# OpenTallas tools/qwen_missing/phy_plan_pins.py (plan pin sites, QC S4P): ot_qfd_serdes_112g_x12_phy_s597 hard-macro ABSTRACT (licensed PHY IP; FDI side only)
VERSION 5.7 ;
BUSBITCHARS "[]" ;
DIVIDERCHAR "/" ;
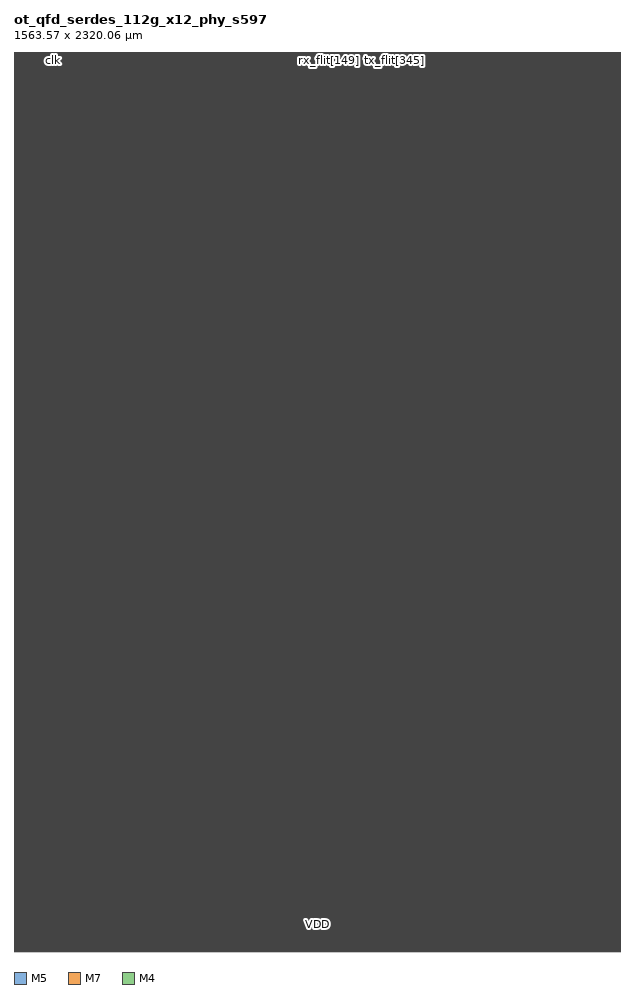
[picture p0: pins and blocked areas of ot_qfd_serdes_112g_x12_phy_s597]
MACRO ot_qfd_serdes_112g_x12_phy_s597
  FOREIGN ot_qfd_serdes_112g_x12_phy_s597 0 0 ;
  SYMMETRY X Y ;
  SIZE 1563.570 BY 2320.056 ;
  CLASS BLOCK ;
  PIN clk
    DIRECTION INPUT ;
    USE CLOCK ;
    SHAPE ABUTMENT ;
    PORT
      LAYER M5 ;
      RECT 99.996 2319.864 100.020 2320.056 ;
    END
  END clk
  PIN rst_n
    DIRECTION INPUT ;
    USE SIGNAL ;
    SHAPE ABUTMENT ;
    PORT
      LAYER M5 ;
      RECT 100.044 2319.864 100.068 2320.056 ;
    END
  END rst_n
  PIN tx_up
    DIRECTION OUTPUT ;
    USE SIGNAL ;
    SHAPE ABUTMENT ;
    PORT
      LAYER M7 ;
      RECT 1034.960 2319.864 1034.992 2320.056 ;
    END
  END tx_up
  PIN tx_v
    DIRECTION INPUT ;
    USE SIGNAL ;
    SHAPE ABUTMENT ;
    PORT
      LAYER M7 ;
      RECT 1036.304 2319.864 1036.336 2320.056 ;
    END
  END tx_v
  PIN tx_flit[0]
    DIRECTION INPUT ;
    USE SIGNAL ;
    SHAPE ABUTMENT ;
    PORT
      LAYER M7 ;
      RECT 909.200 2319.864 909.232 2320.056 ;
    END
  END tx_flit[0]
  PIN tx_flit[1]
    DIRECTION INPUT ;
    USE SIGNAL ;
    SHAPE ABUTMENT ;
    PORT
      LAYER M5 ;
      RECT 909.084 2319.864 909.108 2320.056 ;
    END
  END tx_flit[1]
  PIN tx_flit[2]
    DIRECTION INPUT ;
    USE SIGNAL ;
    SHAPE ABUTMENT ;
    PORT
      LAYER M7 ;
      RECT 909.648 2319.864 909.680 2320.056 ;
    END
  END tx_flit[2]
  PIN tx_flit[3]
    DIRECTION INPUT ;
    USE SIGNAL ;
    SHAPE ABUTMENT ;
    PORT
      LAYER M5 ;
      RECT 909.612 2319.864 909.636 2320.056 ;
    END
  END tx_flit[3]
  PIN tx_flit[4]
    DIRECTION INPUT ;
    USE SIGNAL ;
    SHAPE ABUTMENT ;
    PORT
      LAYER M7 ;
      RECT 910.032 2319.864 910.064 2320.056 ;
    END
  END tx_flit[4]
  PIN tx_flit[5]
    DIRECTION INPUT ;
    USE SIGNAL ;
    SHAPE ABUTMENT ;
    PORT
      LAYER M5 ;
      RECT 910.044 2319.864 910.068 2320.056 ;
    END
  END tx_flit[5]
  PIN tx_flit[6]
    DIRECTION INPUT ;
    USE SIGNAL ;
    SHAPE ABUTMENT ;
    PORT
      LAYER M7 ;
      RECT 910.480 2319.864 910.512 2320.056 ;
    END
  END tx_flit[6]
  PIN tx_flit[7]
    DIRECTION INPUT ;
    USE SIGNAL ;
    SHAPE ABUTMENT ;
    PORT
      LAYER M5 ;
      RECT 910.476 2319.864 910.500 2320.056 ;
    END
  END tx_flit[7]
  PIN tx_flit[8]
    DIRECTION INPUT ;
    USE SIGNAL ;
    SHAPE ABUTMENT ;
    PORT
      LAYER M7 ;
      RECT 910.864 2319.864 910.896 2320.056 ;
    END
  END tx_flit[8]
  PIN tx_flit[9]
    DIRECTION INPUT ;
    USE SIGNAL ;
    SHAPE ABUTMENT ;
    PORT
      LAYER M5 ;
      RECT 910.860 2319.864 910.884 2320.056 ;
    END
  END tx_flit[9]
  PIN tx_flit[10]
    DIRECTION INPUT ;
    USE SIGNAL ;
    SHAPE ABUTMENT ;
    PORT
      LAYER M7 ;
      RECT 910.992 2319.864 911.024 2320.056 ;
    END
  END tx_flit[10]
  PIN tx_flit[11]
    DIRECTION INPUT ;
    USE SIGNAL ;
    SHAPE ABUTMENT ;
    PORT
      LAYER M5 ;
      RECT 911.292 2319.864 911.316 2320.056 ;
    END
  END tx_flit[11]
  PIN tx_flit[12]
    DIRECTION INPUT ;
    USE SIGNAL ;
    SHAPE ABUTMENT ;
    PORT
      LAYER M7 ;
      RECT 912.016 2319.864 912.048 2320.056 ;
    END
  END tx_flit[12]
  PIN tx_flit[13]
    DIRECTION INPUT ;
    USE SIGNAL ;
    SHAPE ABUTMENT ;
    PORT
      LAYER M5 ;
      RECT 911.724 2319.864 911.748 2320.056 ;
    END
  END tx_flit[13]
  PIN tx_flit[14]
    DIRECTION INPUT ;
    USE SIGNAL ;
    SHAPE ABUTMENT ;
    PORT
      LAYER M7 ;
      RECT 912.144 2319.864 912.176 2320.056 ;
    END
  END tx_flit[14]
  PIN tx_flit[15]
    DIRECTION INPUT ;
    USE SIGNAL ;
    SHAPE ABUTMENT ;
    PORT
      LAYER M5 ;
      RECT 912.108 2319.864 912.132 2320.056 ;
    END
  END tx_flit[15]
  PIN tx_flit[16]
    DIRECTION INPUT ;
    USE SIGNAL ;
    SHAPE ABUTMENT ;
    PORT
      LAYER M7 ;
      RECT 912.528 2319.864 912.560 2320.056 ;
    END
  END tx_flit[16]
  PIN tx_flit[17]
    DIRECTION INPUT ;
    USE SIGNAL ;
    SHAPE ABUTMENT ;
    PORT
      LAYER M5 ;
      RECT 912.540 2319.864 912.564 2320.056 ;
    END
  END tx_flit[17]
  PIN tx_flit[18]
    DIRECTION INPUT ;
    USE SIGNAL ;
    SHAPE ABUTMENT ;
    PORT
      LAYER M7 ;
      RECT 912.976 2319.864 913.008 2320.056 ;
    END
  END tx_flit[18]
  PIN tx_flit[19]
    DIRECTION INPUT ;
    USE SIGNAL ;
    SHAPE ABUTMENT ;
    PORT
      LAYER M5 ;
      RECT 912.972 2319.864 912.996 2320.056 ;
    END
  END tx_flit[19]
  PIN tx_flit[20]
    DIRECTION INPUT ;
    USE SIGNAL ;
    SHAPE ABUTMENT ;
    PORT
      LAYER M7 ;
      RECT 913.360 2319.864 913.392 2320.056 ;
    END
  END tx_flit[20]
  PIN tx_flit[21]
    DIRECTION INPUT ;
    USE SIGNAL ;
    SHAPE ABUTMENT ;
    PORT
      LAYER M5 ;
      RECT 913.356 2319.864 913.380 2320.056 ;
    END
  END tx_flit[21]
  PIN tx_flit[22]
    DIRECTION INPUT ;
    USE SIGNAL ;
    SHAPE ABUTMENT ;
    PORT
      LAYER M7 ;
      RECT 913.808 2319.864 913.840 2320.056 ;
    END
  END tx_flit[22]
  PIN tx_flit[23]
    DIRECTION INPUT ;
    USE SIGNAL ;
    SHAPE ABUTMENT ;
    PORT
      LAYER M5 ;
      RECT 913.932 2319.864 913.956 2320.056 ;
    END
  END tx_flit[23]
  PIN tx_flit[24]
    DIRECTION INPUT ;
    USE SIGNAL ;
    SHAPE ABUTMENT ;
    PORT
      LAYER M7 ;
      RECT 914.192 2319.864 914.224 2320.056 ;
    END
  END tx_flit[24]
  PIN tx_flit[25]
    DIRECTION INPUT ;
    USE SIGNAL ;
    SHAPE ABUTMENT ;
    PORT
      LAYER M5 ;
      RECT 914.220 2319.864 914.244 2320.056 ;
    END
  END tx_flit[25]
  PIN tx_flit[26]
    DIRECTION INPUT ;
    USE SIGNAL ;
    SHAPE ABUTMENT ;
    PORT
      LAYER M7 ;
      RECT 914.640 2319.864 914.672 2320.056 ;
    END
  END tx_flit[26]
  PIN tx_flit[27]
    DIRECTION INPUT ;
    USE SIGNAL ;
    SHAPE ABUTMENT ;
    PORT
      LAYER M5 ;
      RECT 914.652 2319.864 914.676 2320.056 ;
    END
  END tx_flit[27]
  PIN tx_flit[28]
    DIRECTION INPUT ;
    USE SIGNAL ;
    SHAPE ABUTMENT ;
    PORT
      LAYER M7 ;
      RECT 915.024 2319.864 915.056 2320.056 ;
    END
  END tx_flit[28]
  PIN tx_flit[29]
    DIRECTION INPUT ;
    USE SIGNAL ;
    SHAPE ABUTMENT ;
    PORT
      LAYER M5 ;
      RECT 915.036 2319.864 915.060 2320.056 ;
    END
  END tx_flit[29]
  PIN tx_flit[30]
    DIRECTION INPUT ;
    USE SIGNAL ;
    SHAPE ABUTMENT ;
    PORT
      LAYER M7 ;
      RECT 915.472 2319.864 915.504 2320.056 ;
    END
  END tx_flit[30]
  PIN tx_flit[31]
    DIRECTION INPUT ;
    USE SIGNAL ;
    SHAPE ABUTMENT ;
    PORT
      LAYER M5 ;
      RECT 915.468 2319.864 915.492 2320.056 ;
    END
  END tx_flit[31]
  PIN tx_flit[32]
    DIRECTION INPUT ;
    USE SIGNAL ;
    SHAPE ABUTMENT ;
    PORT
      LAYER M7 ;
      RECT 915.856 2319.864 915.888 2320.056 ;
    END
  END tx_flit[32]
  PIN tx_flit[33]
    DIRECTION INPUT ;
    USE SIGNAL ;
    SHAPE ABUTMENT ;
    PORT
      LAYER M5 ;
      RECT 915.900 2319.864 915.924 2320.056 ;
    END
  END tx_flit[33]
  PIN tx_flit[34]
    DIRECTION INPUT ;
    USE SIGNAL ;
    SHAPE ABUTMENT ;
    PORT
      LAYER M7 ;
      RECT 916.304 2319.864 916.336 2320.056 ;
    END
  END tx_flit[34]
  PIN tx_flit[35]
    DIRECTION INPUT ;
    USE SIGNAL ;
    SHAPE ABUTMENT ;
    PORT
      LAYER M5 ;
      RECT 916.284 2319.864 916.308 2320.056 ;
    END
  END tx_flit[35]
  PIN tx_flit[36]
    DIRECTION INPUT ;
    USE SIGNAL ;
    SHAPE ABUTMENT ;
    PORT
      LAYER M7 ;
      RECT 916.688 2319.864 916.720 2320.056 ;
    END
  END tx_flit[36]
  PIN tx_flit[37]
    DIRECTION INPUT ;
    USE SIGNAL ;
    SHAPE ABUTMENT ;
    PORT
      LAYER M5 ;
      RECT 916.716 2319.864 916.740 2320.056 ;
    END
  END tx_flit[37]
  PIN tx_flit[38]
    DIRECTION INPUT ;
    USE SIGNAL ;
    SHAPE ABUTMENT ;
    PORT
      LAYER M7 ;
      RECT 917.136 2319.864 917.168 2320.056 ;
    END
  END tx_flit[38]
  PIN tx_flit[39]
    DIRECTION INPUT ;
    USE SIGNAL ;
    SHAPE ABUTMENT ;
    PORT
      LAYER M5 ;
      RECT 917.148 2319.864 917.172 2320.056 ;
    END
  END tx_flit[39]
  PIN tx_flit[40]
    DIRECTION INPUT ;
    USE SIGNAL ;
    SHAPE ABUTMENT ;
    PORT
      LAYER M7 ;
      RECT 917.520 2319.864 917.552 2320.056 ;
    END
  END tx_flit[40]
  PIN tx_flit[41]
    DIRECTION INPUT ;
    USE SIGNAL ;
    SHAPE ABUTMENT ;
    PORT
      LAYER M5 ;
      RECT 917.532 2319.864 917.556 2320.056 ;
    END
  END tx_flit[41]
  PIN tx_flit[42]
    DIRECTION INPUT ;
    USE SIGNAL ;
    SHAPE ABUTMENT ;
    PORT
      LAYER M7 ;
      RECT 917.968 2319.864 918.000 2320.056 ;
    END
  END tx_flit[42]
  PIN tx_flit[43]
    DIRECTION INPUT ;
    USE SIGNAL ;
    SHAPE ABUTMENT ;
    PORT
      LAYER M5 ;
      RECT 917.724 2319.864 917.748 2320.056 ;
    END
  END tx_flit[43]
  PIN tx_flit[44]
    DIRECTION INPUT ;
    USE SIGNAL ;
    SHAPE ABUTMENT ;
    PORT
      LAYER M7 ;
      RECT 918.352 2319.864 918.384 2320.056 ;
    END
  END tx_flit[44]
  PIN tx_flit[45]
    DIRECTION INPUT ;
    USE SIGNAL ;
    SHAPE ABUTMENT ;
    PORT
      LAYER M5 ;
      RECT 918.396 2319.864 918.420 2320.056 ;
    END
  END tx_flit[45]
  PIN tx_flit[46]
    DIRECTION INPUT ;
    USE SIGNAL ;
    SHAPE ABUTMENT ;
    PORT
      LAYER M7 ;
      RECT 918.800 2319.864 918.832 2320.056 ;
    END
  END tx_flit[46]
  PIN tx_flit[47]
    DIRECTION INPUT ;
    USE SIGNAL ;
    SHAPE ABUTMENT ;
    PORT
      LAYER M5 ;
      RECT 918.780 2319.864 918.804 2320.056 ;
    END
  END tx_flit[47]
  PIN tx_flit[48]
    DIRECTION INPUT ;
    USE SIGNAL ;
    SHAPE ABUTMENT ;
    PORT
      LAYER M7 ;
      RECT 919.248 2319.864 919.280 2320.056 ;
    END
  END tx_flit[48]
  PIN tx_flit[49]
    DIRECTION INPUT ;
    USE SIGNAL ;
    SHAPE ABUTMENT ;
    PORT
      LAYER M5 ;
      RECT 919.212 2319.864 919.236 2320.056 ;
    END
  END tx_flit[49]
  PIN tx_flit[50]
    DIRECTION INPUT ;
    USE SIGNAL ;
    SHAPE ABUTMENT ;
    PORT
      LAYER M7 ;
      RECT 919.632 2319.864 919.664 2320.056 ;
    END
  END tx_flit[50]
  PIN tx_flit[51]
    DIRECTION INPUT ;
    USE SIGNAL ;
    SHAPE ABUTMENT ;
    PORT
      LAYER M5 ;
      RECT 919.644 2319.864 919.668 2320.056 ;
    END
  END tx_flit[51]
  PIN tx_flit[52]
    DIRECTION INPUT ;
    USE SIGNAL ;
    SHAPE ABUTMENT ;
    PORT
      LAYER M7 ;
      RECT 920.656 2319.864 920.688 2320.056 ;
    END
  END tx_flit[52]
  PIN tx_flit[53]
    DIRECTION INPUT ;
    USE SIGNAL ;
    SHAPE ABUTMENT ;
    PORT
      LAYER M5 ;
      RECT 920.076 2319.864 920.100 2320.056 ;
    END
  END tx_flit[53]
  PIN tx_flit[54]
    DIRECTION INPUT ;
    USE SIGNAL ;
    SHAPE ABUTMENT ;
    PORT
      LAYER M7 ;
      RECT 920.720 2319.864 920.752 2320.056 ;
    END
  END tx_flit[54]
  PIN tx_flit[55]
    DIRECTION INPUT ;
    USE SIGNAL ;
    SHAPE ABUTMENT ;
    PORT
      LAYER M5 ;
      RECT 920.460 2319.864 920.484 2320.056 ;
    END
  END tx_flit[55]
  PIN tx_flit[56]
    DIRECTION INPUT ;
    USE SIGNAL ;
    SHAPE ABUTMENT ;
    PORT
      LAYER M7 ;
      RECT 920.912 2319.864 920.944 2320.056 ;
    END
  END tx_flit[56]
  PIN tx_flit[57]
    DIRECTION INPUT ;
    USE SIGNAL ;
    SHAPE ABUTMENT ;
    PORT
      LAYER M5 ;
      RECT 920.892 2319.864 920.916 2320.056 ;
    END
  END tx_flit[57]
  PIN tx_flit[58]
    DIRECTION INPUT ;
    USE SIGNAL ;
    SHAPE ABUTMENT ;
    PORT
      LAYER M7 ;
      RECT 921.296 2319.864 921.328 2320.056 ;
    END
  END tx_flit[58]
  PIN tx_flit[59]
    DIRECTION INPUT ;
    USE SIGNAL ;
    SHAPE ABUTMENT ;
    PORT
      LAYER M5 ;
      RECT 921.324 2319.864 921.348 2320.056 ;
    END
  END tx_flit[59]
  PIN tx_flit[60]
    DIRECTION INPUT ;
    USE SIGNAL ;
    SHAPE ABUTMENT ;
    PORT
      LAYER M7 ;
      RECT 921.744 2319.864 921.776 2320.056 ;
    END
  END tx_flit[60]
  PIN tx_flit[61]
    DIRECTION INPUT ;
    USE SIGNAL ;
    SHAPE ABUTMENT ;
    PORT
      LAYER M5 ;
      RECT 921.708 2319.864 921.732 2320.056 ;
    END
  END tx_flit[61]
  PIN tx_flit[62]
    DIRECTION INPUT ;
    USE SIGNAL ;
    SHAPE ABUTMENT ;
    PORT
      LAYER M7 ;
      RECT 922.128 2319.864 922.160 2320.056 ;
    END
  END tx_flit[62]
  PIN tx_flit[63]
    DIRECTION INPUT ;
    USE SIGNAL ;
    SHAPE ABUTMENT ;
    PORT
      LAYER M5 ;
      RECT 922.044 2319.864 922.068 2320.056 ;
    END
  END tx_flit[63]
  PIN tx_flit[64]
    DIRECTION INPUT ;
    USE SIGNAL ;
    SHAPE ABUTMENT ;
    PORT
      LAYER M7 ;
      RECT 922.576 2319.864 922.608 2320.056 ;
    END
  END tx_flit[64]
  PIN tx_flit[65]
    DIRECTION INPUT ;
    USE SIGNAL ;
    SHAPE ABUTMENT ;
    PORT
      LAYER M5 ;
      RECT 922.572 2319.864 922.596 2320.056 ;
    END
  END tx_flit[65]
  PIN tx_flit[66]
    DIRECTION INPUT ;
    USE SIGNAL ;
    SHAPE ABUTMENT ;
    PORT
      LAYER M7 ;
      RECT 922.960 2319.864 922.992 2320.056 ;
    END
  END tx_flit[66]
  PIN tx_flit[67]
    DIRECTION INPUT ;
    USE SIGNAL ;
    SHAPE ABUTMENT ;
    PORT
      LAYER M5 ;
      RECT 922.956 2319.864 922.980 2320.056 ;
    END
  END tx_flit[67]
  PIN tx_flit[68]
    DIRECTION INPUT ;
    USE SIGNAL ;
    SHAPE ABUTMENT ;
    PORT
      LAYER M7 ;
      RECT 923.408 2319.864 923.440 2320.056 ;
    END
  END tx_flit[68]
  PIN tx_flit[69]
    DIRECTION INPUT ;
    USE SIGNAL ;
    SHAPE ABUTMENT ;
    PORT
      LAYER M5 ;
      RECT 923.388 2319.864 923.412 2320.056 ;
    END
  END tx_flit[69]
  PIN tx_flit[70]
    DIRECTION INPUT ;
    USE SIGNAL ;
    SHAPE ABUTMENT ;
    PORT
      LAYER M7 ;
      RECT 923.792 2319.864 923.824 2320.056 ;
    END
  END tx_flit[70]
  PIN tx_flit[71]
    DIRECTION INPUT ;
    USE SIGNAL ;
    SHAPE ABUTMENT ;
    PORT
      LAYER M5 ;
      RECT 923.820 2319.864 923.844 2320.056 ;
    END
  END tx_flit[71]
  PIN tx_flit[72]
    DIRECTION INPUT ;
    USE SIGNAL ;
    SHAPE ABUTMENT ;
    PORT
      LAYER M7 ;
      RECT 924.240 2319.864 924.272 2320.056 ;
    END
  END tx_flit[72]
  PIN tx_flit[73]
    DIRECTION INPUT ;
    USE SIGNAL ;
    SHAPE ABUTMENT ;
    PORT
      LAYER M5 ;
      RECT 924.252 2319.864 924.276 2320.056 ;
    END
  END tx_flit[73]
  PIN tx_flit[74]
    DIRECTION INPUT ;
    USE SIGNAL ;
    SHAPE ABUTMENT ;
    PORT
      LAYER M7 ;
      RECT 924.624 2319.864 924.656 2320.056 ;
    END
  END tx_flit[74]
  PIN tx_flit[75]
    DIRECTION INPUT ;
    USE SIGNAL ;
    SHAPE ABUTMENT ;
    PORT
      LAYER M5 ;
      RECT 924.636 2319.864 924.660 2320.056 ;
    END
  END tx_flit[75]
  PIN tx_flit[76]
    DIRECTION INPUT ;
    USE SIGNAL ;
    SHAPE ABUTMENT ;
    PORT
      LAYER M7 ;
      RECT 925.072 2319.864 925.104 2320.056 ;
    END
  END tx_flit[76]
  PIN tx_flit[77]
    DIRECTION INPUT ;
    USE SIGNAL ;
    SHAPE ABUTMENT ;
    PORT
      LAYER M5 ;
      RECT 925.068 2319.864 925.092 2320.056 ;
    END
  END tx_flit[77]
  PIN tx_flit[78]
    DIRECTION INPUT ;
    USE SIGNAL ;
    SHAPE ABUTMENT ;
    PORT
      LAYER M7 ;
      RECT 925.456 2319.864 925.488 2320.056 ;
    END
  END tx_flit[78]
  PIN tx_flit[79]
    DIRECTION INPUT ;
    USE SIGNAL ;
    SHAPE ABUTMENT ;
    PORT
      LAYER M5 ;
      RECT 925.500 2319.864 925.524 2320.056 ;
    END
  END tx_flit[79]
  PIN tx_flit[80]
    DIRECTION INPUT ;
    USE SIGNAL ;
    SHAPE ABUTMENT ;
    PORT
      LAYER M7 ;
      RECT 925.904 2319.864 925.936 2320.056 ;
    END
  END tx_flit[80]
  PIN tx_flit[81]
    DIRECTION INPUT ;
    USE SIGNAL ;
    SHAPE ABUTMENT ;
    PORT
      LAYER M5 ;
      RECT 925.884 2319.864 925.908 2320.056 ;
    END
  END tx_flit[81]
  PIN tx_flit[82]
    DIRECTION INPUT ;
    USE SIGNAL ;
    SHAPE ABUTMENT ;
    PORT
      LAYER M7 ;
      RECT 926.288 2319.864 926.320 2320.056 ;
    END
  END tx_flit[82]
  PIN tx_flit[83]
    DIRECTION INPUT ;
    USE SIGNAL ;
    SHAPE ABUTMENT ;
    PORT
      LAYER M5 ;
      RECT 926.316 2319.864 926.340 2320.056 ;
    END
  END tx_flit[83]
  PIN tx_flit[84]
    DIRECTION INPUT ;
    USE SIGNAL ;
    SHAPE ABUTMENT ;
    PORT
      LAYER M7 ;
      RECT 926.736 2319.864 926.768 2320.056 ;
    END
  END tx_flit[84]
  PIN tx_flit[85]
    DIRECTION INPUT ;
    USE SIGNAL ;
    SHAPE ABUTMENT ;
    PORT
      LAYER M5 ;
      RECT 926.892 2319.864 926.916 2320.056 ;
    END
  END tx_flit[85]
  PIN tx_flit[86]
    DIRECTION INPUT ;
    USE SIGNAL ;
    SHAPE ABUTMENT ;
    PORT
      LAYER M7 ;
      RECT 927.120 2319.864 927.152 2320.056 ;
    END
  END tx_flit[86]
  PIN tx_flit[87]
    DIRECTION INPUT ;
    USE SIGNAL ;
    SHAPE ABUTMENT ;
    PORT
      LAYER M5 ;
      RECT 927.132 2319.864 927.156 2320.056 ;
    END
  END tx_flit[87]
  PIN tx_flit[88]
    DIRECTION INPUT ;
    USE SIGNAL ;
    SHAPE ABUTMENT ;
    PORT
      LAYER M7 ;
      RECT 927.568 2319.864 927.600 2320.056 ;
    END
  END tx_flit[88]
  PIN tx_flit[89]
    DIRECTION INPUT ;
    USE SIGNAL ;
    SHAPE ABUTMENT ;
    PORT
      LAYER M5 ;
      RECT 927.564 2319.864 927.588 2320.056 ;
    END
  END tx_flit[89]
  PIN tx_flit[90]
    DIRECTION INPUT ;
    USE SIGNAL ;
    SHAPE ABUTMENT ;
    PORT
      LAYER M7 ;
      RECT 927.952 2319.864 927.984 2320.056 ;
    END
  END tx_flit[90]
  PIN tx_flit[91]
    DIRECTION INPUT ;
    USE SIGNAL ;
    SHAPE ABUTMENT ;
    PORT
      LAYER M5 ;
      RECT 927.996 2319.864 928.020 2320.056 ;
    END
  END tx_flit[91]
  PIN tx_flit[92]
    DIRECTION INPUT ;
    USE SIGNAL ;
    SHAPE ABUTMENT ;
    PORT
      LAYER M7 ;
      RECT 928.272 2319.864 928.304 2320.056 ;
    END
  END tx_flit[92]
  PIN tx_flit[93]
    DIRECTION INPUT ;
    USE SIGNAL ;
    SHAPE ABUTMENT ;
    PORT
      LAYER M5 ;
      RECT 928.380 2319.864 928.404 2320.056 ;
    END
  END tx_flit[93]
  PIN tx_flit[94]
    DIRECTION INPUT ;
    USE SIGNAL ;
    SHAPE ABUTMENT ;
    PORT
      LAYER M7 ;
      RECT 929.296 2319.864 929.328 2320.056 ;
    END
  END tx_flit[94]
  PIN tx_flit[95]
    DIRECTION INPUT ;
    USE SIGNAL ;
    SHAPE ABUTMENT ;
    PORT
      LAYER M5 ;
      RECT 928.812 2319.864 928.836 2320.056 ;
    END
  END tx_flit[95]
  PIN tx_flit[96]
    DIRECTION INPUT ;
    USE SIGNAL ;
    SHAPE ABUTMENT ;
    PORT
      LAYER M7 ;
      RECT 929.360 2319.864 929.392 2320.056 ;
    END
  END tx_flit[96]
  PIN tx_flit[97]
    DIRECTION INPUT ;
    USE SIGNAL ;
    SHAPE ABUTMENT ;
    PORT
      LAYER M5 ;
      RECT 929.244 2319.864 929.268 2320.056 ;
    END
  END tx_flit[97]
  PIN tx_flit[98]
    DIRECTION INPUT ;
    USE SIGNAL ;
    SHAPE ABUTMENT ;
    PORT
      LAYER M7 ;
      RECT 929.680 2319.864 929.712 2320.056 ;
    END
  END tx_flit[98]
  PIN tx_flit[99]
    DIRECTION INPUT ;
    USE SIGNAL ;
    SHAPE ABUTMENT ;
    PORT
      LAYER M5 ;
      RECT 929.676 2319.864 929.700 2320.056 ;
    END
  END tx_flit[99]
  PIN tx_flit[100]
    DIRECTION INPUT ;
    USE SIGNAL ;
    SHAPE ABUTMENT ;
    PORT
      LAYER M7 ;
      RECT 930.064 2319.864 930.096 2320.056 ;
    END
  END tx_flit[100]
  PIN tx_flit[101]
    DIRECTION INPUT ;
    USE SIGNAL ;
    SHAPE ABUTMENT ;
    PORT
      LAYER M5 ;
      RECT 930.060 2319.864 930.084 2320.056 ;
    END
  END tx_flit[101]
  PIN tx_flit[102]
    DIRECTION INPUT ;
    USE SIGNAL ;
    SHAPE ABUTMENT ;
    PORT
      LAYER M7 ;
      RECT 930.512 2319.864 930.544 2320.056 ;
    END
  END tx_flit[102]
  PIN tx_flit[103]
    DIRECTION INPUT ;
    USE SIGNAL ;
    SHAPE ABUTMENT ;
    PORT
      LAYER M5 ;
      RECT 930.492 2319.864 930.516 2320.056 ;
    END
  END tx_flit[103]
  PIN tx_flit[104]
    DIRECTION INPUT ;
    USE SIGNAL ;
    SHAPE ABUTMENT ;
    PORT
      LAYER M7 ;
      RECT 930.896 2319.864 930.928 2320.056 ;
    END
  END tx_flit[104]
  PIN tx_flit[105]
    DIRECTION INPUT ;
    USE SIGNAL ;
    SHAPE ABUTMENT ;
    PORT
      LAYER M5 ;
      RECT 930.684 2319.864 930.708 2320.056 ;
    END
  END tx_flit[105]
  PIN tx_flit[106]
    DIRECTION INPUT ;
    USE SIGNAL ;
    SHAPE ABUTMENT ;
    PORT
      LAYER M7 ;
      RECT 931.344 2319.864 931.376 2320.056 ;
    END
  END tx_flit[106]
  PIN tx_flit[107]
    DIRECTION INPUT ;
    USE SIGNAL ;
    SHAPE ABUTMENT ;
    PORT
      LAYER M5 ;
      RECT 931.308 2319.864 931.332 2320.056 ;
    END
  END tx_flit[107]
  PIN tx_flit[108]
    DIRECTION INPUT ;
    USE SIGNAL ;
    SHAPE ABUTMENT ;
    PORT
      LAYER M7 ;
      RECT 931.728 2319.864 931.760 2320.056 ;
    END
  END tx_flit[108]
  PIN tx_flit[109]
    DIRECTION INPUT ;
    USE SIGNAL ;
    SHAPE ABUTMENT ;
    PORT
      LAYER M5 ;
      RECT 931.740 2319.864 931.764 2320.056 ;
    END
  END tx_flit[109]
  PIN tx_flit[110]
    DIRECTION INPUT ;
    USE SIGNAL ;
    SHAPE ABUTMENT ;
    PORT
      LAYER M7 ;
      RECT 932.176 2319.864 932.208 2320.056 ;
    END
  END tx_flit[110]
  PIN tx_flit[111]
    DIRECTION INPUT ;
    USE SIGNAL ;
    SHAPE ABUTMENT ;
    PORT
      LAYER M5 ;
      RECT 932.172 2319.864 932.196 2320.056 ;
    END
  END tx_flit[111]
  PIN tx_flit[112]
    DIRECTION INPUT ;
    USE SIGNAL ;
    SHAPE ABUTMENT ;
    PORT
      LAYER M7 ;
      RECT 932.560 2319.864 932.592 2320.056 ;
    END
  END tx_flit[112]
  PIN tx_flit[113]
    DIRECTION INPUT ;
    USE SIGNAL ;
    SHAPE ABUTMENT ;
    PORT
      LAYER M5 ;
      RECT 932.556 2319.864 932.580 2320.056 ;
    END
  END tx_flit[113]
  PIN tx_flit[114]
    DIRECTION INPUT ;
    USE SIGNAL ;
    SHAPE ABUTMENT ;
    PORT
      LAYER M7 ;
      RECT 933.008 2319.864 933.040 2320.056 ;
    END
  END tx_flit[114]
  PIN tx_flit[115]
    DIRECTION INPUT ;
    USE SIGNAL ;
    SHAPE ABUTMENT ;
    PORT
      LAYER M5 ;
      RECT 932.988 2319.864 933.012 2320.056 ;
    END
  END tx_flit[115]
  PIN tx_flit[116]
    DIRECTION INPUT ;
    USE SIGNAL ;
    SHAPE ABUTMENT ;
    PORT
      LAYER M7 ;
      RECT 933.392 2319.864 933.424 2320.056 ;
    END
  END tx_flit[116]
  PIN tx_flit[117]
    DIRECTION INPUT ;
    USE SIGNAL ;
    SHAPE ABUTMENT ;
    PORT
      LAYER M5 ;
      RECT 933.420 2319.864 933.444 2320.056 ;
    END
  END tx_flit[117]
  PIN tx_flit[118]
    DIRECTION INPUT ;
    USE SIGNAL ;
    SHAPE ABUTMENT ;
    PORT
      LAYER M7 ;
      RECT 933.840 2319.864 933.872 2320.056 ;
    END
  END tx_flit[118]
  PIN tx_flit[119]
    DIRECTION INPUT ;
    USE SIGNAL ;
    SHAPE ABUTMENT ;
    PORT
      LAYER M5 ;
      RECT 933.804 2319.864 933.828 2320.056 ;
    END
  END tx_flit[119]
  PIN tx_flit[120]
    DIRECTION INPUT ;
    USE SIGNAL ;
    SHAPE ABUTMENT ;
    PORT
      LAYER M7 ;
      RECT 934.224 2319.864 934.256 2320.056 ;
    END
  END tx_flit[120]
  PIN tx_flit[121]
    DIRECTION INPUT ;
    USE SIGNAL ;
    SHAPE ABUTMENT ;
    PORT
      LAYER M5 ;
      RECT 934.236 2319.864 934.260 2320.056 ;
    END
  END tx_flit[121]
  PIN tx_flit[122]
    DIRECTION INPUT ;
    USE SIGNAL ;
    SHAPE ABUTMENT ;
    PORT
      LAYER M7 ;
      RECT 934.672 2319.864 934.704 2320.056 ;
    END
  END tx_flit[122]
  PIN tx_flit[123]
    DIRECTION INPUT ;
    USE SIGNAL ;
    SHAPE ABUTMENT ;
    PORT
      LAYER M5 ;
      RECT 934.668 2319.864 934.692 2320.056 ;
    END
  END tx_flit[123]
  PIN tx_flit[124]
    DIRECTION INPUT ;
    USE SIGNAL ;
    SHAPE ABUTMENT ;
    PORT
      LAYER M7 ;
      RECT 935.056 2319.864 935.088 2320.056 ;
    END
  END tx_flit[124]
  PIN tx_flit[125]
    DIRECTION INPUT ;
    USE SIGNAL ;
    SHAPE ABUTMENT ;
    PORT
      LAYER M5 ;
      RECT 935.004 2319.864 935.028 2320.056 ;
    END
  END tx_flit[125]
  PIN tx_flit[126]
    DIRECTION INPUT ;
    USE SIGNAL ;
    SHAPE ABUTMENT ;
    PORT
      LAYER M7 ;
      RECT 935.504 2319.864 935.536 2320.056 ;
    END
  END tx_flit[126]
  PIN tx_flit[127]
    DIRECTION INPUT ;
    USE SIGNAL ;
    SHAPE ABUTMENT ;
    PORT
      LAYER M5 ;
      RECT 935.532 2319.864 935.556 2320.056 ;
    END
  END tx_flit[127]
  PIN tx_flit[128]
    DIRECTION INPUT ;
    USE SIGNAL ;
    SHAPE ABUTMENT ;
    PORT
      LAYER M7 ;
      RECT 935.888 2319.864 935.920 2320.056 ;
    END
  END tx_flit[128]
  PIN tx_flit[129]
    DIRECTION INPUT ;
    USE SIGNAL ;
    SHAPE ABUTMENT ;
    PORT
      LAYER M5 ;
      RECT 935.916 2319.864 935.940 2320.056 ;
    END
  END tx_flit[129]
  PIN tx_flit[130]
    DIRECTION INPUT ;
    USE SIGNAL ;
    SHAPE ABUTMENT ;
    PORT
      LAYER M7 ;
      RECT 936.336 2319.864 936.368 2320.056 ;
    END
  END tx_flit[130]
  PIN tx_flit[131]
    DIRECTION INPUT ;
    USE SIGNAL ;
    SHAPE ABUTMENT ;
    PORT
      LAYER M5 ;
      RECT 936.348 2319.864 936.372 2320.056 ;
    END
  END tx_flit[131]
  PIN tx_flit[132]
    DIRECTION INPUT ;
    USE SIGNAL ;
    SHAPE ABUTMENT ;
    PORT
      LAYER M7 ;
      RECT 936.720 2319.864 936.752 2320.056 ;
    END
  END tx_flit[132]
  PIN tx_flit[133]
    DIRECTION INPUT ;
    USE SIGNAL ;
    SHAPE ABUTMENT ;
    PORT
      LAYER M5 ;
      RECT 936.732 2319.864 936.756 2320.056 ;
    END
  END tx_flit[133]
  PIN tx_flit[134]
    DIRECTION INPUT ;
    USE SIGNAL ;
    SHAPE ABUTMENT ;
    PORT
      LAYER M7 ;
      RECT 936.912 2319.864 936.944 2320.056 ;
    END
  END tx_flit[134]
  PIN tx_flit[135]
    DIRECTION INPUT ;
    USE SIGNAL ;
    SHAPE ABUTMENT ;
    PORT
      LAYER M5 ;
      RECT 937.164 2319.864 937.188 2320.056 ;
    END
  END tx_flit[135]
  PIN tx_flit[136]
    DIRECTION INPUT ;
    USE SIGNAL ;
    SHAPE ABUTMENT ;
    PORT
      LAYER M7 ;
      RECT 937.936 2319.864 937.968 2320.056 ;
    END
  END tx_flit[136]
  PIN tx_flit[137]
    DIRECTION INPUT ;
    USE SIGNAL ;
    SHAPE ABUTMENT ;
    PORT
      LAYER M5 ;
      RECT 937.596 2319.864 937.620 2320.056 ;
    END
  END tx_flit[137]
  PIN tx_flit[138]
    DIRECTION INPUT ;
    USE SIGNAL ;
    SHAPE ABUTMENT ;
    PORT
      LAYER M7 ;
      RECT 938.000 2319.864 938.032 2320.056 ;
    END
  END tx_flit[138]
  PIN tx_flit[139]
    DIRECTION INPUT ;
    USE SIGNAL ;
    SHAPE ABUTMENT ;
    PORT
      LAYER M5 ;
      RECT 937.980 2319.864 938.004 2320.056 ;
    END
  END tx_flit[139]
  PIN tx_flit[140]
    DIRECTION INPUT ;
    USE SIGNAL ;
    SHAPE ABUTMENT ;
    PORT
      LAYER M7 ;
      RECT 938.384 2319.864 938.416 2320.056 ;
    END
  END tx_flit[140]
  PIN tx_flit[141]
    DIRECTION INPUT ;
    USE SIGNAL ;
    SHAPE ABUTMENT ;
    PORT
      LAYER M5 ;
      RECT 938.412 2319.864 938.436 2320.056 ;
    END
  END tx_flit[141]
  PIN tx_flit[142]
    DIRECTION INPUT ;
    USE SIGNAL ;
    SHAPE ABUTMENT ;
    PORT
      LAYER M7 ;
      RECT 938.832 2319.864 938.864 2320.056 ;
    END
  END tx_flit[142]
  PIN tx_flit[143]
    DIRECTION INPUT ;
    USE SIGNAL ;
    SHAPE ABUTMENT ;
    PORT
      LAYER M5 ;
      RECT 938.844 2319.864 938.868 2320.056 ;
    END
  END tx_flit[143]
  PIN tx_flit[144]
    DIRECTION INPUT ;
    USE SIGNAL ;
    SHAPE ABUTMENT ;
    PORT
      LAYER M7 ;
      RECT 939.280 2319.864 939.312 2320.056 ;
    END
  END tx_flit[144]
  PIN tx_flit[145]
    DIRECTION INPUT ;
    USE SIGNAL ;
    SHAPE ABUTMENT ;
    PORT
      LAYER M5 ;
      RECT 939.276 2319.864 939.300 2320.056 ;
    END
  END tx_flit[145]
  PIN tx_flit[146]
    DIRECTION INPUT ;
    USE SIGNAL ;
    SHAPE ABUTMENT ;
    PORT
      LAYER M7 ;
      RECT 939.664 2319.864 939.696 2320.056 ;
    END
  END tx_flit[146]
  PIN tx_flit[147]
    DIRECTION INPUT ;
    USE SIGNAL ;
    SHAPE ABUTMENT ;
    PORT
      LAYER M5 ;
      RECT 939.852 2319.864 939.876 2320.056 ;
    END
  END tx_flit[147]
  PIN tx_flit[148]
    DIRECTION INPUT ;
    USE SIGNAL ;
    SHAPE ABUTMENT ;
    PORT
      LAYER M7 ;
      RECT 940.112 2319.864 940.144 2320.056 ;
    END
  END tx_flit[148]
  PIN tx_flit[149]
    DIRECTION INPUT ;
    USE SIGNAL ;
    SHAPE ABUTMENT ;
    PORT
      LAYER M5 ;
      RECT 940.092 2319.864 940.116 2320.056 ;
    END
  END tx_flit[149]
  PIN tx_flit[150]
    DIRECTION INPUT ;
    USE SIGNAL ;
    SHAPE ABUTMENT ;
    PORT
      LAYER M7 ;
      RECT 940.496 2319.864 940.528 2320.056 ;
    END
  END tx_flit[150]
  PIN tx_flit[151]
    DIRECTION INPUT ;
    USE SIGNAL ;
    SHAPE ABUTMENT ;
    PORT
      LAYER M5 ;
      RECT 940.524 2319.864 940.548 2320.056 ;
    END
  END tx_flit[151]
  PIN tx_flit[152]
    DIRECTION INPUT ;
    USE SIGNAL ;
    SHAPE ABUTMENT ;
    PORT
      LAYER M7 ;
      RECT 940.944 2319.864 940.976 2320.056 ;
    END
  END tx_flit[152]
  PIN tx_flit[153]
    DIRECTION INPUT ;
    USE SIGNAL ;
    SHAPE ABUTMENT ;
    PORT
      LAYER M5 ;
      RECT 940.908 2319.864 940.932 2320.056 ;
    END
  END tx_flit[153]
  PIN tx_flit[154]
    DIRECTION INPUT ;
    USE SIGNAL ;
    SHAPE ABUTMENT ;
    PORT
      LAYER M7 ;
      RECT 941.328 2319.864 941.360 2320.056 ;
    END
  END tx_flit[154]
  PIN tx_flit[155]
    DIRECTION INPUT ;
    USE SIGNAL ;
    SHAPE ABUTMENT ;
    PORT
      LAYER M5 ;
      RECT 941.340 2319.864 941.364 2320.056 ;
    END
  END tx_flit[155]
  PIN tx_flit[156]
    DIRECTION INPUT ;
    USE SIGNAL ;
    SHAPE ABUTMENT ;
    PORT
      LAYER M7 ;
      RECT 941.776 2319.864 941.808 2320.056 ;
    END
  END tx_flit[156]
  PIN tx_flit[157]
    DIRECTION INPUT ;
    USE SIGNAL ;
    SHAPE ABUTMENT ;
    PORT
      LAYER M5 ;
      RECT 941.772 2319.864 941.796 2320.056 ;
    END
  END tx_flit[157]
  PIN tx_flit[158]
    DIRECTION INPUT ;
    USE SIGNAL ;
    SHAPE ABUTMENT ;
    PORT
      LAYER M7 ;
      RECT 942.160 2319.864 942.192 2320.056 ;
    END
  END tx_flit[158]
  PIN tx_flit[159]
    DIRECTION INPUT ;
    USE SIGNAL ;
    SHAPE ABUTMENT ;
    PORT
      LAYER M5 ;
      RECT 942.156 2319.864 942.180 2320.056 ;
    END
  END tx_flit[159]
  PIN tx_flit[160]
    DIRECTION INPUT ;
    USE SIGNAL ;
    SHAPE ABUTMENT ;
    PORT
      LAYER M7 ;
      RECT 942.608 2319.864 942.640 2320.056 ;
    END
  END tx_flit[160]
  PIN tx_flit[161]
    DIRECTION INPUT ;
    USE SIGNAL ;
    SHAPE ABUTMENT ;
    PORT
      LAYER M5 ;
      RECT 942.588 2319.864 942.612 2320.056 ;
    END
  END tx_flit[161]
  PIN tx_flit[162]
    DIRECTION INPUT ;
    USE SIGNAL ;
    SHAPE ABUTMENT ;
    PORT
      LAYER M7 ;
      RECT 942.992 2319.864 943.024 2320.056 ;
    END
  END tx_flit[162]
  PIN tx_flit[163]
    DIRECTION INPUT ;
    USE SIGNAL ;
    SHAPE ABUTMENT ;
    PORT
      LAYER M5 ;
      RECT 943.020 2319.864 943.044 2320.056 ;
    END
  END tx_flit[163]
  PIN tx_flit[164]
    DIRECTION INPUT ;
    USE SIGNAL ;
    SHAPE ABUTMENT ;
    PORT
      LAYER M7 ;
      RECT 943.440 2319.864 943.472 2320.056 ;
    END
  END tx_flit[164]
  PIN tx_flit[165]
    DIRECTION INPUT ;
    USE SIGNAL ;
    SHAPE ABUTMENT ;
    PORT
      LAYER M5 ;
      RECT 943.404 2319.864 943.428 2320.056 ;
    END
  END tx_flit[165]
  PIN tx_flit[166]
    DIRECTION INPUT ;
    USE SIGNAL ;
    SHAPE ABUTMENT ;
    PORT
      LAYER M7 ;
      RECT 943.824 2319.864 943.856 2320.056 ;
    END
  END tx_flit[166]
  PIN tx_flit[167]
    DIRECTION INPUT ;
    USE SIGNAL ;
    SHAPE ABUTMENT ;
    PORT
      LAYER M5 ;
      RECT 943.644 2319.864 943.668 2320.056 ;
    END
  END tx_flit[167]
  PIN tx_flit[168]
    DIRECTION INPUT ;
    USE SIGNAL ;
    SHAPE ABUTMENT ;
    PORT
      LAYER M7 ;
      RECT 944.272 2319.864 944.304 2320.056 ;
    END
  END tx_flit[168]
  PIN tx_flit[169]
    DIRECTION INPUT ;
    USE SIGNAL ;
    SHAPE ABUTMENT ;
    PORT
      LAYER M5 ;
      RECT 944.268 2319.864 944.292 2320.056 ;
    END
  END tx_flit[169]
  PIN tx_flit[170]
    DIRECTION INPUT ;
    USE SIGNAL ;
    SHAPE ABUTMENT ;
    PORT
      LAYER M7 ;
      RECT 944.656 2319.864 944.688 2320.056 ;
    END
  END tx_flit[170]
  PIN tx_flit[171]
    DIRECTION INPUT ;
    USE SIGNAL ;
    SHAPE ABUTMENT ;
    PORT
      LAYER M5 ;
      RECT 944.700 2319.864 944.724 2320.056 ;
    END
  END tx_flit[171]
  PIN tx_flit[172]
    DIRECTION INPUT ;
    USE SIGNAL ;
    SHAPE ABUTMENT ;
    PORT
      LAYER M7 ;
      RECT 945.104 2319.864 945.136 2320.056 ;
    END
  END tx_flit[172]
  PIN tx_flit[173]
    DIRECTION INPUT ;
    USE SIGNAL ;
    SHAPE ABUTMENT ;
    PORT
      LAYER M5 ;
      RECT 945.084 2319.864 945.108 2320.056 ;
    END
  END tx_flit[173]
  PIN tx_flit[174]
    DIRECTION INPUT ;
    USE SIGNAL ;
    SHAPE ABUTMENT ;
    PORT
      LAYER M7 ;
      RECT 945.488 2319.864 945.520 2320.056 ;
    END
  END tx_flit[174]
  PIN tx_flit[175]
    DIRECTION INPUT ;
    USE SIGNAL ;
    SHAPE ABUTMENT ;
    PORT
      LAYER M5 ;
      RECT 945.516 2319.864 945.540 2320.056 ;
    END
  END tx_flit[175]
  PIN tx_flit[176]
    DIRECTION INPUT ;
    USE SIGNAL ;
    SHAPE ABUTMENT ;
    PORT
      LAYER M7 ;
      RECT 945.552 2319.864 945.584 2320.056 ;
    END
  END tx_flit[176]
  PIN tx_flit[177]
    DIRECTION INPUT ;
    USE SIGNAL ;
    SHAPE ABUTMENT ;
    PORT
      LAYER M5 ;
      RECT 945.948 2319.864 945.972 2320.056 ;
    END
  END tx_flit[177]
  PIN tx_flit[178]
    DIRECTION INPUT ;
    USE SIGNAL ;
    SHAPE ABUTMENT ;
    PORT
      LAYER M7 ;
      RECT 946.576 2319.864 946.608 2320.056 ;
    END
  END tx_flit[178]
  PIN tx_flit[179]
    DIRECTION INPUT ;
    USE SIGNAL ;
    SHAPE ABUTMENT ;
    PORT
      LAYER M5 ;
      RECT 946.332 2319.864 946.356 2320.056 ;
    END
  END tx_flit[179]
  PIN tx_flit[180]
    DIRECTION INPUT ;
    USE SIGNAL ;
    SHAPE ABUTMENT ;
    PORT
      LAYER M7 ;
      RECT 946.768 2319.864 946.800 2320.056 ;
    END
  END tx_flit[180]
  PIN tx_flit[181]
    DIRECTION INPUT ;
    USE SIGNAL ;
    SHAPE ABUTMENT ;
    PORT
      LAYER M5 ;
      RECT 946.764 2319.864 946.788 2320.056 ;
    END
  END tx_flit[181]
  PIN tx_flit[182]
    DIRECTION INPUT ;
    USE SIGNAL ;
    SHAPE ABUTMENT ;
    PORT
      LAYER M7 ;
      RECT 947.152 2319.864 947.184 2320.056 ;
    END
  END tx_flit[182]
  PIN tx_flit[183]
    DIRECTION INPUT ;
    USE SIGNAL ;
    SHAPE ABUTMENT ;
    PORT
      LAYER M5 ;
      RECT 947.196 2319.864 947.220 2320.056 ;
    END
  END tx_flit[183]
  PIN tx_flit[184]
    DIRECTION INPUT ;
    USE SIGNAL ;
    SHAPE ABUTMENT ;
    PORT
      LAYER M7 ;
      RECT 947.600 2319.864 947.632 2320.056 ;
    END
  END tx_flit[184]
  PIN tx_flit[185]
    DIRECTION INPUT ;
    USE SIGNAL ;
    SHAPE ABUTMENT ;
    PORT
      LAYER M5 ;
      RECT 947.580 2319.864 947.604 2320.056 ;
    END
  END tx_flit[185]
  PIN tx_flit[186]
    DIRECTION INPUT ;
    USE SIGNAL ;
    SHAPE ABUTMENT ;
    PORT
      LAYER M7 ;
      RECT 947.984 2319.864 948.016 2320.056 ;
    END
  END tx_flit[186]
  PIN tx_flit[187]
    DIRECTION INPUT ;
    USE SIGNAL ;
    SHAPE ABUTMENT ;
    PORT
      LAYER M5 ;
      RECT 947.964 2319.864 947.988 2320.056 ;
    END
  END tx_flit[187]
  PIN tx_flit[188]
    DIRECTION INPUT ;
    USE SIGNAL ;
    SHAPE ABUTMENT ;
    PORT
      LAYER M7 ;
      RECT 948.432 2319.864 948.464 2320.056 ;
    END
  END tx_flit[188]
  PIN tx_flit[189]
    DIRECTION INPUT ;
    USE SIGNAL ;
    SHAPE ABUTMENT ;
    PORT
      LAYER M5 ;
      RECT 948.492 2319.864 948.516 2320.056 ;
    END
  END tx_flit[189]
  PIN tx_flit[190]
    DIRECTION INPUT ;
    USE SIGNAL ;
    SHAPE ABUTMENT ;
    PORT
      LAYER M7 ;
      RECT 948.816 2319.864 948.848 2320.056 ;
    END
  END tx_flit[190]
  PIN tx_flit[191]
    DIRECTION INPUT ;
    USE SIGNAL ;
    SHAPE ABUTMENT ;
    PORT
      LAYER M5 ;
      RECT 948.828 2319.864 948.852 2320.056 ;
    END
  END tx_flit[191]
  PIN tx_flit[192]
    DIRECTION INPUT ;
    USE SIGNAL ;
    SHAPE ABUTMENT ;
    PORT
      LAYER M7 ;
      RECT 949.264 2319.864 949.296 2320.056 ;
    END
  END tx_flit[192]
  PIN tx_flit[193]
    DIRECTION INPUT ;
    USE SIGNAL ;
    SHAPE ABUTMENT ;
    PORT
      LAYER M5 ;
      RECT 949.260 2319.864 949.284 2320.056 ;
    END
  END tx_flit[193]
  PIN tx_flit[194]
    DIRECTION INPUT ;
    USE SIGNAL ;
    SHAPE ABUTMENT ;
    PORT
      LAYER M7 ;
      RECT 949.712 2319.864 949.744 2320.056 ;
    END
  END tx_flit[194]
  PIN tx_flit[195]
    DIRECTION INPUT ;
    USE SIGNAL ;
    SHAPE ABUTMENT ;
    PORT
      LAYER M5 ;
      RECT 949.692 2319.864 949.716 2320.056 ;
    END
  END tx_flit[195]
  PIN tx_flit[196]
    DIRECTION INPUT ;
    USE SIGNAL ;
    SHAPE ABUTMENT ;
    PORT
      LAYER M7 ;
      RECT 950.096 2319.864 950.128 2320.056 ;
    END
  END tx_flit[196]
  PIN tx_flit[197]
    DIRECTION INPUT ;
    USE SIGNAL ;
    SHAPE ABUTMENT ;
    PORT
      LAYER M5 ;
      RECT 950.124 2319.864 950.148 2320.056 ;
    END
  END tx_flit[197]
  PIN tx_flit[198]
    DIRECTION INPUT ;
    USE SIGNAL ;
    SHAPE ABUTMENT ;
    PORT
      LAYER M7 ;
      RECT 950.544 2319.864 950.576 2320.056 ;
    END
  END tx_flit[198]
  PIN tx_flit[199]
    DIRECTION INPUT ;
    USE SIGNAL ;
    SHAPE ABUTMENT ;
    PORT
      LAYER M5 ;
      RECT 950.508 2319.864 950.532 2320.056 ;
    END
  END tx_flit[199]
  PIN tx_flit[200]
    DIRECTION INPUT ;
    USE SIGNAL ;
    SHAPE ABUTMENT ;
    PORT
      LAYER M7 ;
      RECT 950.928 2319.864 950.960 2320.056 ;
    END
  END tx_flit[200]
  PIN tx_flit[201]
    DIRECTION INPUT ;
    USE SIGNAL ;
    SHAPE ABUTMENT ;
    PORT
      LAYER M5 ;
      RECT 950.940 2319.864 950.964 2320.056 ;
    END
  END tx_flit[201]
  PIN tx_flit[202]
    DIRECTION INPUT ;
    USE SIGNAL ;
    SHAPE ABUTMENT ;
    PORT
      LAYER M7 ;
      RECT 951.376 2319.864 951.408 2320.056 ;
    END
  END tx_flit[202]
  PIN tx_flit[203]
    DIRECTION INPUT ;
    USE SIGNAL ;
    SHAPE ABUTMENT ;
    PORT
      LAYER M5 ;
      RECT 951.372 2319.864 951.396 2320.056 ;
    END
  END tx_flit[203]
  PIN tx_flit[204]
    DIRECTION INPUT ;
    USE SIGNAL ;
    SHAPE ABUTMENT ;
    PORT
      LAYER M7 ;
      RECT 951.760 2319.864 951.792 2320.056 ;
    END
  END tx_flit[204]
  PIN tx_flit[205]
    DIRECTION INPUT ;
    USE SIGNAL ;
    SHAPE ABUTMENT ;
    PORT
      LAYER M5 ;
      RECT 951.756 2319.864 951.780 2320.056 ;
    END
  END tx_flit[205]
  PIN tx_flit[206]
    DIRECTION INPUT ;
    USE SIGNAL ;
    SHAPE ABUTMENT ;
    PORT
      LAYER M7 ;
      RECT 952.208 2319.864 952.240 2320.056 ;
    END
  END tx_flit[206]
  PIN tx_flit[207]
    DIRECTION INPUT ;
    USE SIGNAL ;
    SHAPE ABUTMENT ;
    PORT
      LAYER M5 ;
      RECT 952.188 2319.864 952.212 2320.056 ;
    END
  END tx_flit[207]
  PIN tx_flit[208]
    DIRECTION INPUT ;
    USE SIGNAL ;
    SHAPE ABUTMENT ;
    PORT
      LAYER M7 ;
      RECT 952.592 2319.864 952.624 2320.056 ;
    END
  END tx_flit[208]
  PIN tx_flit[209]
    DIRECTION INPUT ;
    USE SIGNAL ;
    SHAPE ABUTMENT ;
    PORT
      LAYER M5 ;
      RECT 952.812 2319.864 952.836 2320.056 ;
    END
  END tx_flit[209]
  PIN tx_flit[210]
    DIRECTION INPUT ;
    USE SIGNAL ;
    SHAPE ABUTMENT ;
    PORT
      LAYER M7 ;
      RECT 953.040 2319.864 953.072 2320.056 ;
    END
  END tx_flit[210]
  PIN tx_flit[211]
    DIRECTION INPUT ;
    USE SIGNAL ;
    SHAPE ABUTMENT ;
    PORT
      LAYER M5 ;
      RECT 953.004 2319.864 953.028 2320.056 ;
    END
  END tx_flit[211]
  PIN tx_flit[212]
    DIRECTION INPUT ;
    USE SIGNAL ;
    SHAPE ABUTMENT ;
    PORT
      LAYER M7 ;
      RECT 953.424 2319.864 953.456 2320.056 ;
    END
  END tx_flit[212]
  PIN tx_flit[213]
    DIRECTION INPUT ;
    USE SIGNAL ;
    SHAPE ABUTMENT ;
    PORT
      LAYER M5 ;
      RECT 953.436 2319.864 953.460 2320.056 ;
    END
  END tx_flit[213]
  PIN tx_flit[214]
    DIRECTION INPUT ;
    USE SIGNAL ;
    SHAPE ABUTMENT ;
    PORT
      LAYER M7 ;
      RECT 953.872 2319.864 953.904 2320.056 ;
    END
  END tx_flit[214]
  PIN tx_flit[215]
    DIRECTION INPUT ;
    USE SIGNAL ;
    SHAPE ABUTMENT ;
    PORT
      LAYER M5 ;
      RECT 953.868 2319.864 953.892 2320.056 ;
    END
  END tx_flit[215]
  PIN tx_flit[216]
    DIRECTION INPUT ;
    USE SIGNAL ;
    SHAPE ABUTMENT ;
    PORT
      LAYER M7 ;
      RECT 954.192 2319.864 954.224 2320.056 ;
    END
  END tx_flit[216]
  PIN tx_flit[217]
    DIRECTION INPUT ;
    USE SIGNAL ;
    SHAPE ABUTMENT ;
    PORT
      LAYER M5 ;
      RECT 954.300 2319.864 954.324 2320.056 ;
    END
  END tx_flit[217]
  PIN tx_flit[218]
    DIRECTION INPUT ;
    USE SIGNAL ;
    SHAPE ABUTMENT ;
    PORT
      LAYER M7 ;
      RECT 955.216 2319.864 955.248 2320.056 ;
    END
  END tx_flit[218]
  PIN tx_flit[219]
    DIRECTION INPUT ;
    USE SIGNAL ;
    SHAPE ABUTMENT ;
    PORT
      LAYER M5 ;
      RECT 954.684 2319.864 954.708 2320.056 ;
    END
  END tx_flit[219]
  PIN tx_flit[220]
    DIRECTION INPUT ;
    USE SIGNAL ;
    SHAPE ABUTMENT ;
    PORT
      LAYER M7 ;
      RECT 955.280 2319.864 955.312 2320.056 ;
    END
  END tx_flit[220]
  PIN tx_flit[221]
    DIRECTION INPUT ;
    USE SIGNAL ;
    SHAPE ABUTMENT ;
    PORT
      LAYER M5 ;
      RECT 955.116 2319.864 955.140 2320.056 ;
    END
  END tx_flit[221]
  PIN tx_flit[222]
    DIRECTION INPUT ;
    USE SIGNAL ;
    SHAPE ABUTMENT ;
    PORT
      LAYER M7 ;
      RECT 955.536 2319.864 955.568 2320.056 ;
    END
  END tx_flit[222]
  PIN tx_flit[223]
    DIRECTION INPUT ;
    USE SIGNAL ;
    SHAPE ABUTMENT ;
    PORT
      LAYER M5 ;
      RECT 955.548 2319.864 955.572 2320.056 ;
    END
  END tx_flit[223]
  PIN tx_flit[224]
    DIRECTION INPUT ;
    USE SIGNAL ;
    SHAPE ABUTMENT ;
    PORT
      LAYER M7 ;
      RECT 955.920 2319.864 955.952 2320.056 ;
    END
  END tx_flit[224]
  PIN tx_flit[225]
    DIRECTION INPUT ;
    USE SIGNAL ;
    SHAPE ABUTMENT ;
    PORT
      LAYER M5 ;
      RECT 955.932 2319.864 955.956 2320.056 ;
    END
  END tx_flit[225]
  PIN tx_flit[226]
    DIRECTION INPUT ;
    USE SIGNAL ;
    SHAPE ABUTMENT ;
    PORT
      LAYER M7 ;
      RECT 956.368 2319.864 956.400 2320.056 ;
    END
  END tx_flit[226]
  PIN tx_flit[227]
    DIRECTION INPUT ;
    USE SIGNAL ;
    SHAPE ABUTMENT ;
    PORT
      LAYER M5 ;
      RECT 956.364 2319.864 956.388 2320.056 ;
    END
  END tx_flit[227]
  PIN tx_flit[228]
    DIRECTION INPUT ;
    USE SIGNAL ;
    SHAPE ABUTMENT ;
    PORT
      LAYER M7 ;
      RECT 956.752 2319.864 956.784 2320.056 ;
    END
  END tx_flit[228]
  PIN tx_flit[229]
    DIRECTION INPUT ;
    USE SIGNAL ;
    SHAPE ABUTMENT ;
    PORT
      LAYER M5 ;
      RECT 956.604 2319.864 956.628 2320.056 ;
    END
  END tx_flit[229]
  PIN tx_flit[230]
    DIRECTION INPUT ;
    USE SIGNAL ;
    SHAPE ABUTMENT ;
    PORT
      LAYER M7 ;
      RECT 957.200 2319.864 957.232 2320.056 ;
    END
  END tx_flit[230]
  PIN tx_flit[231]
    DIRECTION INPUT ;
    USE SIGNAL ;
    SHAPE ABUTMENT ;
    PORT
      LAYER M5 ;
      RECT 957.180 2319.864 957.204 2320.056 ;
    END
  END tx_flit[231]
  PIN tx_flit[232]
    DIRECTION INPUT ;
    USE SIGNAL ;
    SHAPE ABUTMENT ;
    PORT
      LAYER M7 ;
      RECT 957.584 2319.864 957.616 2320.056 ;
    END
  END tx_flit[232]
  PIN tx_flit[233]
    DIRECTION INPUT ;
    USE SIGNAL ;
    SHAPE ABUTMENT ;
    PORT
      LAYER M5 ;
      RECT 957.612 2319.864 957.636 2320.056 ;
    END
  END tx_flit[233]
  PIN tx_flit[234]
    DIRECTION INPUT ;
    USE SIGNAL ;
    SHAPE ABUTMENT ;
    PORT
      LAYER M7 ;
      RECT 958.032 2319.864 958.064 2320.056 ;
    END
  END tx_flit[234]
  PIN tx_flit[235]
    DIRECTION INPUT ;
    USE SIGNAL ;
    SHAPE ABUTMENT ;
    PORT
      LAYER M5 ;
      RECT 958.044 2319.864 958.068 2320.056 ;
    END
  END tx_flit[235]
  PIN tx_flit[236]
    DIRECTION INPUT ;
    USE SIGNAL ;
    SHAPE ABUTMENT ;
    PORT
      LAYER M7 ;
      RECT 958.416 2319.864 958.448 2320.056 ;
    END
  END tx_flit[236]
  PIN tx_flit[237]
    DIRECTION INPUT ;
    USE SIGNAL ;
    SHAPE ABUTMENT ;
    PORT
      LAYER M5 ;
      RECT 958.428 2319.864 958.452 2320.056 ;
    END
  END tx_flit[237]
  PIN tx_flit[238]
    DIRECTION INPUT ;
    USE SIGNAL ;
    SHAPE ABUTMENT ;
    PORT
      LAYER M7 ;
      RECT 958.864 2319.864 958.896 2320.056 ;
    END
  END tx_flit[238]
  PIN tx_flit[239]
    DIRECTION INPUT ;
    USE SIGNAL ;
    SHAPE ABUTMENT ;
    PORT
      LAYER M5 ;
      RECT 958.860 2319.864 958.884 2320.056 ;
    END
  END tx_flit[239]
  PIN tx_flit[240]
    DIRECTION INPUT ;
    USE SIGNAL ;
    SHAPE ABUTMENT ;
    PORT
      LAYER M7 ;
      RECT 959.312 2319.864 959.344 2320.056 ;
    END
  END tx_flit[240]
  PIN tx_flit[241]
    DIRECTION INPUT ;
    USE SIGNAL ;
    SHAPE ABUTMENT ;
    PORT
      LAYER M5 ;
      RECT 959.292 2319.864 959.316 2320.056 ;
    END
  END tx_flit[241]
  PIN tx_flit[242]
    DIRECTION INPUT ;
    USE SIGNAL ;
    SHAPE ABUTMENT ;
    PORT
      LAYER M7 ;
      RECT 959.696 2319.864 959.728 2320.056 ;
    END
  END tx_flit[242]
  PIN tx_flit[243]
    DIRECTION INPUT ;
    USE SIGNAL ;
    SHAPE ABUTMENT ;
    PORT
      LAYER M5 ;
      RECT 959.724 2319.864 959.748 2320.056 ;
    END
  END tx_flit[243]
  PIN tx_flit[244]
    DIRECTION INPUT ;
    USE SIGNAL ;
    SHAPE ABUTMENT ;
    PORT
      LAYER M7 ;
      RECT 960.144 2319.864 960.176 2320.056 ;
    END
  END tx_flit[244]
  PIN tx_flit[245]
    DIRECTION INPUT ;
    USE SIGNAL ;
    SHAPE ABUTMENT ;
    PORT
      LAYER M5 ;
      RECT 960.108 2319.864 960.132 2320.056 ;
    END
  END tx_flit[245]
  PIN tx_flit[246]
    DIRECTION INPUT ;
    USE SIGNAL ;
    SHAPE ABUTMENT ;
    PORT
      LAYER M7 ;
      RECT 960.528 2319.864 960.560 2320.056 ;
    END
  END tx_flit[246]
  PIN tx_flit[247]
    DIRECTION INPUT ;
    USE SIGNAL ;
    SHAPE ABUTMENT ;
    PORT
      LAYER M5 ;
      RECT 960.540 2319.864 960.564 2320.056 ;
    END
  END tx_flit[247]
  PIN tx_flit[248]
    DIRECTION INPUT ;
    USE SIGNAL ;
    SHAPE ABUTMENT ;
    PORT
      LAYER M7 ;
      RECT 960.976 2319.864 961.008 2320.056 ;
    END
  END tx_flit[248]
  PIN tx_flit[249]
    DIRECTION INPUT ;
    USE SIGNAL ;
    SHAPE ABUTMENT ;
    PORT
      LAYER M5 ;
      RECT 960.924 2319.864 960.948 2320.056 ;
    END
  END tx_flit[249]
  PIN tx_flit[250]
    DIRECTION INPUT ;
    USE SIGNAL ;
    SHAPE ABUTMENT ;
    PORT
      LAYER M7 ;
      RECT 961.360 2319.864 961.392 2320.056 ;
    END
  END tx_flit[250]
  PIN tx_flit[251]
    DIRECTION INPUT ;
    USE SIGNAL ;
    SHAPE ABUTMENT ;
    PORT
      LAYER M5 ;
      RECT 961.452 2319.864 961.476 2320.056 ;
    END
  END tx_flit[251]
  PIN tx_flit[252]
    DIRECTION INPUT ;
    USE SIGNAL ;
    SHAPE ABUTMENT ;
    PORT
      LAYER M7 ;
      RECT 961.808 2319.864 961.840 2320.056 ;
    END
  END tx_flit[252]
  PIN tx_flit[253]
    DIRECTION INPUT ;
    USE SIGNAL ;
    SHAPE ABUTMENT ;
    PORT
      LAYER M5 ;
      RECT 961.788 2319.864 961.812 2320.056 ;
    END
  END tx_flit[253]
  PIN tx_flit[254]
    DIRECTION INPUT ;
    USE SIGNAL ;
    SHAPE ABUTMENT ;
    PORT
      LAYER M7 ;
      RECT 962.192 2319.864 962.224 2320.056 ;
    END
  END tx_flit[254]
  PIN tx_flit[255]
    DIRECTION INPUT ;
    USE SIGNAL ;
    SHAPE ABUTMENT ;
    PORT
      LAYER M5 ;
      RECT 962.220 2319.864 962.244 2320.056 ;
    END
  END tx_flit[255]
  PIN tx_flit[256]
    DIRECTION INPUT ;
    USE SIGNAL ;
    SHAPE ABUTMENT ;
    PORT
      LAYER M7 ;
      RECT 962.640 2319.864 962.672 2320.056 ;
    END
  END tx_flit[256]
  PIN tx_flit[257]
    DIRECTION INPUT ;
    USE SIGNAL ;
    SHAPE ABUTMENT ;
    PORT
      LAYER M5 ;
      RECT 962.604 2319.864 962.628 2320.056 ;
    END
  END tx_flit[257]
  PIN tx_flit[258]
    DIRECTION INPUT ;
    USE SIGNAL ;
    SHAPE ABUTMENT ;
    PORT
      LAYER M7 ;
      RECT 962.832 2319.864 962.864 2320.056 ;
    END
  END tx_flit[258]
  PIN tx_flit[259]
    DIRECTION INPUT ;
    USE SIGNAL ;
    SHAPE ABUTMENT ;
    PORT
      LAYER M5 ;
      RECT 963.036 2319.864 963.060 2320.056 ;
    END
  END tx_flit[259]
  PIN tx_flit[260]
    DIRECTION INPUT ;
    USE SIGNAL ;
    SHAPE ABUTMENT ;
    PORT
      LAYER M7 ;
      RECT 963.856 2319.864 963.888 2320.056 ;
    END
  END tx_flit[260]
  PIN tx_flit[261]
    DIRECTION INPUT ;
    USE SIGNAL ;
    SHAPE ABUTMENT ;
    PORT
      LAYER M5 ;
      RECT 963.468 2319.864 963.492 2320.056 ;
    END
  END tx_flit[261]
  PIN tx_flit[262]
    DIRECTION INPUT ;
    USE SIGNAL ;
    SHAPE ABUTMENT ;
    PORT
      LAYER M7 ;
      RECT 963.920 2319.864 963.952 2320.056 ;
    END
  END tx_flit[262]
  PIN tx_flit[263]
    DIRECTION INPUT ;
    USE SIGNAL ;
    SHAPE ABUTMENT ;
    PORT
      LAYER M5 ;
      RECT 963.852 2319.864 963.876 2320.056 ;
    END
  END tx_flit[263]
  PIN tx_flit[264]
    DIRECTION INPUT ;
    USE SIGNAL ;
    SHAPE ABUTMENT ;
    PORT
      LAYER M7 ;
      RECT 964.304 2319.864 964.336 2320.056 ;
    END
  END tx_flit[264]
  PIN tx_flit[265]
    DIRECTION INPUT ;
    USE SIGNAL ;
    SHAPE ABUTMENT ;
    PORT
      LAYER M5 ;
      RECT 964.284 2319.864 964.308 2320.056 ;
    END
  END tx_flit[265]
  PIN tx_flit[266]
    DIRECTION INPUT ;
    USE SIGNAL ;
    SHAPE ABUTMENT ;
    PORT
      LAYER M7 ;
      RECT 964.688 2319.864 964.720 2320.056 ;
    END
  END tx_flit[266]
  PIN tx_flit[267]
    DIRECTION INPUT ;
    USE SIGNAL ;
    SHAPE ABUTMENT ;
    PORT
      LAYER M5 ;
      RECT 964.716 2319.864 964.740 2320.056 ;
    END
  END tx_flit[267]
  PIN tx_flit[268]
    DIRECTION INPUT ;
    USE SIGNAL ;
    SHAPE ABUTMENT ;
    PORT
      LAYER M7 ;
      RECT 965.136 2319.864 965.168 2320.056 ;
    END
  END tx_flit[268]
  PIN tx_flit[269]
    DIRECTION INPUT ;
    USE SIGNAL ;
    SHAPE ABUTMENT ;
    PORT
      LAYER M5 ;
      RECT 965.148 2319.864 965.172 2320.056 ;
    END
  END tx_flit[269]
  PIN tx_flit[270]
    DIRECTION INPUT ;
    USE SIGNAL ;
    SHAPE ABUTMENT ;
    PORT
      LAYER M7 ;
      RECT 965.520 2319.864 965.552 2320.056 ;
    END
  END tx_flit[270]
  PIN tx_flit[271]
    DIRECTION INPUT ;
    USE SIGNAL ;
    SHAPE ABUTMENT ;
    PORT
      LAYER M5 ;
      RECT 965.772 2319.864 965.796 2320.056 ;
    END
  END tx_flit[271]
  PIN tx_flit[272]
    DIRECTION INPUT ;
    USE SIGNAL ;
    SHAPE ABUTMENT ;
    PORT
      LAYER M7 ;
      RECT 965.968 2319.864 966.000 2320.056 ;
    END
  END tx_flit[272]
  PIN tx_flit[273]
    DIRECTION INPUT ;
    USE SIGNAL ;
    SHAPE ABUTMENT ;
    PORT
      LAYER M5 ;
      RECT 965.964 2319.864 965.988 2320.056 ;
    END
  END tx_flit[273]
  PIN tx_flit[274]
    DIRECTION INPUT ;
    USE SIGNAL ;
    SHAPE ABUTMENT ;
    PORT
      LAYER M7 ;
      RECT 966.352 2319.864 966.384 2320.056 ;
    END
  END tx_flit[274]
  PIN tx_flit[275]
    DIRECTION INPUT ;
    USE SIGNAL ;
    SHAPE ABUTMENT ;
    PORT
      LAYER M5 ;
      RECT 966.396 2319.864 966.420 2320.056 ;
    END
  END tx_flit[275]
  PIN tx_flit[276]
    DIRECTION INPUT ;
    USE SIGNAL ;
    SHAPE ABUTMENT ;
    PORT
      LAYER M7 ;
      RECT 966.800 2319.864 966.832 2320.056 ;
    END
  END tx_flit[276]
  PIN tx_flit[277]
    DIRECTION INPUT ;
    USE SIGNAL ;
    SHAPE ABUTMENT ;
    PORT
      LAYER M5 ;
      RECT 966.780 2319.864 966.804 2320.056 ;
    END
  END tx_flit[277]
  PIN tx_flit[278]
    DIRECTION INPUT ;
    USE SIGNAL ;
    SHAPE ABUTMENT ;
    PORT
      LAYER M7 ;
      RECT 967.184 2319.864 967.216 2320.056 ;
    END
  END tx_flit[278]
  PIN tx_flit[279]
    DIRECTION INPUT ;
    USE SIGNAL ;
    SHAPE ABUTMENT ;
    PORT
      LAYER M5 ;
      RECT 967.212 2319.864 967.236 2320.056 ;
    END
  END tx_flit[279]
  PIN tx_flit[280]
    DIRECTION INPUT ;
    USE SIGNAL ;
    SHAPE ABUTMENT ;
    PORT
      LAYER M7 ;
      RECT 967.632 2319.864 967.664 2320.056 ;
    END
  END tx_flit[280]
  PIN tx_flit[281]
    DIRECTION INPUT ;
    USE SIGNAL ;
    SHAPE ABUTMENT ;
    PORT
      LAYER M5 ;
      RECT 967.644 2319.864 967.668 2320.056 ;
    END
  END tx_flit[281]
  PIN tx_flit[282]
    DIRECTION INPUT ;
    USE SIGNAL ;
    SHAPE ABUTMENT ;
    PORT
      LAYER M7 ;
      RECT 968.016 2319.864 968.048 2320.056 ;
    END
  END tx_flit[282]
  PIN tx_flit[283]
    DIRECTION INPUT ;
    USE SIGNAL ;
    SHAPE ABUTMENT ;
    PORT
      LAYER M5 ;
      RECT 968.028 2319.864 968.052 2320.056 ;
    END
  END tx_flit[283]
  PIN tx_flit[284]
    DIRECTION INPUT ;
    USE SIGNAL ;
    SHAPE ABUTMENT ;
    PORT
      LAYER M7 ;
      RECT 968.464 2319.864 968.496 2320.056 ;
    END
  END tx_flit[284]
  PIN tx_flit[285]
    DIRECTION INPUT ;
    USE SIGNAL ;
    SHAPE ABUTMENT ;
    PORT
      LAYER M5 ;
      RECT 968.460 2319.864 968.484 2320.056 ;
    END
  END tx_flit[285]
  PIN tx_flit[286]
    DIRECTION INPUT ;
    USE SIGNAL ;
    SHAPE ABUTMENT ;
    PORT
      LAYER M7 ;
      RECT 968.848 2319.864 968.880 2320.056 ;
    END
  END tx_flit[286]
  PIN tx_flit[287]
    DIRECTION INPUT ;
    USE SIGNAL ;
    SHAPE ABUTMENT ;
    PORT
      LAYER M5 ;
      RECT 968.892 2319.864 968.916 2320.056 ;
    END
  END tx_flit[287]
  PIN tx_flit[288]
    DIRECTION INPUT ;
    USE SIGNAL ;
    SHAPE ABUTMENT ;
    PORT
      LAYER M7 ;
      RECT 969.296 2319.864 969.328 2320.056 ;
    END
  END tx_flit[288]
  PIN tx_flit[289]
    DIRECTION INPUT ;
    USE SIGNAL ;
    SHAPE ABUTMENT ;
    PORT
      LAYER M5 ;
      RECT 969.324 2319.864 969.348 2320.056 ;
    END
  END tx_flit[289]
  PIN tx_flit[290]
    DIRECTION INPUT ;
    USE SIGNAL ;
    SHAPE ABUTMENT ;
    PORT
      LAYER M7 ;
      RECT 969.744 2319.864 969.776 2320.056 ;
    END
  END tx_flit[290]
  PIN tx_flit[291]
    DIRECTION INPUT ;
    USE SIGNAL ;
    SHAPE ABUTMENT ;
    PORT
      LAYER M5 ;
      RECT 969.564 2319.864 969.588 2320.056 ;
    END
  END tx_flit[291]
  PIN tx_flit[292]
    DIRECTION INPUT ;
    USE SIGNAL ;
    SHAPE ABUTMENT ;
    PORT
      LAYER M7 ;
      RECT 970.128 2319.864 970.160 2320.056 ;
    END
  END tx_flit[292]
  PIN tx_flit[293]
    DIRECTION INPUT ;
    USE SIGNAL ;
    SHAPE ABUTMENT ;
    PORT
      LAYER M5 ;
      RECT 970.140 2319.864 970.164 2320.056 ;
    END
  END tx_flit[293]
  PIN tx_flit[294]
    DIRECTION INPUT ;
    USE SIGNAL ;
    SHAPE ABUTMENT ;
    PORT
      LAYER M7 ;
      RECT 970.576 2319.864 970.608 2320.056 ;
    END
  END tx_flit[294]
  PIN tx_flit[295]
    DIRECTION INPUT ;
    USE SIGNAL ;
    SHAPE ABUTMENT ;
    PORT
      LAYER M5 ;
      RECT 970.572 2319.864 970.596 2320.056 ;
    END
  END tx_flit[295]
  PIN tx_flit[296]
    DIRECTION INPUT ;
    USE SIGNAL ;
    SHAPE ABUTMENT ;
    PORT
      LAYER M7 ;
      RECT 970.960 2319.864 970.992 2320.056 ;
    END
  END tx_flit[296]
  PIN tx_flit[297]
    DIRECTION INPUT ;
    USE SIGNAL ;
    SHAPE ABUTMENT ;
    PORT
      LAYER M5 ;
      RECT 970.956 2319.864 970.980 2320.056 ;
    END
  END tx_flit[297]
  PIN tx_flit[298]
    DIRECTION INPUT ;
    USE SIGNAL ;
    SHAPE ABUTMENT ;
    PORT
      LAYER M7 ;
      RECT 971.408 2319.864 971.440 2320.056 ;
    END
  END tx_flit[298]
  PIN tx_flit[299]
    DIRECTION INPUT ;
    USE SIGNAL ;
    SHAPE ABUTMENT ;
    PORT
      LAYER M5 ;
      RECT 971.388 2319.864 971.412 2320.056 ;
    END
  END tx_flit[299]
  PIN tx_flit[300]
    DIRECTION INPUT ;
    USE SIGNAL ;
    SHAPE ABUTMENT ;
    PORT
      LAYER M7 ;
      RECT 971.472 2319.864 971.504 2320.056 ;
    END
  END tx_flit[300]
  PIN tx_flit[301]
    DIRECTION INPUT ;
    USE SIGNAL ;
    SHAPE ABUTMENT ;
    PORT
      LAYER M5 ;
      RECT 971.820 2319.864 971.844 2320.056 ;
    END
  END tx_flit[301]
  PIN tx_flit[302]
    DIRECTION INPUT ;
    USE SIGNAL ;
    SHAPE ABUTMENT ;
    PORT
      LAYER M7 ;
      RECT 972.496 2319.864 972.528 2320.056 ;
    END
  END tx_flit[302]
  PIN tx_flit[303]
    DIRECTION INPUT ;
    USE SIGNAL ;
    SHAPE ABUTMENT ;
    PORT
      LAYER M5 ;
      RECT 972.204 2319.864 972.228 2320.056 ;
    END
  END tx_flit[303]
  PIN tx_flit[304]
    DIRECTION INPUT ;
    USE SIGNAL ;
    SHAPE ABUTMENT ;
    PORT
      LAYER M7 ;
      RECT 972.624 2319.864 972.656 2320.056 ;
    END
  END tx_flit[304]
  PIN tx_flit[305]
    DIRECTION INPUT ;
    USE SIGNAL ;
    SHAPE ABUTMENT ;
    PORT
      LAYER M5 ;
      RECT 972.636 2319.864 972.660 2320.056 ;
    END
  END tx_flit[305]
  PIN tx_flit[306]
    DIRECTION INPUT ;
    USE SIGNAL ;
    SHAPE ABUTMENT ;
    PORT
      LAYER M7 ;
      RECT 973.072 2319.864 973.104 2320.056 ;
    END
  END tx_flit[306]
  PIN tx_flit[307]
    DIRECTION INPUT ;
    USE SIGNAL ;
    SHAPE ABUTMENT ;
    PORT
      LAYER M5 ;
      RECT 973.068 2319.864 973.092 2320.056 ;
    END
  END tx_flit[307]
  PIN tx_flit[308]
    DIRECTION INPUT ;
    USE SIGNAL ;
    SHAPE ABUTMENT ;
    PORT
      LAYER M7 ;
      RECT 973.456 2319.864 973.488 2320.056 ;
    END
  END tx_flit[308]
  PIN tx_flit[309]
    DIRECTION INPUT ;
    USE SIGNAL ;
    SHAPE ABUTMENT ;
    PORT
      LAYER M5 ;
      RECT 973.452 2319.864 973.476 2320.056 ;
    END
  END tx_flit[309]
  PIN tx_flit[310]
    DIRECTION INPUT ;
    USE SIGNAL ;
    SHAPE ABUTMENT ;
    PORT
      LAYER M7 ;
      RECT 973.904 2319.864 973.936 2320.056 ;
    END
  END tx_flit[310]
  PIN tx_flit[311]
    DIRECTION INPUT ;
    USE SIGNAL ;
    SHAPE ABUTMENT ;
    PORT
      LAYER M5 ;
      RECT 973.884 2319.864 973.908 2320.056 ;
    END
  END tx_flit[311]
  PIN tx_flit[312]
    DIRECTION INPUT ;
    USE SIGNAL ;
    SHAPE ABUTMENT ;
    PORT
      LAYER M7 ;
      RECT 974.288 2319.864 974.320 2320.056 ;
    END
  END tx_flit[312]
  PIN tx_flit[313]
    DIRECTION INPUT ;
    USE SIGNAL ;
    SHAPE ABUTMENT ;
    PORT
      LAYER M5 ;
      RECT 974.412 2319.864 974.436 2320.056 ;
    END
  END tx_flit[313]
  PIN tx_flit[314]
    DIRECTION INPUT ;
    USE SIGNAL ;
    SHAPE ABUTMENT ;
    PORT
      LAYER M7 ;
      RECT 974.736 2319.864 974.768 2320.056 ;
    END
  END tx_flit[314]
  PIN tx_flit[315]
    DIRECTION INPUT ;
    USE SIGNAL ;
    SHAPE ABUTMENT ;
    PORT
      LAYER M5 ;
      RECT 974.748 2319.864 974.772 2320.056 ;
    END
  END tx_flit[315]
  PIN tx_flit[316]
    DIRECTION INPUT ;
    USE SIGNAL ;
    SHAPE ABUTMENT ;
    PORT
      LAYER M7 ;
      RECT 975.120 2319.864 975.152 2320.056 ;
    END
  END tx_flit[316]
  PIN tx_flit[317]
    DIRECTION INPUT ;
    USE SIGNAL ;
    SHAPE ABUTMENT ;
    PORT
      LAYER M5 ;
      RECT 975.132 2319.864 975.156 2320.056 ;
    END
  END tx_flit[317]
  PIN tx_flit[318]
    DIRECTION INPUT ;
    USE SIGNAL ;
    SHAPE ABUTMENT ;
    PORT
      LAYER M7 ;
      RECT 975.568 2319.864 975.600 2320.056 ;
    END
  END tx_flit[318]
  PIN tx_flit[319]
    DIRECTION INPUT ;
    USE SIGNAL ;
    SHAPE ABUTMENT ;
    PORT
      LAYER M5 ;
      RECT 975.564 2319.864 975.588 2320.056 ;
    END
  END tx_flit[319]
  PIN tx_flit[320]
    DIRECTION INPUT ;
    USE SIGNAL ;
    SHAPE ABUTMENT ;
    PORT
      LAYER M7 ;
      RECT 975.952 2319.864 975.984 2320.056 ;
    END
  END tx_flit[320]
  PIN tx_flit[321]
    DIRECTION INPUT ;
    USE SIGNAL ;
    SHAPE ABUTMENT ;
    PORT
      LAYER M5 ;
      RECT 975.996 2319.864 976.020 2320.056 ;
    END
  END tx_flit[321]
  PIN tx_flit[322]
    DIRECTION INPUT ;
    USE SIGNAL ;
    SHAPE ABUTMENT ;
    PORT
      LAYER M7 ;
      RECT 976.400 2319.864 976.432 2320.056 ;
    END
  END tx_flit[322]
  PIN tx_flit[323]
    DIRECTION INPUT ;
    USE SIGNAL ;
    SHAPE ABUTMENT ;
    PORT
      LAYER M5 ;
      RECT 976.380 2319.864 976.404 2320.056 ;
    END
  END tx_flit[323]
  PIN tx_flit[324]
    DIRECTION INPUT ;
    USE SIGNAL ;
    SHAPE ABUTMENT ;
    PORT
      LAYER M7 ;
      RECT 976.784 2319.864 976.816 2320.056 ;
    END
  END tx_flit[324]
  PIN tx_flit[325]
    DIRECTION INPUT ;
    USE SIGNAL ;
    SHAPE ABUTMENT ;
    PORT
      LAYER M5 ;
      RECT 976.812 2319.864 976.836 2320.056 ;
    END
  END tx_flit[325]
  PIN tx_flit[326]
    DIRECTION INPUT ;
    USE SIGNAL ;
    SHAPE ABUTMENT ;
    PORT
      LAYER M7 ;
      RECT 977.232 2319.864 977.264 2320.056 ;
    END
  END tx_flit[326]
  PIN tx_flit[327]
    DIRECTION INPUT ;
    USE SIGNAL ;
    SHAPE ABUTMENT ;
    PORT
      LAYER M5 ;
      RECT 977.244 2319.864 977.268 2320.056 ;
    END
  END tx_flit[327]
  PIN tx_flit[328]
    DIRECTION INPUT ;
    USE SIGNAL ;
    SHAPE ABUTMENT ;
    PORT
      LAYER M7 ;
      RECT 977.616 2319.864 977.648 2320.056 ;
    END
  END tx_flit[328]
  PIN tx_flit[329]
    DIRECTION INPUT ;
    USE SIGNAL ;
    SHAPE ABUTMENT ;
    PORT
      LAYER M5 ;
      RECT 977.628 2319.864 977.652 2320.056 ;
    END
  END tx_flit[329]
  PIN tx_flit[330]
    DIRECTION INPUT ;
    USE SIGNAL ;
    SHAPE ABUTMENT ;
    PORT
      LAYER M7 ;
      RECT 978.064 2319.864 978.096 2320.056 ;
    END
  END tx_flit[330]
  PIN tx_flit[331]
    DIRECTION INPUT ;
    USE SIGNAL ;
    SHAPE ABUTMENT ;
    PORT
      LAYER M5 ;
      RECT 978.060 2319.864 978.084 2320.056 ;
    END
  END tx_flit[331]
  PIN tx_flit[332]
    DIRECTION INPUT ;
    USE SIGNAL ;
    SHAPE ABUTMENT ;
    PORT
      LAYER M7 ;
      RECT 978.448 2319.864 978.480 2320.056 ;
    END
  END tx_flit[332]
  PIN tx_flit[333]
    DIRECTION INPUT ;
    USE SIGNAL ;
    SHAPE ABUTMENT ;
    PORT
      LAYER M5 ;
      RECT 978.732 2319.864 978.756 2320.056 ;
    END
  END tx_flit[333]
  PIN tx_flit[334]
    DIRECTION INPUT ;
    USE SIGNAL ;
    SHAPE ABUTMENT ;
    PORT
      LAYER M7 ;
      RECT 978.896 2319.864 978.928 2320.056 ;
    END
  END tx_flit[334]
  PIN tx_flit[335]
    DIRECTION INPUT ;
    USE SIGNAL ;
    SHAPE ABUTMENT ;
    PORT
      LAYER M5 ;
      RECT 978.924 2319.864 978.948 2320.056 ;
    END
  END tx_flit[335]
  PIN tx_flit[336]
    DIRECTION INPUT ;
    USE SIGNAL ;
    SHAPE ABUTMENT ;
    PORT
      LAYER M7 ;
      RECT 979.344 2319.864 979.376 2320.056 ;
    END
  END tx_flit[336]
  PIN tx_flit[337]
    DIRECTION INPUT ;
    USE SIGNAL ;
    SHAPE ABUTMENT ;
    PORT
      LAYER M5 ;
      RECT 979.308 2319.864 979.332 2320.056 ;
    END
  END tx_flit[337]
  PIN tx_flit[338]
    DIRECTION INPUT ;
    USE SIGNAL ;
    SHAPE ABUTMENT ;
    PORT
      LAYER M7 ;
      RECT 979.728 2319.864 979.760 2320.056 ;
    END
  END tx_flit[338]
  PIN tx_flit[339]
    DIRECTION INPUT ;
    USE SIGNAL ;
    SHAPE ABUTMENT ;
    PORT
      LAYER M5 ;
      RECT 979.740 2319.864 979.764 2320.056 ;
    END
  END tx_flit[339]
  PIN tx_flit[340]
    DIRECTION INPUT ;
    USE SIGNAL ;
    SHAPE ABUTMENT ;
    PORT
      LAYER M7 ;
      RECT 980.048 2319.864 980.080 2320.056 ;
    END
  END tx_flit[340]
  PIN tx_flit[341]
    DIRECTION INPUT ;
    USE SIGNAL ;
    SHAPE ABUTMENT ;
    PORT
      LAYER M5 ;
      RECT 980.172 2319.864 980.196 2320.056 ;
    END
  END tx_flit[341]
  PIN tx_flit[342]
    DIRECTION INPUT ;
    USE SIGNAL ;
    SHAPE ABUTMENT ;
    PORT
      LAYER M7 ;
      RECT 980.112 2319.864 980.144 2320.056 ;
    END
  END tx_flit[342]
  PIN tx_flit[343]
    DIRECTION INPUT ;
    USE SIGNAL ;
    SHAPE ABUTMENT ;
    PORT
      LAYER M5 ;
      RECT 980.556 2319.864 980.580 2320.056 ;
    END
  END tx_flit[343]
  PIN tx_flit[344]
    DIRECTION INPUT ;
    USE SIGNAL ;
    SHAPE ABUTMENT ;
    PORT
      LAYER M7 ;
      RECT 981.136 2319.864 981.168 2320.056 ;
    END
  END tx_flit[344]
  PIN tx_flit[345]
    DIRECTION INPUT ;
    USE SIGNAL ;
    SHAPE ABUTMENT ;
    PORT
      LAYER M5 ;
      RECT 980.988 2319.864 981.012 2320.056 ;
    END
  END tx_flit[345]
  PIN tx_flit[346]
    DIRECTION INPUT ;
    USE SIGNAL ;
    SHAPE ABUTMENT ;
    PORT
      LAYER M7 ;
      RECT 981.392 2319.864 981.424 2320.056 ;
    END
  END tx_flit[346]
  PIN tx_flit[347]
    DIRECTION INPUT ;
    USE SIGNAL ;
    SHAPE ABUTMENT ;
    PORT
      LAYER M5 ;
      RECT 981.420 2319.864 981.444 2320.056 ;
    END
  END tx_flit[347]
  PIN tx_flit[348]
    DIRECTION INPUT ;
    USE SIGNAL ;
    SHAPE ABUTMENT ;
    PORT
      LAYER M7 ;
      RECT 981.840 2319.864 981.872 2320.056 ;
    END
  END tx_flit[348]
  PIN tx_flit[349]
    DIRECTION INPUT ;
    USE SIGNAL ;
    SHAPE ABUTMENT ;
    PORT
      LAYER M5 ;
      RECT 981.804 2319.864 981.828 2320.056 ;
    END
  END tx_flit[349]
  PIN tx_flit[350]
    DIRECTION INPUT ;
    USE SIGNAL ;
    SHAPE ABUTMENT ;
    PORT
      LAYER M7 ;
      RECT 982.224 2319.864 982.256 2320.056 ;
    END
  END tx_flit[350]
  PIN tx_flit[351]
    DIRECTION INPUT ;
    USE SIGNAL ;
    SHAPE ABUTMENT ;
    PORT
      LAYER M5 ;
      RECT 982.236 2319.864 982.260 2320.056 ;
    END
  END tx_flit[351]
  PIN tx_flit[352]
    DIRECTION INPUT ;
    USE SIGNAL ;
    SHAPE ABUTMENT ;
    PORT
      LAYER M7 ;
      RECT 982.672 2319.864 982.704 2320.056 ;
    END
  END tx_flit[352]
  PIN tx_flit[353]
    DIRECTION INPUT ;
    USE SIGNAL ;
    SHAPE ABUTMENT ;
    PORT
      LAYER M5 ;
      RECT 982.524 2319.864 982.548 2320.056 ;
    END
  END tx_flit[353]
  PIN tx_flit[354]
    DIRECTION INPUT ;
    USE SIGNAL ;
    SHAPE ABUTMENT ;
    PORT
      LAYER M7 ;
      RECT 983.056 2319.864 983.088 2320.056 ;
    END
  END tx_flit[354]
  PIN tx_flit[355]
    DIRECTION INPUT ;
    USE SIGNAL ;
    SHAPE ABUTMENT ;
    PORT
      LAYER M5 ;
      RECT 983.052 2319.864 983.076 2320.056 ;
    END
  END tx_flit[355]
  PIN tx_flit[356]
    DIRECTION INPUT ;
    USE SIGNAL ;
    SHAPE ABUTMENT ;
    PORT
      LAYER M7 ;
      RECT 983.504 2319.864 983.536 2320.056 ;
    END
  END tx_flit[356]
  PIN tx_flit[357]
    DIRECTION INPUT ;
    USE SIGNAL ;
    SHAPE ABUTMENT ;
    PORT
      LAYER M5 ;
      RECT 983.484 2319.864 983.508 2320.056 ;
    END
  END tx_flit[357]
  PIN tx_flit[358]
    DIRECTION INPUT ;
    USE SIGNAL ;
    SHAPE ABUTMENT ;
    PORT
      LAYER M7 ;
      RECT 983.888 2319.864 983.920 2320.056 ;
    END
  END tx_flit[358]
  PIN tx_flit[359]
    DIRECTION INPUT ;
    USE SIGNAL ;
    SHAPE ABUTMENT ;
    PORT
      LAYER M5 ;
      RECT 983.916 2319.864 983.940 2320.056 ;
    END
  END tx_flit[359]
  PIN tx_flit[360]
    DIRECTION INPUT ;
    USE SIGNAL ;
    SHAPE ABUTMENT ;
    PORT
      LAYER M7 ;
      RECT 984.336 2319.864 984.368 2320.056 ;
    END
  END tx_flit[360]
  PIN tx_flit[361]
    DIRECTION INPUT ;
    USE SIGNAL ;
    SHAPE ABUTMENT ;
    PORT
      LAYER M5 ;
      RECT 984.348 2319.864 984.372 2320.056 ;
    END
  END tx_flit[361]
  PIN tx_flit[362]
    DIRECTION INPUT ;
    USE SIGNAL ;
    SHAPE ABUTMENT ;
    PORT
      LAYER M7 ;
      RECT 984.720 2319.864 984.752 2320.056 ;
    END
  END tx_flit[362]
  PIN tx_flit[363]
    DIRECTION INPUT ;
    USE SIGNAL ;
    SHAPE ABUTMENT ;
    PORT
      LAYER M5 ;
      RECT 984.732 2319.864 984.756 2320.056 ;
    END
  END tx_flit[363]
  PIN tx_flit[364]
    DIRECTION INPUT ;
    USE SIGNAL ;
    SHAPE ABUTMENT ;
    PORT
      LAYER M7 ;
      RECT 985.168 2319.864 985.200 2320.056 ;
    END
  END tx_flit[364]
  PIN tx_flit[365]
    DIRECTION INPUT ;
    USE SIGNAL ;
    SHAPE ABUTMENT ;
    PORT
      LAYER M5 ;
      RECT 985.164 2319.864 985.188 2320.056 ;
    END
  END tx_flit[365]
  PIN tx_flit[366]
    DIRECTION INPUT ;
    USE SIGNAL ;
    SHAPE ABUTMENT ;
    PORT
      LAYER M7 ;
      RECT 985.552 2319.864 985.584 2320.056 ;
    END
  END tx_flit[366]
  PIN tx_flit[367]
    DIRECTION INPUT ;
    USE SIGNAL ;
    SHAPE ABUTMENT ;
    PORT
      LAYER M5 ;
      RECT 985.596 2319.864 985.620 2320.056 ;
    END
  END tx_flit[367]
  PIN tx_flit[368]
    DIRECTION INPUT ;
    USE SIGNAL ;
    SHAPE ABUTMENT ;
    PORT
      LAYER M7 ;
      RECT 986.000 2319.864 986.032 2320.056 ;
    END
  END tx_flit[368]
  PIN tx_flit[369]
    DIRECTION INPUT ;
    USE SIGNAL ;
    SHAPE ABUTMENT ;
    PORT
      LAYER M5 ;
      RECT 985.980 2319.864 986.004 2320.056 ;
    END
  END tx_flit[369]
  PIN tx_flit[370]
    DIRECTION INPUT ;
    USE SIGNAL ;
    SHAPE ABUTMENT ;
    PORT
      LAYER M7 ;
      RECT 986.384 2319.864 986.416 2320.056 ;
    END
  END tx_flit[370]
  PIN tx_flit[371]
    DIRECTION INPUT ;
    USE SIGNAL ;
    SHAPE ABUTMENT ;
    PORT
      LAYER M5 ;
      RECT 986.412 2319.864 986.436 2320.056 ;
    END
  END tx_flit[371]
  PIN tx_flit[372]
    DIRECTION INPUT ;
    USE SIGNAL ;
    SHAPE ABUTMENT ;
    PORT
      LAYER M7 ;
      RECT 986.832 2319.864 986.864 2320.056 ;
    END
  END tx_flit[372]
  PIN tx_flit[373]
    DIRECTION INPUT ;
    USE SIGNAL ;
    SHAPE ABUTMENT ;
    PORT
      LAYER M5 ;
      RECT 986.844 2319.864 986.868 2320.056 ;
    END
  END tx_flit[373]
  PIN tx_flit[374]
    DIRECTION INPUT ;
    USE SIGNAL ;
    SHAPE ABUTMENT ;
    PORT
      LAYER M7 ;
      RECT 987.216 2319.864 987.248 2320.056 ;
    END
  END tx_flit[374]
  PIN tx_flit[375]
    DIRECTION INPUT ;
    USE SIGNAL ;
    SHAPE ABUTMENT ;
    PORT
      LAYER M5 ;
      RECT 987.372 2319.864 987.396 2320.056 ;
    END
  END tx_flit[375]
  PIN tx_flit[376]
    DIRECTION INPUT ;
    USE SIGNAL ;
    SHAPE ABUTMENT ;
    PORT
      LAYER M7 ;
      RECT 987.664 2319.864 987.696 2320.056 ;
    END
  END tx_flit[376]
  PIN tx_flit[377]
    DIRECTION INPUT ;
    USE SIGNAL ;
    SHAPE ABUTMENT ;
    PORT
      LAYER M5 ;
      RECT 987.660 2319.864 987.684 2320.056 ;
    END
  END tx_flit[377]
  PIN tx_flit[378]
    DIRECTION INPUT ;
    USE SIGNAL ;
    SHAPE ABUTMENT ;
    PORT
      LAYER M7 ;
      RECT 988.048 2319.864 988.080 2320.056 ;
    END
  END tx_flit[378]
  PIN tx_flit[379]
    DIRECTION INPUT ;
    USE SIGNAL ;
    SHAPE ABUTMENT ;
    PORT
      LAYER M5 ;
      RECT 988.092 2319.864 988.116 2320.056 ;
    END
  END tx_flit[379]
  PIN tx_flit[380]
    DIRECTION INPUT ;
    USE SIGNAL ;
    SHAPE ABUTMENT ;
    PORT
      LAYER M7 ;
      RECT 988.496 2319.864 988.528 2320.056 ;
    END
  END tx_flit[380]
  PIN tx_flit[381]
    DIRECTION INPUT ;
    USE SIGNAL ;
    SHAPE ABUTMENT ;
    PORT
      LAYER M5 ;
      RECT 988.476 2319.864 988.500 2320.056 ;
    END
  END tx_flit[381]
  PIN tx_flit[382]
    DIRECTION INPUT ;
    USE SIGNAL ;
    SHAPE ABUTMENT ;
    PORT
      LAYER M7 ;
      RECT 988.688 2319.864 988.720 2320.056 ;
    END
  END tx_flit[382]
  PIN tx_flit[383]
    DIRECTION INPUT ;
    USE SIGNAL ;
    SHAPE ABUTMENT ;
    PORT
      LAYER M5 ;
      RECT 988.908 2319.864 988.932 2320.056 ;
    END
  END tx_flit[383]
  PIN tx_flit[384]
    DIRECTION INPUT ;
    USE SIGNAL ;
    SHAPE ABUTMENT ;
    PORT
      LAYER M7 ;
      RECT 988.752 2319.864 988.784 2320.056 ;
    END
  END tx_flit[384]
  PIN tx_flit[385]
    DIRECTION INPUT ;
    USE SIGNAL ;
    SHAPE ABUTMENT ;
    PORT
      LAYER M5 ;
      RECT 989.340 2319.864 989.364 2320.056 ;
    END
  END tx_flit[385]
  PIN tx_flit[386]
    DIRECTION INPUT ;
    USE SIGNAL ;
    SHAPE ABUTMENT ;
    PORT
      LAYER M7 ;
      RECT 989.776 2319.864 989.808 2320.056 ;
    END
  END tx_flit[386]
  PIN tx_flit[387]
    DIRECTION INPUT ;
    USE SIGNAL ;
    SHAPE ABUTMENT ;
    PORT
      LAYER M5 ;
      RECT 989.772 2319.864 989.796 2320.056 ;
    END
  END tx_flit[387]
  PIN tx_flit[388]
    DIRECTION INPUT ;
    USE SIGNAL ;
    SHAPE ABUTMENT ;
    PORT
      LAYER M7 ;
      RECT 990.160 2319.864 990.192 2320.056 ;
    END
  END tx_flit[388]
  PIN tx_flit[389]
    DIRECTION INPUT ;
    USE SIGNAL ;
    SHAPE ABUTMENT ;
    PORT
      LAYER M5 ;
      RECT 990.156 2319.864 990.180 2320.056 ;
    END
  END tx_flit[389]
  PIN tx_flit[390]
    DIRECTION INPUT ;
    USE SIGNAL ;
    SHAPE ABUTMENT ;
    PORT
      LAYER M7 ;
      RECT 990.608 2319.864 990.640 2320.056 ;
    END
  END tx_flit[390]
  PIN tx_flit[391]
    DIRECTION INPUT ;
    USE SIGNAL ;
    SHAPE ABUTMENT ;
    PORT
      LAYER M5 ;
      RECT 990.588 2319.864 990.612 2320.056 ;
    END
  END tx_flit[391]
  PIN tx_flit[392]
    DIRECTION INPUT ;
    USE SIGNAL ;
    SHAPE ABUTMENT ;
    PORT
      LAYER M7 ;
      RECT 990.992 2319.864 991.024 2320.056 ;
    END
  END tx_flit[392]
  PIN tx_flit[393]
    DIRECTION INPUT ;
    USE SIGNAL ;
    SHAPE ABUTMENT ;
    PORT
      LAYER M5 ;
      RECT 991.020 2319.864 991.044 2320.056 ;
    END
  END tx_flit[393]
  PIN tx_flit[394]
    DIRECTION INPUT ;
    USE SIGNAL ;
    SHAPE ABUTMENT ;
    PORT
      LAYER M7 ;
      RECT 991.440 2319.864 991.472 2320.056 ;
    END
  END tx_flit[394]
  PIN tx_flit[395]
    DIRECTION INPUT ;
    USE SIGNAL ;
    SHAPE ABUTMENT ;
    PORT
      LAYER M5 ;
      RECT 991.164 2319.864 991.188 2320.056 ;
    END
  END tx_flit[395]
  PIN tx_flit[396]
    DIRECTION INPUT ;
    USE SIGNAL ;
    SHAPE ABUTMENT ;
    PORT
      LAYER M7 ;
      RECT 991.824 2319.864 991.856 2320.056 ;
    END
  END tx_flit[396]
  PIN tx_flit[397]
    DIRECTION INPUT ;
    USE SIGNAL ;
    SHAPE ABUTMENT ;
    PORT
      LAYER M5 ;
      RECT 991.836 2319.864 991.860 2320.056 ;
    END
  END tx_flit[397]
  PIN tx_flit[398]
    DIRECTION INPUT ;
    USE SIGNAL ;
    SHAPE ABUTMENT ;
    PORT
      LAYER M7 ;
      RECT 992.272 2319.864 992.304 2320.056 ;
    END
  END tx_flit[398]
  PIN tx_flit[399]
    DIRECTION INPUT ;
    USE SIGNAL ;
    SHAPE ABUTMENT ;
    PORT
      LAYER M5 ;
      RECT 992.268 2319.864 992.292 2320.056 ;
    END
  END tx_flit[399]
  PIN tx_flit[400]
    DIRECTION INPUT ;
    USE SIGNAL ;
    SHAPE ABUTMENT ;
    PORT
      LAYER M7 ;
      RECT 992.656 2319.864 992.688 2320.056 ;
    END
  END tx_flit[400]
  PIN tx_flit[401]
    DIRECTION INPUT ;
    USE SIGNAL ;
    SHAPE ABUTMENT ;
    PORT
      LAYER M5 ;
      RECT 992.652 2319.864 992.676 2320.056 ;
    END
  END tx_flit[401]
  PIN tx_flit[402]
    DIRECTION INPUT ;
    USE SIGNAL ;
    SHAPE ABUTMENT ;
    PORT
      LAYER M7 ;
      RECT 993.104 2319.864 993.136 2320.056 ;
    END
  END tx_flit[402]
  PIN tx_flit[403]
    DIRECTION INPUT ;
    USE SIGNAL ;
    SHAPE ABUTMENT ;
    PORT
      LAYER M5 ;
      RECT 993.084 2319.864 993.108 2320.056 ;
    END
  END tx_flit[403]
  PIN tx_flit[404]
    DIRECTION INPUT ;
    USE SIGNAL ;
    SHAPE ABUTMENT ;
    PORT
      LAYER M7 ;
      RECT 993.488 2319.864 993.520 2320.056 ;
    END
  END tx_flit[404]
  PIN tx_flit[405]
    DIRECTION INPUT ;
    USE SIGNAL ;
    SHAPE ABUTMENT ;
    PORT
      LAYER M5 ;
      RECT 993.516 2319.864 993.540 2320.056 ;
    END
  END tx_flit[405]
  PIN tx_flit[406]
    DIRECTION INPUT ;
    USE SIGNAL ;
    SHAPE ABUTMENT ;
    PORT
      LAYER M7 ;
      RECT 993.936 2319.864 993.968 2320.056 ;
    END
  END tx_flit[406]
  PIN tx_flit[407]
    DIRECTION INPUT ;
    USE SIGNAL ;
    SHAPE ABUTMENT ;
    PORT
      LAYER M5 ;
      RECT 993.948 2319.864 993.972 2320.056 ;
    END
  END tx_flit[407]
  PIN tx_flit[408]
    DIRECTION INPUT ;
    USE SIGNAL ;
    SHAPE ABUTMENT ;
    PORT
      LAYER M7 ;
      RECT 994.320 2319.864 994.352 2320.056 ;
    END
  END tx_flit[408]
  PIN tx_flit[409]
    DIRECTION INPUT ;
    USE SIGNAL ;
    SHAPE ABUTMENT ;
    PORT
      LAYER M5 ;
      RECT 994.332 2319.864 994.356 2320.056 ;
    END
  END tx_flit[409]
  PIN tx_flit[410]
    DIRECTION INPUT ;
    USE SIGNAL ;
    SHAPE ABUTMENT ;
    PORT
      LAYER M7 ;
      RECT 994.768 2319.864 994.800 2320.056 ;
    END
  END tx_flit[410]
  PIN tx_flit[411]
    DIRECTION INPUT ;
    USE SIGNAL ;
    SHAPE ABUTMENT ;
    PORT
      LAYER M5 ;
      RECT 994.764 2319.864 994.788 2320.056 ;
    END
  END tx_flit[411]
  PIN tx_flit[412]
    DIRECTION INPUT ;
    USE SIGNAL ;
    SHAPE ABUTMENT ;
    PORT
      LAYER M7 ;
      RECT 995.152 2319.864 995.184 2320.056 ;
    END
  END tx_flit[412]
  PIN tx_flit[413]
    DIRECTION INPUT ;
    USE SIGNAL ;
    SHAPE ABUTMENT ;
    PORT
      LAYER M5 ;
      RECT 995.196 2319.864 995.220 2320.056 ;
    END
  END tx_flit[413]
  PIN tx_flit[414]
    DIRECTION INPUT ;
    USE SIGNAL ;
    SHAPE ABUTMENT ;
    PORT
      LAYER M7 ;
      RECT 995.600 2319.864 995.632 2320.056 ;
    END
  END tx_flit[414]
  PIN tx_flit[415]
    DIRECTION INPUT ;
    USE SIGNAL ;
    SHAPE ABUTMENT ;
    PORT
      LAYER M5 ;
      RECT 995.484 2319.864 995.508 2320.056 ;
    END
  END tx_flit[415]
  PIN tx_flit[416]
    DIRECTION INPUT ;
    USE SIGNAL ;
    SHAPE ABUTMENT ;
    PORT
      LAYER M7 ;
      RECT 995.984 2319.864 996.016 2320.056 ;
    END
  END tx_flit[416]
  PIN tx_flit[417]
    DIRECTION INPUT ;
    USE SIGNAL ;
    SHAPE ABUTMENT ;
    PORT
      LAYER M5 ;
      RECT 996.012 2319.864 996.036 2320.056 ;
    END
  END tx_flit[417]
  PIN tx_flit[418]
    DIRECTION INPUT ;
    USE SIGNAL ;
    SHAPE ABUTMENT ;
    PORT
      LAYER M7 ;
      RECT 996.432 2319.864 996.464 2320.056 ;
    END
  END tx_flit[418]
  PIN tx_flit[419]
    DIRECTION INPUT ;
    USE SIGNAL ;
    SHAPE ABUTMENT ;
    PORT
      LAYER M5 ;
      RECT 996.444 2319.864 996.468 2320.056 ;
    END
  END tx_flit[419]
  PIN tx_flit[420]
    DIRECTION INPUT ;
    USE SIGNAL ;
    SHAPE ABUTMENT ;
    PORT
      LAYER M7 ;
      RECT 996.816 2319.864 996.848 2320.056 ;
    END
  END tx_flit[420]
  PIN tx_flit[421]
    DIRECTION INPUT ;
    USE SIGNAL ;
    SHAPE ABUTMENT ;
    PORT
      LAYER M5 ;
      RECT 996.828 2319.864 996.852 2320.056 ;
    END
  END tx_flit[421]
  PIN tx_flit[422]
    DIRECTION INPUT ;
    USE SIGNAL ;
    SHAPE ABUTMENT ;
    PORT
      LAYER M7 ;
      RECT 997.264 2319.864 997.296 2320.056 ;
    END
  END tx_flit[422]
  PIN tx_flit[423]
    DIRECTION INPUT ;
    USE SIGNAL ;
    SHAPE ABUTMENT ;
    PORT
      LAYER M5 ;
      RECT 997.260 2319.864 997.284 2320.056 ;
    END
  END tx_flit[423]
  PIN tx_flit[424]
    DIRECTION INPUT ;
    USE SIGNAL ;
    SHAPE ABUTMENT ;
    PORT
      LAYER M7 ;
      RECT 997.392 2319.864 997.424 2320.056 ;
    END
  END tx_flit[424]
  PIN tx_flit[425]
    DIRECTION INPUT ;
    USE SIGNAL ;
    SHAPE ABUTMENT ;
    PORT
      LAYER M5 ;
      RECT 997.692 2319.864 997.716 2320.056 ;
    END
  END tx_flit[425]
  PIN tx_flit[426]
    DIRECTION INPUT ;
    USE SIGNAL ;
    SHAPE ABUTMENT ;
    PORT
      LAYER M7 ;
      RECT 998.416 2319.864 998.448 2320.056 ;
    END
  END tx_flit[426]
  PIN tx_flit[427]
    DIRECTION INPUT ;
    USE SIGNAL ;
    SHAPE ABUTMENT ;
    PORT
      LAYER M5 ;
      RECT 998.076 2319.864 998.100 2320.056 ;
    END
  END tx_flit[427]
  PIN tx_flit[428]
    DIRECTION INPUT ;
    USE SIGNAL ;
    SHAPE ABUTMENT ;
    PORT
      LAYER M7 ;
      RECT 998.480 2319.864 998.512 2320.056 ;
    END
  END tx_flit[428]
  PIN tx_flit[429]
    DIRECTION INPUT ;
    USE SIGNAL ;
    SHAPE ABUTMENT ;
    PORT
      LAYER M5 ;
      RECT 998.508 2319.864 998.532 2320.056 ;
    END
  END tx_flit[429]
  PIN tx_flit[430]
    DIRECTION INPUT ;
    USE SIGNAL ;
    SHAPE ABUTMENT ;
    PORT
      LAYER M7 ;
      RECT 998.928 2319.864 998.960 2320.056 ;
    END
  END tx_flit[430]
  PIN tx_flit[431]
    DIRECTION INPUT ;
    USE SIGNAL ;
    SHAPE ABUTMENT ;
    PORT
      LAYER M5 ;
      RECT 998.940 2319.864 998.964 2320.056 ;
    END
  END tx_flit[431]
  PIN tx_flit[432]
    DIRECTION INPUT ;
    USE SIGNAL ;
    SHAPE ABUTMENT ;
    PORT
      LAYER M7 ;
      RECT 999.376 2319.864 999.408 2320.056 ;
    END
  END tx_flit[432]
  PIN tx_flit[433]
    DIRECTION INPUT ;
    USE SIGNAL ;
    SHAPE ABUTMENT ;
    PORT
      LAYER M5 ;
      RECT 999.372 2319.864 999.396 2320.056 ;
    END
  END tx_flit[433]
  PIN tx_flit[434]
    DIRECTION INPUT ;
    USE SIGNAL ;
    SHAPE ABUTMENT ;
    PORT
      LAYER M7 ;
      RECT 999.760 2319.864 999.792 2320.056 ;
    END
  END tx_flit[434]
  PIN tx_flit[435]
    DIRECTION INPUT ;
    USE SIGNAL ;
    SHAPE ABUTMENT ;
    PORT
      LAYER M5 ;
      RECT 999.756 2319.864 999.780 2320.056 ;
    END
  END tx_flit[435]
  PIN tx_flit[436]
    DIRECTION INPUT ;
    USE SIGNAL ;
    SHAPE ABUTMENT ;
    PORT
      LAYER M7 ;
      RECT 1000.208 2319.864 1000.240 2320.056 ;
    END
  END tx_flit[436]
  PIN tx_flit[437]
    DIRECTION INPUT ;
    USE SIGNAL ;
    SHAPE ABUTMENT ;
    PORT
      LAYER M5 ;
      RECT 1000.332 2319.864 1000.356 2320.056 ;
    END
  END tx_flit[437]
  PIN tx_flit[438]
    DIRECTION INPUT ;
    USE SIGNAL ;
    SHAPE ABUTMENT ;
    PORT
      LAYER M7 ;
      RECT 1000.592 2319.864 1000.624 2320.056 ;
    END
  END tx_flit[438]
  PIN tx_flit[439]
    DIRECTION INPUT ;
    USE SIGNAL ;
    SHAPE ABUTMENT ;
    PORT
      LAYER M5 ;
      RECT 1000.620 2319.864 1000.644 2320.056 ;
    END
  END tx_flit[439]
  PIN tx_flit[440]
    DIRECTION INPUT ;
    USE SIGNAL ;
    SHAPE ABUTMENT ;
    PORT
      LAYER M7 ;
      RECT 1001.040 2319.864 1001.072 2320.056 ;
    END
  END tx_flit[440]
  PIN tx_flit[441]
    DIRECTION INPUT ;
    USE SIGNAL ;
    SHAPE ABUTMENT ;
    PORT
      LAYER M5 ;
      RECT 1001.004 2319.864 1001.028 2320.056 ;
    END
  END tx_flit[441]
  PIN tx_flit[442]
    DIRECTION INPUT ;
    USE SIGNAL ;
    SHAPE ABUTMENT ;
    PORT
      LAYER M7 ;
      RECT 1001.424 2319.864 1001.456 2320.056 ;
    END
  END tx_flit[442]
  PIN tx_flit[443]
    DIRECTION INPUT ;
    USE SIGNAL ;
    SHAPE ABUTMENT ;
    PORT
      LAYER M5 ;
      RECT 1001.436 2319.864 1001.460 2320.056 ;
    END
  END tx_flit[443]
  PIN tx_flit[444]
    DIRECTION INPUT ;
    USE SIGNAL ;
    SHAPE ABUTMENT ;
    PORT
      LAYER M7 ;
      RECT 1001.872 2319.864 1001.904 2320.056 ;
    END
  END tx_flit[444]
  PIN tx_flit[445]
    DIRECTION INPUT ;
    USE SIGNAL ;
    SHAPE ABUTMENT ;
    PORT
      LAYER M5 ;
      RECT 1001.868 2319.864 1001.892 2320.056 ;
    END
  END tx_flit[445]
  PIN tx_flit[446]
    DIRECTION INPUT ;
    USE SIGNAL ;
    SHAPE ABUTMENT ;
    PORT
      LAYER M7 ;
      RECT 1002.256 2319.864 1002.288 2320.056 ;
    END
  END tx_flit[446]
  PIN tx_flit[447]
    DIRECTION INPUT ;
    USE SIGNAL ;
    SHAPE ABUTMENT ;
    PORT
      LAYER M5 ;
      RECT 1002.252 2319.864 1002.276 2320.056 ;
    END
  END tx_flit[447]
  PIN tx_flit[448]
    DIRECTION INPUT ;
    USE SIGNAL ;
    SHAPE ABUTMENT ;
    PORT
      LAYER M7 ;
      RECT 1002.704 2319.864 1002.736 2320.056 ;
    END
  END tx_flit[448]
  PIN tx_flit[449]
    DIRECTION INPUT ;
    USE SIGNAL ;
    SHAPE ABUTMENT ;
    PORT
      LAYER M5 ;
      RECT 1002.684 2319.864 1002.708 2320.056 ;
    END
  END tx_flit[449]
  PIN tx_flit[450]
    DIRECTION INPUT ;
    USE SIGNAL ;
    SHAPE ABUTMENT ;
    PORT
      LAYER M7 ;
      RECT 1003.088 2319.864 1003.120 2320.056 ;
    END
  END tx_flit[450]
  PIN tx_flit[451]
    DIRECTION INPUT ;
    USE SIGNAL ;
    SHAPE ABUTMENT ;
    PORT
      LAYER M5 ;
      RECT 1003.116 2319.864 1003.140 2320.056 ;
    END
  END tx_flit[451]
  PIN tx_flit[452]
    DIRECTION INPUT ;
    USE SIGNAL ;
    SHAPE ABUTMENT ;
    PORT
      LAYER M7 ;
      RECT 1003.536 2319.864 1003.568 2320.056 ;
    END
  END tx_flit[452]
  PIN tx_flit[453]
    DIRECTION INPUT ;
    USE SIGNAL ;
    SHAPE ABUTMENT ;
    PORT
      LAYER M5 ;
      RECT 1003.500 2319.864 1003.524 2320.056 ;
    END
  END tx_flit[453]
  PIN tx_flit[454]
    DIRECTION INPUT ;
    USE SIGNAL ;
    SHAPE ABUTMENT ;
    PORT
      LAYER M7 ;
      RECT 1003.920 2319.864 1003.952 2320.056 ;
    END
  END tx_flit[454]
  PIN tx_flit[455]
    DIRECTION INPUT ;
    USE SIGNAL ;
    SHAPE ABUTMENT ;
    PORT
      LAYER M5 ;
      RECT 1003.932 2319.864 1003.956 2320.056 ;
    END
  END tx_flit[455]
  PIN tx_flit[456]
    DIRECTION INPUT ;
    USE SIGNAL ;
    SHAPE ABUTMENT ;
    PORT
      LAYER M7 ;
      RECT 1004.368 2319.864 1004.400 2320.056 ;
    END
  END tx_flit[456]
  PIN tx_flit[457]
    DIRECTION INPUT ;
    USE SIGNAL ;
    SHAPE ABUTMENT ;
    PORT
      LAYER M5 ;
      RECT 1004.124 2319.864 1004.148 2320.056 ;
    END
  END tx_flit[457]
  PIN tx_flit[458]
    DIRECTION INPUT ;
    USE SIGNAL ;
    SHAPE ABUTMENT ;
    PORT
      LAYER M7 ;
      RECT 1004.752 2319.864 1004.784 2320.056 ;
    END
  END tx_flit[458]
  PIN tx_flit[459]
    DIRECTION INPUT ;
    USE SIGNAL ;
    SHAPE ABUTMENT ;
    PORT
      LAYER M5 ;
      RECT 1004.796 2319.864 1004.820 2320.056 ;
    END
  END tx_flit[459]
  PIN tx_flit[460]
    DIRECTION INPUT ;
    USE SIGNAL ;
    SHAPE ABUTMENT ;
    PORT
      LAYER M7 ;
      RECT 1005.200 2319.864 1005.232 2320.056 ;
    END
  END tx_flit[460]
  PIN tx_flit[461]
    DIRECTION INPUT ;
    USE SIGNAL ;
    SHAPE ABUTMENT ;
    PORT
      LAYER M5 ;
      RECT 1005.180 2319.864 1005.204 2320.056 ;
    END
  END tx_flit[461]
  PIN tx_flit[462]
    DIRECTION INPUT ;
    USE SIGNAL ;
    SHAPE ABUTMENT ;
    PORT
      LAYER M7 ;
      RECT 1005.584 2319.864 1005.616 2320.056 ;
    END
  END tx_flit[462]
  PIN tx_flit[463]
    DIRECTION INPUT ;
    USE SIGNAL ;
    SHAPE ABUTMENT ;
    PORT
      LAYER M5 ;
      RECT 1005.612 2319.864 1005.636 2320.056 ;
    END
  END tx_flit[463]
  PIN tx_flit[464]
    DIRECTION INPUT ;
    USE SIGNAL ;
    SHAPE ABUTMENT ;
    PORT
      LAYER M7 ;
      RECT 1005.968 2319.864 1006.000 2320.056 ;
    END
  END tx_flit[464]
  PIN tx_flit[465]
    DIRECTION INPUT ;
    USE SIGNAL ;
    SHAPE ABUTMENT ;
    PORT
      LAYER M5 ;
      RECT 1006.044 2319.864 1006.068 2320.056 ;
    END
  END tx_flit[465]
  PIN tx_flit[466]
    DIRECTION INPUT ;
    USE SIGNAL ;
    SHAPE ABUTMENT ;
    PORT
      LAYER M7 ;
      RECT 1006.032 2319.864 1006.064 2320.056 ;
    END
  END tx_flit[466]
  PIN tx_flit[467]
    DIRECTION INPUT ;
    USE SIGNAL ;
    SHAPE ABUTMENT ;
    PORT
      LAYER M5 ;
      RECT 1006.428 2319.864 1006.452 2320.056 ;
    END
  END tx_flit[467]
  PIN tx_flit[468]
    DIRECTION INPUT ;
    USE SIGNAL ;
    SHAPE ABUTMENT ;
    PORT
      LAYER M7 ;
      RECT 1007.056 2319.864 1007.088 2320.056 ;
    END
  END tx_flit[468]
  PIN tx_flit[469]
    DIRECTION INPUT ;
    USE SIGNAL ;
    SHAPE ABUTMENT ;
    PORT
      LAYER M5 ;
      RECT 1006.860 2319.864 1006.884 2320.056 ;
    END
  END tx_flit[469]
  PIN tx_flit[470]
    DIRECTION INPUT ;
    USE SIGNAL ;
    SHAPE ABUTMENT ;
    PORT
      LAYER M7 ;
      RECT 1007.248 2319.864 1007.280 2320.056 ;
    END
  END tx_flit[470]
  PIN tx_flit[471]
    DIRECTION INPUT ;
    USE SIGNAL ;
    SHAPE ABUTMENT ;
    PORT
      LAYER M5 ;
      RECT 1007.292 2319.864 1007.316 2320.056 ;
    END
  END tx_flit[471]
  PIN tx_flit[472]
    DIRECTION INPUT ;
    USE SIGNAL ;
    SHAPE ABUTMENT ;
    PORT
      LAYER M7 ;
      RECT 1007.696 2319.864 1007.728 2320.056 ;
    END
  END tx_flit[472]
  PIN tx_flit[473]
    DIRECTION INPUT ;
    USE SIGNAL ;
    SHAPE ABUTMENT ;
    PORT
      LAYER M5 ;
      RECT 1007.676 2319.864 1007.700 2320.056 ;
    END
  END tx_flit[473]
  PIN tx_flit[474]
    DIRECTION INPUT ;
    USE SIGNAL ;
    SHAPE ABUTMENT ;
    PORT
      LAYER M7 ;
      RECT 1008.080 2319.864 1008.112 2320.056 ;
    END
  END tx_flit[474]
  PIN tx_flit[475]
    DIRECTION INPUT ;
    USE SIGNAL ;
    SHAPE ABUTMENT ;
    PORT
      LAYER M5 ;
      RECT 1008.108 2319.864 1008.132 2320.056 ;
    END
  END tx_flit[475]
  PIN tx_flit[476]
    DIRECTION INPUT ;
    USE SIGNAL ;
    SHAPE ABUTMENT ;
    PORT
      LAYER M7 ;
      RECT 1008.528 2319.864 1008.560 2320.056 ;
    END
  END tx_flit[476]
  PIN tx_flit[477]
    DIRECTION INPUT ;
    USE SIGNAL ;
    SHAPE ABUTMENT ;
    PORT
      LAYER M5 ;
      RECT 1008.444 2319.864 1008.468 2320.056 ;
    END
  END tx_flit[477]
  PIN tx_flit[478]
    DIRECTION INPUT ;
    USE SIGNAL ;
    SHAPE ABUTMENT ;
    PORT
      LAYER M7 ;
      RECT 1008.976 2319.864 1009.008 2320.056 ;
    END
  END tx_flit[478]
  PIN tx_flit[479]
    DIRECTION INPUT ;
    USE SIGNAL ;
    SHAPE ABUTMENT ;
    PORT
      LAYER M5 ;
      RECT 1008.972 2319.864 1008.996 2320.056 ;
    END
  END tx_flit[479]
  PIN tx_flit[480]
    DIRECTION INPUT ;
    USE SIGNAL ;
    SHAPE ABUTMENT ;
    PORT
      LAYER M7 ;
      RECT 1009.360 2319.864 1009.392 2320.056 ;
    END
  END tx_flit[480]
  PIN tx_flit[481]
    DIRECTION INPUT ;
    USE SIGNAL ;
    SHAPE ABUTMENT ;
    PORT
      LAYER M5 ;
      RECT 1009.356 2319.864 1009.380 2320.056 ;
    END
  END tx_flit[481]
  PIN tx_flit[482]
    DIRECTION INPUT ;
    USE SIGNAL ;
    SHAPE ABUTMENT ;
    PORT
      LAYER M7 ;
      RECT 1009.808 2319.864 1009.840 2320.056 ;
    END
  END tx_flit[482]
  PIN tx_flit[483]
    DIRECTION INPUT ;
    USE SIGNAL ;
    SHAPE ABUTMENT ;
    PORT
      LAYER M5 ;
      RECT 1009.788 2319.864 1009.812 2320.056 ;
    END
  END tx_flit[483]
  PIN tx_flit[484]
    DIRECTION INPUT ;
    USE SIGNAL ;
    SHAPE ABUTMENT ;
    PORT
      LAYER M7 ;
      RECT 1010.192 2319.864 1010.224 2320.056 ;
    END
  END tx_flit[484]
  PIN tx_flit[485]
    DIRECTION INPUT ;
    USE SIGNAL ;
    SHAPE ABUTMENT ;
    PORT
      LAYER M5 ;
      RECT 1010.220 2319.864 1010.244 2320.056 ;
    END
  END tx_flit[485]
  PIN tx_flit[486]
    DIRECTION INPUT ;
    USE SIGNAL ;
    SHAPE ABUTMENT ;
    PORT
      LAYER M7 ;
      RECT 1010.640 2319.864 1010.672 2320.056 ;
    END
  END tx_flit[486]
  PIN tx_flit[487]
    DIRECTION INPUT ;
    USE SIGNAL ;
    SHAPE ABUTMENT ;
    PORT
      LAYER M5 ;
      RECT 1010.604 2319.864 1010.628 2320.056 ;
    END
  END tx_flit[487]
  PIN tx_flit[488]
    DIRECTION INPUT ;
    USE SIGNAL ;
    SHAPE ABUTMENT ;
    PORT
      LAYER M7 ;
      RECT 1011.024 2319.864 1011.056 2320.056 ;
    END
  END tx_flit[488]
  PIN tx_flit[489]
    DIRECTION INPUT ;
    USE SIGNAL ;
    SHAPE ABUTMENT ;
    PORT
      LAYER M5 ;
      RECT 1011.036 2319.864 1011.060 2320.056 ;
    END
  END tx_flit[489]
  PIN tx_flit[490]
    DIRECTION INPUT ;
    USE SIGNAL ;
    SHAPE ABUTMENT ;
    PORT
      LAYER M7 ;
      RECT 1011.472 2319.864 1011.504 2320.056 ;
    END
  END tx_flit[490]
  PIN tx_flit[491]
    DIRECTION INPUT ;
    USE SIGNAL ;
    SHAPE ABUTMENT ;
    PORT
      LAYER M5 ;
      RECT 1011.468 2319.864 1011.492 2320.056 ;
    END
  END tx_flit[491]
  PIN tx_flit[492]
    DIRECTION INPUT ;
    USE SIGNAL ;
    SHAPE ABUTMENT ;
    PORT
      LAYER M7 ;
      RECT 1011.856 2319.864 1011.888 2320.056 ;
    END
  END tx_flit[492]
  PIN tx_flit[493]
    DIRECTION INPUT ;
    USE SIGNAL ;
    SHAPE ABUTMENT ;
    PORT
      LAYER M5 ;
      RECT 1011.852 2319.864 1011.876 2320.056 ;
    END
  END tx_flit[493]
  PIN tx_flit[494]
    DIRECTION INPUT ;
    USE SIGNAL ;
    SHAPE ABUTMENT ;
    PORT
      LAYER M7 ;
      RECT 1012.304 2319.864 1012.336 2320.056 ;
    END
  END tx_flit[494]
  PIN tx_flit[495]
    DIRECTION INPUT ;
    USE SIGNAL ;
    SHAPE ABUTMENT ;
    PORT
      LAYER M5 ;
      RECT 1012.284 2319.864 1012.308 2320.056 ;
    END
  END tx_flit[495]
  PIN tx_flit[496]
    DIRECTION INPUT ;
    USE SIGNAL ;
    SHAPE ABUTMENT ;
    PORT
      LAYER M7 ;
      RECT 1012.688 2319.864 1012.720 2320.056 ;
    END
  END tx_flit[496]
  PIN tx_flit[497]
    DIRECTION INPUT ;
    USE SIGNAL ;
    SHAPE ABUTMENT ;
    PORT
      LAYER M5 ;
      RECT 1012.716 2319.864 1012.740 2320.056 ;
    END
  END tx_flit[497]
  PIN tx_flit[498]
    DIRECTION INPUT ;
    USE SIGNAL ;
    SHAPE ABUTMENT ;
    PORT
      LAYER M7 ;
      RECT 1013.136 2319.864 1013.168 2320.056 ;
    END
  END tx_flit[498]
  PIN tx_flit[499]
    DIRECTION INPUT ;
    USE SIGNAL ;
    SHAPE ABUTMENT ;
    PORT
      LAYER M5 ;
      RECT 1013.292 2319.864 1013.316 2320.056 ;
    END
  END tx_flit[499]
  PIN tx_flit[500]
    DIRECTION INPUT ;
    USE SIGNAL ;
    SHAPE ABUTMENT ;
    PORT
      LAYER M7 ;
      RECT 1013.520 2319.864 1013.552 2320.056 ;
    END
  END tx_flit[500]
  PIN tx_flit[501]
    DIRECTION INPUT ;
    USE SIGNAL ;
    SHAPE ABUTMENT ;
    PORT
      LAYER M5 ;
      RECT 1013.532 2319.864 1013.556 2320.056 ;
    END
  END tx_flit[501]
  PIN tx_flit[502]
    DIRECTION INPUT ;
    USE SIGNAL ;
    SHAPE ABUTMENT ;
    PORT
      LAYER M7 ;
      RECT 1013.968 2319.864 1014.000 2320.056 ;
    END
  END tx_flit[502]
  PIN tx_flit[503]
    DIRECTION INPUT ;
    USE SIGNAL ;
    SHAPE ABUTMENT ;
    PORT
      LAYER M5 ;
      RECT 1013.964 2319.864 1013.988 2320.056 ;
    END
  END tx_flit[503]
  PIN tx_flit[504]
    DIRECTION INPUT ;
    USE SIGNAL ;
    SHAPE ABUTMENT ;
    PORT
      LAYER M7 ;
      RECT 1014.352 2319.864 1014.384 2320.056 ;
    END
  END tx_flit[504]
  PIN tx_flit[505]
    DIRECTION INPUT ;
    USE SIGNAL ;
    SHAPE ABUTMENT ;
    PORT
      LAYER M5 ;
      RECT 1014.396 2319.864 1014.420 2320.056 ;
    END
  END tx_flit[505]
  PIN tx_flit[506]
    DIRECTION INPUT ;
    USE SIGNAL ;
    SHAPE ABUTMENT ;
    PORT
      LAYER M7 ;
      RECT 1014.608 2319.864 1014.640 2320.056 ;
    END
  END tx_flit[506]
  PIN tx_flit[507]
    DIRECTION INPUT ;
    USE SIGNAL ;
    SHAPE ABUTMENT ;
    PORT
      LAYER M5 ;
      RECT 1014.780 2319.864 1014.804 2320.056 ;
    END
  END tx_flit[507]
  PIN tx_flit[508]
    DIRECTION INPUT ;
    USE SIGNAL ;
    SHAPE ABUTMENT ;
    PORT
      LAYER M7 ;
      RECT 1014.672 2319.864 1014.704 2320.056 ;
    END
  END tx_flit[508]
  PIN tx_flit[509]
    DIRECTION INPUT ;
    USE SIGNAL ;
    SHAPE ABUTMENT ;
    PORT
      LAYER M5 ;
      RECT 1015.212 2319.864 1015.236 2320.056 ;
    END
  END tx_flit[509]
  PIN tx_flit[510]
    DIRECTION INPUT ;
    USE SIGNAL ;
    SHAPE ABUTMENT ;
    PORT
      LAYER M7 ;
      RECT 1015.696 2319.864 1015.728 2320.056 ;
    END
  END tx_flit[510]
  PIN tx_flit[511]
    DIRECTION INPUT ;
    USE SIGNAL ;
    SHAPE ABUTMENT ;
    PORT
      LAYER M5 ;
      RECT 1015.644 2319.864 1015.668 2320.056 ;
    END
  END tx_flit[511]
  PIN tx_flit[512]
    DIRECTION INPUT ;
    USE SIGNAL ;
    SHAPE ABUTMENT ;
    PORT
      LAYER M7 ;
      RECT 1016.016 2319.864 1016.048 2320.056 ;
    END
  END tx_flit[512]
  PIN tx_flit[513]
    DIRECTION INPUT ;
    USE SIGNAL ;
    SHAPE ABUTMENT ;
    PORT
      LAYER M5 ;
      RECT 1016.028 2319.864 1016.052 2320.056 ;
    END
  END tx_flit[513]
  PIN tx_flit[514]
    DIRECTION INPUT ;
    USE SIGNAL ;
    SHAPE ABUTMENT ;
    PORT
      LAYER M7 ;
      RECT 1016.464 2319.864 1016.496 2320.056 ;
    END
  END tx_flit[514]
  PIN tx_flit[515]
    DIRECTION INPUT ;
    USE SIGNAL ;
    SHAPE ABUTMENT ;
    PORT
      LAYER M5 ;
      RECT 1016.460 2319.864 1016.484 2320.056 ;
    END
  END tx_flit[515]
  PIN tx_flit[516]
    DIRECTION INPUT ;
    USE SIGNAL ;
    SHAPE ABUTMENT ;
    PORT
      LAYER M7 ;
      RECT 1016.848 2319.864 1016.880 2320.056 ;
    END
  END tx_flit[516]
  PIN tx_flit[517]
    DIRECTION INPUT ;
    USE SIGNAL ;
    SHAPE ABUTMENT ;
    PORT
      LAYER M5 ;
      RECT 1016.892 2319.864 1016.916 2320.056 ;
    END
  END tx_flit[517]
  PIN tx_flit[518]
    DIRECTION INPUT ;
    USE SIGNAL ;
    SHAPE ABUTMENT ;
    PORT
      LAYER M7 ;
      RECT 1017.296 2319.864 1017.328 2320.056 ;
    END
  END tx_flit[518]
  PIN tx_flit[519]
    DIRECTION INPUT ;
    USE SIGNAL ;
    SHAPE ABUTMENT ;
    PORT
      LAYER M5 ;
      RECT 1017.084 2319.864 1017.108 2320.056 ;
    END
  END tx_flit[519]
  PIN tx_flit[520]
    DIRECTION INPUT ;
    USE SIGNAL ;
    SHAPE ABUTMENT ;
    PORT
      LAYER M7 ;
      RECT 1017.680 2319.864 1017.712 2320.056 ;
    END
  END tx_flit[520]
  PIN tx_flit[521]
    DIRECTION INPUT ;
    USE SIGNAL ;
    SHAPE ABUTMENT ;
    PORT
      LAYER M5 ;
      RECT 1017.708 2319.864 1017.732 2320.056 ;
    END
  END tx_flit[521]
  PIN tx_flit[522]
    DIRECTION INPUT ;
    USE SIGNAL ;
    SHAPE ABUTMENT ;
    PORT
      LAYER M7 ;
      RECT 1018.128 2319.864 1018.160 2320.056 ;
    END
  END tx_flit[522]
  PIN tx_flit[523]
    DIRECTION INPUT ;
    USE SIGNAL ;
    SHAPE ABUTMENT ;
    PORT
      LAYER M5 ;
      RECT 1018.140 2319.864 1018.164 2320.056 ;
    END
  END tx_flit[523]
  PIN tx_flit[524]
    DIRECTION INPUT ;
    USE SIGNAL ;
    SHAPE ABUTMENT ;
    PORT
      LAYER M7 ;
      RECT 1018.512 2319.864 1018.544 2320.056 ;
    END
  END tx_flit[524]
  PIN tx_flit[525]
    DIRECTION INPUT ;
    USE SIGNAL ;
    SHAPE ABUTMENT ;
    PORT
      LAYER M5 ;
      RECT 1018.524 2319.864 1018.548 2320.056 ;
    END
  END tx_flit[525]
  PIN tx_flit[526]
    DIRECTION INPUT ;
    USE SIGNAL ;
    SHAPE ABUTMENT ;
    PORT
      LAYER M7 ;
      RECT 1018.960 2319.864 1018.992 2320.056 ;
    END
  END tx_flit[526]
  PIN tx_flit[527]
    DIRECTION INPUT ;
    USE SIGNAL ;
    SHAPE ABUTMENT ;
    PORT
      LAYER M5 ;
      RECT 1018.956 2319.864 1018.980 2320.056 ;
    END
  END tx_flit[527]
  PIN tx_flit[528]
    DIRECTION INPUT ;
    USE SIGNAL ;
    SHAPE ABUTMENT ;
    PORT
      LAYER M7 ;
      RECT 1019.408 2319.864 1019.440 2320.056 ;
    END
  END tx_flit[528]
  PIN tx_flit[529]
    DIRECTION INPUT ;
    USE SIGNAL ;
    SHAPE ABUTMENT ;
    PORT
      LAYER M5 ;
      RECT 1019.388 2319.864 1019.412 2320.056 ;
    END
  END tx_flit[529]
  PIN tx_flit[530]
    DIRECTION INPUT ;
    USE SIGNAL ;
    SHAPE ABUTMENT ;
    PORT
      LAYER M7 ;
      RECT 1019.792 2319.864 1019.824 2320.056 ;
    END
  END tx_flit[530]
  PIN tx_flit[531]
    DIRECTION INPUT ;
    USE SIGNAL ;
    SHAPE ABUTMENT ;
    PORT
      LAYER M5 ;
      RECT 1019.820 2319.864 1019.844 2320.056 ;
    END
  END tx_flit[531]
  PIN tx_flit[532]
    DIRECTION INPUT ;
    USE SIGNAL ;
    SHAPE ABUTMENT ;
    PORT
      LAYER M7 ;
      RECT 1020.240 2319.864 1020.272 2320.056 ;
    END
  END tx_flit[532]
  PIN tx_flit[533]
    DIRECTION INPUT ;
    USE SIGNAL ;
    SHAPE ABUTMENT ;
    PORT
      LAYER M5 ;
      RECT 1020.204 2319.864 1020.228 2320.056 ;
    END
  END tx_flit[533]
  PIN tx_flit[534]
    DIRECTION INPUT ;
    USE SIGNAL ;
    SHAPE ABUTMENT ;
    PORT
      LAYER M7 ;
      RECT 1020.624 2319.864 1020.656 2320.056 ;
    END
  END tx_flit[534]
  PIN tx_flit[535]
    DIRECTION INPUT ;
    USE SIGNAL ;
    SHAPE ABUTMENT ;
    PORT
      LAYER M5 ;
      RECT 1020.636 2319.864 1020.660 2320.056 ;
    END
  END tx_flit[535]
  PIN tx_flit[536]
    DIRECTION INPUT ;
    USE SIGNAL ;
    SHAPE ABUTMENT ;
    PORT
      LAYER M7 ;
      RECT 1021.072 2319.864 1021.104 2320.056 ;
    END
  END tx_flit[536]
  PIN tx_flit[537]
    DIRECTION INPUT ;
    USE SIGNAL ;
    SHAPE ABUTMENT ;
    PORT
      LAYER M5 ;
      RECT 1021.068 2319.864 1021.092 2320.056 ;
    END
  END tx_flit[537]
  PIN tx_flit[538]
    DIRECTION INPUT ;
    USE SIGNAL ;
    SHAPE ABUTMENT ;
    PORT
      LAYER M7 ;
      RECT 1021.456 2319.864 1021.488 2320.056 ;
    END
  END tx_flit[538]
  PIN tx_flit[539]
    DIRECTION INPUT ;
    USE SIGNAL ;
    SHAPE ABUTMENT ;
    PORT
      LAYER M5 ;
      RECT 1021.404 2319.864 1021.428 2320.056 ;
    END
  END tx_flit[539]
  PIN tx_flit[540]
    DIRECTION INPUT ;
    USE SIGNAL ;
    SHAPE ABUTMENT ;
    PORT
      LAYER M7 ;
      RECT 1021.904 2319.864 1021.936 2320.056 ;
    END
  END tx_flit[540]
  PIN tx_flit[541]
    DIRECTION INPUT ;
    USE SIGNAL ;
    SHAPE ABUTMENT ;
    PORT
      LAYER M5 ;
      RECT 1021.932 2319.864 1021.956 2320.056 ;
    END
  END tx_flit[541]
  PIN tx_flit[542]
    DIRECTION INPUT ;
    USE SIGNAL ;
    SHAPE ABUTMENT ;
    PORT
      LAYER M7 ;
      RECT 1022.288 2319.864 1022.320 2320.056 ;
    END
  END tx_flit[542]
  PIN tx_flit[543]
    DIRECTION INPUT ;
    USE SIGNAL ;
    SHAPE ABUTMENT ;
    PORT
      LAYER M5 ;
      RECT 1022.316 2319.864 1022.340 2320.056 ;
    END
  END tx_flit[543]
  PIN tx_flit[544]
    DIRECTION INPUT ;
    USE SIGNAL ;
    SHAPE ABUTMENT ;
    PORT
      LAYER M7 ;
      RECT 1022.736 2319.864 1022.768 2320.056 ;
    END
  END tx_flit[544]
  PIN tx_flit[545]
    DIRECTION INPUT ;
    USE SIGNAL ;
    SHAPE ABUTMENT ;
    PORT
      LAYER M5 ;
      RECT 1022.700 2319.864 1022.724 2320.056 ;
    END
  END tx_flit[545]
  PIN tx_flit[546]
    DIRECTION INPUT ;
    USE SIGNAL ;
    SHAPE ABUTMENT ;
    PORT
      LAYER M7 ;
      RECT 1023.120 2319.864 1023.152 2320.056 ;
    END
  END tx_flit[546]
  PIN tx_flit[547]
    DIRECTION INPUT ;
    USE SIGNAL ;
    SHAPE ABUTMENT ;
    PORT
      LAYER M5 ;
      RECT 1023.132 2319.864 1023.156 2320.056 ;
    END
  END tx_flit[547]
  PIN tx_flit[548]
    DIRECTION INPUT ;
    USE SIGNAL ;
    SHAPE ABUTMENT ;
    PORT
      LAYER M7 ;
      RECT 1023.312 2319.864 1023.344 2320.056 ;
    END
  END tx_flit[548]
  PIN tx_flit[549]
    DIRECTION INPUT ;
    USE SIGNAL ;
    SHAPE ABUTMENT ;
    PORT
      LAYER M5 ;
      RECT 1023.564 2319.864 1023.588 2320.056 ;
    END
  END tx_flit[549]
  PIN tx_flit[550]
    DIRECTION INPUT ;
    USE SIGNAL ;
    SHAPE ABUTMENT ;
    PORT
      LAYER M7 ;
      RECT 1024.336 2319.864 1024.368 2320.056 ;
    END
  END tx_flit[550]
  PIN tx_flit[551]
    DIRECTION INPUT ;
    USE SIGNAL ;
    SHAPE ABUTMENT ;
    PORT
      LAYER M5 ;
      RECT 1023.996 2319.864 1024.020 2320.056 ;
    END
  END tx_flit[551]
  PIN tx_flit[552]
    DIRECTION INPUT ;
    USE SIGNAL ;
    SHAPE ABUTMENT ;
    PORT
      LAYER M7 ;
      RECT 1024.400 2319.864 1024.432 2320.056 ;
    END
  END tx_flit[552]
  PIN tx_flit[553]
    DIRECTION INPUT ;
    USE SIGNAL ;
    SHAPE ABUTMENT ;
    PORT
      LAYER M5 ;
      RECT 1024.380 2319.864 1024.404 2320.056 ;
    END
  END tx_flit[553]
  PIN tx_flit[554]
    DIRECTION INPUT ;
    USE SIGNAL ;
    SHAPE ABUTMENT ;
    PORT
      LAYER M7 ;
      RECT 1024.784 2319.864 1024.816 2320.056 ;
    END
  END tx_flit[554]
  PIN tx_flit[555]
    DIRECTION INPUT ;
    USE SIGNAL ;
    SHAPE ABUTMENT ;
    PORT
      LAYER M5 ;
      RECT 1024.812 2319.864 1024.836 2320.056 ;
    END
  END tx_flit[555]
  PIN tx_flit[556]
    DIRECTION INPUT ;
    USE SIGNAL ;
    SHAPE ABUTMENT ;
    PORT
      LAYER M7 ;
      RECT 1025.232 2319.864 1025.264 2320.056 ;
    END
  END tx_flit[556]
  PIN tx_flit[557]
    DIRECTION INPUT ;
    USE SIGNAL ;
    SHAPE ABUTMENT ;
    PORT
      LAYER M5 ;
      RECT 1025.244 2319.864 1025.268 2320.056 ;
    END
  END tx_flit[557]
  PIN tx_flit[558]
    DIRECTION INPUT ;
    USE SIGNAL ;
    SHAPE ABUTMENT ;
    PORT
      LAYER M7 ;
      RECT 1025.616 2319.864 1025.648 2320.056 ;
    END
  END tx_flit[558]
  PIN tx_flit[559]
    DIRECTION INPUT ;
    USE SIGNAL ;
    SHAPE ABUTMENT ;
    PORT
      LAYER M5 ;
      RECT 1025.628 2319.864 1025.652 2320.056 ;
    END
  END tx_flit[559]
  PIN tx_flit[560]
    DIRECTION INPUT ;
    USE SIGNAL ;
    SHAPE ABUTMENT ;
    PORT
      LAYER M7 ;
      RECT 1026.064 2319.864 1026.096 2320.056 ;
    END
  END tx_flit[560]
  PIN tx_flit[561]
    DIRECTION INPUT ;
    USE SIGNAL ;
    SHAPE ABUTMENT ;
    PORT
      LAYER M5 ;
      RECT 1026.252 2319.864 1026.276 2320.056 ;
    END
  END tx_flit[561]
  PIN tx_flit[562]
    DIRECTION INPUT ;
    USE SIGNAL ;
    SHAPE ABUTMENT ;
    PORT
      LAYER M7 ;
      RECT 1026.448 2319.864 1026.480 2320.056 ;
    END
  END tx_flit[562]
  PIN tx_flit[563]
    DIRECTION INPUT ;
    USE SIGNAL ;
    SHAPE ABUTMENT ;
    PORT
      LAYER M5 ;
      RECT 1026.492 2319.864 1026.516 2320.056 ;
    END
  END tx_flit[563]
  PIN tx_flit[564]
    DIRECTION INPUT ;
    USE SIGNAL ;
    SHAPE ABUTMENT ;
    PORT
      LAYER M7 ;
      RECT 1026.896 2319.864 1026.928 2320.056 ;
    END
  END tx_flit[564]
  PIN tx_flit[565]
    DIRECTION INPUT ;
    USE SIGNAL ;
    SHAPE ABUTMENT ;
    PORT
      LAYER M5 ;
      RECT 1026.876 2319.864 1026.900 2320.056 ;
    END
  END tx_flit[565]
  PIN tx_flit[566]
    DIRECTION INPUT ;
    USE SIGNAL ;
    SHAPE ABUTMENT ;
    PORT
      LAYER M7 ;
      RECT 1027.280 2319.864 1027.312 2320.056 ;
    END
  END tx_flit[566]
  PIN tx_flit[567]
    DIRECTION INPUT ;
    USE SIGNAL ;
    SHAPE ABUTMENT ;
    PORT
      LAYER M5 ;
      RECT 1027.308 2319.864 1027.332 2320.056 ;
    END
  END tx_flit[567]
  PIN tx_flit[568]
    DIRECTION INPUT ;
    USE SIGNAL ;
    SHAPE ABUTMENT ;
    PORT
      LAYER M7 ;
      RECT 1027.728 2319.864 1027.760 2320.056 ;
    END
  END tx_flit[568]
  PIN tx_flit[569]
    DIRECTION INPUT ;
    USE SIGNAL ;
    SHAPE ABUTMENT ;
    PORT
      LAYER M5 ;
      RECT 1027.740 2319.864 1027.764 2320.056 ;
    END
  END tx_flit[569]
  PIN tx_flit[570]
    DIRECTION INPUT ;
    USE SIGNAL ;
    SHAPE ABUTMENT ;
    PORT
      LAYER M7 ;
      RECT 1028.112 2319.864 1028.144 2320.056 ;
    END
  END tx_flit[570]
  PIN tx_flit[571]
    DIRECTION INPUT ;
    USE SIGNAL ;
    SHAPE ABUTMENT ;
    PORT
      LAYER M5 ;
      RECT 1028.124 2319.864 1028.148 2320.056 ;
    END
  END tx_flit[571]
  PIN tx_flit[572]
    DIRECTION INPUT ;
    USE SIGNAL ;
    SHAPE ABUTMENT ;
    PORT
      LAYER M7 ;
      RECT 1028.560 2319.864 1028.592 2320.056 ;
    END
  END tx_flit[572]
  PIN tx_flit[573]
    DIRECTION INPUT ;
    USE SIGNAL ;
    SHAPE ABUTMENT ;
    PORT
      LAYER M5 ;
      RECT 1028.556 2319.864 1028.580 2320.056 ;
    END
  END tx_flit[573]
  PIN tx_flit[574]
    DIRECTION INPUT ;
    USE SIGNAL ;
    SHAPE ABUTMENT ;
    PORT
      LAYER M7 ;
      RECT 1029.008 2319.864 1029.040 2320.056 ;
    END
  END tx_flit[574]
  PIN tx_flit[575]
    DIRECTION INPUT ;
    USE SIGNAL ;
    SHAPE ABUTMENT ;
    PORT
      LAYER M5 ;
      RECT 1028.988 2319.864 1029.012 2320.056 ;
    END
  END tx_flit[575]
  PIN tx_flit[576]
    DIRECTION INPUT ;
    USE SIGNAL ;
    SHAPE ABUTMENT ;
    PORT
      LAYER M7 ;
      RECT 1029.392 2319.864 1029.424 2320.056 ;
    END
  END tx_flit[576]
  PIN tx_flit[577]
    DIRECTION INPUT ;
    USE SIGNAL ;
    SHAPE ABUTMENT ;
    PORT
      LAYER M5 ;
      RECT 1029.420 2319.864 1029.444 2320.056 ;
    END
  END tx_flit[577]
  PIN tx_flit[578]
    DIRECTION INPUT ;
    USE SIGNAL ;
    SHAPE ABUTMENT ;
    PORT
      LAYER M7 ;
      RECT 1029.840 2319.864 1029.872 2320.056 ;
    END
  END tx_flit[578]
  PIN tx_flit[579]
    DIRECTION INPUT ;
    USE SIGNAL ;
    SHAPE ABUTMENT ;
    PORT
      LAYER M5 ;
      RECT 1029.804 2319.864 1029.828 2320.056 ;
    END
  END tx_flit[579]
  PIN tx_flit[580]
    DIRECTION INPUT ;
    USE SIGNAL ;
    SHAPE ABUTMENT ;
    PORT
      LAYER M7 ;
      RECT 1030.224 2319.864 1030.256 2320.056 ;
    END
  END tx_flit[580]
  PIN tx_flit[581]
    DIRECTION INPUT ;
    USE SIGNAL ;
    SHAPE ABUTMENT ;
    PORT
      LAYER M5 ;
      RECT 1030.044 2319.864 1030.068 2320.056 ;
    END
  END tx_flit[581]
  PIN tx_flit[582]
    DIRECTION INPUT ;
    USE SIGNAL ;
    SHAPE ABUTMENT ;
    PORT
      LAYER M7 ;
      RECT 1030.672 2319.864 1030.704 2320.056 ;
    END
  END tx_flit[582]
  PIN tx_flit[583]
    DIRECTION INPUT ;
    USE SIGNAL ;
    SHAPE ABUTMENT ;
    PORT
      LAYER M5 ;
      RECT 1030.668 2319.864 1030.692 2320.056 ;
    END
  END tx_flit[583]
  PIN tx_flit[584]
    DIRECTION INPUT ;
    USE SIGNAL ;
    SHAPE ABUTMENT ;
    PORT
      LAYER M7 ;
      RECT 1031.056 2319.864 1031.088 2320.056 ;
    END
  END tx_flit[584]
  PIN tx_flit[585]
    DIRECTION INPUT ;
    USE SIGNAL ;
    SHAPE ABUTMENT ;
    PORT
      LAYER M5 ;
      RECT 1031.052 2319.864 1031.076 2320.056 ;
    END
  END tx_flit[585]
  PIN tx_flit[586]
    DIRECTION INPUT ;
    USE SIGNAL ;
    SHAPE ABUTMENT ;
    PORT
      LAYER M7 ;
      RECT 1031.504 2319.864 1031.536 2320.056 ;
    END
  END tx_flit[586]
  PIN tx_flit[587]
    DIRECTION INPUT ;
    USE SIGNAL ;
    SHAPE ABUTMENT ;
    PORT
      LAYER M5 ;
      RECT 1031.484 2319.864 1031.508 2320.056 ;
    END
  END tx_flit[587]
  PIN tx_flit[588]
    DIRECTION INPUT ;
    USE SIGNAL ;
    SHAPE ABUTMENT ;
    PORT
      LAYER M7 ;
      RECT 1031.888 2319.864 1031.920 2320.056 ;
    END
  END tx_flit[588]
  PIN tx_flit[589]
    DIRECTION INPUT ;
    USE SIGNAL ;
    SHAPE ABUTMENT ;
    PORT
      LAYER M5 ;
      RECT 1031.916 2319.864 1031.940 2320.056 ;
    END
  END tx_flit[589]
  PIN tx_flit[590]
    DIRECTION INPUT ;
    USE SIGNAL ;
    SHAPE ABUTMENT ;
    PORT
      LAYER M7 ;
      RECT 1031.952 2319.864 1031.984 2320.056 ;
    END
  END tx_flit[590]
  PIN tx_flit[591]
    DIRECTION INPUT ;
    USE SIGNAL ;
    SHAPE ABUTMENT ;
    PORT
      LAYER M5 ;
      RECT 1032.300 2319.864 1032.324 2320.056 ;
    END
  END tx_flit[591]
  PIN tx_flit[592]
    DIRECTION INPUT ;
    USE SIGNAL ;
    SHAPE ABUTMENT ;
    PORT
      LAYER M7 ;
      RECT 1032.976 2319.864 1033.008 2320.056 ;
    END
  END tx_flit[592]
  PIN tx_flit[593]
    DIRECTION INPUT ;
    USE SIGNAL ;
    SHAPE ABUTMENT ;
    PORT
      LAYER M5 ;
      RECT 1032.732 2319.864 1032.756 2320.056 ;
    END
  END tx_flit[593]
  PIN tx_flit[594]
    DIRECTION INPUT ;
    USE SIGNAL ;
    SHAPE ABUTMENT ;
    PORT
      LAYER M7 ;
      RECT 1033.168 2319.864 1033.200 2320.056 ;
    END
  END tx_flit[594]
  PIN tx_flit[595]
    DIRECTION INPUT ;
    USE SIGNAL ;
    SHAPE ABUTMENT ;
    PORT
      LAYER M5 ;
      RECT 1033.164 2319.864 1033.188 2320.056 ;
    END
  END tx_flit[595]
  PIN tx_flit[596]
    DIRECTION INPUT ;
    USE SIGNAL ;
    SHAPE ABUTMENT ;
    PORT
      LAYER M7 ;
      RECT 1033.552 2319.864 1033.584 2320.056 ;
    END
  END tx_flit[596]
  PIN rx_v
    DIRECTION OUTPUT ;
    USE SIGNAL ;
    SHAPE ABUTMENT ;
    PORT
      LAYER M7 ;
      RECT 907.856 2319.864 907.888 2320.056 ;
    END
  END rx_v
  PIN rx_flit[0]
    DIRECTION OUTPUT ;
    USE SIGNAL ;
    SHAPE ABUTMENT ;
    PORT
      LAYER M7 ;
      RECT 782.416 2319.864 782.448 2320.056 ;
    END
  END rx_flit[0]
  PIN rx_flit[1]
    DIRECTION OUTPUT ;
    USE SIGNAL ;
    SHAPE ABUTMENT ;
    PORT
      LAYER M5 ;
      RECT 782.124 2319.864 782.148 2320.056 ;
    END
  END rx_flit[1]
  PIN rx_flit[2]
    DIRECTION OUTPUT ;
    USE SIGNAL ;
    SHAPE ABUTMENT ;
    PORT
      LAYER M7 ;
      RECT 782.544 2319.864 782.576 2320.056 ;
    END
  END rx_flit[2]
  PIN rx_flit[3]
    DIRECTION OUTPUT ;
    USE SIGNAL ;
    SHAPE ABUTMENT ;
    PORT
      LAYER M5 ;
      RECT 782.556 2319.864 782.580 2320.056 ;
    END
  END rx_flit[3]
  PIN rx_flit[4]
    DIRECTION OUTPUT ;
    USE SIGNAL ;
    SHAPE ABUTMENT ;
    PORT
      LAYER M7 ;
      RECT 782.928 2319.864 782.960 2320.056 ;
    END
  END rx_flit[4]
  PIN rx_flit[5]
    DIRECTION OUTPUT ;
    USE SIGNAL ;
    SHAPE ABUTMENT ;
    PORT
      LAYER M5 ;
      RECT 782.940 2319.864 782.964 2320.056 ;
    END
  END rx_flit[5]
  PIN rx_flit[6]
    DIRECTION OUTPUT ;
    USE SIGNAL ;
    SHAPE ABUTMENT ;
    PORT
      LAYER M7 ;
      RECT 783.376 2319.864 783.408 2320.056 ;
    END
  END rx_flit[6]
  PIN rx_flit[7]
    DIRECTION OUTPUT ;
    USE SIGNAL ;
    SHAPE ABUTMENT ;
    PORT
      LAYER M5 ;
      RECT 783.372 2319.864 783.396 2320.056 ;
    END
  END rx_flit[7]
  PIN rx_flit[8]
    DIRECTION OUTPUT ;
    USE SIGNAL ;
    SHAPE ABUTMENT ;
    PORT
      LAYER M7 ;
      RECT 783.760 2319.864 783.792 2320.056 ;
    END
  END rx_flit[8]
  PIN rx_flit[9]
    DIRECTION OUTPUT ;
    USE SIGNAL ;
    SHAPE ABUTMENT ;
    PORT
      LAYER M5 ;
      RECT 783.804 2319.864 783.828 2320.056 ;
    END
  END rx_flit[9]
  PIN rx_flit[10]
    DIRECTION OUTPUT ;
    USE SIGNAL ;
    SHAPE ABUTMENT ;
    PORT
      LAYER M7 ;
      RECT 784.208 2319.864 784.240 2320.056 ;
    END
  END rx_flit[10]
  PIN rx_flit[11]
    DIRECTION OUTPUT ;
    USE SIGNAL ;
    SHAPE ABUTMENT ;
    PORT
      LAYER M5 ;
      RECT 784.332 2319.864 784.356 2320.056 ;
    END
  END rx_flit[11]
  PIN rx_flit[12]
    DIRECTION OUTPUT ;
    USE SIGNAL ;
    SHAPE ABUTMENT ;
    PORT
      LAYER M7 ;
      RECT 784.592 2319.864 784.624 2320.056 ;
    END
  END rx_flit[12]
  PIN rx_flit[13]
    DIRECTION OUTPUT ;
    USE SIGNAL ;
    SHAPE ABUTMENT ;
    PORT
      LAYER M5 ;
      RECT 784.620 2319.864 784.644 2320.056 ;
    END
  END rx_flit[13]
  PIN rx_flit[14]
    DIRECTION OUTPUT ;
    USE SIGNAL ;
    SHAPE ABUTMENT ;
    PORT
      LAYER M7 ;
      RECT 785.040 2319.864 785.072 2320.056 ;
    END
  END rx_flit[14]
  PIN rx_flit[15]
    DIRECTION OUTPUT ;
    USE SIGNAL ;
    SHAPE ABUTMENT ;
    PORT
      LAYER M5 ;
      RECT 785.052 2319.864 785.076 2320.056 ;
    END
  END rx_flit[15]
  PIN rx_flit[16]
    DIRECTION OUTPUT ;
    USE SIGNAL ;
    SHAPE ABUTMENT ;
    PORT
      LAYER M7 ;
      RECT 785.424 2319.864 785.456 2320.056 ;
    END
  END rx_flit[16]
  PIN rx_flit[17]
    DIRECTION OUTPUT ;
    USE SIGNAL ;
    SHAPE ABUTMENT ;
    PORT
      LAYER M5 ;
      RECT 785.436 2319.864 785.460 2320.056 ;
    END
  END rx_flit[17]
  PIN rx_flit[18]
    DIRECTION OUTPUT ;
    USE SIGNAL ;
    SHAPE ABUTMENT ;
    PORT
      LAYER M7 ;
      RECT 785.872 2319.864 785.904 2320.056 ;
    END
  END rx_flit[18]
  PIN rx_flit[19]
    DIRECTION OUTPUT ;
    USE SIGNAL ;
    SHAPE ABUTMENT ;
    PORT
      LAYER M5 ;
      RECT 785.868 2319.864 785.892 2320.056 ;
    END
  END rx_flit[19]
  PIN rx_flit[20]
    DIRECTION OUTPUT ;
    USE SIGNAL ;
    SHAPE ABUTMENT ;
    PORT
      LAYER M7 ;
      RECT 786.256 2319.864 786.288 2320.056 ;
    END
  END rx_flit[20]
  PIN rx_flit[21]
    DIRECTION OUTPUT ;
    USE SIGNAL ;
    SHAPE ABUTMENT ;
    PORT
      LAYER M5 ;
      RECT 786.300 2319.864 786.324 2320.056 ;
    END
  END rx_flit[21]
  PIN rx_flit[22]
    DIRECTION OUTPUT ;
    USE SIGNAL ;
    SHAPE ABUTMENT ;
    PORT
      LAYER M7 ;
      RECT 786.704 2319.864 786.736 2320.056 ;
    END
  END rx_flit[22]
  PIN rx_flit[23]
    DIRECTION OUTPUT ;
    USE SIGNAL ;
    SHAPE ABUTMENT ;
    PORT
      LAYER M5 ;
      RECT 786.684 2319.864 786.708 2320.056 ;
    END
  END rx_flit[23]
  PIN rx_flit[24]
    DIRECTION OUTPUT ;
    USE SIGNAL ;
    SHAPE ABUTMENT ;
    PORT
      LAYER M7 ;
      RECT 787.152 2319.864 787.184 2320.056 ;
    END
  END rx_flit[24]
  PIN rx_flit[25]
    DIRECTION OUTPUT ;
    USE SIGNAL ;
    SHAPE ABUTMENT ;
    PORT
      LAYER M5 ;
      RECT 787.116 2319.864 787.140 2320.056 ;
    END
  END rx_flit[25]
  PIN rx_flit[26]
    DIRECTION OUTPUT ;
    USE SIGNAL ;
    SHAPE ABUTMENT ;
    PORT
      LAYER M7 ;
      RECT 787.536 2319.864 787.568 2320.056 ;
    END
  END rx_flit[26]
  PIN rx_flit[27]
    DIRECTION OUTPUT ;
    USE SIGNAL ;
    SHAPE ABUTMENT ;
    PORT
      LAYER M5 ;
      RECT 787.548 2319.864 787.572 2320.056 ;
    END
  END rx_flit[27]
  PIN rx_flit[28]
    DIRECTION OUTPUT ;
    USE SIGNAL ;
    SHAPE ABUTMENT ;
    PORT
      LAYER M7 ;
      RECT 787.984 2319.864 788.016 2320.056 ;
    END
  END rx_flit[28]
  PIN rx_flit[29]
    DIRECTION OUTPUT ;
    USE SIGNAL ;
    SHAPE ABUTMENT ;
    PORT
      LAYER M5 ;
      RECT 787.980 2319.864 788.004 2320.056 ;
    END
  END rx_flit[29]
  PIN rx_flit[30]
    DIRECTION OUTPUT ;
    USE SIGNAL ;
    SHAPE ABUTMENT ;
    PORT
      LAYER M7 ;
      RECT 788.368 2319.864 788.400 2320.056 ;
    END
  END rx_flit[30]
  PIN rx_flit[31]
    DIRECTION OUTPUT ;
    USE SIGNAL ;
    SHAPE ABUTMENT ;
    PORT
      LAYER M5 ;
      RECT 788.124 2319.864 788.148 2320.056 ;
    END
  END rx_flit[31]
  PIN rx_flit[32]
    DIRECTION OUTPUT ;
    USE SIGNAL ;
    SHAPE ABUTMENT ;
    PORT
      LAYER M7 ;
      RECT 788.816 2319.864 788.848 2320.056 ;
    END
  END rx_flit[32]
  PIN rx_flit[33]
    DIRECTION OUTPUT ;
    USE SIGNAL ;
    SHAPE ABUTMENT ;
    PORT
      LAYER M5 ;
      RECT 788.796 2319.864 788.820 2320.056 ;
    END
  END rx_flit[33]
  PIN rx_flit[34]
    DIRECTION OUTPUT ;
    USE SIGNAL ;
    SHAPE ABUTMENT ;
    PORT
      LAYER M7 ;
      RECT 789.200 2319.864 789.232 2320.056 ;
    END
  END rx_flit[34]
  PIN rx_flit[35]
    DIRECTION OUTPUT ;
    USE SIGNAL ;
    SHAPE ABUTMENT ;
    PORT
      LAYER M5 ;
      RECT 789.228 2319.864 789.252 2320.056 ;
    END
  END rx_flit[35]
  PIN rx_flit[36]
    DIRECTION OUTPUT ;
    USE SIGNAL ;
    SHAPE ABUTMENT ;
    PORT
      LAYER M7 ;
      RECT 789.648 2319.864 789.680 2320.056 ;
    END
  END rx_flit[36]
  PIN rx_flit[37]
    DIRECTION OUTPUT ;
    USE SIGNAL ;
    SHAPE ABUTMENT ;
    PORT
      LAYER M5 ;
      RECT 789.612 2319.864 789.636 2320.056 ;
    END
  END rx_flit[37]
  PIN rx_flit[38]
    DIRECTION OUTPUT ;
    USE SIGNAL ;
    SHAPE ABUTMENT ;
    PORT
      LAYER M7 ;
      RECT 790.032 2319.864 790.064 2320.056 ;
    END
  END rx_flit[38]
  PIN rx_flit[39]
    DIRECTION OUTPUT ;
    USE SIGNAL ;
    SHAPE ABUTMENT ;
    PORT
      LAYER M5 ;
      RECT 790.044 2319.864 790.068 2320.056 ;
    END
  END rx_flit[39]
  PIN rx_flit[40]
    DIRECTION OUTPUT ;
    USE SIGNAL ;
    SHAPE ABUTMENT ;
    PORT
      LAYER M7 ;
      RECT 791.056 2319.864 791.088 2320.056 ;
    END
  END rx_flit[40]
  PIN rx_flit[41]
    DIRECTION OUTPUT ;
    USE SIGNAL ;
    SHAPE ABUTMENT ;
    PORT
      LAYER M5 ;
      RECT 790.476 2319.864 790.500 2320.056 ;
    END
  END rx_flit[41]
  PIN rx_flit[42]
    DIRECTION OUTPUT ;
    USE SIGNAL ;
    SHAPE ABUTMENT ;
    PORT
      LAYER M7 ;
      RECT 791.120 2319.864 791.152 2320.056 ;
    END
  END rx_flit[42]
  PIN rx_flit[43]
    DIRECTION OUTPUT ;
    USE SIGNAL ;
    SHAPE ABUTMENT ;
    PORT
      LAYER M5 ;
      RECT 790.860 2319.864 790.884 2320.056 ;
    END
  END rx_flit[43]
  PIN rx_flit[44]
    DIRECTION OUTPUT ;
    USE SIGNAL ;
    SHAPE ABUTMENT ;
    PORT
      LAYER M7 ;
      RECT 791.312 2319.864 791.344 2320.056 ;
    END
  END rx_flit[44]
  PIN rx_flit[45]
    DIRECTION OUTPUT ;
    USE SIGNAL ;
    SHAPE ABUTMENT ;
    PORT
      LAYER M5 ;
      RECT 791.292 2319.864 791.316 2320.056 ;
    END
  END rx_flit[45]
  PIN rx_flit[46]
    DIRECTION OUTPUT ;
    USE SIGNAL ;
    SHAPE ABUTMENT ;
    PORT
      LAYER M7 ;
      RECT 791.696 2319.864 791.728 2320.056 ;
    END
  END rx_flit[46]
  PIN rx_flit[47]
    DIRECTION OUTPUT ;
    USE SIGNAL ;
    SHAPE ABUTMENT ;
    PORT
      LAYER M5 ;
      RECT 791.724 2319.864 791.748 2320.056 ;
    END
  END rx_flit[47]
  PIN rx_flit[48]
    DIRECTION OUTPUT ;
    USE SIGNAL ;
    SHAPE ABUTMENT ;
    PORT
      LAYER M7 ;
      RECT 792.144 2319.864 792.176 2320.056 ;
    END
  END rx_flit[48]
  PIN rx_flit[49]
    DIRECTION OUTPUT ;
    USE SIGNAL ;
    SHAPE ABUTMENT ;
    PORT
      LAYER M5 ;
      RECT 792.108 2319.864 792.132 2320.056 ;
    END
  END rx_flit[49]
  PIN rx_flit[50]
    DIRECTION OUTPUT ;
    USE SIGNAL ;
    SHAPE ABUTMENT ;
    PORT
      LAYER M7 ;
      RECT 792.528 2319.864 792.560 2320.056 ;
    END
  END rx_flit[50]
  PIN rx_flit[51]
    DIRECTION OUTPUT ;
    USE SIGNAL ;
    SHAPE ABUTMENT ;
    PORT
      LAYER M5 ;
      RECT 792.444 2319.864 792.468 2320.056 ;
    END
  END rx_flit[51]
  PIN rx_flit[52]
    DIRECTION OUTPUT ;
    USE SIGNAL ;
    SHAPE ABUTMENT ;
    PORT
      LAYER M7 ;
      RECT 792.976 2319.864 793.008 2320.056 ;
    END
  END rx_flit[52]
  PIN rx_flit[53]
    DIRECTION OUTPUT ;
    USE SIGNAL ;
    SHAPE ABUTMENT ;
    PORT
      LAYER M5 ;
      RECT 792.972 2319.864 792.996 2320.056 ;
    END
  END rx_flit[53]
  PIN rx_flit[54]
    DIRECTION OUTPUT ;
    USE SIGNAL ;
    SHAPE ABUTMENT ;
    PORT
      LAYER M7 ;
      RECT 793.360 2319.864 793.392 2320.056 ;
    END
  END rx_flit[54]
  PIN rx_flit[55]
    DIRECTION OUTPUT ;
    USE SIGNAL ;
    SHAPE ABUTMENT ;
    PORT
      LAYER M5 ;
      RECT 793.404 2319.864 793.428 2320.056 ;
    END
  END rx_flit[55]
  PIN rx_flit[56]
    DIRECTION OUTPUT ;
    USE SIGNAL ;
    SHAPE ABUTMENT ;
    PORT
      LAYER M7 ;
      RECT 793.808 2319.864 793.840 2320.056 ;
    END
  END rx_flit[56]
  PIN rx_flit[57]
    DIRECTION OUTPUT ;
    USE SIGNAL ;
    SHAPE ABUTMENT ;
    PORT
      LAYER M5 ;
      RECT 793.788 2319.864 793.812 2320.056 ;
    END
  END rx_flit[57]
  PIN rx_flit[58]
    DIRECTION OUTPUT ;
    USE SIGNAL ;
    SHAPE ABUTMENT ;
    PORT
      LAYER M7 ;
      RECT 794.192 2319.864 794.224 2320.056 ;
    END
  END rx_flit[58]
  PIN rx_flit[59]
    DIRECTION OUTPUT ;
    USE SIGNAL ;
    SHAPE ABUTMENT ;
    PORT
      LAYER M5 ;
      RECT 794.220 2319.864 794.244 2320.056 ;
    END
  END rx_flit[59]
  PIN rx_flit[60]
    DIRECTION OUTPUT ;
    USE SIGNAL ;
    SHAPE ABUTMENT ;
    PORT
      LAYER M7 ;
      RECT 794.640 2319.864 794.672 2320.056 ;
    END
  END rx_flit[60]
  PIN rx_flit[61]
    DIRECTION OUTPUT ;
    USE SIGNAL ;
    SHAPE ABUTMENT ;
    PORT
      LAYER M5 ;
      RECT 794.652 2319.864 794.676 2320.056 ;
    END
  END rx_flit[61]
  PIN rx_flit[62]
    DIRECTION OUTPUT ;
    USE SIGNAL ;
    SHAPE ABUTMENT ;
    PORT
      LAYER M7 ;
      RECT 795.024 2319.864 795.056 2320.056 ;
    END
  END rx_flit[62]
  PIN rx_flit[63]
    DIRECTION OUTPUT ;
    USE SIGNAL ;
    SHAPE ABUTMENT ;
    PORT
      LAYER M5 ;
      RECT 795.036 2319.864 795.060 2320.056 ;
    END
  END rx_flit[63]
  PIN rx_flit[64]
    DIRECTION OUTPUT ;
    USE SIGNAL ;
    SHAPE ABUTMENT ;
    PORT
      LAYER M7 ;
      RECT 795.472 2319.864 795.504 2320.056 ;
    END
  END rx_flit[64]
  PIN rx_flit[65]
    DIRECTION OUTPUT ;
    USE SIGNAL ;
    SHAPE ABUTMENT ;
    PORT
      LAYER M5 ;
      RECT 795.468 2319.864 795.492 2320.056 ;
    END
  END rx_flit[65]
  PIN rx_flit[66]
    DIRECTION OUTPUT ;
    USE SIGNAL ;
    SHAPE ABUTMENT ;
    PORT
      LAYER M7 ;
      RECT 795.856 2319.864 795.888 2320.056 ;
    END
  END rx_flit[66]
  PIN rx_flit[67]
    DIRECTION OUTPUT ;
    USE SIGNAL ;
    SHAPE ABUTMENT ;
    PORT
      LAYER M5 ;
      RECT 795.900 2319.864 795.924 2320.056 ;
    END
  END rx_flit[67]
  PIN rx_flit[68]
    DIRECTION OUTPUT ;
    USE SIGNAL ;
    SHAPE ABUTMENT ;
    PORT
      LAYER M7 ;
      RECT 796.304 2319.864 796.336 2320.056 ;
    END
  END rx_flit[68]
  PIN rx_flit[69]
    DIRECTION OUTPUT ;
    USE SIGNAL ;
    SHAPE ABUTMENT ;
    PORT
      LAYER M5 ;
      RECT 796.284 2319.864 796.308 2320.056 ;
    END
  END rx_flit[69]
  PIN rx_flit[70]
    DIRECTION OUTPUT ;
    USE SIGNAL ;
    SHAPE ABUTMENT ;
    PORT
      LAYER M7 ;
      RECT 796.688 2319.864 796.720 2320.056 ;
    END
  END rx_flit[70]
  PIN rx_flit[71]
    DIRECTION OUTPUT ;
    USE SIGNAL ;
    SHAPE ABUTMENT ;
    PORT
      LAYER M5 ;
      RECT 796.716 2319.864 796.740 2320.056 ;
    END
  END rx_flit[71]
  PIN rx_flit[72]
    DIRECTION OUTPUT ;
    USE SIGNAL ;
    SHAPE ABUTMENT ;
    PORT
      LAYER M7 ;
      RECT 797.136 2319.864 797.168 2320.056 ;
    END
  END rx_flit[72]
  PIN rx_flit[73]
    DIRECTION OUTPUT ;
    USE SIGNAL ;
    SHAPE ABUTMENT ;
    PORT
      LAYER M5 ;
      RECT 797.292 2319.864 797.316 2320.056 ;
    END
  END rx_flit[73]
  PIN rx_flit[74]
    DIRECTION OUTPUT ;
    USE SIGNAL ;
    SHAPE ABUTMENT ;
    PORT
      LAYER M7 ;
      RECT 797.584 2319.864 797.616 2320.056 ;
    END
  END rx_flit[74]
  PIN rx_flit[75]
    DIRECTION OUTPUT ;
    USE SIGNAL ;
    SHAPE ABUTMENT ;
    PORT
      LAYER M5 ;
      RECT 797.580 2319.864 797.604 2320.056 ;
    END
  END rx_flit[75]
  PIN rx_flit[76]
    DIRECTION OUTPUT ;
    USE SIGNAL ;
    SHAPE ABUTMENT ;
    PORT
      LAYER M7 ;
      RECT 797.968 2319.864 798.000 2320.056 ;
    END
  END rx_flit[76]
  PIN rx_flit[77]
    DIRECTION OUTPUT ;
    USE SIGNAL ;
    SHAPE ABUTMENT ;
    PORT
      LAYER M5 ;
      RECT 797.964 2319.864 797.988 2320.056 ;
    END
  END rx_flit[77]
  PIN rx_flit[78]
    DIRECTION OUTPUT ;
    USE SIGNAL ;
    SHAPE ABUTMENT ;
    PORT
      LAYER M7 ;
      RECT 798.416 2319.864 798.448 2320.056 ;
    END
  END rx_flit[78]
  PIN rx_flit[79]
    DIRECTION OUTPUT ;
    USE SIGNAL ;
    SHAPE ABUTMENT ;
    PORT
      LAYER M5 ;
      RECT 798.396 2319.864 798.420 2320.056 ;
    END
  END rx_flit[79]
  PIN rx_flit[80]
    DIRECTION OUTPUT ;
    USE SIGNAL ;
    SHAPE ABUTMENT ;
    PORT
      LAYER M7 ;
      RECT 798.672 2319.864 798.704 2320.056 ;
    END
  END rx_flit[80]
  PIN rx_flit[81]
    DIRECTION OUTPUT ;
    USE SIGNAL ;
    SHAPE ABUTMENT ;
    PORT
      LAYER M5 ;
      RECT 798.828 2319.864 798.852 2320.056 ;
    END
  END rx_flit[81]
  PIN rx_flit[82]
    DIRECTION OUTPUT ;
    USE SIGNAL ;
    SHAPE ABUTMENT ;
    PORT
      LAYER M7 ;
      RECT 799.696 2319.864 799.728 2320.056 ;
    END
  END rx_flit[82]
  PIN rx_flit[83]
    DIRECTION OUTPUT ;
    USE SIGNAL ;
    SHAPE ABUTMENT ;
    PORT
      LAYER M5 ;
      RECT 799.212 2319.864 799.236 2320.056 ;
    END
  END rx_flit[83]
  PIN rx_flit[84]
    DIRECTION OUTPUT ;
    USE SIGNAL ;
    SHAPE ABUTMENT ;
    PORT
      LAYER M7 ;
      RECT 799.760 2319.864 799.792 2320.056 ;
    END
  END rx_flit[84]
  PIN rx_flit[85]
    DIRECTION OUTPUT ;
    USE SIGNAL ;
    SHAPE ABUTMENT ;
    PORT
      LAYER M5 ;
      RECT 799.644 2319.864 799.668 2320.056 ;
    END
  END rx_flit[85]
  PIN rx_flit[86]
    DIRECTION OUTPUT ;
    USE SIGNAL ;
    SHAPE ABUTMENT ;
    PORT
      LAYER M7 ;
      RECT 800.080 2319.864 800.112 2320.056 ;
    END
  END rx_flit[86]
  PIN rx_flit[87]
    DIRECTION OUTPUT ;
    USE SIGNAL ;
    SHAPE ABUTMENT ;
    PORT
      LAYER M5 ;
      RECT 800.076 2319.864 800.100 2320.056 ;
    END
  END rx_flit[87]
  PIN rx_flit[88]
    DIRECTION OUTPUT ;
    USE SIGNAL ;
    SHAPE ABUTMENT ;
    PORT
      LAYER M7 ;
      RECT 800.464 2319.864 800.496 2320.056 ;
    END
  END rx_flit[88]
  PIN rx_flit[89]
    DIRECTION OUTPUT ;
    USE SIGNAL ;
    SHAPE ABUTMENT ;
    PORT
      LAYER M5 ;
      RECT 800.460 2319.864 800.484 2320.056 ;
    END
  END rx_flit[89]
  PIN rx_flit[90]
    DIRECTION OUTPUT ;
    USE SIGNAL ;
    SHAPE ABUTMENT ;
    PORT
      LAYER M7 ;
      RECT 800.912 2319.864 800.944 2320.056 ;
    END
  END rx_flit[90]
  PIN rx_flit[91]
    DIRECTION OUTPUT ;
    USE SIGNAL ;
    SHAPE ABUTMENT ;
    PORT
      LAYER M5 ;
      RECT 800.892 2319.864 800.916 2320.056 ;
    END
  END rx_flit[91]
  PIN rx_flit[92]
    DIRECTION OUTPUT ;
    USE SIGNAL ;
    SHAPE ABUTMENT ;
    PORT
      LAYER M7 ;
      RECT 801.296 2319.864 801.328 2320.056 ;
    END
  END rx_flit[92]
  PIN rx_flit[93]
    DIRECTION OUTPUT ;
    USE SIGNAL ;
    SHAPE ABUTMENT ;
    PORT
      LAYER M5 ;
      RECT 801.084 2319.864 801.108 2320.056 ;
    END
  END rx_flit[93]
  PIN rx_flit[94]
    DIRECTION OUTPUT ;
    USE SIGNAL ;
    SHAPE ABUTMENT ;
    PORT
      LAYER M7 ;
      RECT 801.744 2319.864 801.776 2320.056 ;
    END
  END rx_flit[94]
  PIN rx_flit[95]
    DIRECTION OUTPUT ;
    USE SIGNAL ;
    SHAPE ABUTMENT ;
    PORT
      LAYER M5 ;
      RECT 801.708 2319.864 801.732 2320.056 ;
    END
  END rx_flit[95]
  PIN rx_flit[96]
    DIRECTION OUTPUT ;
    USE SIGNAL ;
    SHAPE ABUTMENT ;
    PORT
      LAYER M7 ;
      RECT 802.128 2319.864 802.160 2320.056 ;
    END
  END rx_flit[96]
  PIN rx_flit[97]
    DIRECTION OUTPUT ;
    USE SIGNAL ;
    SHAPE ABUTMENT ;
    PORT
      LAYER M5 ;
      RECT 802.140 2319.864 802.164 2320.056 ;
    END
  END rx_flit[97]
  PIN rx_flit[98]
    DIRECTION OUTPUT ;
    USE SIGNAL ;
    SHAPE ABUTMENT ;
    PORT
      LAYER M7 ;
      RECT 802.576 2319.864 802.608 2320.056 ;
    END
  END rx_flit[98]
  PIN rx_flit[99]
    DIRECTION OUTPUT ;
    USE SIGNAL ;
    SHAPE ABUTMENT ;
    PORT
      LAYER M5 ;
      RECT 802.572 2319.864 802.596 2320.056 ;
    END
  END rx_flit[99]
  PIN rx_flit[100]
    DIRECTION OUTPUT ;
    USE SIGNAL ;
    SHAPE ABUTMENT ;
    PORT
      LAYER M7 ;
      RECT 802.960 2319.864 802.992 2320.056 ;
    END
  END rx_flit[100]
  PIN rx_flit[101]
    DIRECTION OUTPUT ;
    USE SIGNAL ;
    SHAPE ABUTMENT ;
    PORT
      LAYER M5 ;
      RECT 803.004 2319.864 803.028 2320.056 ;
    END
  END rx_flit[101]
  PIN rx_flit[102]
    DIRECTION OUTPUT ;
    USE SIGNAL ;
    SHAPE ABUTMENT ;
    PORT
      LAYER M7 ;
      RECT 803.408 2319.864 803.440 2320.056 ;
    END
  END rx_flit[102]
  PIN rx_flit[103]
    DIRECTION OUTPUT ;
    USE SIGNAL ;
    SHAPE ABUTMENT ;
    PORT
      LAYER M5 ;
      RECT 803.388 2319.864 803.412 2320.056 ;
    END
  END rx_flit[103]
  PIN rx_flit[104]
    DIRECTION OUTPUT ;
    USE SIGNAL ;
    SHAPE ABUTMENT ;
    PORT
      LAYER M7 ;
      RECT 803.792 2319.864 803.824 2320.056 ;
    END
  END rx_flit[104]
  PIN rx_flit[105]
    DIRECTION OUTPUT ;
    USE SIGNAL ;
    SHAPE ABUTMENT ;
    PORT
      LAYER M5 ;
      RECT 803.820 2319.864 803.844 2320.056 ;
    END
  END rx_flit[105]
  PIN rx_flit[106]
    DIRECTION OUTPUT ;
    USE SIGNAL ;
    SHAPE ABUTMENT ;
    PORT
      LAYER M7 ;
      RECT 804.240 2319.864 804.272 2320.056 ;
    END
  END rx_flit[106]
  PIN rx_flit[107]
    DIRECTION OUTPUT ;
    USE SIGNAL ;
    SHAPE ABUTMENT ;
    PORT
      LAYER M5 ;
      RECT 804.252 2319.864 804.276 2320.056 ;
    END
  END rx_flit[107]
  PIN rx_flit[108]
    DIRECTION OUTPUT ;
    USE SIGNAL ;
    SHAPE ABUTMENT ;
    PORT
      LAYER M7 ;
      RECT 804.624 2319.864 804.656 2320.056 ;
    END
  END rx_flit[108]
  PIN rx_flit[109]
    DIRECTION OUTPUT ;
    USE SIGNAL ;
    SHAPE ABUTMENT ;
    PORT
      LAYER M5 ;
      RECT 804.636 2319.864 804.660 2320.056 ;
    END
  END rx_flit[109]
  PIN rx_flit[110]
    DIRECTION OUTPUT ;
    USE SIGNAL ;
    SHAPE ABUTMENT ;
    PORT
      LAYER M7 ;
      RECT 805.072 2319.864 805.104 2320.056 ;
    END
  END rx_flit[110]
  PIN rx_flit[111]
    DIRECTION OUTPUT ;
    USE SIGNAL ;
    SHAPE ABUTMENT ;
    PORT
      LAYER M5 ;
      RECT 805.068 2319.864 805.092 2320.056 ;
    END
  END rx_flit[111]
  PIN rx_flit[112]
    DIRECTION OUTPUT ;
    USE SIGNAL ;
    SHAPE ABUTMENT ;
    PORT
      LAYER M7 ;
      RECT 805.456 2319.864 805.488 2320.056 ;
    END
  END rx_flit[112]
  PIN rx_flit[113]
    DIRECTION OUTPUT ;
    USE SIGNAL ;
    SHAPE ABUTMENT ;
    PORT
      LAYER M5 ;
      RECT 805.404 2319.864 805.428 2320.056 ;
    END
  END rx_flit[113]
  PIN rx_flit[114]
    DIRECTION OUTPUT ;
    USE SIGNAL ;
    SHAPE ABUTMENT ;
    PORT
      LAYER M7 ;
      RECT 805.904 2319.864 805.936 2320.056 ;
    END
  END rx_flit[114]
  PIN rx_flit[115]
    DIRECTION OUTPUT ;
    USE SIGNAL ;
    SHAPE ABUTMENT ;
    PORT
      LAYER M5 ;
      RECT 805.932 2319.864 805.956 2320.056 ;
    END
  END rx_flit[115]
  PIN rx_flit[116]
    DIRECTION OUTPUT ;
    USE SIGNAL ;
    SHAPE ABUTMENT ;
    PORT
      LAYER M7 ;
      RECT 806.288 2319.864 806.320 2320.056 ;
    END
  END rx_flit[116]
  PIN rx_flit[117]
    DIRECTION OUTPUT ;
    USE SIGNAL ;
    SHAPE ABUTMENT ;
    PORT
      LAYER M5 ;
      RECT 806.316 2319.864 806.340 2320.056 ;
    END
  END rx_flit[117]
  PIN rx_flit[118]
    DIRECTION OUTPUT ;
    USE SIGNAL ;
    SHAPE ABUTMENT ;
    PORT
      LAYER M7 ;
      RECT 806.736 2319.864 806.768 2320.056 ;
    END
  END rx_flit[118]
  PIN rx_flit[119]
    DIRECTION OUTPUT ;
    USE SIGNAL ;
    SHAPE ABUTMENT ;
    PORT
      LAYER M5 ;
      RECT 806.748 2319.864 806.772 2320.056 ;
    END
  END rx_flit[119]
  PIN rx_flit[120]
    DIRECTION OUTPUT ;
    USE SIGNAL ;
    SHAPE ABUTMENT ;
    PORT
      LAYER M7 ;
      RECT 807.120 2319.864 807.152 2320.056 ;
    END
  END rx_flit[120]
  PIN rx_flit[121]
    DIRECTION OUTPUT ;
    USE SIGNAL ;
    SHAPE ABUTMENT ;
    PORT
      LAYER M5 ;
      RECT 807.132 2319.864 807.156 2320.056 ;
    END
  END rx_flit[121]
  PIN rx_flit[122]
    DIRECTION OUTPUT ;
    USE SIGNAL ;
    SHAPE ABUTMENT ;
    PORT
      LAYER M7 ;
      RECT 807.312 2319.864 807.344 2320.056 ;
    END
  END rx_flit[122]
  PIN rx_flit[123]
    DIRECTION OUTPUT ;
    USE SIGNAL ;
    SHAPE ABUTMENT ;
    PORT
      LAYER M5 ;
      RECT 807.564 2319.864 807.588 2320.056 ;
    END
  END rx_flit[123]
  PIN rx_flit[124]
    DIRECTION OUTPUT ;
    USE SIGNAL ;
    SHAPE ABUTMENT ;
    PORT
      LAYER M7 ;
      RECT 808.336 2319.864 808.368 2320.056 ;
    END
  END rx_flit[124]
  PIN rx_flit[125]
    DIRECTION OUTPUT ;
    USE SIGNAL ;
    SHAPE ABUTMENT ;
    PORT
      LAYER M5 ;
      RECT 807.996 2319.864 808.020 2320.056 ;
    END
  END rx_flit[125]
  PIN rx_flit[126]
    DIRECTION OUTPUT ;
    USE SIGNAL ;
    SHAPE ABUTMENT ;
    PORT
      LAYER M7 ;
      RECT 808.400 2319.864 808.432 2320.056 ;
    END
  END rx_flit[126]
  PIN rx_flit[127]
    DIRECTION OUTPUT ;
    USE SIGNAL ;
    SHAPE ABUTMENT ;
    PORT
      LAYER M5 ;
      RECT 808.428 2319.864 808.452 2320.056 ;
    END
  END rx_flit[127]
  PIN rx_flit[128]
    DIRECTION OUTPUT ;
    USE SIGNAL ;
    SHAPE ABUTMENT ;
    PORT
      LAYER M7 ;
      RECT 808.848 2319.864 808.880 2320.056 ;
    END
  END rx_flit[128]
  PIN rx_flit[129]
    DIRECTION OUTPUT ;
    USE SIGNAL ;
    SHAPE ABUTMENT ;
    PORT
      LAYER M5 ;
      RECT 808.812 2319.864 808.836 2320.056 ;
    END
  END rx_flit[129]
  PIN rx_flit[130]
    DIRECTION OUTPUT ;
    USE SIGNAL ;
    SHAPE ABUTMENT ;
    PORT
      LAYER M7 ;
      RECT 809.232 2319.864 809.264 2320.056 ;
    END
  END rx_flit[130]
  PIN rx_flit[131]
    DIRECTION OUTPUT ;
    USE SIGNAL ;
    SHAPE ABUTMENT ;
    PORT
      LAYER M5 ;
      RECT 809.244 2319.864 809.268 2320.056 ;
    END
  END rx_flit[131]
  PIN rx_flit[132]
    DIRECTION OUTPUT ;
    USE SIGNAL ;
    SHAPE ABUTMENT ;
    PORT
      LAYER M7 ;
      RECT 809.680 2319.864 809.712 2320.056 ;
    END
  END rx_flit[132]
  PIN rx_flit[133]
    DIRECTION OUTPUT ;
    USE SIGNAL ;
    SHAPE ABUTMENT ;
    PORT
      LAYER M5 ;
      RECT 809.676 2319.864 809.700 2320.056 ;
    END
  END rx_flit[133]
  PIN rx_flit[134]
    DIRECTION OUTPUT ;
    USE SIGNAL ;
    SHAPE ABUTMENT ;
    PORT
      LAYER M7 ;
      RECT 810.064 2319.864 810.096 2320.056 ;
    END
  END rx_flit[134]
  PIN rx_flit[135]
    DIRECTION OUTPUT ;
    USE SIGNAL ;
    SHAPE ABUTMENT ;
    PORT
      LAYER M5 ;
      RECT 810.252 2319.864 810.276 2320.056 ;
    END
  END rx_flit[135]
  PIN rx_flit[136]
    DIRECTION OUTPUT ;
    USE SIGNAL ;
    SHAPE ABUTMENT ;
    PORT
      LAYER M7 ;
      RECT 810.512 2319.864 810.544 2320.056 ;
    END
  END rx_flit[136]
  PIN rx_flit[137]
    DIRECTION OUTPUT ;
    USE SIGNAL ;
    SHAPE ABUTMENT ;
    PORT
      LAYER M5 ;
      RECT 810.492 2319.864 810.516 2320.056 ;
    END
  END rx_flit[137]
  PIN rx_flit[138]
    DIRECTION OUTPUT ;
    USE SIGNAL ;
    SHAPE ABUTMENT ;
    PORT
      LAYER M7 ;
      RECT 810.896 2319.864 810.928 2320.056 ;
    END
  END rx_flit[138]
  PIN rx_flit[139]
    DIRECTION OUTPUT ;
    USE SIGNAL ;
    SHAPE ABUTMENT ;
    PORT
      LAYER M5 ;
      RECT 810.924 2319.864 810.948 2320.056 ;
    END
  END rx_flit[139]
  PIN rx_flit[140]
    DIRECTION OUTPUT ;
    USE SIGNAL ;
    SHAPE ABUTMENT ;
    PORT
      LAYER M7 ;
      RECT 811.344 2319.864 811.376 2320.056 ;
    END
  END rx_flit[140]
  PIN rx_flit[141]
    DIRECTION OUTPUT ;
    USE SIGNAL ;
    SHAPE ABUTMENT ;
    PORT
      LAYER M5 ;
      RECT 811.308 2319.864 811.332 2320.056 ;
    END
  END rx_flit[141]
  PIN rx_flit[142]
    DIRECTION OUTPUT ;
    USE SIGNAL ;
    SHAPE ABUTMENT ;
    PORT
      LAYER M7 ;
      RECT 811.728 2319.864 811.760 2320.056 ;
    END
  END rx_flit[142]
  PIN rx_flit[143]
    DIRECTION OUTPUT ;
    USE SIGNAL ;
    SHAPE ABUTMENT ;
    PORT
      LAYER M5 ;
      RECT 811.740 2319.864 811.764 2320.056 ;
    END
  END rx_flit[143]
  PIN rx_flit[144]
    DIRECTION OUTPUT ;
    USE SIGNAL ;
    SHAPE ABUTMENT ;
    PORT
      LAYER M7 ;
      RECT 812.176 2319.864 812.208 2320.056 ;
    END
  END rx_flit[144]
  PIN rx_flit[145]
    DIRECTION OUTPUT ;
    USE SIGNAL ;
    SHAPE ABUTMENT ;
    PORT
      LAYER M5 ;
      RECT 812.172 2319.864 812.196 2320.056 ;
    END
  END rx_flit[145]
  PIN rx_flit[146]
    DIRECTION OUTPUT ;
    USE SIGNAL ;
    SHAPE ABUTMENT ;
    PORT
      LAYER M7 ;
      RECT 812.560 2319.864 812.592 2320.056 ;
    END
  END rx_flit[146]
  PIN rx_flit[147]
    DIRECTION OUTPUT ;
    USE SIGNAL ;
    SHAPE ABUTMENT ;
    PORT
      LAYER M5 ;
      RECT 812.556 2319.864 812.580 2320.056 ;
    END
  END rx_flit[147]
  PIN rx_flit[148]
    DIRECTION OUTPUT ;
    USE SIGNAL ;
    SHAPE ABUTMENT ;
    PORT
      LAYER M7 ;
      RECT 813.008 2319.864 813.040 2320.056 ;
    END
  END rx_flit[148]
  PIN rx_flit[149]
    DIRECTION OUTPUT ;
    USE SIGNAL ;
    SHAPE ABUTMENT ;
    PORT
      LAYER M5 ;
      RECT 812.988 2319.864 813.012 2320.056 ;
    END
  END rx_flit[149]
  PIN rx_flit[150]
    DIRECTION OUTPUT ;
    USE SIGNAL ;
    SHAPE ABUTMENT ;
    PORT
      LAYER M7 ;
      RECT 813.392 2319.864 813.424 2320.056 ;
    END
  END rx_flit[150]
  PIN rx_flit[151]
    DIRECTION OUTPUT ;
    USE SIGNAL ;
    SHAPE ABUTMENT ;
    PORT
      LAYER M5 ;
      RECT 813.420 2319.864 813.444 2320.056 ;
    END
  END rx_flit[151]
  PIN rx_flit[152]
    DIRECTION OUTPUT ;
    USE SIGNAL ;
    SHAPE ABUTMENT ;
    PORT
      LAYER M7 ;
      RECT 813.840 2319.864 813.872 2320.056 ;
    END
  END rx_flit[152]
  PIN rx_flit[153]
    DIRECTION OUTPUT ;
    USE SIGNAL ;
    SHAPE ABUTMENT ;
    PORT
      LAYER M5 ;
      RECT 813.852 2319.864 813.876 2320.056 ;
    END
  END rx_flit[153]
  PIN rx_flit[154]
    DIRECTION OUTPUT ;
    USE SIGNAL ;
    SHAPE ABUTMENT ;
    PORT
      LAYER M7 ;
      RECT 814.224 2319.864 814.256 2320.056 ;
    END
  END rx_flit[154]
  PIN rx_flit[155]
    DIRECTION OUTPUT ;
    USE SIGNAL ;
    SHAPE ABUTMENT ;
    PORT
      LAYER M5 ;
      RECT 814.044 2319.864 814.068 2320.056 ;
    END
  END rx_flit[155]
  PIN rx_flit[156]
    DIRECTION OUTPUT ;
    USE SIGNAL ;
    SHAPE ABUTMENT ;
    PORT
      LAYER M7 ;
      RECT 814.672 2319.864 814.704 2320.056 ;
    END
  END rx_flit[156]
  PIN rx_flit[157]
    DIRECTION OUTPUT ;
    USE SIGNAL ;
    SHAPE ABUTMENT ;
    PORT
      LAYER M5 ;
      RECT 814.668 2319.864 814.692 2320.056 ;
    END
  END rx_flit[157]
  PIN rx_flit[158]
    DIRECTION OUTPUT ;
    USE SIGNAL ;
    SHAPE ABUTMENT ;
    PORT
      LAYER M7 ;
      RECT 815.056 2319.864 815.088 2320.056 ;
    END
  END rx_flit[158]
  PIN rx_flit[159]
    DIRECTION OUTPUT ;
    USE SIGNAL ;
    SHAPE ABUTMENT ;
    PORT
      LAYER M5 ;
      RECT 815.100 2319.864 815.124 2320.056 ;
    END
  END rx_flit[159]
  PIN rx_flit[160]
    DIRECTION OUTPUT ;
    USE SIGNAL ;
    SHAPE ABUTMENT ;
    PORT
      LAYER M7 ;
      RECT 815.504 2319.864 815.536 2320.056 ;
    END
  END rx_flit[160]
  PIN rx_flit[161]
    DIRECTION OUTPUT ;
    USE SIGNAL ;
    SHAPE ABUTMENT ;
    PORT
      LAYER M5 ;
      RECT 815.484 2319.864 815.508 2320.056 ;
    END
  END rx_flit[161]
  PIN rx_flit[162]
    DIRECTION OUTPUT ;
    USE SIGNAL ;
    SHAPE ABUTMENT ;
    PORT
      LAYER M7 ;
      RECT 815.888 2319.864 815.920 2320.056 ;
    END
  END rx_flit[162]
  PIN rx_flit[163]
    DIRECTION OUTPUT ;
    USE SIGNAL ;
    SHAPE ABUTMENT ;
    PORT
      LAYER M5 ;
      RECT 815.916 2319.864 815.940 2320.056 ;
    END
  END rx_flit[163]
  PIN rx_flit[164]
    DIRECTION OUTPUT ;
    USE SIGNAL ;
    SHAPE ABUTMENT ;
    PORT
      LAYER M7 ;
      RECT 815.952 2319.864 815.984 2320.056 ;
    END
  END rx_flit[164]
  PIN rx_flit[165]
    DIRECTION OUTPUT ;
    USE SIGNAL ;
    SHAPE ABUTMENT ;
    PORT
      LAYER M5 ;
      RECT 816.348 2319.864 816.372 2320.056 ;
    END
  END rx_flit[165]
  PIN rx_flit[166]
    DIRECTION OUTPUT ;
    USE SIGNAL ;
    SHAPE ABUTMENT ;
    PORT
      LAYER M7 ;
      RECT 816.976 2319.864 817.008 2320.056 ;
    END
  END rx_flit[166]
  PIN rx_flit[167]
    DIRECTION OUTPUT ;
    USE SIGNAL ;
    SHAPE ABUTMENT ;
    PORT
      LAYER M5 ;
      RECT 816.732 2319.864 816.756 2320.056 ;
    END
  END rx_flit[167]
  PIN rx_flit[168]
    DIRECTION OUTPUT ;
    USE SIGNAL ;
    SHAPE ABUTMENT ;
    PORT
      LAYER M7 ;
      RECT 817.168 2319.864 817.200 2320.056 ;
    END
  END rx_flit[168]
  PIN rx_flit[169]
    DIRECTION OUTPUT ;
    USE SIGNAL ;
    SHAPE ABUTMENT ;
    PORT
      LAYER M5 ;
      RECT 817.164 2319.864 817.188 2320.056 ;
    END
  END rx_flit[169]
  PIN rx_flit[170]
    DIRECTION OUTPUT ;
    USE SIGNAL ;
    SHAPE ABUTMENT ;
    PORT
      LAYER M7 ;
      RECT 817.552 2319.864 817.584 2320.056 ;
    END
  END rx_flit[170]
  PIN rx_flit[171]
    DIRECTION OUTPUT ;
    USE SIGNAL ;
    SHAPE ABUTMENT ;
    PORT
      LAYER M5 ;
      RECT 817.596 2319.864 817.620 2320.056 ;
    END
  END rx_flit[171]
  PIN rx_flit[172]
    DIRECTION OUTPUT ;
    USE SIGNAL ;
    SHAPE ABUTMENT ;
    PORT
      LAYER M7 ;
      RECT 818.000 2319.864 818.032 2320.056 ;
    END
  END rx_flit[172]
  PIN rx_flit[173]
    DIRECTION OUTPUT ;
    USE SIGNAL ;
    SHAPE ABUTMENT ;
    PORT
      LAYER M5 ;
      RECT 817.980 2319.864 818.004 2320.056 ;
    END
  END rx_flit[173]
  PIN rx_flit[174]
    DIRECTION OUTPUT ;
    USE SIGNAL ;
    SHAPE ABUTMENT ;
    PORT
      LAYER M7 ;
      RECT 818.448 2319.864 818.480 2320.056 ;
    END
  END rx_flit[174]
  PIN rx_flit[175]
    DIRECTION OUTPUT ;
    USE SIGNAL ;
    SHAPE ABUTMENT ;
    PORT
      LAYER M5 ;
      RECT 818.364 2319.864 818.388 2320.056 ;
    END
  END rx_flit[175]
  PIN rx_flit[176]
    DIRECTION OUTPUT ;
    USE SIGNAL ;
    SHAPE ABUTMENT ;
    PORT
      LAYER M7 ;
      RECT 818.832 2319.864 818.864 2320.056 ;
    END
  END rx_flit[176]
  PIN rx_flit[177]
    DIRECTION OUTPUT ;
    USE SIGNAL ;
    SHAPE ABUTMENT ;
    PORT
      LAYER M5 ;
      RECT 818.892 2319.864 818.916 2320.056 ;
    END
  END rx_flit[177]
  PIN rx_flit[178]
    DIRECTION OUTPUT ;
    USE SIGNAL ;
    SHAPE ABUTMENT ;
    PORT
      LAYER M7 ;
      RECT 819.280 2319.864 819.312 2320.056 ;
    END
  END rx_flit[178]
  PIN rx_flit[179]
    DIRECTION OUTPUT ;
    USE SIGNAL ;
    SHAPE ABUTMENT ;
    PORT
      LAYER M5 ;
      RECT 819.276 2319.864 819.300 2320.056 ;
    END
  END rx_flit[179]
  PIN rx_flit[180]
    DIRECTION OUTPUT ;
    USE SIGNAL ;
    SHAPE ABUTMENT ;
    PORT
      LAYER M7 ;
      RECT 819.664 2319.864 819.696 2320.056 ;
    END
  END rx_flit[180]
  PIN rx_flit[181]
    DIRECTION OUTPUT ;
    USE SIGNAL ;
    SHAPE ABUTMENT ;
    PORT
      LAYER M5 ;
      RECT 819.660 2319.864 819.684 2320.056 ;
    END
  END rx_flit[181]
  PIN rx_flit[182]
    DIRECTION OUTPUT ;
    USE SIGNAL ;
    SHAPE ABUTMENT ;
    PORT
      LAYER M7 ;
      RECT 820.112 2319.864 820.144 2320.056 ;
    END
  END rx_flit[182]
  PIN rx_flit[183]
    DIRECTION OUTPUT ;
    USE SIGNAL ;
    SHAPE ABUTMENT ;
    PORT
      LAYER M5 ;
      RECT 820.092 2319.864 820.116 2320.056 ;
    END
  END rx_flit[183]
  PIN rx_flit[184]
    DIRECTION OUTPUT ;
    USE SIGNAL ;
    SHAPE ABUTMENT ;
    PORT
      LAYER M7 ;
      RECT 820.496 2319.864 820.528 2320.056 ;
    END
  END rx_flit[184]
  PIN rx_flit[185]
    DIRECTION OUTPUT ;
    USE SIGNAL ;
    SHAPE ABUTMENT ;
    PORT
      LAYER M5 ;
      RECT 820.524 2319.864 820.548 2320.056 ;
    END
  END rx_flit[185]
  PIN rx_flit[186]
    DIRECTION OUTPUT ;
    USE SIGNAL ;
    SHAPE ABUTMENT ;
    PORT
      LAYER M7 ;
      RECT 820.944 2319.864 820.976 2320.056 ;
    END
  END rx_flit[186]
  PIN rx_flit[187]
    DIRECTION OUTPUT ;
    USE SIGNAL ;
    SHAPE ABUTMENT ;
    PORT
      LAYER M5 ;
      RECT 820.908 2319.864 820.932 2320.056 ;
    END
  END rx_flit[187]
  PIN rx_flit[188]
    DIRECTION OUTPUT ;
    USE SIGNAL ;
    SHAPE ABUTMENT ;
    PORT
      LAYER M7 ;
      RECT 821.328 2319.864 821.360 2320.056 ;
    END
  END rx_flit[188]
  PIN rx_flit[189]
    DIRECTION OUTPUT ;
    USE SIGNAL ;
    SHAPE ABUTMENT ;
    PORT
      LAYER M5 ;
      RECT 821.340 2319.864 821.364 2320.056 ;
    END
  END rx_flit[189]
  PIN rx_flit[190]
    DIRECTION OUTPUT ;
    USE SIGNAL ;
    SHAPE ABUTMENT ;
    PORT
      LAYER M7 ;
      RECT 821.776 2319.864 821.808 2320.056 ;
    END
  END rx_flit[190]
  PIN rx_flit[191]
    DIRECTION OUTPUT ;
    USE SIGNAL ;
    SHAPE ABUTMENT ;
    PORT
      LAYER M5 ;
      RECT 821.772 2319.864 821.796 2320.056 ;
    END
  END rx_flit[191]
  PIN rx_flit[192]
    DIRECTION OUTPUT ;
    USE SIGNAL ;
    SHAPE ABUTMENT ;
    PORT
      LAYER M7 ;
      RECT 822.160 2319.864 822.192 2320.056 ;
    END
  END rx_flit[192]
  PIN rx_flit[193]
    DIRECTION OUTPUT ;
    USE SIGNAL ;
    SHAPE ABUTMENT ;
    PORT
      LAYER M5 ;
      RECT 822.156 2319.864 822.180 2320.056 ;
    END
  END rx_flit[193]
  PIN rx_flit[194]
    DIRECTION OUTPUT ;
    USE SIGNAL ;
    SHAPE ABUTMENT ;
    PORT
      LAYER M7 ;
      RECT 822.608 2319.864 822.640 2320.056 ;
    END
  END rx_flit[194]
  PIN rx_flit[195]
    DIRECTION OUTPUT ;
    USE SIGNAL ;
    SHAPE ABUTMENT ;
    PORT
      LAYER M5 ;
      RECT 822.588 2319.864 822.612 2320.056 ;
    END
  END rx_flit[195]
  PIN rx_flit[196]
    DIRECTION OUTPUT ;
    USE SIGNAL ;
    SHAPE ABUTMENT ;
    PORT
      LAYER M7 ;
      RECT 822.992 2319.864 823.024 2320.056 ;
    END
  END rx_flit[196]
  PIN rx_flit[197]
    DIRECTION OUTPUT ;
    USE SIGNAL ;
    SHAPE ABUTMENT ;
    PORT
      LAYER M5 ;
      RECT 823.212 2319.864 823.236 2320.056 ;
    END
  END rx_flit[197]
  PIN rx_flit[198]
    DIRECTION OUTPUT ;
    USE SIGNAL ;
    SHAPE ABUTMENT ;
    PORT
      LAYER M7 ;
      RECT 823.440 2319.864 823.472 2320.056 ;
    END
  END rx_flit[198]
  PIN rx_flit[199]
    DIRECTION OUTPUT ;
    USE SIGNAL ;
    SHAPE ABUTMENT ;
    PORT
      LAYER M5 ;
      RECT 823.404 2319.864 823.428 2320.056 ;
    END
  END rx_flit[199]
  PIN rx_flit[200]
    DIRECTION OUTPUT ;
    USE SIGNAL ;
    SHAPE ABUTMENT ;
    PORT
      LAYER M7 ;
      RECT 823.824 2319.864 823.856 2320.056 ;
    END
  END rx_flit[200]
  PIN rx_flit[201]
    DIRECTION OUTPUT ;
    USE SIGNAL ;
    SHAPE ABUTMENT ;
    PORT
      LAYER M5 ;
      RECT 823.836 2319.864 823.860 2320.056 ;
    END
  END rx_flit[201]
  PIN rx_flit[202]
    DIRECTION OUTPUT ;
    USE SIGNAL ;
    SHAPE ABUTMENT ;
    PORT
      LAYER M7 ;
      RECT 824.272 2319.864 824.304 2320.056 ;
    END
  END rx_flit[202]
  PIN rx_flit[203]
    DIRECTION OUTPUT ;
    USE SIGNAL ;
    SHAPE ABUTMENT ;
    PORT
      LAYER M5 ;
      RECT 824.268 2319.864 824.292 2320.056 ;
    END
  END rx_flit[203]
  PIN rx_flit[204]
    DIRECTION OUTPUT ;
    USE SIGNAL ;
    SHAPE ABUTMENT ;
    PORT
      LAYER M7 ;
      RECT 824.592 2319.864 824.624 2320.056 ;
    END
  END rx_flit[204]
  PIN rx_flit[205]
    DIRECTION OUTPUT ;
    USE SIGNAL ;
    SHAPE ABUTMENT ;
    PORT
      LAYER M5 ;
      RECT 824.700 2319.864 824.724 2320.056 ;
    END
  END rx_flit[205]
  PIN rx_flit[206]
    DIRECTION OUTPUT ;
    USE SIGNAL ;
    SHAPE ABUTMENT ;
    PORT
      LAYER M7 ;
      RECT 825.616 2319.864 825.648 2320.056 ;
    END
  END rx_flit[206]
  PIN rx_flit[207]
    DIRECTION OUTPUT ;
    USE SIGNAL ;
    SHAPE ABUTMENT ;
    PORT
      LAYER M5 ;
      RECT 825.084 2319.864 825.108 2320.056 ;
    END
  END rx_flit[207]
  PIN rx_flit[208]
    DIRECTION OUTPUT ;
    USE SIGNAL ;
    SHAPE ABUTMENT ;
    PORT
      LAYER M7 ;
      RECT 825.680 2319.864 825.712 2320.056 ;
    END
  END rx_flit[208]
  PIN rx_flit[209]
    DIRECTION OUTPUT ;
    USE SIGNAL ;
    SHAPE ABUTMENT ;
    PORT
      LAYER M5 ;
      RECT 825.516 2319.864 825.540 2320.056 ;
    END
  END rx_flit[209]
  PIN rx_flit[210]
    DIRECTION OUTPUT ;
    USE SIGNAL ;
    SHAPE ABUTMENT ;
    PORT
      LAYER M7 ;
      RECT 825.936 2319.864 825.968 2320.056 ;
    END
  END rx_flit[210]
  PIN rx_flit[211]
    DIRECTION OUTPUT ;
    USE SIGNAL ;
    SHAPE ABUTMENT ;
    PORT
      LAYER M5 ;
      RECT 825.948 2319.864 825.972 2320.056 ;
    END
  END rx_flit[211]
  PIN rx_flit[212]
    DIRECTION OUTPUT ;
    USE SIGNAL ;
    SHAPE ABUTMENT ;
    PORT
      LAYER M7 ;
      RECT 826.320 2319.864 826.352 2320.056 ;
    END
  END rx_flit[212]
  PIN rx_flit[213]
    DIRECTION OUTPUT ;
    USE SIGNAL ;
    SHAPE ABUTMENT ;
    PORT
      LAYER M5 ;
      RECT 826.332 2319.864 826.356 2320.056 ;
    END
  END rx_flit[213]
  PIN rx_flit[214]
    DIRECTION OUTPUT ;
    USE SIGNAL ;
    SHAPE ABUTMENT ;
    PORT
      LAYER M7 ;
      RECT 826.768 2319.864 826.800 2320.056 ;
    END
  END rx_flit[214]
  PIN rx_flit[215]
    DIRECTION OUTPUT ;
    USE SIGNAL ;
    SHAPE ABUTMENT ;
    PORT
      LAYER M5 ;
      RECT 826.764 2319.864 826.788 2320.056 ;
    END
  END rx_flit[215]
  PIN rx_flit[216]
    DIRECTION OUTPUT ;
    USE SIGNAL ;
    SHAPE ABUTMENT ;
    PORT
      LAYER M7 ;
      RECT 827.152 2319.864 827.184 2320.056 ;
    END
  END rx_flit[216]
  PIN rx_flit[217]
    DIRECTION OUTPUT ;
    USE SIGNAL ;
    SHAPE ABUTMENT ;
    PORT
      LAYER M5 ;
      RECT 827.004 2319.864 827.028 2320.056 ;
    END
  END rx_flit[217]
  PIN rx_flit[218]
    DIRECTION OUTPUT ;
    USE SIGNAL ;
    SHAPE ABUTMENT ;
    PORT
      LAYER M7 ;
      RECT 827.600 2319.864 827.632 2320.056 ;
    END
  END rx_flit[218]
  PIN rx_flit[219]
    DIRECTION OUTPUT ;
    USE SIGNAL ;
    SHAPE ABUTMENT ;
    PORT
      LAYER M5 ;
      RECT 827.580 2319.864 827.604 2320.056 ;
    END
  END rx_flit[219]
  PIN rx_flit[220]
    DIRECTION OUTPUT ;
    USE SIGNAL ;
    SHAPE ABUTMENT ;
    PORT
      LAYER M7 ;
      RECT 827.984 2319.864 828.016 2320.056 ;
    END
  END rx_flit[220]
  PIN rx_flit[221]
    DIRECTION OUTPUT ;
    USE SIGNAL ;
    SHAPE ABUTMENT ;
    PORT
      LAYER M5 ;
      RECT 828.012 2319.864 828.036 2320.056 ;
    END
  END rx_flit[221]
  PIN rx_flit[222]
    DIRECTION OUTPUT ;
    USE SIGNAL ;
    SHAPE ABUTMENT ;
    PORT
      LAYER M7 ;
      RECT 828.432 2319.864 828.464 2320.056 ;
    END
  END rx_flit[222]
  PIN rx_flit[223]
    DIRECTION OUTPUT ;
    USE SIGNAL ;
    SHAPE ABUTMENT ;
    PORT
      LAYER M5 ;
      RECT 828.444 2319.864 828.468 2320.056 ;
    END
  END rx_flit[223]
  PIN rx_flit[224]
    DIRECTION OUTPUT ;
    USE SIGNAL ;
    SHAPE ABUTMENT ;
    PORT
      LAYER M7 ;
      RECT 828.880 2319.864 828.912 2320.056 ;
    END
  END rx_flit[224]
  PIN rx_flit[225]
    DIRECTION OUTPUT ;
    USE SIGNAL ;
    SHAPE ABUTMENT ;
    PORT
      LAYER M5 ;
      RECT 828.876 2319.864 828.900 2320.056 ;
    END
  END rx_flit[225]
  PIN rx_flit[226]
    DIRECTION OUTPUT ;
    USE SIGNAL ;
    SHAPE ABUTMENT ;
    PORT
      LAYER M7 ;
      RECT 829.264 2319.864 829.296 2320.056 ;
    END
  END rx_flit[226]
  PIN rx_flit[227]
    DIRECTION OUTPUT ;
    USE SIGNAL ;
    SHAPE ABUTMENT ;
    PORT
      LAYER M5 ;
      RECT 829.260 2319.864 829.284 2320.056 ;
    END
  END rx_flit[227]
  PIN rx_flit[228]
    DIRECTION OUTPUT ;
    USE SIGNAL ;
    SHAPE ABUTMENT ;
    PORT
      LAYER M7 ;
      RECT 829.712 2319.864 829.744 2320.056 ;
    END
  END rx_flit[228]
  PIN rx_flit[229]
    DIRECTION OUTPUT ;
    USE SIGNAL ;
    SHAPE ABUTMENT ;
    PORT
      LAYER M5 ;
      RECT 829.692 2319.864 829.716 2320.056 ;
    END
  END rx_flit[229]
  PIN rx_flit[230]
    DIRECTION OUTPUT ;
    USE SIGNAL ;
    SHAPE ABUTMENT ;
    PORT
      LAYER M7 ;
      RECT 830.096 2319.864 830.128 2320.056 ;
    END
  END rx_flit[230]
  PIN rx_flit[231]
    DIRECTION OUTPUT ;
    USE SIGNAL ;
    SHAPE ABUTMENT ;
    PORT
      LAYER M5 ;
      RECT 830.124 2319.864 830.148 2320.056 ;
    END
  END rx_flit[231]
  PIN rx_flit[232]
    DIRECTION OUTPUT ;
    USE SIGNAL ;
    SHAPE ABUTMENT ;
    PORT
      LAYER M7 ;
      RECT 830.544 2319.864 830.576 2320.056 ;
    END
  END rx_flit[232]
  PIN rx_flit[233]
    DIRECTION OUTPUT ;
    USE SIGNAL ;
    SHAPE ABUTMENT ;
    PORT
      LAYER M5 ;
      RECT 830.508 2319.864 830.532 2320.056 ;
    END
  END rx_flit[233]
  PIN rx_flit[234]
    DIRECTION OUTPUT ;
    USE SIGNAL ;
    SHAPE ABUTMENT ;
    PORT
      LAYER M7 ;
      RECT 830.928 2319.864 830.960 2320.056 ;
    END
  END rx_flit[234]
  PIN rx_flit[235]
    DIRECTION OUTPUT ;
    USE SIGNAL ;
    SHAPE ABUTMENT ;
    PORT
      LAYER M5 ;
      RECT 830.940 2319.864 830.964 2320.056 ;
    END
  END rx_flit[235]
  PIN rx_flit[236]
    DIRECTION OUTPUT ;
    USE SIGNAL ;
    SHAPE ABUTMENT ;
    PORT
      LAYER M7 ;
      RECT 831.376 2319.864 831.408 2320.056 ;
    END
  END rx_flit[236]
  PIN rx_flit[237]
    DIRECTION OUTPUT ;
    USE SIGNAL ;
    SHAPE ABUTMENT ;
    PORT
      LAYER M5 ;
      RECT 831.324 2319.864 831.348 2320.056 ;
    END
  END rx_flit[237]
  PIN rx_flit[238]
    DIRECTION OUTPUT ;
    USE SIGNAL ;
    SHAPE ABUTMENT ;
    PORT
      LAYER M7 ;
      RECT 831.760 2319.864 831.792 2320.056 ;
    END
  END rx_flit[238]
  PIN rx_flit[239]
    DIRECTION OUTPUT ;
    USE SIGNAL ;
    SHAPE ABUTMENT ;
    PORT
      LAYER M5 ;
      RECT 831.852 2319.864 831.876 2320.056 ;
    END
  END rx_flit[239]
  PIN rx_flit[240]
    DIRECTION OUTPUT ;
    USE SIGNAL ;
    SHAPE ABUTMENT ;
    PORT
      LAYER M7 ;
      RECT 832.208 2319.864 832.240 2320.056 ;
    END
  END rx_flit[240]
  PIN rx_flit[241]
    DIRECTION OUTPUT ;
    USE SIGNAL ;
    SHAPE ABUTMENT ;
    PORT
      LAYER M5 ;
      RECT 832.188 2319.864 832.212 2320.056 ;
    END
  END rx_flit[241]
  PIN rx_flit[242]
    DIRECTION OUTPUT ;
    USE SIGNAL ;
    SHAPE ABUTMENT ;
    PORT
      LAYER M7 ;
      RECT 832.592 2319.864 832.624 2320.056 ;
    END
  END rx_flit[242]
  PIN rx_flit[243]
    DIRECTION OUTPUT ;
    USE SIGNAL ;
    SHAPE ABUTMENT ;
    PORT
      LAYER M5 ;
      RECT 832.620 2319.864 832.644 2320.056 ;
    END
  END rx_flit[243]
  PIN rx_flit[244]
    DIRECTION OUTPUT ;
    USE SIGNAL ;
    SHAPE ABUTMENT ;
    PORT
      LAYER M7 ;
      RECT 833.040 2319.864 833.072 2320.056 ;
    END
  END rx_flit[244]
  PIN rx_flit[245]
    DIRECTION OUTPUT ;
    USE SIGNAL ;
    SHAPE ABUTMENT ;
    PORT
      LAYER M5 ;
      RECT 833.004 2319.864 833.028 2320.056 ;
    END
  END rx_flit[245]
  PIN rx_flit[246]
    DIRECTION OUTPUT ;
    USE SIGNAL ;
    SHAPE ABUTMENT ;
    PORT
      LAYER M7 ;
      RECT 833.232 2319.864 833.264 2320.056 ;
    END
  END rx_flit[246]
  PIN rx_flit[247]
    DIRECTION OUTPUT ;
    USE SIGNAL ;
    SHAPE ABUTMENT ;
    PORT
      LAYER M5 ;
      RECT 833.436 2319.864 833.460 2320.056 ;
    END
  END rx_flit[247]
  PIN rx_flit[248]
    DIRECTION OUTPUT ;
    USE SIGNAL ;
    SHAPE ABUTMENT ;
    PORT
      LAYER M7 ;
      RECT 834.256 2319.864 834.288 2320.056 ;
    END
  END rx_flit[248]
  PIN rx_flit[249]
    DIRECTION OUTPUT ;
    USE SIGNAL ;
    SHAPE ABUTMENT ;
    PORT
      LAYER M5 ;
      RECT 833.868 2319.864 833.892 2320.056 ;
    END
  END rx_flit[249]
  PIN rx_flit[250]
    DIRECTION OUTPUT ;
    USE SIGNAL ;
    SHAPE ABUTMENT ;
    PORT
      LAYER M7 ;
      RECT 834.320 2319.864 834.352 2320.056 ;
    END
  END rx_flit[250]
  PIN rx_flit[251]
    DIRECTION OUTPUT ;
    USE SIGNAL ;
    SHAPE ABUTMENT ;
    PORT
      LAYER M5 ;
      RECT 834.300 2319.864 834.324 2320.056 ;
    END
  END rx_flit[251]
  PIN rx_flit[252]
    DIRECTION OUTPUT ;
    USE SIGNAL ;
    SHAPE ABUTMENT ;
    PORT
      LAYER M7 ;
      RECT 834.704 2319.864 834.736 2320.056 ;
    END
  END rx_flit[252]
  PIN rx_flit[253]
    DIRECTION OUTPUT ;
    USE SIGNAL ;
    SHAPE ABUTMENT ;
    PORT
      LAYER M5 ;
      RECT 834.684 2319.864 834.708 2320.056 ;
    END
  END rx_flit[253]
  PIN rx_flit[254]
    DIRECTION OUTPUT ;
    USE SIGNAL ;
    SHAPE ABUTMENT ;
    PORT
      LAYER M7 ;
      RECT 835.088 2319.864 835.120 2320.056 ;
    END
  END rx_flit[254]
  PIN rx_flit[255]
    DIRECTION OUTPUT ;
    USE SIGNAL ;
    SHAPE ABUTMENT ;
    PORT
      LAYER M5 ;
      RECT 835.116 2319.864 835.140 2320.056 ;
    END
  END rx_flit[255]
  PIN rx_flit[256]
    DIRECTION OUTPUT ;
    USE SIGNAL ;
    SHAPE ABUTMENT ;
    PORT
      LAYER M7 ;
      RECT 835.536 2319.864 835.568 2320.056 ;
    END
  END rx_flit[256]
  PIN rx_flit[257]
    DIRECTION OUTPUT ;
    USE SIGNAL ;
    SHAPE ABUTMENT ;
    PORT
      LAYER M5 ;
      RECT 835.548 2319.864 835.572 2320.056 ;
    END
  END rx_flit[257]
  PIN rx_flit[258]
    DIRECTION OUTPUT ;
    USE SIGNAL ;
    SHAPE ABUTMENT ;
    PORT
      LAYER M7 ;
      RECT 835.920 2319.864 835.952 2320.056 ;
    END
  END rx_flit[258]
  PIN rx_flit[259]
    DIRECTION OUTPUT ;
    USE SIGNAL ;
    SHAPE ABUTMENT ;
    PORT
      LAYER M5 ;
      RECT 836.172 2319.864 836.196 2320.056 ;
    END
  END rx_flit[259]
  PIN rx_flit[260]
    DIRECTION OUTPUT ;
    USE SIGNAL ;
    SHAPE ABUTMENT ;
    PORT
      LAYER M7 ;
      RECT 836.368 2319.864 836.400 2320.056 ;
    END
  END rx_flit[260]
  PIN rx_flit[261]
    DIRECTION OUTPUT ;
    USE SIGNAL ;
    SHAPE ABUTMENT ;
    PORT
      LAYER M5 ;
      RECT 836.364 2319.864 836.388 2320.056 ;
    END
  END rx_flit[261]
  PIN rx_flit[262]
    DIRECTION OUTPUT ;
    USE SIGNAL ;
    SHAPE ABUTMENT ;
    PORT
      LAYER M7 ;
      RECT 836.752 2319.864 836.784 2320.056 ;
    END
  END rx_flit[262]
  PIN rx_flit[263]
    DIRECTION OUTPUT ;
    USE SIGNAL ;
    SHAPE ABUTMENT ;
    PORT
      LAYER M5 ;
      RECT 836.796 2319.864 836.820 2320.056 ;
    END
  END rx_flit[263]
  PIN rx_flit[264]
    DIRECTION OUTPUT ;
    USE SIGNAL ;
    SHAPE ABUTMENT ;
    PORT
      LAYER M7 ;
      RECT 837.200 2319.864 837.232 2320.056 ;
    END
  END rx_flit[264]
  PIN rx_flit[265]
    DIRECTION OUTPUT ;
    USE SIGNAL ;
    SHAPE ABUTMENT ;
    PORT
      LAYER M5 ;
      RECT 837.180 2319.864 837.204 2320.056 ;
    END
  END rx_flit[265]
  PIN rx_flit[266]
    DIRECTION OUTPUT ;
    USE SIGNAL ;
    SHAPE ABUTMENT ;
    PORT
      LAYER M7 ;
      RECT 837.584 2319.864 837.616 2320.056 ;
    END
  END rx_flit[266]
  PIN rx_flit[267]
    DIRECTION OUTPUT ;
    USE SIGNAL ;
    SHAPE ABUTMENT ;
    PORT
      LAYER M5 ;
      RECT 837.612 2319.864 837.636 2320.056 ;
    END
  END rx_flit[267]
  PIN rx_flit[268]
    DIRECTION OUTPUT ;
    USE SIGNAL ;
    SHAPE ABUTMENT ;
    PORT
      LAYER M7 ;
      RECT 838.032 2319.864 838.064 2320.056 ;
    END
  END rx_flit[268]
  PIN rx_flit[269]
    DIRECTION OUTPUT ;
    USE SIGNAL ;
    SHAPE ABUTMENT ;
    PORT
      LAYER M5 ;
      RECT 838.044 2319.864 838.068 2320.056 ;
    END
  END rx_flit[269]
  PIN rx_flit[270]
    DIRECTION OUTPUT ;
    USE SIGNAL ;
    SHAPE ABUTMENT ;
    PORT
      LAYER M7 ;
      RECT 838.416 2319.864 838.448 2320.056 ;
    END
  END rx_flit[270]
  PIN rx_flit[271]
    DIRECTION OUTPUT ;
    USE SIGNAL ;
    SHAPE ABUTMENT ;
    PORT
      LAYER M5 ;
      RECT 838.428 2319.864 838.452 2320.056 ;
    END
  END rx_flit[271]
  PIN rx_flit[272]
    DIRECTION OUTPUT ;
    USE SIGNAL ;
    SHAPE ABUTMENT ;
    PORT
      LAYER M7 ;
      RECT 838.864 2319.864 838.896 2320.056 ;
    END
  END rx_flit[272]
  PIN rx_flit[273]
    DIRECTION OUTPUT ;
    USE SIGNAL ;
    SHAPE ABUTMENT ;
    PORT
      LAYER M5 ;
      RECT 838.860 2319.864 838.884 2320.056 ;
    END
  END rx_flit[273]
  PIN rx_flit[274]
    DIRECTION OUTPUT ;
    USE SIGNAL ;
    SHAPE ABUTMENT ;
    PORT
      LAYER M7 ;
      RECT 839.312 2319.864 839.344 2320.056 ;
    END
  END rx_flit[274]
  PIN rx_flit[275]
    DIRECTION OUTPUT ;
    USE SIGNAL ;
    SHAPE ABUTMENT ;
    PORT
      LAYER M5 ;
      RECT 839.292 2319.864 839.316 2320.056 ;
    END
  END rx_flit[275]
  PIN rx_flit[276]
    DIRECTION OUTPUT ;
    USE SIGNAL ;
    SHAPE ABUTMENT ;
    PORT
      LAYER M7 ;
      RECT 839.696 2319.864 839.728 2320.056 ;
    END
  END rx_flit[276]
  PIN rx_flit[277]
    DIRECTION OUTPUT ;
    USE SIGNAL ;
    SHAPE ABUTMENT ;
    PORT
      LAYER M5 ;
      RECT 839.724 2319.864 839.748 2320.056 ;
    END
  END rx_flit[277]
  PIN rx_flit[278]
    DIRECTION OUTPUT ;
    USE SIGNAL ;
    SHAPE ABUTMENT ;
    PORT
      LAYER M7 ;
      RECT 840.144 2319.864 840.176 2320.056 ;
    END
  END rx_flit[278]
  PIN rx_flit[279]
    DIRECTION OUTPUT ;
    USE SIGNAL ;
    SHAPE ABUTMENT ;
    PORT
      LAYER M5 ;
      RECT 839.964 2319.864 839.988 2320.056 ;
    END
  END rx_flit[279]
  PIN rx_flit[280]
    DIRECTION OUTPUT ;
    USE SIGNAL ;
    SHAPE ABUTMENT ;
    PORT
      LAYER M7 ;
      RECT 840.528 2319.864 840.560 2320.056 ;
    END
  END rx_flit[280]
  PIN rx_flit[281]
    DIRECTION OUTPUT ;
    USE SIGNAL ;
    SHAPE ABUTMENT ;
    PORT
      LAYER M5 ;
      RECT 840.540 2319.864 840.564 2320.056 ;
    END
  END rx_flit[281]
  PIN rx_flit[282]
    DIRECTION OUTPUT ;
    USE SIGNAL ;
    SHAPE ABUTMENT ;
    PORT
      LAYER M7 ;
      RECT 840.976 2319.864 841.008 2320.056 ;
    END
  END rx_flit[282]
  PIN rx_flit[283]
    DIRECTION OUTPUT ;
    USE SIGNAL ;
    SHAPE ABUTMENT ;
    PORT
      LAYER M5 ;
      RECT 840.972 2319.864 840.996 2320.056 ;
    END
  END rx_flit[283]
  PIN rx_flit[284]
    DIRECTION OUTPUT ;
    USE SIGNAL ;
    SHAPE ABUTMENT ;
    PORT
      LAYER M7 ;
      RECT 841.360 2319.864 841.392 2320.056 ;
    END
  END rx_flit[284]
  PIN rx_flit[285]
    DIRECTION OUTPUT ;
    USE SIGNAL ;
    SHAPE ABUTMENT ;
    PORT
      LAYER M5 ;
      RECT 841.356 2319.864 841.380 2320.056 ;
    END
  END rx_flit[285]
  PIN rx_flit[286]
    DIRECTION OUTPUT ;
    USE SIGNAL ;
    SHAPE ABUTMENT ;
    PORT
      LAYER M7 ;
      RECT 841.808 2319.864 841.840 2320.056 ;
    END
  END rx_flit[286]
  PIN rx_flit[287]
    DIRECTION OUTPUT ;
    USE SIGNAL ;
    SHAPE ABUTMENT ;
    PORT
      LAYER M5 ;
      RECT 841.788 2319.864 841.812 2320.056 ;
    END
  END rx_flit[287]
  PIN rx_flit[288]
    DIRECTION OUTPUT ;
    USE SIGNAL ;
    SHAPE ABUTMENT ;
    PORT
      LAYER M7 ;
      RECT 841.872 2319.864 841.904 2320.056 ;
    END
  END rx_flit[288]
  PIN rx_flit[289]
    DIRECTION OUTPUT ;
    USE SIGNAL ;
    SHAPE ABUTMENT ;
    PORT
      LAYER M5 ;
      RECT 842.220 2319.864 842.244 2320.056 ;
    END
  END rx_flit[289]
  PIN rx_flit[290]
    DIRECTION OUTPUT ;
    USE SIGNAL ;
    SHAPE ABUTMENT ;
    PORT
      LAYER M7 ;
      RECT 842.896 2319.864 842.928 2320.056 ;
    END
  END rx_flit[290]
  PIN rx_flit[291]
    DIRECTION OUTPUT ;
    USE SIGNAL ;
    SHAPE ABUTMENT ;
    PORT
      LAYER M5 ;
      RECT 842.604 2319.864 842.628 2320.056 ;
    END
  END rx_flit[291]
  PIN rx_flit[292]
    DIRECTION OUTPUT ;
    USE SIGNAL ;
    SHAPE ABUTMENT ;
    PORT
      LAYER M7 ;
      RECT 843.024 2319.864 843.056 2320.056 ;
    END
  END rx_flit[292]
  PIN rx_flit[293]
    DIRECTION OUTPUT ;
    USE SIGNAL ;
    SHAPE ABUTMENT ;
    PORT
      LAYER M5 ;
      RECT 843.036 2319.864 843.060 2320.056 ;
    END
  END rx_flit[293]
  PIN rx_flit[294]
    DIRECTION OUTPUT ;
    USE SIGNAL ;
    SHAPE ABUTMENT ;
    PORT
      LAYER M7 ;
      RECT 843.472 2319.864 843.504 2320.056 ;
    END
  END rx_flit[294]
  PIN rx_flit[295]
    DIRECTION OUTPUT ;
    USE SIGNAL ;
    SHAPE ABUTMENT ;
    PORT
      LAYER M5 ;
      RECT 843.468 2319.864 843.492 2320.056 ;
    END
  END rx_flit[295]
  PIN rx_flit[296]
    DIRECTION OUTPUT ;
    USE SIGNAL ;
    SHAPE ABUTMENT ;
    PORT
      LAYER M7 ;
      RECT 843.856 2319.864 843.888 2320.056 ;
    END
  END rx_flit[296]
  PIN rx_flit[297]
    DIRECTION OUTPUT ;
    USE SIGNAL ;
    SHAPE ABUTMENT ;
    PORT
      LAYER M5 ;
      RECT 843.852 2319.864 843.876 2320.056 ;
    END
  END rx_flit[297]
  PIN rx_flit[298]
    DIRECTION OUTPUT ;
    USE SIGNAL ;
    SHAPE ABUTMENT ;
    PORT
      LAYER M7 ;
      RECT 844.304 2319.864 844.336 2320.056 ;
    END
  END rx_flit[298]
  PIN rx_flit[299]
    DIRECTION OUTPUT ;
    USE SIGNAL ;
    SHAPE ABUTMENT ;
    PORT
      LAYER M5 ;
      RECT 844.284 2319.864 844.308 2320.056 ;
    END
  END rx_flit[299]
  PIN rx_flit[300]
    DIRECTION OUTPUT ;
    USE SIGNAL ;
    SHAPE ABUTMENT ;
    PORT
      LAYER M7 ;
      RECT 844.688 2319.864 844.720 2320.056 ;
    END
  END rx_flit[300]
  PIN rx_flit[301]
    DIRECTION OUTPUT ;
    USE SIGNAL ;
    SHAPE ABUTMENT ;
    PORT
      LAYER M5 ;
      RECT 844.812 2319.864 844.836 2320.056 ;
    END
  END rx_flit[301]
  PIN rx_flit[302]
    DIRECTION OUTPUT ;
    USE SIGNAL ;
    SHAPE ABUTMENT ;
    PORT
      LAYER M7 ;
      RECT 845.136 2319.864 845.168 2320.056 ;
    END
  END rx_flit[302]
  PIN rx_flit[303]
    DIRECTION OUTPUT ;
    USE SIGNAL ;
    SHAPE ABUTMENT ;
    PORT
      LAYER M5 ;
      RECT 845.148 2319.864 845.172 2320.056 ;
    END
  END rx_flit[303]
  PIN rx_flit[304]
    DIRECTION OUTPUT ;
    USE SIGNAL ;
    SHAPE ABUTMENT ;
    PORT
      LAYER M7 ;
      RECT 845.520 2319.864 845.552 2320.056 ;
    END
  END rx_flit[304]
  PIN rx_flit[305]
    DIRECTION OUTPUT ;
    USE SIGNAL ;
    SHAPE ABUTMENT ;
    PORT
      LAYER M5 ;
      RECT 845.532 2319.864 845.556 2320.056 ;
    END
  END rx_flit[305]
  PIN rx_flit[306]
    DIRECTION OUTPUT ;
    USE SIGNAL ;
    SHAPE ABUTMENT ;
    PORT
      LAYER M7 ;
      RECT 845.968 2319.864 846.000 2320.056 ;
    END
  END rx_flit[306]
  PIN rx_flit[307]
    DIRECTION OUTPUT ;
    USE SIGNAL ;
    SHAPE ABUTMENT ;
    PORT
      LAYER M5 ;
      RECT 845.964 2319.864 845.988 2320.056 ;
    END
  END rx_flit[307]
  PIN rx_flit[308]
    DIRECTION OUTPUT ;
    USE SIGNAL ;
    SHAPE ABUTMENT ;
    PORT
      LAYER M7 ;
      RECT 846.352 2319.864 846.384 2320.056 ;
    END
  END rx_flit[308]
  PIN rx_flit[309]
    DIRECTION OUTPUT ;
    USE SIGNAL ;
    SHAPE ABUTMENT ;
    PORT
      LAYER M5 ;
      RECT 846.396 2319.864 846.420 2320.056 ;
    END
  END rx_flit[309]
  PIN rx_flit[310]
    DIRECTION OUTPUT ;
    USE SIGNAL ;
    SHAPE ABUTMENT ;
    PORT
      LAYER M7 ;
      RECT 846.800 2319.864 846.832 2320.056 ;
    END
  END rx_flit[310]
  PIN rx_flit[311]
    DIRECTION OUTPUT ;
    USE SIGNAL ;
    SHAPE ABUTMENT ;
    PORT
      LAYER M5 ;
      RECT 846.780 2319.864 846.804 2320.056 ;
    END
  END rx_flit[311]
  PIN rx_flit[312]
    DIRECTION OUTPUT ;
    USE SIGNAL ;
    SHAPE ABUTMENT ;
    PORT
      LAYER M7 ;
      RECT 847.184 2319.864 847.216 2320.056 ;
    END
  END rx_flit[312]
  PIN rx_flit[313]
    DIRECTION OUTPUT ;
    USE SIGNAL ;
    SHAPE ABUTMENT ;
    PORT
      LAYER M5 ;
      RECT 847.212 2319.864 847.236 2320.056 ;
    END
  END rx_flit[313]
  PIN rx_flit[314]
    DIRECTION OUTPUT ;
    USE SIGNAL ;
    SHAPE ABUTMENT ;
    PORT
      LAYER M7 ;
      RECT 847.632 2319.864 847.664 2320.056 ;
    END
  END rx_flit[314]
  PIN rx_flit[315]
    DIRECTION OUTPUT ;
    USE SIGNAL ;
    SHAPE ABUTMENT ;
    PORT
      LAYER M5 ;
      RECT 847.644 2319.864 847.668 2320.056 ;
    END
  END rx_flit[315]
  PIN rx_flit[316]
    DIRECTION OUTPUT ;
    USE SIGNAL ;
    SHAPE ABUTMENT ;
    PORT
      LAYER M7 ;
      RECT 848.016 2319.864 848.048 2320.056 ;
    END
  END rx_flit[316]
  PIN rx_flit[317]
    DIRECTION OUTPUT ;
    USE SIGNAL ;
    SHAPE ABUTMENT ;
    PORT
      LAYER M5 ;
      RECT 848.028 2319.864 848.052 2320.056 ;
    END
  END rx_flit[317]
  PIN rx_flit[318]
    DIRECTION OUTPUT ;
    USE SIGNAL ;
    SHAPE ABUTMENT ;
    PORT
      LAYER M7 ;
      RECT 848.464 2319.864 848.496 2320.056 ;
    END
  END rx_flit[318]
  PIN rx_flit[319]
    DIRECTION OUTPUT ;
    USE SIGNAL ;
    SHAPE ABUTMENT ;
    PORT
      LAYER M5 ;
      RECT 848.460 2319.864 848.484 2320.056 ;
    END
  END rx_flit[319]
  PIN rx_flit[320]
    DIRECTION OUTPUT ;
    USE SIGNAL ;
    SHAPE ABUTMENT ;
    PORT
      LAYER M7 ;
      RECT 848.848 2319.864 848.880 2320.056 ;
    END
  END rx_flit[320]
  PIN rx_flit[321]
    DIRECTION OUTPUT ;
    USE SIGNAL ;
    SHAPE ABUTMENT ;
    PORT
      LAYER M5 ;
      RECT 849.132 2319.864 849.156 2320.056 ;
    END
  END rx_flit[321]
  PIN rx_flit[322]
    DIRECTION OUTPUT ;
    USE SIGNAL ;
    SHAPE ABUTMENT ;
    PORT
      LAYER M7 ;
      RECT 849.296 2319.864 849.328 2320.056 ;
    END
  END rx_flit[322]
  PIN rx_flit[323]
    DIRECTION OUTPUT ;
    USE SIGNAL ;
    SHAPE ABUTMENT ;
    PORT
      LAYER M5 ;
      RECT 849.276 2319.864 849.300 2320.056 ;
    END
  END rx_flit[323]
  PIN rx_flit[324]
    DIRECTION OUTPUT ;
    USE SIGNAL ;
    SHAPE ABUTMENT ;
    PORT
      LAYER M7 ;
      RECT 849.744 2319.864 849.776 2320.056 ;
    END
  END rx_flit[324]
  PIN rx_flit[325]
    DIRECTION OUTPUT ;
    USE SIGNAL ;
    SHAPE ABUTMENT ;
    PORT
      LAYER M5 ;
      RECT 849.708 2319.864 849.732 2320.056 ;
    END
  END rx_flit[325]
  PIN rx_flit[326]
    DIRECTION OUTPUT ;
    USE SIGNAL ;
    SHAPE ABUTMENT ;
    PORT
      LAYER M7 ;
      RECT 850.128 2319.864 850.160 2320.056 ;
    END
  END rx_flit[326]
  PIN rx_flit[327]
    DIRECTION OUTPUT ;
    USE SIGNAL ;
    SHAPE ABUTMENT ;
    PORT
      LAYER M5 ;
      RECT 850.140 2319.864 850.164 2320.056 ;
    END
  END rx_flit[327]
  PIN rx_flit[328]
    DIRECTION OUTPUT ;
    USE SIGNAL ;
    SHAPE ABUTMENT ;
    PORT
      LAYER M7 ;
      RECT 850.448 2319.864 850.480 2320.056 ;
    END
  END rx_flit[328]
  PIN rx_flit[329]
    DIRECTION OUTPUT ;
    USE SIGNAL ;
    SHAPE ABUTMENT ;
    PORT
      LAYER M5 ;
      RECT 850.572 2319.864 850.596 2320.056 ;
    END
  END rx_flit[329]
  PIN rx_flit[330]
    DIRECTION OUTPUT ;
    USE SIGNAL ;
    SHAPE ABUTMENT ;
    PORT
      LAYER M7 ;
      RECT 850.512 2319.864 850.544 2320.056 ;
    END
  END rx_flit[330]
  PIN rx_flit[331]
    DIRECTION OUTPUT ;
    USE SIGNAL ;
    SHAPE ABUTMENT ;
    PORT
      LAYER M5 ;
      RECT 850.956 2319.864 850.980 2320.056 ;
    END
  END rx_flit[331]
  PIN rx_flit[332]
    DIRECTION OUTPUT ;
    USE SIGNAL ;
    SHAPE ABUTMENT ;
    PORT
      LAYER M7 ;
      RECT 851.536 2319.864 851.568 2320.056 ;
    END
  END rx_flit[332]
  PIN rx_flit[333]
    DIRECTION OUTPUT ;
    USE SIGNAL ;
    SHAPE ABUTMENT ;
    PORT
      LAYER M5 ;
      RECT 851.388 2319.864 851.412 2320.056 ;
    END
  END rx_flit[333]
  PIN rx_flit[334]
    DIRECTION OUTPUT ;
    USE SIGNAL ;
    SHAPE ABUTMENT ;
    PORT
      LAYER M7 ;
      RECT 851.792 2319.864 851.824 2320.056 ;
    END
  END rx_flit[334]
  PIN rx_flit[335]
    DIRECTION OUTPUT ;
    USE SIGNAL ;
    SHAPE ABUTMENT ;
    PORT
      LAYER M5 ;
      RECT 851.820 2319.864 851.844 2320.056 ;
    END
  END rx_flit[335]
  PIN rx_flit[336]
    DIRECTION OUTPUT ;
    USE SIGNAL ;
    SHAPE ABUTMENT ;
    PORT
      LAYER M7 ;
      RECT 852.240 2319.864 852.272 2320.056 ;
    END
  END rx_flit[336]
  PIN rx_flit[337]
    DIRECTION OUTPUT ;
    USE SIGNAL ;
    SHAPE ABUTMENT ;
    PORT
      LAYER M5 ;
      RECT 852.204 2319.864 852.228 2320.056 ;
    END
  END rx_flit[337]
  PIN rx_flit[338]
    DIRECTION OUTPUT ;
    USE SIGNAL ;
    SHAPE ABUTMENT ;
    PORT
      LAYER M7 ;
      RECT 852.624 2319.864 852.656 2320.056 ;
    END
  END rx_flit[338]
  PIN rx_flit[339]
    DIRECTION OUTPUT ;
    USE SIGNAL ;
    SHAPE ABUTMENT ;
    PORT
      LAYER M5 ;
      RECT 852.636 2319.864 852.660 2320.056 ;
    END
  END rx_flit[339]
  PIN rx_flit[340]
    DIRECTION OUTPUT ;
    USE SIGNAL ;
    SHAPE ABUTMENT ;
    PORT
      LAYER M7 ;
      RECT 853.072 2319.864 853.104 2320.056 ;
    END
  END rx_flit[340]
  PIN rx_flit[341]
    DIRECTION OUTPUT ;
    USE SIGNAL ;
    SHAPE ABUTMENT ;
    PORT
      LAYER M5 ;
      RECT 852.924 2319.864 852.948 2320.056 ;
    END
  END rx_flit[341]
  PIN rx_flit[342]
    DIRECTION OUTPUT ;
    USE SIGNAL ;
    SHAPE ABUTMENT ;
    PORT
      LAYER M7 ;
      RECT 853.456 2319.864 853.488 2320.056 ;
    END
  END rx_flit[342]
  PIN rx_flit[343]
    DIRECTION OUTPUT ;
    USE SIGNAL ;
    SHAPE ABUTMENT ;
    PORT
      LAYER M5 ;
      RECT 853.452 2319.864 853.476 2320.056 ;
    END
  END rx_flit[343]
  PIN rx_flit[344]
    DIRECTION OUTPUT ;
    USE SIGNAL ;
    SHAPE ABUTMENT ;
    PORT
      LAYER M7 ;
      RECT 853.904 2319.864 853.936 2320.056 ;
    END
  END rx_flit[344]
  PIN rx_flit[345]
    DIRECTION OUTPUT ;
    USE SIGNAL ;
    SHAPE ABUTMENT ;
    PORT
      LAYER M5 ;
      RECT 853.884 2319.864 853.908 2320.056 ;
    END
  END rx_flit[345]
  PIN rx_flit[346]
    DIRECTION OUTPUT ;
    USE SIGNAL ;
    SHAPE ABUTMENT ;
    PORT
      LAYER M7 ;
      RECT 854.288 2319.864 854.320 2320.056 ;
    END
  END rx_flit[346]
  PIN rx_flit[347]
    DIRECTION OUTPUT ;
    USE SIGNAL ;
    SHAPE ABUTMENT ;
    PORT
      LAYER M5 ;
      RECT 854.316 2319.864 854.340 2320.056 ;
    END
  END rx_flit[347]
  PIN rx_flit[348]
    DIRECTION OUTPUT ;
    USE SIGNAL ;
    SHAPE ABUTMENT ;
    PORT
      LAYER M7 ;
      RECT 854.736 2319.864 854.768 2320.056 ;
    END
  END rx_flit[348]
  PIN rx_flit[349]
    DIRECTION OUTPUT ;
    USE SIGNAL ;
    SHAPE ABUTMENT ;
    PORT
      LAYER M5 ;
      RECT 854.748 2319.864 854.772 2320.056 ;
    END
  END rx_flit[349]
  PIN rx_flit[350]
    DIRECTION OUTPUT ;
    USE SIGNAL ;
    SHAPE ABUTMENT ;
    PORT
      LAYER M7 ;
      RECT 855.120 2319.864 855.152 2320.056 ;
    END
  END rx_flit[350]
  PIN rx_flit[351]
    DIRECTION OUTPUT ;
    USE SIGNAL ;
    SHAPE ABUTMENT ;
    PORT
      LAYER M5 ;
      RECT 855.132 2319.864 855.156 2320.056 ;
    END
  END rx_flit[351]
  PIN rx_flit[352]
    DIRECTION OUTPUT ;
    USE SIGNAL ;
    SHAPE ABUTMENT ;
    PORT
      LAYER M7 ;
      RECT 855.568 2319.864 855.600 2320.056 ;
    END
  END rx_flit[352]
  PIN rx_flit[353]
    DIRECTION OUTPUT ;
    USE SIGNAL ;
    SHAPE ABUTMENT ;
    PORT
      LAYER M5 ;
      RECT 855.564 2319.864 855.588 2320.056 ;
    END
  END rx_flit[353]
  PIN rx_flit[354]
    DIRECTION OUTPUT ;
    USE SIGNAL ;
    SHAPE ABUTMENT ;
    PORT
      LAYER M7 ;
      RECT 855.952 2319.864 855.984 2320.056 ;
    END
  END rx_flit[354]
  PIN rx_flit[355]
    DIRECTION OUTPUT ;
    USE SIGNAL ;
    SHAPE ABUTMENT ;
    PORT
      LAYER M5 ;
      RECT 855.996 2319.864 856.020 2320.056 ;
    END
  END rx_flit[355]
  PIN rx_flit[356]
    DIRECTION OUTPUT ;
    USE SIGNAL ;
    SHAPE ABUTMENT ;
    PORT
      LAYER M7 ;
      RECT 856.400 2319.864 856.432 2320.056 ;
    END
  END rx_flit[356]
  PIN rx_flit[357]
    DIRECTION OUTPUT ;
    USE SIGNAL ;
    SHAPE ABUTMENT ;
    PORT
      LAYER M5 ;
      RECT 856.380 2319.864 856.404 2320.056 ;
    END
  END rx_flit[357]
  PIN rx_flit[358]
    DIRECTION OUTPUT ;
    USE SIGNAL ;
    SHAPE ABUTMENT ;
    PORT
      LAYER M7 ;
      RECT 856.784 2319.864 856.816 2320.056 ;
    END
  END rx_flit[358]
  PIN rx_flit[359]
    DIRECTION OUTPUT ;
    USE SIGNAL ;
    SHAPE ABUTMENT ;
    PORT
      LAYER M5 ;
      RECT 856.812 2319.864 856.836 2320.056 ;
    END
  END rx_flit[359]
  PIN rx_flit[360]
    DIRECTION OUTPUT ;
    USE SIGNAL ;
    SHAPE ABUTMENT ;
    PORT
      LAYER M7 ;
      RECT 857.232 2319.864 857.264 2320.056 ;
    END
  END rx_flit[360]
  PIN rx_flit[361]
    DIRECTION OUTPUT ;
    USE SIGNAL ;
    SHAPE ABUTMENT ;
    PORT
      LAYER M5 ;
      RECT 857.244 2319.864 857.268 2320.056 ;
    END
  END rx_flit[361]
  PIN rx_flit[362]
    DIRECTION OUTPUT ;
    USE SIGNAL ;
    SHAPE ABUTMENT ;
    PORT
      LAYER M7 ;
      RECT 857.616 2319.864 857.648 2320.056 ;
    END
  END rx_flit[362]
  PIN rx_flit[363]
    DIRECTION OUTPUT ;
    USE SIGNAL ;
    SHAPE ABUTMENT ;
    PORT
      LAYER M5 ;
      RECT 857.772 2319.864 857.796 2320.056 ;
    END
  END rx_flit[363]
  PIN rx_flit[364]
    DIRECTION OUTPUT ;
    USE SIGNAL ;
    SHAPE ABUTMENT ;
    PORT
      LAYER M7 ;
      RECT 858.064 2319.864 858.096 2320.056 ;
    END
  END rx_flit[364]
  PIN rx_flit[365]
    DIRECTION OUTPUT ;
    USE SIGNAL ;
    SHAPE ABUTMENT ;
    PORT
      LAYER M5 ;
      RECT 858.060 2319.864 858.084 2320.056 ;
    END
  END rx_flit[365]
  PIN rx_flit[366]
    DIRECTION OUTPUT ;
    USE SIGNAL ;
    SHAPE ABUTMENT ;
    PORT
      LAYER M7 ;
      RECT 858.448 2319.864 858.480 2320.056 ;
    END
  END rx_flit[366]
  PIN rx_flit[367]
    DIRECTION OUTPUT ;
    USE SIGNAL ;
    SHAPE ABUTMENT ;
    PORT
      LAYER M5 ;
      RECT 858.492 2319.864 858.516 2320.056 ;
    END
  END rx_flit[367]
  PIN rx_flit[368]
    DIRECTION OUTPUT ;
    USE SIGNAL ;
    SHAPE ABUTMENT ;
    PORT
      LAYER M7 ;
      RECT 858.896 2319.864 858.928 2320.056 ;
    END
  END rx_flit[368]
  PIN rx_flit[369]
    DIRECTION OUTPUT ;
    USE SIGNAL ;
    SHAPE ABUTMENT ;
    PORT
      LAYER M5 ;
      RECT 858.876 2319.864 858.900 2320.056 ;
    END
  END rx_flit[369]
  PIN rx_flit[370]
    DIRECTION OUTPUT ;
    USE SIGNAL ;
    SHAPE ABUTMENT ;
    PORT
      LAYER M7 ;
      RECT 859.088 2319.864 859.120 2320.056 ;
    END
  END rx_flit[370]
  PIN rx_flit[371]
    DIRECTION OUTPUT ;
    USE SIGNAL ;
    SHAPE ABUTMENT ;
    PORT
      LAYER M5 ;
      RECT 859.308 2319.864 859.332 2320.056 ;
    END
  END rx_flit[371]
  PIN rx_flit[372]
    DIRECTION OUTPUT ;
    USE SIGNAL ;
    SHAPE ABUTMENT ;
    PORT
      LAYER M7 ;
      RECT 859.152 2319.864 859.184 2320.056 ;
    END
  END rx_flit[372]
  PIN rx_flit[373]
    DIRECTION OUTPUT ;
    USE SIGNAL ;
    SHAPE ABUTMENT ;
    PORT
      LAYER M5 ;
      RECT 859.740 2319.864 859.764 2320.056 ;
    END
  END rx_flit[373]
  PIN rx_flit[374]
    DIRECTION OUTPUT ;
    USE SIGNAL ;
    SHAPE ABUTMENT ;
    PORT
      LAYER M7 ;
      RECT 860.176 2319.864 860.208 2320.056 ;
    END
  END rx_flit[374]
  PIN rx_flit[375]
    DIRECTION OUTPUT ;
    USE SIGNAL ;
    SHAPE ABUTMENT ;
    PORT
      LAYER M5 ;
      RECT 860.172 2319.864 860.196 2320.056 ;
    END
  END rx_flit[375]
  PIN rx_flit[376]
    DIRECTION OUTPUT ;
    USE SIGNAL ;
    SHAPE ABUTMENT ;
    PORT
      LAYER M7 ;
      RECT 860.560 2319.864 860.592 2320.056 ;
    END
  END rx_flit[376]
  PIN rx_flit[377]
    DIRECTION OUTPUT ;
    USE SIGNAL ;
    SHAPE ABUTMENT ;
    PORT
      LAYER M5 ;
      RECT 860.556 2319.864 860.580 2320.056 ;
    END
  END rx_flit[377]
  PIN rx_flit[378]
    DIRECTION OUTPUT ;
    USE SIGNAL ;
    SHAPE ABUTMENT ;
    PORT
      LAYER M7 ;
      RECT 861.008 2319.864 861.040 2320.056 ;
    END
  END rx_flit[378]
  PIN rx_flit[379]
    DIRECTION OUTPUT ;
    USE SIGNAL ;
    SHAPE ABUTMENT ;
    PORT
      LAYER M5 ;
      RECT 860.988 2319.864 861.012 2320.056 ;
    END
  END rx_flit[379]
  PIN rx_flit[380]
    DIRECTION OUTPUT ;
    USE SIGNAL ;
    SHAPE ABUTMENT ;
    PORT
      LAYER M7 ;
      RECT 861.392 2319.864 861.424 2320.056 ;
    END
  END rx_flit[380]
  PIN rx_flit[381]
    DIRECTION OUTPUT ;
    USE SIGNAL ;
    SHAPE ABUTMENT ;
    PORT
      LAYER M5 ;
      RECT 861.420 2319.864 861.444 2320.056 ;
    END
  END rx_flit[381]
  PIN rx_flit[382]
    DIRECTION OUTPUT ;
    USE SIGNAL ;
    SHAPE ABUTMENT ;
    PORT
      LAYER M7 ;
      RECT 861.840 2319.864 861.872 2320.056 ;
    END
  END rx_flit[382]
  PIN rx_flit[383]
    DIRECTION OUTPUT ;
    USE SIGNAL ;
    SHAPE ABUTMENT ;
    PORT
      LAYER M5 ;
      RECT 861.564 2319.864 861.588 2320.056 ;
    END
  END rx_flit[383]
  PIN rx_flit[384]
    DIRECTION OUTPUT ;
    USE SIGNAL ;
    SHAPE ABUTMENT ;
    PORT
      LAYER M7 ;
      RECT 862.224 2319.864 862.256 2320.056 ;
    END
  END rx_flit[384]
  PIN rx_flit[385]
    DIRECTION OUTPUT ;
    USE SIGNAL ;
    SHAPE ABUTMENT ;
    PORT
      LAYER M5 ;
      RECT 862.236 2319.864 862.260 2320.056 ;
    END
  END rx_flit[385]
  PIN rx_flit[386]
    DIRECTION OUTPUT ;
    USE SIGNAL ;
    SHAPE ABUTMENT ;
    PORT
      LAYER M7 ;
      RECT 862.672 2319.864 862.704 2320.056 ;
    END
  END rx_flit[386]
  PIN rx_flit[387]
    DIRECTION OUTPUT ;
    USE SIGNAL ;
    SHAPE ABUTMENT ;
    PORT
      LAYER M5 ;
      RECT 862.668 2319.864 862.692 2320.056 ;
    END
  END rx_flit[387]
  PIN rx_flit[388]
    DIRECTION OUTPUT ;
    USE SIGNAL ;
    SHAPE ABUTMENT ;
    PORT
      LAYER M7 ;
      RECT 863.056 2319.864 863.088 2320.056 ;
    END
  END rx_flit[388]
  PIN rx_flit[389]
    DIRECTION OUTPUT ;
    USE SIGNAL ;
    SHAPE ABUTMENT ;
    PORT
      LAYER M5 ;
      RECT 863.052 2319.864 863.076 2320.056 ;
    END
  END rx_flit[389]
  PIN rx_flit[390]
    DIRECTION OUTPUT ;
    USE SIGNAL ;
    SHAPE ABUTMENT ;
    PORT
      LAYER M7 ;
      RECT 863.504 2319.864 863.536 2320.056 ;
    END
  END rx_flit[390]
  PIN rx_flit[391]
    DIRECTION OUTPUT ;
    USE SIGNAL ;
    SHAPE ABUTMENT ;
    PORT
      LAYER M5 ;
      RECT 863.484 2319.864 863.508 2320.056 ;
    END
  END rx_flit[391]
  PIN rx_flit[392]
    DIRECTION OUTPUT ;
    USE SIGNAL ;
    SHAPE ABUTMENT ;
    PORT
      LAYER M7 ;
      RECT 863.888 2319.864 863.920 2320.056 ;
    END
  END rx_flit[392]
  PIN rx_flit[393]
    DIRECTION OUTPUT ;
    USE SIGNAL ;
    SHAPE ABUTMENT ;
    PORT
      LAYER M5 ;
      RECT 863.916 2319.864 863.940 2320.056 ;
    END
  END rx_flit[393]
  PIN rx_flit[394]
    DIRECTION OUTPUT ;
    USE SIGNAL ;
    SHAPE ABUTMENT ;
    PORT
      LAYER M7 ;
      RECT 864.336 2319.864 864.368 2320.056 ;
    END
  END rx_flit[394]
  PIN rx_flit[395]
    DIRECTION OUTPUT ;
    USE SIGNAL ;
    SHAPE ABUTMENT ;
    PORT
      LAYER M5 ;
      RECT 864.300 2319.864 864.324 2320.056 ;
    END
  END rx_flit[395]
  PIN rx_flit[396]
    DIRECTION OUTPUT ;
    USE SIGNAL ;
    SHAPE ABUTMENT ;
    PORT
      LAYER M7 ;
      RECT 864.720 2319.864 864.752 2320.056 ;
    END
  END rx_flit[396]
  PIN rx_flit[397]
    DIRECTION OUTPUT ;
    USE SIGNAL ;
    SHAPE ABUTMENT ;
    PORT
      LAYER M5 ;
      RECT 864.732 2319.864 864.756 2320.056 ;
    END
  END rx_flit[397]
  PIN rx_flit[398]
    DIRECTION OUTPUT ;
    USE SIGNAL ;
    SHAPE ABUTMENT ;
    PORT
      LAYER M7 ;
      RECT 865.168 2319.864 865.200 2320.056 ;
    END
  END rx_flit[398]
  PIN rx_flit[399]
    DIRECTION OUTPUT ;
    USE SIGNAL ;
    SHAPE ABUTMENT ;
    PORT
      LAYER M5 ;
      RECT 865.164 2319.864 865.188 2320.056 ;
    END
  END rx_flit[399]
  PIN rx_flit[400]
    DIRECTION OUTPUT ;
    USE SIGNAL ;
    SHAPE ABUTMENT ;
    PORT
      LAYER M7 ;
      RECT 865.552 2319.864 865.584 2320.056 ;
    END
  END rx_flit[400]
  PIN rx_flit[401]
    DIRECTION OUTPUT ;
    USE SIGNAL ;
    SHAPE ABUTMENT ;
    PORT
      LAYER M5 ;
      RECT 865.596 2319.864 865.620 2320.056 ;
    END
  END rx_flit[401]
  PIN rx_flit[402]
    DIRECTION OUTPUT ;
    USE SIGNAL ;
    SHAPE ABUTMENT ;
    PORT
      LAYER M7 ;
      RECT 866.000 2319.864 866.032 2320.056 ;
    END
  END rx_flit[402]
  PIN rx_flit[403]
    DIRECTION OUTPUT ;
    USE SIGNAL ;
    SHAPE ABUTMENT ;
    PORT
      LAYER M5 ;
      RECT 865.884 2319.864 865.908 2320.056 ;
    END
  END rx_flit[403]
  PIN rx_flit[404]
    DIRECTION OUTPUT ;
    USE SIGNAL ;
    SHAPE ABUTMENT ;
    PORT
      LAYER M7 ;
      RECT 866.384 2319.864 866.416 2320.056 ;
    END
  END rx_flit[404]
  PIN rx_flit[405]
    DIRECTION OUTPUT ;
    USE SIGNAL ;
    SHAPE ABUTMENT ;
    PORT
      LAYER M5 ;
      RECT 866.412 2319.864 866.436 2320.056 ;
    END
  END rx_flit[405]
  PIN rx_flit[406]
    DIRECTION OUTPUT ;
    USE SIGNAL ;
    SHAPE ABUTMENT ;
    PORT
      LAYER M7 ;
      RECT 866.832 2319.864 866.864 2320.056 ;
    END
  END rx_flit[406]
  PIN rx_flit[407]
    DIRECTION OUTPUT ;
    USE SIGNAL ;
    SHAPE ABUTMENT ;
    PORT
      LAYER M5 ;
      RECT 866.844 2319.864 866.868 2320.056 ;
    END
  END rx_flit[407]
  PIN rx_flit[408]
    DIRECTION OUTPUT ;
    USE SIGNAL ;
    SHAPE ABUTMENT ;
    PORT
      LAYER M7 ;
      RECT 867.216 2319.864 867.248 2320.056 ;
    END
  END rx_flit[408]
  PIN rx_flit[409]
    DIRECTION OUTPUT ;
    USE SIGNAL ;
    SHAPE ABUTMENT ;
    PORT
      LAYER M5 ;
      RECT 867.228 2319.864 867.252 2320.056 ;
    END
  END rx_flit[409]
  PIN rx_flit[410]
    DIRECTION OUTPUT ;
    USE SIGNAL ;
    SHAPE ABUTMENT ;
    PORT
      LAYER M7 ;
      RECT 867.664 2319.864 867.696 2320.056 ;
    END
  END rx_flit[410]
  PIN rx_flit[411]
    DIRECTION OUTPUT ;
    USE SIGNAL ;
    SHAPE ABUTMENT ;
    PORT
      LAYER M5 ;
      RECT 867.660 2319.864 867.684 2320.056 ;
    END
  END rx_flit[411]
  PIN rx_flit[412]
    DIRECTION OUTPUT ;
    USE SIGNAL ;
    SHAPE ABUTMENT ;
    PORT
      LAYER M7 ;
      RECT 867.792 2319.864 867.824 2320.056 ;
    END
  END rx_flit[412]
  PIN rx_flit[413]
    DIRECTION OUTPUT ;
    USE SIGNAL ;
    SHAPE ABUTMENT ;
    PORT
      LAYER M5 ;
      RECT 868.092 2319.864 868.116 2320.056 ;
    END
  END rx_flit[413]
  PIN rx_flit[414]
    DIRECTION OUTPUT ;
    USE SIGNAL ;
    SHAPE ABUTMENT ;
    PORT
      LAYER M7 ;
      RECT 868.816 2319.864 868.848 2320.056 ;
    END
  END rx_flit[414]
  PIN rx_flit[415]
    DIRECTION OUTPUT ;
    USE SIGNAL ;
    SHAPE ABUTMENT ;
    PORT
      LAYER M5 ;
      RECT 868.476 2319.864 868.500 2320.056 ;
    END
  END rx_flit[415]
  PIN rx_flit[416]
    DIRECTION OUTPUT ;
    USE SIGNAL ;
    SHAPE ABUTMENT ;
    PORT
      LAYER M7 ;
      RECT 868.880 2319.864 868.912 2320.056 ;
    END
  END rx_flit[416]
  PIN rx_flit[417]
    DIRECTION OUTPUT ;
    USE SIGNAL ;
    SHAPE ABUTMENT ;
    PORT
      LAYER M5 ;
      RECT 868.908 2319.864 868.932 2320.056 ;
    END
  END rx_flit[417]
  PIN rx_flit[418]
    DIRECTION OUTPUT ;
    USE SIGNAL ;
    SHAPE ABUTMENT ;
    PORT
      LAYER M7 ;
      RECT 869.328 2319.864 869.360 2320.056 ;
    END
  END rx_flit[418]
  PIN rx_flit[419]
    DIRECTION OUTPUT ;
    USE SIGNAL ;
    SHAPE ABUTMENT ;
    PORT
      LAYER M5 ;
      RECT 869.340 2319.864 869.364 2320.056 ;
    END
  END rx_flit[419]
  PIN rx_flit[420]
    DIRECTION OUTPUT ;
    USE SIGNAL ;
    SHAPE ABUTMENT ;
    PORT
      LAYER M7 ;
      RECT 869.712 2319.864 869.744 2320.056 ;
    END
  END rx_flit[420]
  PIN rx_flit[421]
    DIRECTION OUTPUT ;
    USE SIGNAL ;
    SHAPE ABUTMENT ;
    PORT
      LAYER M5 ;
      RECT 869.724 2319.864 869.748 2320.056 ;
    END
  END rx_flit[421]
  PIN rx_flit[422]
    DIRECTION OUTPUT ;
    USE SIGNAL ;
    SHAPE ABUTMENT ;
    PORT
      LAYER M7 ;
      RECT 870.160 2319.864 870.192 2320.056 ;
    END
  END rx_flit[422]
  PIN rx_flit[423]
    DIRECTION OUTPUT ;
    USE SIGNAL ;
    SHAPE ABUTMENT ;
    PORT
      LAYER M5 ;
      RECT 870.156 2319.864 870.180 2320.056 ;
    END
  END rx_flit[423]
  PIN rx_flit[424]
    DIRECTION OUTPUT ;
    USE SIGNAL ;
    SHAPE ABUTMENT ;
    PORT
      LAYER M7 ;
      RECT 870.608 2319.864 870.640 2320.056 ;
    END
  END rx_flit[424]
  PIN rx_flit[425]
    DIRECTION OUTPUT ;
    USE SIGNAL ;
    SHAPE ABUTMENT ;
    PORT
      LAYER M5 ;
      RECT 870.732 2319.864 870.756 2320.056 ;
    END
  END rx_flit[425]
  PIN rx_flit[426]
    DIRECTION OUTPUT ;
    USE SIGNAL ;
    SHAPE ABUTMENT ;
    PORT
      LAYER M7 ;
      RECT 870.992 2319.864 871.024 2320.056 ;
    END
  END rx_flit[426]
  PIN rx_flit[427]
    DIRECTION OUTPUT ;
    USE SIGNAL ;
    SHAPE ABUTMENT ;
    PORT
      LAYER M5 ;
      RECT 871.020 2319.864 871.044 2320.056 ;
    END
  END rx_flit[427]
  PIN rx_flit[428]
    DIRECTION OUTPUT ;
    USE SIGNAL ;
    SHAPE ABUTMENT ;
    PORT
      LAYER M7 ;
      RECT 871.440 2319.864 871.472 2320.056 ;
    END
  END rx_flit[428]
  PIN rx_flit[429]
    DIRECTION OUTPUT ;
    USE SIGNAL ;
    SHAPE ABUTMENT ;
    PORT
      LAYER M5 ;
      RECT 871.404 2319.864 871.428 2320.056 ;
    END
  END rx_flit[429]
  PIN rx_flit[430]
    DIRECTION OUTPUT ;
    USE SIGNAL ;
    SHAPE ABUTMENT ;
    PORT
      LAYER M7 ;
      RECT 871.824 2319.864 871.856 2320.056 ;
    END
  END rx_flit[430]
  PIN rx_flit[431]
    DIRECTION OUTPUT ;
    USE SIGNAL ;
    SHAPE ABUTMENT ;
    PORT
      LAYER M5 ;
      RECT 871.836 2319.864 871.860 2320.056 ;
    END
  END rx_flit[431]
  PIN rx_flit[432]
    DIRECTION OUTPUT ;
    USE SIGNAL ;
    SHAPE ABUTMENT ;
    PORT
      LAYER M7 ;
      RECT 872.272 2319.864 872.304 2320.056 ;
    END
  END rx_flit[432]
  PIN rx_flit[433]
    DIRECTION OUTPUT ;
    USE SIGNAL ;
    SHAPE ABUTMENT ;
    PORT
      LAYER M5 ;
      RECT 872.268 2319.864 872.292 2320.056 ;
    END
  END rx_flit[433]
  PIN rx_flit[434]
    DIRECTION OUTPUT ;
    USE SIGNAL ;
    SHAPE ABUTMENT ;
    PORT
      LAYER M7 ;
      RECT 872.656 2319.864 872.688 2320.056 ;
    END
  END rx_flit[434]
  PIN rx_flit[435]
    DIRECTION OUTPUT ;
    USE SIGNAL ;
    SHAPE ABUTMENT ;
    PORT
      LAYER M5 ;
      RECT 872.652 2319.864 872.676 2320.056 ;
    END
  END rx_flit[435]
  PIN rx_flit[436]
    DIRECTION OUTPUT ;
    USE SIGNAL ;
    SHAPE ABUTMENT ;
    PORT
      LAYER M7 ;
      RECT 873.104 2319.864 873.136 2320.056 ;
    END
  END rx_flit[436]
  PIN rx_flit[437]
    DIRECTION OUTPUT ;
    USE SIGNAL ;
    SHAPE ABUTMENT ;
    PORT
      LAYER M5 ;
      RECT 873.084 2319.864 873.108 2320.056 ;
    END
  END rx_flit[437]
  PIN rx_flit[438]
    DIRECTION OUTPUT ;
    USE SIGNAL ;
    SHAPE ABUTMENT ;
    PORT
      LAYER M7 ;
      RECT 873.488 2319.864 873.520 2320.056 ;
    END
  END rx_flit[438]
  PIN rx_flit[439]
    DIRECTION OUTPUT ;
    USE SIGNAL ;
    SHAPE ABUTMENT ;
    PORT
      LAYER M5 ;
      RECT 873.516 2319.864 873.540 2320.056 ;
    END
  END rx_flit[439]
  PIN rx_flit[440]
    DIRECTION OUTPUT ;
    USE SIGNAL ;
    SHAPE ABUTMENT ;
    PORT
      LAYER M7 ;
      RECT 873.936 2319.864 873.968 2320.056 ;
    END
  END rx_flit[440]
  PIN rx_flit[441]
    DIRECTION OUTPUT ;
    USE SIGNAL ;
    SHAPE ABUTMENT ;
    PORT
      LAYER M5 ;
      RECT 873.900 2319.864 873.924 2320.056 ;
    END
  END rx_flit[441]
  PIN rx_flit[442]
    DIRECTION OUTPUT ;
    USE SIGNAL ;
    SHAPE ABUTMENT ;
    PORT
      LAYER M7 ;
      RECT 874.320 2319.864 874.352 2320.056 ;
    END
  END rx_flit[442]
  PIN rx_flit[443]
    DIRECTION OUTPUT ;
    USE SIGNAL ;
    SHAPE ABUTMENT ;
    PORT
      LAYER M5 ;
      RECT 874.332 2319.864 874.356 2320.056 ;
    END
  END rx_flit[443]
  PIN rx_flit[444]
    DIRECTION OUTPUT ;
    USE SIGNAL ;
    SHAPE ABUTMENT ;
    PORT
      LAYER M7 ;
      RECT 874.768 2319.864 874.800 2320.056 ;
    END
  END rx_flit[444]
  PIN rx_flit[445]
    DIRECTION OUTPUT ;
    USE SIGNAL ;
    SHAPE ABUTMENT ;
    PORT
      LAYER M5 ;
      RECT 874.524 2319.864 874.548 2320.056 ;
    END
  END rx_flit[445]
  PIN rx_flit[446]
    DIRECTION OUTPUT ;
    USE SIGNAL ;
    SHAPE ABUTMENT ;
    PORT
      LAYER M7 ;
      RECT 875.152 2319.864 875.184 2320.056 ;
    END
  END rx_flit[446]
  PIN rx_flit[447]
    DIRECTION OUTPUT ;
    USE SIGNAL ;
    SHAPE ABUTMENT ;
    PORT
      LAYER M5 ;
      RECT 875.148 2319.864 875.172 2320.056 ;
    END
  END rx_flit[447]
  PIN rx_flit[448]
    DIRECTION OUTPUT ;
    USE SIGNAL ;
    SHAPE ABUTMENT ;
    PORT
      LAYER M7 ;
      RECT 875.600 2319.864 875.632 2320.056 ;
    END
  END rx_flit[448]
  PIN rx_flit[449]
    DIRECTION OUTPUT ;
    USE SIGNAL ;
    SHAPE ABUTMENT ;
    PORT
      LAYER M5 ;
      RECT 875.580 2319.864 875.604 2320.056 ;
    END
  END rx_flit[449]
  PIN rx_flit[450]
    DIRECTION OUTPUT ;
    USE SIGNAL ;
    SHAPE ABUTMENT ;
    PORT
      LAYER M7 ;
      RECT 875.984 2319.864 876.016 2320.056 ;
    END
  END rx_flit[450]
  PIN rx_flit[451]
    DIRECTION OUTPUT ;
    USE SIGNAL ;
    SHAPE ABUTMENT ;
    PORT
      LAYER M5 ;
      RECT 876.012 2319.864 876.036 2320.056 ;
    END
  END rx_flit[451]
  PIN rx_flit[452]
    DIRECTION OUTPUT ;
    USE SIGNAL ;
    SHAPE ABUTMENT ;
    PORT
      LAYER M7 ;
      RECT 876.368 2319.864 876.400 2320.056 ;
    END
  END rx_flit[452]
  PIN rx_flit[453]
    DIRECTION OUTPUT ;
    USE SIGNAL ;
    SHAPE ABUTMENT ;
    PORT
      LAYER M5 ;
      RECT 876.444 2319.864 876.468 2320.056 ;
    END
  END rx_flit[453]
  PIN rx_flit[454]
    DIRECTION OUTPUT ;
    USE SIGNAL ;
    SHAPE ABUTMENT ;
    PORT
      LAYER M7 ;
      RECT 876.432 2319.864 876.464 2320.056 ;
    END
  END rx_flit[454]
  PIN rx_flit[455]
    DIRECTION OUTPUT ;
    USE SIGNAL ;
    SHAPE ABUTMENT ;
    PORT
      LAYER M5 ;
      RECT 876.828 2319.864 876.852 2320.056 ;
    END
  END rx_flit[455]
  PIN rx_flit[456]
    DIRECTION OUTPUT ;
    USE SIGNAL ;
    SHAPE ABUTMENT ;
    PORT
      LAYER M7 ;
      RECT 877.456 2319.864 877.488 2320.056 ;
    END
  END rx_flit[456]
  PIN rx_flit[457]
    DIRECTION OUTPUT ;
    USE SIGNAL ;
    SHAPE ABUTMENT ;
    PORT
      LAYER M5 ;
      RECT 877.260 2319.864 877.284 2320.056 ;
    END
  END rx_flit[457]
  PIN rx_flit[458]
    DIRECTION OUTPUT ;
    USE SIGNAL ;
    SHAPE ABUTMENT ;
    PORT
      LAYER M7 ;
      RECT 877.648 2319.864 877.680 2320.056 ;
    END
  END rx_flit[458]
  PIN rx_flit[459]
    DIRECTION OUTPUT ;
    USE SIGNAL ;
    SHAPE ABUTMENT ;
    PORT
      LAYER M5 ;
      RECT 877.692 2319.864 877.716 2320.056 ;
    END
  END rx_flit[459]
  PIN rx_flit[460]
    DIRECTION OUTPUT ;
    USE SIGNAL ;
    SHAPE ABUTMENT ;
    PORT
      LAYER M7 ;
      RECT 878.096 2319.864 878.128 2320.056 ;
    END
  END rx_flit[460]
  PIN rx_flit[461]
    DIRECTION OUTPUT ;
    USE SIGNAL ;
    SHAPE ABUTMENT ;
    PORT
      LAYER M5 ;
      RECT 878.076 2319.864 878.100 2320.056 ;
    END
  END rx_flit[461]
  PIN rx_flit[462]
    DIRECTION OUTPUT ;
    USE SIGNAL ;
    SHAPE ABUTMENT ;
    PORT
      LAYER M7 ;
      RECT 878.480 2319.864 878.512 2320.056 ;
    END
  END rx_flit[462]
  PIN rx_flit[463]
    DIRECTION OUTPUT ;
    USE SIGNAL ;
    SHAPE ABUTMENT ;
    PORT
      LAYER M5 ;
      RECT 878.508 2319.864 878.532 2320.056 ;
    END
  END rx_flit[463]
  PIN rx_flit[464]
    DIRECTION OUTPUT ;
    USE SIGNAL ;
    SHAPE ABUTMENT ;
    PORT
      LAYER M7 ;
      RECT 878.928 2319.864 878.960 2320.056 ;
    END
  END rx_flit[464]
  PIN rx_flit[465]
    DIRECTION OUTPUT ;
    USE SIGNAL ;
    SHAPE ABUTMENT ;
    PORT
      LAYER M5 ;
      RECT 878.844 2319.864 878.868 2320.056 ;
    END
  END rx_flit[465]
  PIN rx_flit[466]
    DIRECTION OUTPUT ;
    USE SIGNAL ;
    SHAPE ABUTMENT ;
    PORT
      LAYER M7 ;
      RECT 879.312 2319.864 879.344 2320.056 ;
    END
  END rx_flit[466]
  PIN rx_flit[467]
    DIRECTION OUTPUT ;
    USE SIGNAL ;
    SHAPE ABUTMENT ;
    PORT
      LAYER M5 ;
      RECT 879.372 2319.864 879.396 2320.056 ;
    END
  END rx_flit[467]
  PIN rx_flit[468]
    DIRECTION OUTPUT ;
    USE SIGNAL ;
    SHAPE ABUTMENT ;
    PORT
      LAYER M7 ;
      RECT 879.760 2319.864 879.792 2320.056 ;
    END
  END rx_flit[468]
  PIN rx_flit[469]
    DIRECTION OUTPUT ;
    USE SIGNAL ;
    SHAPE ABUTMENT ;
    PORT
      LAYER M5 ;
      RECT 879.756 2319.864 879.780 2320.056 ;
    END
  END rx_flit[469]
  PIN rx_flit[470]
    DIRECTION OUTPUT ;
    USE SIGNAL ;
    SHAPE ABUTMENT ;
    PORT
      LAYER M7 ;
      RECT 880.144 2319.864 880.176 2320.056 ;
    END
  END rx_flit[470]
  PIN rx_flit[471]
    DIRECTION OUTPUT ;
    USE SIGNAL ;
    SHAPE ABUTMENT ;
    PORT
      LAYER M5 ;
      RECT 880.188 2319.864 880.212 2320.056 ;
    END
  END rx_flit[471]
  PIN rx_flit[472]
    DIRECTION OUTPUT ;
    USE SIGNAL ;
    SHAPE ABUTMENT ;
    PORT
      LAYER M7 ;
      RECT 880.592 2319.864 880.624 2320.056 ;
    END
  END rx_flit[472]
  PIN rx_flit[473]
    DIRECTION OUTPUT ;
    USE SIGNAL ;
    SHAPE ABUTMENT ;
    PORT
      LAYER M5 ;
      RECT 880.572 2319.864 880.596 2320.056 ;
    END
  END rx_flit[473]
  PIN rx_flit[474]
    DIRECTION OUTPUT ;
    USE SIGNAL ;
    SHAPE ABUTMENT ;
    PORT
      LAYER M7 ;
      RECT 881.040 2319.864 881.072 2320.056 ;
    END
  END rx_flit[474]
  PIN rx_flit[475]
    DIRECTION OUTPUT ;
    USE SIGNAL ;
    SHAPE ABUTMENT ;
    PORT
      LAYER M5 ;
      RECT 881.004 2319.864 881.028 2320.056 ;
    END
  END rx_flit[475]
  PIN rx_flit[476]
    DIRECTION OUTPUT ;
    USE SIGNAL ;
    SHAPE ABUTMENT ;
    PORT
      LAYER M7 ;
      RECT 881.424 2319.864 881.456 2320.056 ;
    END
  END rx_flit[476]
  PIN rx_flit[477]
    DIRECTION OUTPUT ;
    USE SIGNAL ;
    SHAPE ABUTMENT ;
    PORT
      LAYER M5 ;
      RECT 881.436 2319.864 881.460 2320.056 ;
    END
  END rx_flit[477]
  PIN rx_flit[478]
    DIRECTION OUTPUT ;
    USE SIGNAL ;
    SHAPE ABUTMENT ;
    PORT
      LAYER M7 ;
      RECT 881.872 2319.864 881.904 2320.056 ;
    END
  END rx_flit[478]
  PIN rx_flit[479]
    DIRECTION OUTPUT ;
    USE SIGNAL ;
    SHAPE ABUTMENT ;
    PORT
      LAYER M5 ;
      RECT 881.868 2319.864 881.892 2320.056 ;
    END
  END rx_flit[479]
  PIN rx_flit[480]
    DIRECTION OUTPUT ;
    USE SIGNAL ;
    SHAPE ABUTMENT ;
    PORT
      LAYER M7 ;
      RECT 882.256 2319.864 882.288 2320.056 ;
    END
  END rx_flit[480]
  PIN rx_flit[481]
    DIRECTION OUTPUT ;
    USE SIGNAL ;
    SHAPE ABUTMENT ;
    PORT
      LAYER M5 ;
      RECT 882.252 2319.864 882.276 2320.056 ;
    END
  END rx_flit[481]
  PIN rx_flit[482]
    DIRECTION OUTPUT ;
    USE SIGNAL ;
    SHAPE ABUTMENT ;
    PORT
      LAYER M7 ;
      RECT 882.704 2319.864 882.736 2320.056 ;
    END
  END rx_flit[482]
  PIN rx_flit[483]
    DIRECTION OUTPUT ;
    USE SIGNAL ;
    SHAPE ABUTMENT ;
    PORT
      LAYER M5 ;
      RECT 882.684 2319.864 882.708 2320.056 ;
    END
  END rx_flit[483]
  PIN rx_flit[484]
    DIRECTION OUTPUT ;
    USE SIGNAL ;
    SHAPE ABUTMENT ;
    PORT
      LAYER M7 ;
      RECT 883.088 2319.864 883.120 2320.056 ;
    END
  END rx_flit[484]
  PIN rx_flit[485]
    DIRECTION OUTPUT ;
    USE SIGNAL ;
    SHAPE ABUTMENT ;
    PORT
      LAYER M5 ;
      RECT 883.116 2319.864 883.140 2320.056 ;
    END
  END rx_flit[485]
  PIN rx_flit[486]
    DIRECTION OUTPUT ;
    USE SIGNAL ;
    SHAPE ABUTMENT ;
    PORT
      LAYER M7 ;
      RECT 883.536 2319.864 883.568 2320.056 ;
    END
  END rx_flit[486]
  PIN rx_flit[487]
    DIRECTION OUTPUT ;
    USE SIGNAL ;
    SHAPE ABUTMENT ;
    PORT
      LAYER M5 ;
      RECT 883.692 2319.864 883.716 2320.056 ;
    END
  END rx_flit[487]
  PIN rx_flit[488]
    DIRECTION OUTPUT ;
    USE SIGNAL ;
    SHAPE ABUTMENT ;
    PORT
      LAYER M7 ;
      RECT 883.920 2319.864 883.952 2320.056 ;
    END
  END rx_flit[488]
  PIN rx_flit[489]
    DIRECTION OUTPUT ;
    USE SIGNAL ;
    SHAPE ABUTMENT ;
    PORT
      LAYER M5 ;
      RECT 883.932 2319.864 883.956 2320.056 ;
    END
  END rx_flit[489]
  PIN rx_flit[490]
    DIRECTION OUTPUT ;
    USE SIGNAL ;
    SHAPE ABUTMENT ;
    PORT
      LAYER M7 ;
      RECT 884.368 2319.864 884.400 2320.056 ;
    END
  END rx_flit[490]
  PIN rx_flit[491]
    DIRECTION OUTPUT ;
    USE SIGNAL ;
    SHAPE ABUTMENT ;
    PORT
      LAYER M5 ;
      RECT 884.364 2319.864 884.388 2320.056 ;
    END
  END rx_flit[491]
  PIN rx_flit[492]
    DIRECTION OUTPUT ;
    USE SIGNAL ;
    SHAPE ABUTMENT ;
    PORT
      LAYER M7 ;
      RECT 884.752 2319.864 884.784 2320.056 ;
    END
  END rx_flit[492]
  PIN rx_flit[493]
    DIRECTION OUTPUT ;
    USE SIGNAL ;
    SHAPE ABUTMENT ;
    PORT
      LAYER M5 ;
      RECT 884.748 2319.864 884.772 2320.056 ;
    END
  END rx_flit[493]
  PIN rx_flit[494]
    DIRECTION OUTPUT ;
    USE SIGNAL ;
    SHAPE ABUTMENT ;
    PORT
      LAYER M7 ;
      RECT 885.008 2319.864 885.040 2320.056 ;
    END
  END rx_flit[494]
  PIN rx_flit[495]
    DIRECTION OUTPUT ;
    USE SIGNAL ;
    SHAPE ABUTMENT ;
    PORT
      LAYER M5 ;
      RECT 885.180 2319.864 885.204 2320.056 ;
    END
  END rx_flit[495]
  PIN rx_flit[496]
    DIRECTION OUTPUT ;
    USE SIGNAL ;
    SHAPE ABUTMENT ;
    PORT
      LAYER M7 ;
      RECT 885.072 2319.864 885.104 2320.056 ;
    END
  END rx_flit[496]
  PIN rx_flit[497]
    DIRECTION OUTPUT ;
    USE SIGNAL ;
    SHAPE ABUTMENT ;
    PORT
      LAYER M5 ;
      RECT 885.612 2319.864 885.636 2320.056 ;
    END
  END rx_flit[497]
  PIN rx_flit[498]
    DIRECTION OUTPUT ;
    USE SIGNAL ;
    SHAPE ABUTMENT ;
    PORT
      LAYER M7 ;
      RECT 886.096 2319.864 886.128 2320.056 ;
    END
  END rx_flit[498]
  PIN rx_flit[499]
    DIRECTION OUTPUT ;
    USE SIGNAL ;
    SHAPE ABUTMENT ;
    PORT
      LAYER M5 ;
      RECT 886.044 2319.864 886.068 2320.056 ;
    END
  END rx_flit[499]
  PIN rx_flit[500]
    DIRECTION OUTPUT ;
    USE SIGNAL ;
    SHAPE ABUTMENT ;
    PORT
      LAYER M7 ;
      RECT 886.416 2319.864 886.448 2320.056 ;
    END
  END rx_flit[500]
  PIN rx_flit[501]
    DIRECTION OUTPUT ;
    USE SIGNAL ;
    SHAPE ABUTMENT ;
    PORT
      LAYER M5 ;
      RECT 886.428 2319.864 886.452 2320.056 ;
    END
  END rx_flit[501]
  PIN rx_flit[502]
    DIRECTION OUTPUT ;
    USE SIGNAL ;
    SHAPE ABUTMENT ;
    PORT
      LAYER M7 ;
      RECT 886.864 2319.864 886.896 2320.056 ;
    END
  END rx_flit[502]
  PIN rx_flit[503]
    DIRECTION OUTPUT ;
    USE SIGNAL ;
    SHAPE ABUTMENT ;
    PORT
      LAYER M5 ;
      RECT 886.860 2319.864 886.884 2320.056 ;
    END
  END rx_flit[503]
  PIN rx_flit[504]
    DIRECTION OUTPUT ;
    USE SIGNAL ;
    SHAPE ABUTMENT ;
    PORT
      LAYER M7 ;
      RECT 887.248 2319.864 887.280 2320.056 ;
    END
  END rx_flit[504]
  PIN rx_flit[505]
    DIRECTION OUTPUT ;
    USE SIGNAL ;
    SHAPE ABUTMENT ;
    PORT
      LAYER M5 ;
      RECT 887.292 2319.864 887.316 2320.056 ;
    END
  END rx_flit[505]
  PIN rx_flit[506]
    DIRECTION OUTPUT ;
    USE SIGNAL ;
    SHAPE ABUTMENT ;
    PORT
      LAYER M7 ;
      RECT 887.696 2319.864 887.728 2320.056 ;
    END
  END rx_flit[506]
  PIN rx_flit[507]
    DIRECTION OUTPUT ;
    USE SIGNAL ;
    SHAPE ABUTMENT ;
    PORT
      LAYER M5 ;
      RECT 887.484 2319.864 887.508 2320.056 ;
    END
  END rx_flit[507]
  PIN rx_flit[508]
    DIRECTION OUTPUT ;
    USE SIGNAL ;
    SHAPE ABUTMENT ;
    PORT
      LAYER M7 ;
      RECT 888.080 2319.864 888.112 2320.056 ;
    END
  END rx_flit[508]
  PIN rx_flit[509]
    DIRECTION OUTPUT ;
    USE SIGNAL ;
    SHAPE ABUTMENT ;
    PORT
      LAYER M5 ;
      RECT 888.108 2319.864 888.132 2320.056 ;
    END
  END rx_flit[509]
  PIN rx_flit[510]
    DIRECTION OUTPUT ;
    USE SIGNAL ;
    SHAPE ABUTMENT ;
    PORT
      LAYER M7 ;
      RECT 888.528 2319.864 888.560 2320.056 ;
    END
  END rx_flit[510]
  PIN rx_flit[511]
    DIRECTION OUTPUT ;
    USE SIGNAL ;
    SHAPE ABUTMENT ;
    PORT
      LAYER M5 ;
      RECT 888.540 2319.864 888.564 2320.056 ;
    END
  END rx_flit[511]
  PIN rx_flit[512]
    DIRECTION OUTPUT ;
    USE SIGNAL ;
    SHAPE ABUTMENT ;
    PORT
      LAYER M7 ;
      RECT 888.912 2319.864 888.944 2320.056 ;
    END
  END rx_flit[512]
  PIN rx_flit[513]
    DIRECTION OUTPUT ;
    USE SIGNAL ;
    SHAPE ABUTMENT ;
    PORT
      LAYER M5 ;
      RECT 888.924 2319.864 888.948 2320.056 ;
    END
  END rx_flit[513]
  PIN rx_flit[514]
    DIRECTION OUTPUT ;
    USE SIGNAL ;
    SHAPE ABUTMENT ;
    PORT
      LAYER M7 ;
      RECT 889.360 2319.864 889.392 2320.056 ;
    END
  END rx_flit[514]
  PIN rx_flit[515]
    DIRECTION OUTPUT ;
    USE SIGNAL ;
    SHAPE ABUTMENT ;
    PORT
      LAYER M5 ;
      RECT 889.356 2319.864 889.380 2320.056 ;
    END
  END rx_flit[515]
  PIN rx_flit[516]
    DIRECTION OUTPUT ;
    USE SIGNAL ;
    SHAPE ABUTMENT ;
    PORT
      LAYER M7 ;
      RECT 889.744 2319.864 889.776 2320.056 ;
    END
  END rx_flit[516]
  PIN rx_flit[517]
    DIRECTION OUTPUT ;
    USE SIGNAL ;
    SHAPE ABUTMENT ;
    PORT
      LAYER M5 ;
      RECT 889.788 2319.864 889.812 2320.056 ;
    END
  END rx_flit[517]
  PIN rx_flit[518]
    DIRECTION OUTPUT ;
    USE SIGNAL ;
    SHAPE ABUTMENT ;
    PORT
      LAYER M7 ;
      RECT 890.192 2319.864 890.224 2320.056 ;
    END
  END rx_flit[518]
  PIN rx_flit[519]
    DIRECTION OUTPUT ;
    USE SIGNAL ;
    SHAPE ABUTMENT ;
    PORT
      LAYER M5 ;
      RECT 890.172 2319.864 890.196 2320.056 ;
    END
  END rx_flit[519]
  PIN rx_flit[520]
    DIRECTION OUTPUT ;
    USE SIGNAL ;
    SHAPE ABUTMENT ;
    PORT
      LAYER M7 ;
      RECT 890.576 2319.864 890.608 2320.056 ;
    END
  END rx_flit[520]
  PIN rx_flit[521]
    DIRECTION OUTPUT ;
    USE SIGNAL ;
    SHAPE ABUTMENT ;
    PORT
      LAYER M5 ;
      RECT 890.604 2319.864 890.628 2320.056 ;
    END
  END rx_flit[521]
  PIN rx_flit[522]
    DIRECTION OUTPUT ;
    USE SIGNAL ;
    SHAPE ABUTMENT ;
    PORT
      LAYER M7 ;
      RECT 891.024 2319.864 891.056 2320.056 ;
    END
  END rx_flit[522]
  PIN rx_flit[523]
    DIRECTION OUTPUT ;
    USE SIGNAL ;
    SHAPE ABUTMENT ;
    PORT
      LAYER M5 ;
      RECT 891.036 2319.864 891.060 2320.056 ;
    END
  END rx_flit[523]
  PIN rx_flit[524]
    DIRECTION OUTPUT ;
    USE SIGNAL ;
    SHAPE ABUTMENT ;
    PORT
      LAYER M7 ;
      RECT 891.472 2319.864 891.504 2320.056 ;
    END
  END rx_flit[524]
  PIN rx_flit[525]
    DIRECTION OUTPUT ;
    USE SIGNAL ;
    SHAPE ABUTMENT ;
    PORT
      LAYER M5 ;
      RECT 891.468 2319.864 891.492 2320.056 ;
    END
  END rx_flit[525]
  PIN rx_flit[526]
    DIRECTION OUTPUT ;
    USE SIGNAL ;
    SHAPE ABUTMENT ;
    PORT
      LAYER M7 ;
      RECT 891.856 2319.864 891.888 2320.056 ;
    END
  END rx_flit[526]
  PIN rx_flit[527]
    DIRECTION OUTPUT ;
    USE SIGNAL ;
    SHAPE ABUTMENT ;
    PORT
      LAYER M5 ;
      RECT 891.804 2319.864 891.828 2320.056 ;
    END
  END rx_flit[527]
  PIN rx_flit[528]
    DIRECTION OUTPUT ;
    USE SIGNAL ;
    SHAPE ABUTMENT ;
    PORT
      LAYER M7 ;
      RECT 892.304 2319.864 892.336 2320.056 ;
    END
  END rx_flit[528]
  PIN rx_flit[529]
    DIRECTION OUTPUT ;
    USE SIGNAL ;
    SHAPE ABUTMENT ;
    PORT
      LAYER M5 ;
      RECT 892.332 2319.864 892.356 2320.056 ;
    END
  END rx_flit[529]
  PIN rx_flit[530]
    DIRECTION OUTPUT ;
    USE SIGNAL ;
    SHAPE ABUTMENT ;
    PORT
      LAYER M7 ;
      RECT 892.688 2319.864 892.720 2320.056 ;
    END
  END rx_flit[530]
  PIN rx_flit[531]
    DIRECTION OUTPUT ;
    USE SIGNAL ;
    SHAPE ABUTMENT ;
    PORT
      LAYER M5 ;
      RECT 892.716 2319.864 892.740 2320.056 ;
    END
  END rx_flit[531]
  PIN rx_flit[532]
    DIRECTION OUTPUT ;
    USE SIGNAL ;
    SHAPE ABUTMENT ;
    PORT
      LAYER M7 ;
      RECT 893.136 2319.864 893.168 2320.056 ;
    END
  END rx_flit[532]
  PIN rx_flit[533]
    DIRECTION OUTPUT ;
    USE SIGNAL ;
    SHAPE ABUTMENT ;
    PORT
      LAYER M5 ;
      RECT 893.100 2319.864 893.124 2320.056 ;
    END
  END rx_flit[533]
  PIN rx_flit[534]
    DIRECTION OUTPUT ;
    USE SIGNAL ;
    SHAPE ABUTMENT ;
    PORT
      LAYER M7 ;
      RECT 893.520 2319.864 893.552 2320.056 ;
    END
  END rx_flit[534]
  PIN rx_flit[535]
    DIRECTION OUTPUT ;
    USE SIGNAL ;
    SHAPE ABUTMENT ;
    PORT
      LAYER M5 ;
      RECT 893.532 2319.864 893.556 2320.056 ;
    END
  END rx_flit[535]
  PIN rx_flit[536]
    DIRECTION OUTPUT ;
    USE SIGNAL ;
    SHAPE ABUTMENT ;
    PORT
      LAYER M7 ;
      RECT 893.712 2319.864 893.744 2320.056 ;
    END
  END rx_flit[536]
  PIN rx_flit[537]
    DIRECTION OUTPUT ;
    USE SIGNAL ;
    SHAPE ABUTMENT ;
    PORT
      LAYER M5 ;
      RECT 893.964 2319.864 893.988 2320.056 ;
    END
  END rx_flit[537]
  PIN rx_flit[538]
    DIRECTION OUTPUT ;
    USE SIGNAL ;
    SHAPE ABUTMENT ;
    PORT
      LAYER M7 ;
      RECT 894.736 2319.864 894.768 2320.056 ;
    END
  END rx_flit[538]
  PIN rx_flit[539]
    DIRECTION OUTPUT ;
    USE SIGNAL ;
    SHAPE ABUTMENT ;
    PORT
      LAYER M5 ;
      RECT 894.348 2319.864 894.372 2320.056 ;
    END
  END rx_flit[539]
  PIN rx_flit[540]
    DIRECTION OUTPUT ;
    USE SIGNAL ;
    SHAPE ABUTMENT ;
    PORT
      LAYER M7 ;
      RECT 894.800 2319.864 894.832 2320.056 ;
    END
  END rx_flit[540]
  PIN rx_flit[541]
    DIRECTION OUTPUT ;
    USE SIGNAL ;
    SHAPE ABUTMENT ;
    PORT
      LAYER M5 ;
      RECT 894.780 2319.864 894.804 2320.056 ;
    END
  END rx_flit[541]
  PIN rx_flit[542]
    DIRECTION OUTPUT ;
    USE SIGNAL ;
    SHAPE ABUTMENT ;
    PORT
      LAYER M7 ;
      RECT 895.184 2319.864 895.216 2320.056 ;
    END
  END rx_flit[542]
  PIN rx_flit[543]
    DIRECTION OUTPUT ;
    USE SIGNAL ;
    SHAPE ABUTMENT ;
    PORT
      LAYER M5 ;
      RECT 895.212 2319.864 895.236 2320.056 ;
    END
  END rx_flit[543]
  PIN rx_flit[544]
    DIRECTION OUTPUT ;
    USE SIGNAL ;
    SHAPE ABUTMENT ;
    PORT
      LAYER M7 ;
      RECT 895.632 2319.864 895.664 2320.056 ;
    END
  END rx_flit[544]
  PIN rx_flit[545]
    DIRECTION OUTPUT ;
    USE SIGNAL ;
    SHAPE ABUTMENT ;
    PORT
      LAYER M5 ;
      RECT 895.596 2319.864 895.620 2320.056 ;
    END
  END rx_flit[545]
  PIN rx_flit[546]
    DIRECTION OUTPUT ;
    USE SIGNAL ;
    SHAPE ABUTMENT ;
    PORT
      LAYER M7 ;
      RECT 896.016 2319.864 896.048 2320.056 ;
    END
  END rx_flit[546]
  PIN rx_flit[547]
    DIRECTION OUTPUT ;
    USE SIGNAL ;
    SHAPE ABUTMENT ;
    PORT
      LAYER M5 ;
      RECT 896.028 2319.864 896.052 2320.056 ;
    END
  END rx_flit[547]
  PIN rx_flit[548]
    DIRECTION OUTPUT ;
    USE SIGNAL ;
    SHAPE ABUTMENT ;
    PORT
      LAYER M7 ;
      RECT 896.464 2319.864 896.496 2320.056 ;
    END
  END rx_flit[548]
  PIN rx_flit[549]
    DIRECTION OUTPUT ;
    USE SIGNAL ;
    SHAPE ABUTMENT ;
    PORT
      LAYER M5 ;
      RECT 896.652 2319.864 896.676 2320.056 ;
    END
  END rx_flit[549]
  PIN rx_flit[550]
    DIRECTION OUTPUT ;
    USE SIGNAL ;
    SHAPE ABUTMENT ;
    PORT
      LAYER M7 ;
      RECT 896.848 2319.864 896.880 2320.056 ;
    END
  END rx_flit[550]
  PIN rx_flit[551]
    DIRECTION OUTPUT ;
    USE SIGNAL ;
    SHAPE ABUTMENT ;
    PORT
      LAYER M5 ;
      RECT 896.892 2319.864 896.916 2320.056 ;
    END
  END rx_flit[551]
  PIN rx_flit[552]
    DIRECTION OUTPUT ;
    USE SIGNAL ;
    SHAPE ABUTMENT ;
    PORT
      LAYER M7 ;
      RECT 897.296 2319.864 897.328 2320.056 ;
    END
  END rx_flit[552]
  PIN rx_flit[553]
    DIRECTION OUTPUT ;
    USE SIGNAL ;
    SHAPE ABUTMENT ;
    PORT
      LAYER M5 ;
      RECT 897.276 2319.864 897.300 2320.056 ;
    END
  END rx_flit[553]
  PIN rx_flit[554]
    DIRECTION OUTPUT ;
    USE SIGNAL ;
    SHAPE ABUTMENT ;
    PORT
      LAYER M7 ;
      RECT 897.680 2319.864 897.712 2320.056 ;
    END
  END rx_flit[554]
  PIN rx_flit[555]
    DIRECTION OUTPUT ;
    USE SIGNAL ;
    SHAPE ABUTMENT ;
    PORT
      LAYER M5 ;
      RECT 897.708 2319.864 897.732 2320.056 ;
    END
  END rx_flit[555]
  PIN rx_flit[556]
    DIRECTION OUTPUT ;
    USE SIGNAL ;
    SHAPE ABUTMENT ;
    PORT
      LAYER M7 ;
      RECT 898.128 2319.864 898.160 2320.056 ;
    END
  END rx_flit[556]
  PIN rx_flit[557]
    DIRECTION OUTPUT ;
    USE SIGNAL ;
    SHAPE ABUTMENT ;
    PORT
      LAYER M5 ;
      RECT 898.140 2319.864 898.164 2320.056 ;
    END
  END rx_flit[557]
  PIN rx_flit[558]
    DIRECTION OUTPUT ;
    USE SIGNAL ;
    SHAPE ABUTMENT ;
    PORT
      LAYER M7 ;
      RECT 898.512 2319.864 898.544 2320.056 ;
    END
  END rx_flit[558]
  PIN rx_flit[559]
    DIRECTION OUTPUT ;
    USE SIGNAL ;
    SHAPE ABUTMENT ;
    PORT
      LAYER M5 ;
      RECT 898.524 2319.864 898.548 2320.056 ;
    END
  END rx_flit[559]
  PIN rx_flit[560]
    DIRECTION OUTPUT ;
    USE SIGNAL ;
    SHAPE ABUTMENT ;
    PORT
      LAYER M7 ;
      RECT 898.960 2319.864 898.992 2320.056 ;
    END
  END rx_flit[560]
  PIN rx_flit[561]
    DIRECTION OUTPUT ;
    USE SIGNAL ;
    SHAPE ABUTMENT ;
    PORT
      LAYER M5 ;
      RECT 898.956 2319.864 898.980 2320.056 ;
    END
  END rx_flit[561]
  PIN rx_flit[562]
    DIRECTION OUTPUT ;
    USE SIGNAL ;
    SHAPE ABUTMENT ;
    PORT
      LAYER M7 ;
      RECT 899.344 2319.864 899.376 2320.056 ;
    END
  END rx_flit[562]
  PIN rx_flit[563]
    DIRECTION OUTPUT ;
    USE SIGNAL ;
    SHAPE ABUTMENT ;
    PORT
      LAYER M5 ;
      RECT 899.388 2319.864 899.412 2320.056 ;
    END
  END rx_flit[563]
  PIN rx_flit[564]
    DIRECTION OUTPUT ;
    USE SIGNAL ;
    SHAPE ABUTMENT ;
    PORT
      LAYER M7 ;
      RECT 899.792 2319.864 899.824 2320.056 ;
    END
  END rx_flit[564]
  PIN rx_flit[565]
    DIRECTION OUTPUT ;
    USE SIGNAL ;
    SHAPE ABUTMENT ;
    PORT
      LAYER M5 ;
      RECT 899.772 2319.864 899.796 2320.056 ;
    END
  END rx_flit[565]
  PIN rx_flit[566]
    DIRECTION OUTPUT ;
    USE SIGNAL ;
    SHAPE ABUTMENT ;
    PORT
      LAYER M7 ;
      RECT 900.176 2319.864 900.208 2320.056 ;
    END
  END rx_flit[566]
  PIN rx_flit[567]
    DIRECTION OUTPUT ;
    USE SIGNAL ;
    SHAPE ABUTMENT ;
    PORT
      LAYER M5 ;
      RECT 900.204 2319.864 900.228 2320.056 ;
    END
  END rx_flit[567]
  PIN rx_flit[568]
    DIRECTION OUTPUT ;
    USE SIGNAL ;
    SHAPE ABUTMENT ;
    PORT
      LAYER M7 ;
      RECT 900.624 2319.864 900.656 2320.056 ;
    END
  END rx_flit[568]
  PIN rx_flit[569]
    DIRECTION OUTPUT ;
    USE SIGNAL ;
    SHAPE ABUTMENT ;
    PORT
      LAYER M5 ;
      RECT 900.444 2319.864 900.468 2320.056 ;
    END
  END rx_flit[569]
  PIN rx_flit[570]
    DIRECTION OUTPUT ;
    USE SIGNAL ;
    SHAPE ABUTMENT ;
    PORT
      LAYER M7 ;
      RECT 901.008 2319.864 901.040 2320.056 ;
    END
  END rx_flit[570]
  PIN rx_flit[571]
    DIRECTION OUTPUT ;
    USE SIGNAL ;
    SHAPE ABUTMENT ;
    PORT
      LAYER M5 ;
      RECT 901.020 2319.864 901.044 2320.056 ;
    END
  END rx_flit[571]
  PIN rx_flit[572]
    DIRECTION OUTPUT ;
    USE SIGNAL ;
    SHAPE ABUTMENT ;
    PORT
      LAYER M7 ;
      RECT 901.456 2319.864 901.488 2320.056 ;
    END
  END rx_flit[572]
  PIN rx_flit[573]
    DIRECTION OUTPUT ;
    USE SIGNAL ;
    SHAPE ABUTMENT ;
    PORT
      LAYER M5 ;
      RECT 901.452 2319.864 901.476 2320.056 ;
    END
  END rx_flit[573]
  PIN rx_flit[574]
    DIRECTION OUTPUT ;
    USE SIGNAL ;
    SHAPE ABUTMENT ;
    PORT
      LAYER M7 ;
      RECT 901.904 2319.864 901.936 2320.056 ;
    END
  END rx_flit[574]
  PIN rx_flit[575]
    DIRECTION OUTPUT ;
    USE SIGNAL ;
    SHAPE ABUTMENT ;
    PORT
      LAYER M5 ;
      RECT 901.884 2319.864 901.908 2320.056 ;
    END
  END rx_flit[575]
  PIN rx_flit[576]
    DIRECTION OUTPUT ;
    USE SIGNAL ;
    SHAPE ABUTMENT ;
    PORT
      LAYER M7 ;
      RECT 902.288 2319.864 902.320 2320.056 ;
    END
  END rx_flit[576]
  PIN rx_flit[577]
    DIRECTION OUTPUT ;
    USE SIGNAL ;
    SHAPE ABUTMENT ;
    PORT
      LAYER M5 ;
      RECT 902.316 2319.864 902.340 2320.056 ;
    END
  END rx_flit[577]
  PIN rx_flit[578]
    DIRECTION OUTPUT ;
    USE SIGNAL ;
    SHAPE ABUTMENT ;
    PORT
      LAYER M7 ;
      RECT 902.352 2319.864 902.384 2320.056 ;
    END
  END rx_flit[578]
  PIN rx_flit[579]
    DIRECTION OUTPUT ;
    USE SIGNAL ;
    SHAPE ABUTMENT ;
    PORT
      LAYER M5 ;
      RECT 902.700 2319.864 902.724 2320.056 ;
    END
  END rx_flit[579]
  PIN rx_flit[580]
    DIRECTION OUTPUT ;
    USE SIGNAL ;
    SHAPE ABUTMENT ;
    PORT
      LAYER M7 ;
      RECT 903.376 2319.864 903.408 2320.056 ;
    END
  END rx_flit[580]
  PIN rx_flit[581]
    DIRECTION OUTPUT ;
    USE SIGNAL ;
    SHAPE ABUTMENT ;
    PORT
      LAYER M5 ;
      RECT 903.132 2319.864 903.156 2320.056 ;
    END
  END rx_flit[581]
  PIN rx_flit[582]
    DIRECTION OUTPUT ;
    USE SIGNAL ;
    SHAPE ABUTMENT ;
    PORT
      LAYER M7 ;
      RECT 903.568 2319.864 903.600 2320.056 ;
    END
  END rx_flit[582]
  PIN rx_flit[583]
    DIRECTION OUTPUT ;
    USE SIGNAL ;
    SHAPE ABUTMENT ;
    PORT
      LAYER M5 ;
      RECT 903.564 2319.864 903.588 2320.056 ;
    END
  END rx_flit[583]
  PIN rx_flit[584]
    DIRECTION OUTPUT ;
    USE SIGNAL ;
    SHAPE ABUTMENT ;
    PORT
      LAYER M7 ;
      RECT 903.952 2319.864 903.984 2320.056 ;
    END
  END rx_flit[584]
  PIN rx_flit[585]
    DIRECTION OUTPUT ;
    USE SIGNAL ;
    SHAPE ABUTMENT ;
    PORT
      LAYER M5 ;
      RECT 903.948 2319.864 903.972 2320.056 ;
    END
  END rx_flit[585]
  PIN rx_flit[586]
    DIRECTION OUTPUT ;
    USE SIGNAL ;
    SHAPE ABUTMENT ;
    PORT
      LAYER M7 ;
      RECT 904.400 2319.864 904.432 2320.056 ;
    END
  END rx_flit[586]
  PIN rx_flit[587]
    DIRECTION OUTPUT ;
    USE SIGNAL ;
    SHAPE ABUTMENT ;
    PORT
      LAYER M5 ;
      RECT 904.380 2319.864 904.404 2320.056 ;
    END
  END rx_flit[587]
  PIN rx_flit[588]
    DIRECTION OUTPUT ;
    USE SIGNAL ;
    SHAPE ABUTMENT ;
    PORT
      LAYER M7 ;
      RECT 904.784 2319.864 904.816 2320.056 ;
    END
  END rx_flit[588]
  PIN rx_flit[589]
    DIRECTION OUTPUT ;
    USE SIGNAL ;
    SHAPE ABUTMENT ;
    PORT
      LAYER M5 ;
      RECT 904.764 2319.864 904.788 2320.056 ;
    END
  END rx_flit[589]
  PIN rx_flit[590]
    DIRECTION OUTPUT ;
    USE SIGNAL ;
    SHAPE ABUTMENT ;
    PORT
      LAYER M7 ;
      RECT 905.232 2319.864 905.264 2320.056 ;
    END
  END rx_flit[590]
  PIN rx_flit[591]
    DIRECTION OUTPUT ;
    USE SIGNAL ;
    SHAPE ABUTMENT ;
    PORT
      LAYER M5 ;
      RECT 905.292 2319.864 905.316 2320.056 ;
    END
  END rx_flit[591]
  PIN rx_flit[592]
    DIRECTION OUTPUT ;
    USE SIGNAL ;
    SHAPE ABUTMENT ;
    PORT
      LAYER M7 ;
      RECT 905.616 2319.864 905.648 2320.056 ;
    END
  END rx_flit[592]
  PIN rx_flit[593]
    DIRECTION OUTPUT ;
    USE SIGNAL ;
    SHAPE ABUTMENT ;
    PORT
      LAYER M5 ;
      RECT 905.628 2319.864 905.652 2320.056 ;
    END
  END rx_flit[593]
  PIN rx_flit[594]
    DIRECTION OUTPUT ;
    USE SIGNAL ;
    SHAPE ABUTMENT ;
    PORT
      LAYER M7 ;
      RECT 906.064 2319.864 906.096 2320.056 ;
    END
  END rx_flit[594]
  PIN rx_flit[595]
    DIRECTION OUTPUT ;
    USE SIGNAL ;
    SHAPE ABUTMENT ;
    PORT
      LAYER M5 ;
      RECT 906.060 2319.864 906.084 2320.056 ;
    END
  END rx_flit[595]
  PIN rx_flit[596]
    DIRECTION OUTPUT ;
    USE SIGNAL ;
    SHAPE ABUTMENT ;
    PORT
      LAYER M7 ;
      RECT 906.448 2319.864 906.480 2320.056 ;
    END
  END rx_flit[596]
  PIN VDD
    DIRECTION INOUT ;
    USE POWER ;
    PORT
      LAYER M4 ;
      RECT 0.500 1.000 1563.070 1.288 ;
      RECT 0.500 3.400 1563.070 3.688 ;
      RECT 0.500 5.800 1563.070 6.088 ;
      RECT 0.500 8.200 1563.070 8.488 ;
      RECT 0.500 10.600 1563.070 10.888 ;
      RECT 0.500 13.000 1563.070 13.288 ;
      RECT 0.500 15.400 1563.070 15.688 ;
      RECT 0.500 17.800 1563.070 18.088 ;
      RECT 0.500 20.200 1563.070 20.488 ;
      RECT 0.500 22.600 1563.070 22.888 ;
      RECT 0.500 25.000 1563.070 25.288 ;
      RECT 0.500 27.400 1563.070 27.688 ;
      RECT 0.500 29.800 1563.070 30.088 ;
      RECT 0.500 32.200 1563.070 32.488 ;
      RECT 0.500 34.600 1563.070 34.888 ;
      RECT 0.500 37.000 1563.070 37.288 ;
      RECT 0.500 39.400 1563.070 39.688 ;
      RECT 0.500 41.800 1563.070 42.088 ;
      RECT 0.500 44.200 1563.070 44.488 ;
      RECT 0.500 46.600 1563.070 46.888 ;
      RECT 0.500 49.000 1563.070 49.288 ;
      RECT 0.500 51.400 1563.070 51.688 ;
      RECT 0.500 53.800 1563.070 54.088 ;
      RECT 0.500 56.200 1563.070 56.488 ;
      RECT 0.500 58.600 1563.070 58.888 ;
      RECT 0.500 61.000 1563.070 61.288 ;
      RECT 0.500 63.400 1563.070 63.688 ;
      RECT 0.500 65.800 1563.070 66.088 ;
      RECT 0.500 68.200 1563.070 68.488 ;
      RECT 0.500 70.600 1563.070 70.888 ;
      RECT 0.500 73.000 1563.070 73.288 ;
      RECT 0.500 75.400 1563.070 75.688 ;
      RECT 0.500 77.800 1563.070 78.088 ;
      RECT 0.500 80.200 1563.070 80.488 ;
      RECT 0.500 82.600 1563.070 82.888 ;
      RECT 0.500 85.000 1563.070 85.288 ;
      RECT 0.500 87.400 1563.070 87.688 ;
      RECT 0.500 89.800 1563.070 90.088 ;
      RECT 0.500 92.200 1563.070 92.488 ;
      RECT 0.500 94.600 1563.070 94.888 ;
      RECT 0.500 97.000 1563.070 97.288 ;
      RECT 0.500 99.400 1563.070 99.688 ;
      RECT 0.500 101.800 1563.070 102.088 ;
      RECT 0.500 104.200 1563.070 104.488 ;
      RECT 0.500 106.600 1563.070 106.888 ;
      RECT 0.500 109.000 1563.070 109.288 ;
      RECT 0.500 111.400 1563.070 111.688 ;
      RECT 0.500 113.800 1563.070 114.088 ;
      RECT 0.500 116.200 1563.070 116.488 ;
      RECT 0.500 118.600 1563.070 118.888 ;
      RECT 0.500 121.000 1563.070 121.288 ;
      RECT 0.500 123.400 1563.070 123.688 ;
      RECT 0.500 125.800 1563.070 126.088 ;
      RECT 0.500 128.200 1563.070 128.488 ;
      RECT 0.500 130.600 1563.070 130.888 ;
      RECT 0.500 133.000 1563.070 133.288 ;
      RECT 0.500 135.400 1563.070 135.688 ;
      RECT 0.500 137.800 1563.070 138.088 ;
      RECT 0.500 140.200 1563.070 140.488 ;
      RECT 0.500 142.600 1563.070 142.888 ;
      RECT 0.500 145.000 1563.070 145.288 ;
      RECT 0.500 147.400 1563.070 147.688 ;
      RECT 0.500 149.800 1563.070 150.088 ;
      RECT 0.500 152.200 1563.070 152.488 ;
      RECT 0.500 154.600 1563.070 154.888 ;
      RECT 0.500 157.000 1563.070 157.288 ;
      RECT 0.500 159.400 1563.070 159.688 ;
      RECT 0.500 161.800 1563.070 162.088 ;
      RECT 0.500 164.200 1563.070 164.488 ;
      RECT 0.500 166.600 1563.070 166.888 ;
      RECT 0.500 169.000 1563.070 169.288 ;
      RECT 0.500 171.400 1563.070 171.688 ;
      RECT 0.500 173.800 1563.070 174.088 ;
      RECT 0.500 176.200 1563.070 176.488 ;
      RECT 0.500 178.600 1563.070 178.888 ;
      RECT 0.500 181.000 1563.070 181.288 ;
      RECT 0.500 183.400 1563.070 183.688 ;
      RECT 0.500 185.800 1563.070 186.088 ;
      RECT 0.500 188.200 1563.070 188.488 ;
      RECT 0.500 190.600 1563.070 190.888 ;
      RECT 0.500 193.000 1563.070 193.288 ;
      RECT 0.500 195.400 1563.070 195.688 ;
      RECT 0.500 197.800 1563.070 198.088 ;
      RECT 0.500 200.200 1563.070 200.488 ;
      RECT 0.500 202.600 1563.070 202.888 ;
      RECT 0.500 205.000 1563.070 205.288 ;
      RECT 0.500 207.400 1563.070 207.688 ;
      RECT 0.500 209.800 1563.070 210.088 ;
      RECT 0.500 212.200 1563.070 212.488 ;
      RECT 0.500 214.600 1563.070 214.888 ;
      RECT 0.500 217.000 1563.070 217.288 ;
      RECT 0.500 219.400 1563.070 219.688 ;
      RECT 0.500 221.800 1563.070 222.088 ;
      RECT 0.500 224.200 1563.070 224.488 ;
      RECT 0.500 226.600 1563.070 226.888 ;
      RECT 0.500 229.000 1563.070 229.288 ;
      RECT 0.500 231.400 1563.070 231.688 ;
      RECT 0.500 233.800 1563.070 234.088 ;
      RECT 0.500 236.200 1563.070 236.488 ;
      RECT 0.500 238.600 1563.070 238.888 ;
      RECT 0.500 241.000 1563.070 241.288 ;
      RECT 0.500 243.400 1563.070 243.688 ;
      RECT 0.500 245.800 1563.070 246.088 ;
      RECT 0.500 248.200 1563.070 248.488 ;
      RECT 0.500 250.600 1563.070 250.888 ;
      RECT 0.500 253.000 1563.070 253.288 ;
      RECT 0.500 255.400 1563.070 255.688 ;
      RECT 0.500 257.800 1563.070 258.088 ;
      RECT 0.500 260.200 1563.070 260.488 ;
      RECT 0.500 262.600 1563.070 262.888 ;
      RECT 0.500 265.000 1563.070 265.288 ;
      RECT 0.500 267.400 1563.070 267.688 ;
      RECT 0.500 269.800 1563.070 270.088 ;
      RECT 0.500 272.200 1563.070 272.488 ;
      RECT 0.500 274.600 1563.070 274.888 ;
      RECT 0.500 277.000 1563.070 277.288 ;
      RECT 0.500 279.400 1563.070 279.688 ;
      RECT 0.500 281.800 1563.070 282.088 ;
      RECT 0.500 284.200 1563.070 284.488 ;
      RECT 0.500 286.600 1563.070 286.888 ;
      RECT 0.500 289.000 1563.070 289.288 ;
      RECT 0.500 291.400 1563.070 291.688 ;
      RECT 0.500 293.800 1563.070 294.088 ;
      RECT 0.500 296.200 1563.070 296.488 ;
      RECT 0.500 298.600 1563.070 298.888 ;
      RECT 0.500 301.000 1563.070 301.288 ;
      RECT 0.500 303.400 1563.070 303.688 ;
      RECT 0.500 305.800 1563.070 306.088 ;
      RECT 0.500 308.200 1563.070 308.488 ;
      RECT 0.500 310.600 1563.070 310.888 ;
      RECT 0.500 313.000 1563.070 313.288 ;
      RECT 0.500 315.400 1563.070 315.688 ;
      RECT 0.500 317.800 1563.070 318.088 ;
      RECT 0.500 320.200 1563.070 320.488 ;
      RECT 0.500 322.600 1563.070 322.888 ;
      RECT 0.500 325.000 1563.070 325.288 ;
      RECT 0.500 327.400 1563.070 327.688 ;
      RECT 0.500 329.800 1563.070 330.088 ;
      RECT 0.500 332.200 1563.070 332.488 ;
      RECT 0.500 334.600 1563.070 334.888 ;
      RECT 0.500 337.000 1563.070 337.288 ;
      RECT 0.500 339.400 1563.070 339.688 ;
      RECT 0.500 341.800 1563.070 342.088 ;
      RECT 0.500 344.200 1563.070 344.488 ;
      RECT 0.500 346.600 1563.070 346.888 ;
      RECT 0.500 349.000 1563.070 349.288 ;
      RECT 0.500 351.400 1563.070 351.688 ;
      RECT 0.500 353.800 1563.070 354.088 ;
      RECT 0.500 356.200 1563.070 356.488 ;
      RECT 0.500 358.600 1563.070 358.888 ;
      RECT 0.500 361.000 1563.070 361.288 ;
      RECT 0.500 363.400 1563.070 363.688 ;
      RECT 0.500 365.800 1563.070 366.088 ;
      RECT 0.500 368.200 1563.070 368.488 ;
      RECT 0.500 370.600 1563.070 370.888 ;
      RECT 0.500 373.000 1563.070 373.288 ;
      RECT 0.500 375.400 1563.070 375.688 ;
      RECT 0.500 377.800 1563.070 378.088 ;
      RECT 0.500 380.200 1563.070 380.488 ;
      RECT 0.500 382.600 1563.070 382.888 ;
      RECT 0.500 385.000 1563.070 385.288 ;
      RECT 0.500 387.400 1563.070 387.688 ;
      RECT 0.500 389.800 1563.070 390.088 ;
      RECT 0.500 392.200 1563.070 392.488 ;
      RECT 0.500 394.600 1563.070 394.888 ;
      RECT 0.500 397.000 1563.070 397.288 ;
      RECT 0.500 399.400 1563.070 399.688 ;
      RECT 0.500 401.800 1563.070 402.088 ;
      RECT 0.500 404.200 1563.070 404.488 ;
      RECT 0.500 406.600 1563.070 406.888 ;
      RECT 0.500 409.000 1563.070 409.288 ;
      RECT 0.500 411.400 1563.070 411.688 ;
      RECT 0.500 413.800 1563.070 414.088 ;
      RECT 0.500 416.200 1563.070 416.488 ;
      RECT 0.500 418.600 1563.070 418.888 ;
      RECT 0.500 421.000 1563.070 421.288 ;
      RECT 0.500 423.400 1563.070 423.688 ;
      RECT 0.500 425.800 1563.070 426.088 ;
      RECT 0.500 428.200 1563.070 428.488 ;
      RECT 0.500 430.600 1563.070 430.888 ;
      RECT 0.500 433.000 1563.070 433.288 ;
      RECT 0.500 435.400 1563.070 435.688 ;
      RECT 0.500 437.800 1563.070 438.088 ;
      RECT 0.500 440.200 1563.070 440.488 ;
      RECT 0.500 442.600 1563.070 442.888 ;
      RECT 0.500 445.000 1563.070 445.288 ;
      RECT 0.500 447.400 1563.070 447.688 ;
      RECT 0.500 449.800 1563.070 450.088 ;
      RECT 0.500 452.200 1563.070 452.488 ;
      RECT 0.500 454.600 1563.070 454.888 ;
      RECT 0.500 457.000 1563.070 457.288 ;
      RECT 0.500 459.400 1563.070 459.688 ;
      RECT 0.500 461.800 1563.070 462.088 ;
      RECT 0.500 464.200 1563.070 464.488 ;
      RECT 0.500 466.600 1563.070 466.888 ;
      RECT 0.500 469.000 1563.070 469.288 ;
      RECT 0.500 471.400 1563.070 471.688 ;
      RECT 0.500 473.800 1563.070 474.088 ;
      RECT 0.500 476.200 1563.070 476.488 ;
      RECT 0.500 478.600 1563.070 478.888 ;
      RECT 0.500 481.000 1563.070 481.288 ;
      RECT 0.500 483.400 1563.070 483.688 ;
      RECT 0.500 485.800 1563.070 486.088 ;
      RECT 0.500 488.200 1563.070 488.488 ;
      RECT 0.500 490.600 1563.070 490.888 ;
      RECT 0.500 493.000 1563.070 493.288 ;
      RECT 0.500 495.400 1563.070 495.688 ;
      RECT 0.500 497.800 1563.070 498.088 ;
      RECT 0.500 500.200 1563.070 500.488 ;
      RECT 0.500 502.600 1563.070 502.888 ;
      RECT 0.500 505.000 1563.070 505.288 ;
      RECT 0.500 507.400 1563.070 507.688 ;
      RECT 0.500 509.800 1563.070 510.088 ;
      RECT 0.500 512.200 1563.070 512.488 ;
      RECT 0.500 514.600 1563.070 514.888 ;
      RECT 0.500 517.000 1563.070 517.288 ;
      RECT 0.500 519.400 1563.070 519.688 ;
      RECT 0.500 521.800 1563.070 522.088 ;
      RECT 0.500 524.200 1563.070 524.488 ;
      RECT 0.500 526.600 1563.070 526.888 ;
      RECT 0.500 529.000 1563.070 529.288 ;
      RECT 0.500 531.400 1563.070 531.688 ;
      RECT 0.500 533.800 1563.070 534.088 ;
      RECT 0.500 536.200 1563.070 536.488 ;
      RECT 0.500 538.600 1563.070 538.888 ;
      RECT 0.500 541.000 1563.070 541.288 ;
      RECT 0.500 543.400 1563.070 543.688 ;
      RECT 0.500 545.800 1563.070 546.088 ;
      RECT 0.500 548.200 1563.070 548.488 ;
      RECT 0.500 550.600 1563.070 550.888 ;
      RECT 0.500 553.000 1563.070 553.288 ;
      RECT 0.500 555.400 1563.070 555.688 ;
      RECT 0.500 557.800 1563.070 558.088 ;
      RECT 0.500 560.200 1563.070 560.488 ;
      RECT 0.500 562.600 1563.070 562.888 ;
      RECT 0.500 565.000 1563.070 565.288 ;
      RECT 0.500 567.400 1563.070 567.688 ;
      RECT 0.500 569.800 1563.070 570.088 ;
      RECT 0.500 572.200 1563.070 572.488 ;
      RECT 0.500 574.600 1563.070 574.888 ;
      RECT 0.500 577.000 1563.070 577.288 ;
      RECT 0.500 579.400 1563.070 579.688 ;
      RECT 0.500 581.800 1563.070 582.088 ;
      RECT 0.500 584.200 1563.070 584.488 ;
      RECT 0.500 586.600 1563.070 586.888 ;
      RECT 0.500 589.000 1563.070 589.288 ;
      RECT 0.500 591.400 1563.070 591.688 ;
      RECT 0.500 593.800 1563.070 594.088 ;
      RECT 0.500 596.200 1563.070 596.488 ;
      RECT 0.500 598.600 1563.070 598.888 ;
      RECT 0.500 601.000 1563.070 601.288 ;
      RECT 0.500 603.400 1563.070 603.688 ;
      RECT 0.500 605.800 1563.070 606.088 ;
      RECT 0.500 608.200 1563.070 608.488 ;
      RECT 0.500 610.600 1563.070 610.888 ;
      RECT 0.500 613.000 1563.070 613.288 ;
      RECT 0.500 615.400 1563.070 615.688 ;
      RECT 0.500 617.800 1563.070 618.088 ;
      RECT 0.500 620.200 1563.070 620.488 ;
      RECT 0.500 622.600 1563.070 622.888 ;
      RECT 0.500 625.000 1563.070 625.288 ;
      RECT 0.500 627.400 1563.070 627.688 ;
      RECT 0.500 629.800 1563.070 630.088 ;
      RECT 0.500 632.200 1563.070 632.488 ;
      RECT 0.500 634.600 1563.070 634.888 ;
      RECT 0.500 637.000 1563.070 637.288 ;
      RECT 0.500 639.400 1563.070 639.688 ;
      RECT 0.500 641.800 1563.070 642.088 ;
      RECT 0.500 644.200 1563.070 644.488 ;
      RECT 0.500 646.600 1563.070 646.888 ;
      RECT 0.500 649.000 1563.070 649.288 ;
      RECT 0.500 651.400 1563.070 651.688 ;
      RECT 0.500 653.800 1563.070 654.088 ;
      RECT 0.500 656.200 1563.070 656.488 ;
      RECT 0.500 658.600 1563.070 658.888 ;
      RECT 0.500 661.000 1563.070 661.288 ;
      RECT 0.500 663.400 1563.070 663.688 ;
      RECT 0.500 665.800 1563.070 666.088 ;
      RECT 0.500 668.200 1563.070 668.488 ;
      RECT 0.500 670.600 1563.070 670.888 ;
      RECT 0.500 673.000 1563.070 673.288 ;
      RECT 0.500 675.400 1563.070 675.688 ;
      RECT 0.500 677.800 1563.070 678.088 ;
      RECT 0.500 680.200 1563.070 680.488 ;
      RECT 0.500 682.600 1563.070 682.888 ;
      RECT 0.500 685.000 1563.070 685.288 ;
      RECT 0.500 687.400 1563.070 687.688 ;
      RECT 0.500 689.800 1563.070 690.088 ;
      RECT 0.500 692.200 1563.070 692.488 ;
      RECT 0.500 694.600 1563.070 694.888 ;
      RECT 0.500 697.000 1563.070 697.288 ;
      RECT 0.500 699.400 1563.070 699.688 ;
      RECT 0.500 701.800 1563.070 702.088 ;
      RECT 0.500 704.200 1563.070 704.488 ;
      RECT 0.500 706.600 1563.070 706.888 ;
      RECT 0.500 709.000 1563.070 709.288 ;
      RECT 0.500 711.400 1563.070 711.688 ;
      RECT 0.500 713.800 1563.070 714.088 ;
      RECT 0.500 716.200 1563.070 716.488 ;
      RECT 0.500 718.600 1563.070 718.888 ;
      RECT 0.500 721.000 1563.070 721.288 ;
      RECT 0.500 723.400 1563.070 723.688 ;
      RECT 0.500 725.800 1563.070 726.088 ;
      RECT 0.500 728.200 1563.070 728.488 ;
      RECT 0.500 730.600 1563.070 730.888 ;
      RECT 0.500 733.000 1563.070 733.288 ;
      RECT 0.500 735.400 1563.070 735.688 ;
      RECT 0.500 737.800 1563.070 738.088 ;
      RECT 0.500 740.200 1563.070 740.488 ;
      RECT 0.500 742.600 1563.070 742.888 ;
      RECT 0.500 745.000 1563.070 745.288 ;
      RECT 0.500 747.400 1563.070 747.688 ;
      RECT 0.500 749.800 1563.070 750.088 ;
      RECT 0.500 752.200 1563.070 752.488 ;
      RECT 0.500 754.600 1563.070 754.888 ;
      RECT 0.500 757.000 1563.070 757.288 ;
      RECT 0.500 759.400 1563.070 759.688 ;
      RECT 0.500 761.800 1563.070 762.088 ;
      RECT 0.500 764.200 1563.070 764.488 ;
      RECT 0.500 766.600 1563.070 766.888 ;
      RECT 0.500 769.000 1563.070 769.288 ;
      RECT 0.500 771.400 1563.070 771.688 ;
      RECT 0.500 773.800 1563.070 774.088 ;
      RECT 0.500 776.200 1563.070 776.488 ;
      RECT 0.500 778.600 1563.070 778.888 ;
      RECT 0.500 781.000 1563.070 781.288 ;
      RECT 0.500 783.400 1563.070 783.688 ;
      RECT 0.500 785.800 1563.070 786.088 ;
      RECT 0.500 788.200 1563.070 788.488 ;
      RECT 0.500 790.600 1563.070 790.888 ;
      RECT 0.500 793.000 1563.070 793.288 ;
      RECT 0.500 795.400 1563.070 795.688 ;
      RECT 0.500 797.800 1563.070 798.088 ;
      RECT 0.500 800.200 1563.070 800.488 ;
      RECT 0.500 802.600 1563.070 802.888 ;
      RECT 0.500 805.000 1563.070 805.288 ;
      RECT 0.500 807.400 1563.070 807.688 ;
      RECT 0.500 809.800 1563.070 810.088 ;
      RECT 0.500 812.200 1563.070 812.488 ;
      RECT 0.500 814.600 1563.070 814.888 ;
      RECT 0.500 817.000 1563.070 817.288 ;
      RECT 0.500 819.400 1563.070 819.688 ;
      RECT 0.500 821.800 1563.070 822.088 ;
      RECT 0.500 824.200 1563.070 824.488 ;
      RECT 0.500 826.600 1563.070 826.888 ;
      RECT 0.500 829.000 1563.070 829.288 ;
      RECT 0.500 831.400 1563.070 831.688 ;
      RECT 0.500 833.800 1563.070 834.088 ;
      RECT 0.500 836.200 1563.070 836.488 ;
      RECT 0.500 838.600 1563.070 838.888 ;
      RECT 0.500 841.000 1563.070 841.288 ;
      RECT 0.500 843.400 1563.070 843.688 ;
      RECT 0.500 845.800 1563.070 846.088 ;
      RECT 0.500 848.200 1563.070 848.488 ;
      RECT 0.500 850.600 1563.070 850.888 ;
      RECT 0.500 853.000 1563.070 853.288 ;
      RECT 0.500 855.400 1563.070 855.688 ;
      RECT 0.500 857.800 1563.070 858.088 ;
      RECT 0.500 860.200 1563.070 860.488 ;
      RECT 0.500 862.600 1563.070 862.888 ;
      RECT 0.500 865.000 1563.070 865.288 ;
      RECT 0.500 867.400 1563.070 867.688 ;
      RECT 0.500 869.800 1563.070 870.088 ;
      RECT 0.500 872.200 1563.070 872.488 ;
      RECT 0.500 874.600 1563.070 874.888 ;
      RECT 0.500 877.000 1563.070 877.288 ;
      RECT 0.500 879.400 1563.070 879.688 ;
      RECT 0.500 881.800 1563.070 882.088 ;
      RECT 0.500 884.200 1563.070 884.488 ;
      RECT 0.500 886.600 1563.070 886.888 ;
      RECT 0.500 889.000 1563.070 889.288 ;
      RECT 0.500 891.400 1563.070 891.688 ;
      RECT 0.500 893.800 1563.070 894.088 ;
      RECT 0.500 896.200 1563.070 896.488 ;
      RECT 0.500 898.600 1563.070 898.888 ;
      RECT 0.500 901.000 1563.070 901.288 ;
      RECT 0.500 903.400 1563.070 903.688 ;
      RECT 0.500 905.800 1563.070 906.088 ;
      RECT 0.500 908.200 1563.070 908.488 ;
      RECT 0.500 910.600 1563.070 910.888 ;
      RECT 0.500 913.000 1563.070 913.288 ;
      RECT 0.500 915.400 1563.070 915.688 ;
      RECT 0.500 917.800 1563.070 918.088 ;
      RECT 0.500 920.200 1563.070 920.488 ;
      RECT 0.500 922.600 1563.070 922.888 ;
      RECT 0.500 925.000 1563.070 925.288 ;
      RECT 0.500 927.400 1563.070 927.688 ;
      RECT 0.500 929.800 1563.070 930.088 ;
      RECT 0.500 932.200 1563.070 932.488 ;
      RECT 0.500 934.600 1563.070 934.888 ;
      RECT 0.500 937.000 1563.070 937.288 ;
      RECT 0.500 939.400 1563.070 939.688 ;
      RECT 0.500 941.800 1563.070 942.088 ;
      RECT 0.500 944.200 1563.070 944.488 ;
      RECT 0.500 946.600 1563.070 946.888 ;
      RECT 0.500 949.000 1563.070 949.288 ;
      RECT 0.500 951.400 1563.070 951.688 ;
      RECT 0.500 953.800 1563.070 954.088 ;
      RECT 0.500 956.200 1563.070 956.488 ;
      RECT 0.500 958.600 1563.070 958.888 ;
      RECT 0.500 961.000 1563.070 961.288 ;
      RECT 0.500 963.400 1563.070 963.688 ;
      RECT 0.500 965.800 1563.070 966.088 ;
      RECT 0.500 968.200 1563.070 968.488 ;
      RECT 0.500 970.600 1563.070 970.888 ;
      RECT 0.500 973.000 1563.070 973.288 ;
      RECT 0.500 975.400 1563.070 975.688 ;
      RECT 0.500 977.800 1563.070 978.088 ;
      RECT 0.500 980.200 1563.070 980.488 ;
      RECT 0.500 982.600 1563.070 982.888 ;
      RECT 0.500 985.000 1563.070 985.288 ;
      RECT 0.500 987.400 1563.070 987.688 ;
      RECT 0.500 989.800 1563.070 990.088 ;
      RECT 0.500 992.200 1563.070 992.488 ;
      RECT 0.500 994.600 1563.070 994.888 ;
      RECT 0.500 997.000 1563.070 997.288 ;
      RECT 0.500 999.400 1563.070 999.688 ;
      RECT 0.500 1001.800 1563.070 1002.088 ;
      RECT 0.500 1004.200 1563.070 1004.488 ;
      RECT 0.500 1006.600 1563.070 1006.888 ;
      RECT 0.500 1009.000 1563.070 1009.288 ;
      RECT 0.500 1011.400 1563.070 1011.688 ;
      RECT 0.500 1013.800 1563.070 1014.088 ;
      RECT 0.500 1016.200 1563.070 1016.488 ;
      RECT 0.500 1018.600 1563.070 1018.888 ;
      RECT 0.500 1021.000 1563.070 1021.288 ;
      RECT 0.500 1023.400 1563.070 1023.688 ;
      RECT 0.500 1025.800 1563.070 1026.088 ;
      RECT 0.500 1028.200 1563.070 1028.488 ;
      RECT 0.500 1030.600 1563.070 1030.888 ;
      RECT 0.500 1033.000 1563.070 1033.288 ;
      RECT 0.500 1035.400 1563.070 1035.688 ;
      RECT 0.500 1037.800 1563.070 1038.088 ;
      RECT 0.500 1040.200 1563.070 1040.488 ;
      RECT 0.500 1042.600 1563.070 1042.888 ;
      RECT 0.500 1045.000 1563.070 1045.288 ;
      RECT 0.500 1047.400 1563.070 1047.688 ;
      RECT 0.500 1049.800 1563.070 1050.088 ;
      RECT 0.500 1052.200 1563.070 1052.488 ;
      RECT 0.500 1054.600 1563.070 1054.888 ;
      RECT 0.500 1057.000 1563.070 1057.288 ;
      RECT 0.500 1059.400 1563.070 1059.688 ;
      RECT 0.500 1061.800 1563.070 1062.088 ;
      RECT 0.500 1064.200 1563.070 1064.488 ;
      RECT 0.500 1066.600 1563.070 1066.888 ;
      RECT 0.500 1069.000 1563.070 1069.288 ;
      RECT 0.500 1071.400 1563.070 1071.688 ;
      RECT 0.500 1073.800 1563.070 1074.088 ;
      RECT 0.500 1076.200 1563.070 1076.488 ;
      RECT 0.500 1078.600 1563.070 1078.888 ;
      RECT 0.500 1081.000 1563.070 1081.288 ;
      RECT 0.500 1083.400 1563.070 1083.688 ;
      RECT 0.500 1085.800 1563.070 1086.088 ;
      RECT 0.500 1088.200 1563.070 1088.488 ;
      RECT 0.500 1090.600 1563.070 1090.888 ;
      RECT 0.500 1093.000 1563.070 1093.288 ;
      RECT 0.500 1095.400 1563.070 1095.688 ;
      RECT 0.500 1097.800 1563.070 1098.088 ;
      RECT 0.500 1100.200 1563.070 1100.488 ;
      RECT 0.500 1102.600 1563.070 1102.888 ;
      RECT 0.500 1105.000 1563.070 1105.288 ;
      RECT 0.500 1107.400 1563.070 1107.688 ;
      RECT 0.500 1109.800 1563.070 1110.088 ;
      RECT 0.500 1112.200 1563.070 1112.488 ;
      RECT 0.500 1114.600 1563.070 1114.888 ;
      RECT 0.500 1117.000 1563.070 1117.288 ;
      RECT 0.500 1119.400 1563.070 1119.688 ;
      RECT 0.500 1121.800 1563.070 1122.088 ;
      RECT 0.500 1124.200 1563.070 1124.488 ;
      RECT 0.500 1126.600 1563.070 1126.888 ;
      RECT 0.500 1129.000 1563.070 1129.288 ;
      RECT 0.500 1131.400 1563.070 1131.688 ;
      RECT 0.500 1133.800 1563.070 1134.088 ;
      RECT 0.500 1136.200 1563.070 1136.488 ;
      RECT 0.500 1138.600 1563.070 1138.888 ;
      RECT 0.500 1141.000 1563.070 1141.288 ;
      RECT 0.500 1143.400 1563.070 1143.688 ;
      RECT 0.500 1145.800 1563.070 1146.088 ;
      RECT 0.500 1148.200 1563.070 1148.488 ;
      RECT 0.500 1150.600 1563.070 1150.888 ;
      RECT 0.500 1153.000 1563.070 1153.288 ;
      RECT 0.500 1155.400 1563.070 1155.688 ;
      RECT 0.500 1157.800 1563.070 1158.088 ;
      RECT 0.500 1160.200 1563.070 1160.488 ;
      RECT 0.500 1162.600 1563.070 1162.888 ;
      RECT 0.500 1165.000 1563.070 1165.288 ;
      RECT 0.500 1167.400 1563.070 1167.688 ;
      RECT 0.500 1169.800 1563.070 1170.088 ;
      RECT 0.500 1172.200 1563.070 1172.488 ;
      RECT 0.500 1174.600 1563.070 1174.888 ;
      RECT 0.500 1177.000 1563.070 1177.288 ;
      RECT 0.500 1179.400 1563.070 1179.688 ;
      RECT 0.500 1181.800 1563.070 1182.088 ;
      RECT 0.500 1184.200 1563.070 1184.488 ;
      RECT 0.500 1186.600 1563.070 1186.888 ;
      RECT 0.500 1189.000 1563.070 1189.288 ;
      RECT 0.500 1191.400 1563.070 1191.688 ;
      RECT 0.500 1193.800 1563.070 1194.088 ;
      RECT 0.500 1196.200 1563.070 1196.488 ;
      RECT 0.500 1198.600 1563.070 1198.888 ;
      RECT 0.500 1201.000 1563.070 1201.288 ;
      RECT 0.500 1203.400 1563.070 1203.688 ;
      RECT 0.500 1205.800 1563.070 1206.088 ;
      RECT 0.500 1208.200 1563.070 1208.488 ;
      RECT 0.500 1210.600 1563.070 1210.888 ;
      RECT 0.500 1213.000 1563.070 1213.288 ;
      RECT 0.500 1215.400 1563.070 1215.688 ;
      RECT 0.500 1217.800 1563.070 1218.088 ;
      RECT 0.500 1220.200 1563.070 1220.488 ;
      RECT 0.500 1222.600 1563.070 1222.888 ;
      RECT 0.500 1225.000 1563.070 1225.288 ;
      RECT 0.500 1227.400 1563.070 1227.688 ;
      RECT 0.500 1229.800 1563.070 1230.088 ;
      RECT 0.500 1232.200 1563.070 1232.488 ;
      RECT 0.500 1234.600 1563.070 1234.888 ;
      RECT 0.500 1237.000 1563.070 1237.288 ;
      RECT 0.500 1239.400 1563.070 1239.688 ;
      RECT 0.500 1241.800 1563.070 1242.088 ;
      RECT 0.500 1244.200 1563.070 1244.488 ;
      RECT 0.500 1246.600 1563.070 1246.888 ;
      RECT 0.500 1249.000 1563.070 1249.288 ;
      RECT 0.500 1251.400 1563.070 1251.688 ;
      RECT 0.500 1253.800 1563.070 1254.088 ;
      RECT 0.500 1256.200 1563.070 1256.488 ;
      RECT 0.500 1258.600 1563.070 1258.888 ;
      RECT 0.500 1261.000 1563.070 1261.288 ;
      RECT 0.500 1263.400 1563.070 1263.688 ;
      RECT 0.500 1265.800 1563.070 1266.088 ;
      RECT 0.500 1268.200 1563.070 1268.488 ;
      RECT 0.500 1270.600 1563.070 1270.888 ;
      RECT 0.500 1273.000 1563.070 1273.288 ;
      RECT 0.500 1275.400 1563.070 1275.688 ;
      RECT 0.500 1277.800 1563.070 1278.088 ;
      RECT 0.500 1280.200 1563.070 1280.488 ;
      RECT 0.500 1282.600 1563.070 1282.888 ;
      RECT 0.500 1285.000 1563.070 1285.288 ;
      RECT 0.500 1287.400 1563.070 1287.688 ;
      RECT 0.500 1289.800 1563.070 1290.088 ;
      RECT 0.500 1292.200 1563.070 1292.488 ;
      RECT 0.500 1294.600 1563.070 1294.888 ;
      RECT 0.500 1297.000 1563.070 1297.288 ;
      RECT 0.500 1299.400 1563.070 1299.688 ;
      RECT 0.500 1301.800 1563.070 1302.088 ;
      RECT 0.500 1304.200 1563.070 1304.488 ;
      RECT 0.500 1306.600 1563.070 1306.888 ;
      RECT 0.500 1309.000 1563.070 1309.288 ;
      RECT 0.500 1311.400 1563.070 1311.688 ;
      RECT 0.500 1313.800 1563.070 1314.088 ;
      RECT 0.500 1316.200 1563.070 1316.488 ;
      RECT 0.500 1318.600 1563.070 1318.888 ;
      RECT 0.500 1321.000 1563.070 1321.288 ;
      RECT 0.500 1323.400 1563.070 1323.688 ;
      RECT 0.500 1325.800 1563.070 1326.088 ;
      RECT 0.500 1328.200 1563.070 1328.488 ;
      RECT 0.500 1330.600 1563.070 1330.888 ;
      RECT 0.500 1333.000 1563.070 1333.288 ;
      RECT 0.500 1335.400 1563.070 1335.688 ;
      RECT 0.500 1337.800 1563.070 1338.088 ;
      RECT 0.500 1340.200 1563.070 1340.488 ;
      RECT 0.500 1342.600 1563.070 1342.888 ;
      RECT 0.500 1345.000 1563.070 1345.288 ;
      RECT 0.500 1347.400 1563.070 1347.688 ;
      RECT 0.500 1349.800 1563.070 1350.088 ;
      RECT 0.500 1352.200 1563.070 1352.488 ;
      RECT 0.500 1354.600 1563.070 1354.888 ;
      RECT 0.500 1357.000 1563.070 1357.288 ;
      RECT 0.500 1359.400 1563.070 1359.688 ;
      RECT 0.500 1361.800 1563.070 1362.088 ;
      RECT 0.500 1364.200 1563.070 1364.488 ;
      RECT 0.500 1366.600 1563.070 1366.888 ;
      RECT 0.500 1369.000 1563.070 1369.288 ;
      RECT 0.500 1371.400 1563.070 1371.688 ;
      RECT 0.500 1373.800 1563.070 1374.088 ;
      RECT 0.500 1376.200 1563.070 1376.488 ;
      RECT 0.500 1378.600 1563.070 1378.888 ;
      RECT 0.500 1381.000 1563.070 1381.288 ;
      RECT 0.500 1383.400 1563.070 1383.688 ;
      RECT 0.500 1385.800 1563.070 1386.088 ;
      RECT 0.500 1388.200 1563.070 1388.488 ;
      RECT 0.500 1390.600 1563.070 1390.888 ;
      RECT 0.500 1393.000 1563.070 1393.288 ;
      RECT 0.500 1395.400 1563.070 1395.688 ;
      RECT 0.500 1397.800 1563.070 1398.088 ;
      RECT 0.500 1400.200 1563.070 1400.488 ;
      RECT 0.500 1402.600 1563.070 1402.888 ;
      RECT 0.500 1405.000 1563.070 1405.288 ;
      RECT 0.500 1407.400 1563.070 1407.688 ;
      RECT 0.500 1409.800 1563.070 1410.088 ;
      RECT 0.500 1412.200 1563.070 1412.488 ;
      RECT 0.500 1414.600 1563.070 1414.888 ;
      RECT 0.500 1417.000 1563.070 1417.288 ;
      RECT 0.500 1419.400 1563.070 1419.688 ;
      RECT 0.500 1421.800 1563.070 1422.088 ;
      RECT 0.500 1424.200 1563.070 1424.488 ;
      RECT 0.500 1426.600 1563.070 1426.888 ;
      RECT 0.500 1429.000 1563.070 1429.288 ;
      RECT 0.500 1431.400 1563.070 1431.688 ;
      RECT 0.500 1433.800 1563.070 1434.088 ;
      RECT 0.500 1436.200 1563.070 1436.488 ;
      RECT 0.500 1438.600 1563.070 1438.888 ;
      RECT 0.500 1441.000 1563.070 1441.288 ;
      RECT 0.500 1443.400 1563.070 1443.688 ;
      RECT 0.500 1445.800 1563.070 1446.088 ;
      RECT 0.500 1448.200 1563.070 1448.488 ;
      RECT 0.500 1450.600 1563.070 1450.888 ;
      RECT 0.500 1453.000 1563.070 1453.288 ;
      RECT 0.500 1455.400 1563.070 1455.688 ;
      RECT 0.500 1457.800 1563.070 1458.088 ;
      RECT 0.500 1460.200 1563.070 1460.488 ;
      RECT 0.500 1462.600 1563.070 1462.888 ;
      RECT 0.500 1465.000 1563.070 1465.288 ;
      RECT 0.500 1467.400 1563.070 1467.688 ;
      RECT 0.500 1469.800 1563.070 1470.088 ;
      RECT 0.500 1472.200 1563.070 1472.488 ;
      RECT 0.500 1474.600 1563.070 1474.888 ;
      RECT 0.500 1477.000 1563.070 1477.288 ;
      RECT 0.500 1479.400 1563.070 1479.688 ;
      RECT 0.500 1481.800 1563.070 1482.088 ;
      RECT 0.500 1484.200 1563.070 1484.488 ;
      RECT 0.500 1486.600 1563.070 1486.888 ;
      RECT 0.500 1489.000 1563.070 1489.288 ;
      RECT 0.500 1491.400 1563.070 1491.688 ;
      RECT 0.500 1493.800 1563.070 1494.088 ;
      RECT 0.500 1496.200 1563.070 1496.488 ;
      RECT 0.500 1498.600 1563.070 1498.888 ;
      RECT 0.500 1501.000 1563.070 1501.288 ;
      RECT 0.500 1503.400 1563.070 1503.688 ;
      RECT 0.500 1505.800 1563.070 1506.088 ;
      RECT 0.500 1508.200 1563.070 1508.488 ;
      RECT 0.500 1510.600 1563.070 1510.888 ;
      RECT 0.500 1513.000 1563.070 1513.288 ;
      RECT 0.500 1515.400 1563.070 1515.688 ;
      RECT 0.500 1517.800 1563.070 1518.088 ;
      RECT 0.500 1520.200 1563.070 1520.488 ;
      RECT 0.500 1522.600 1563.070 1522.888 ;
      RECT 0.500 1525.000 1563.070 1525.288 ;
      RECT 0.500 1527.400 1563.070 1527.688 ;
      RECT 0.500 1529.800 1563.070 1530.088 ;
      RECT 0.500 1532.200 1563.070 1532.488 ;
      RECT 0.500 1534.600 1563.070 1534.888 ;
      RECT 0.500 1537.000 1563.070 1537.288 ;
      RECT 0.500 1539.400 1563.070 1539.688 ;
      RECT 0.500 1541.800 1563.070 1542.088 ;
      RECT 0.500 1544.200 1563.070 1544.488 ;
      RECT 0.500 1546.600 1563.070 1546.888 ;
      RECT 0.500 1549.000 1563.070 1549.288 ;
      RECT 0.500 1551.400 1563.070 1551.688 ;
      RECT 0.500 1553.800 1563.070 1554.088 ;
      RECT 0.500 1556.200 1563.070 1556.488 ;
      RECT 0.500 1558.600 1563.070 1558.888 ;
      RECT 0.500 1561.000 1563.070 1561.288 ;
      RECT 0.500 1563.400 1563.070 1563.688 ;
      RECT 0.500 1565.800 1563.070 1566.088 ;
      RECT 0.500 1568.200 1563.070 1568.488 ;
      RECT 0.500 1570.600 1563.070 1570.888 ;
      RECT 0.500 1573.000 1563.070 1573.288 ;
      RECT 0.500 1575.400 1563.070 1575.688 ;
      RECT 0.500 1577.800 1563.070 1578.088 ;
      RECT 0.500 1580.200 1563.070 1580.488 ;
      RECT 0.500 1582.600 1563.070 1582.888 ;
      RECT 0.500 1585.000 1563.070 1585.288 ;
      RECT 0.500 1587.400 1563.070 1587.688 ;
      RECT 0.500 1589.800 1563.070 1590.088 ;
      RECT 0.500 1592.200 1563.070 1592.488 ;
      RECT 0.500 1594.600 1563.070 1594.888 ;
      RECT 0.500 1597.000 1563.070 1597.288 ;
      RECT 0.500 1599.400 1563.070 1599.688 ;
      RECT 0.500 1601.800 1563.070 1602.088 ;
      RECT 0.500 1604.200 1563.070 1604.488 ;
      RECT 0.500 1606.600 1563.070 1606.888 ;
      RECT 0.500 1609.000 1563.070 1609.288 ;
      RECT 0.500 1611.400 1563.070 1611.688 ;
      RECT 0.500 1613.800 1563.070 1614.088 ;
      RECT 0.500 1616.200 1563.070 1616.488 ;
      RECT 0.500 1618.600 1563.070 1618.888 ;
      RECT 0.500 1621.000 1563.070 1621.288 ;
      RECT 0.500 1623.400 1563.070 1623.688 ;
      RECT 0.500 1625.800 1563.070 1626.088 ;
      RECT 0.500 1628.200 1563.070 1628.488 ;
      RECT 0.500 1630.600 1563.070 1630.888 ;
      RECT 0.500 1633.000 1563.070 1633.288 ;
      RECT 0.500 1635.400 1563.070 1635.688 ;
      RECT 0.500 1637.800 1563.070 1638.088 ;
      RECT 0.500 1640.200 1563.070 1640.488 ;
      RECT 0.500 1642.600 1563.070 1642.888 ;
      RECT 0.500 1645.000 1563.070 1645.288 ;
      RECT 0.500 1647.400 1563.070 1647.688 ;
      RECT 0.500 1649.800 1563.070 1650.088 ;
      RECT 0.500 1652.200 1563.070 1652.488 ;
      RECT 0.500 1654.600 1563.070 1654.888 ;
      RECT 0.500 1657.000 1563.070 1657.288 ;
      RECT 0.500 1659.400 1563.070 1659.688 ;
      RECT 0.500 1661.800 1563.070 1662.088 ;
      RECT 0.500 1664.200 1563.070 1664.488 ;
      RECT 0.500 1666.600 1563.070 1666.888 ;
      RECT 0.500 1669.000 1563.070 1669.288 ;
      RECT 0.500 1671.400 1563.070 1671.688 ;
      RECT 0.500 1673.800 1563.070 1674.088 ;
      RECT 0.500 1676.200 1563.070 1676.488 ;
      RECT 0.500 1678.600 1563.070 1678.888 ;
      RECT 0.500 1681.000 1563.070 1681.288 ;
      RECT 0.500 1683.400 1563.070 1683.688 ;
      RECT 0.500 1685.800 1563.070 1686.088 ;
      RECT 0.500 1688.200 1563.070 1688.488 ;
      RECT 0.500 1690.600 1563.070 1690.888 ;
      RECT 0.500 1693.000 1563.070 1693.288 ;
      RECT 0.500 1695.400 1563.070 1695.688 ;
      RECT 0.500 1697.800 1563.070 1698.088 ;
      RECT 0.500 1700.200 1563.070 1700.488 ;
      RECT 0.500 1702.600 1563.070 1702.888 ;
      RECT 0.500 1705.000 1563.070 1705.288 ;
      RECT 0.500 1707.400 1563.070 1707.688 ;
      RECT 0.500 1709.800 1563.070 1710.088 ;
      RECT 0.500 1712.200 1563.070 1712.488 ;
      RECT 0.500 1714.600 1563.070 1714.888 ;
      RECT 0.500 1717.000 1563.070 1717.288 ;
      RECT 0.500 1719.400 1563.070 1719.688 ;
      RECT 0.500 1721.800 1563.070 1722.088 ;
      RECT 0.500 1724.200 1563.070 1724.488 ;
      RECT 0.500 1726.600 1563.070 1726.888 ;
      RECT 0.500 1729.000 1563.070 1729.288 ;
      RECT 0.500 1731.400 1563.070 1731.688 ;
      RECT 0.500 1733.800 1563.070 1734.088 ;
      RECT 0.500 1736.200 1563.070 1736.488 ;
      RECT 0.500 1738.600 1563.070 1738.888 ;
      RECT 0.500 1741.000 1563.070 1741.288 ;
      RECT 0.500 1743.400 1563.070 1743.688 ;
      RECT 0.500 1745.800 1563.070 1746.088 ;
      RECT 0.500 1748.200 1563.070 1748.488 ;
      RECT 0.500 1750.600 1563.070 1750.888 ;
      RECT 0.500 1753.000 1563.070 1753.288 ;
      RECT 0.500 1755.400 1563.070 1755.688 ;
      RECT 0.500 1757.800 1563.070 1758.088 ;
      RECT 0.500 1760.200 1563.070 1760.488 ;
      RECT 0.500 1762.600 1563.070 1762.888 ;
      RECT 0.500 1765.000 1563.070 1765.288 ;
      RECT 0.500 1767.400 1563.070 1767.688 ;
      RECT 0.500 1769.800 1563.070 1770.088 ;
      RECT 0.500 1772.200 1563.070 1772.488 ;
      RECT 0.500 1774.600 1563.070 1774.888 ;
      RECT 0.500 1777.000 1563.070 1777.288 ;
      RECT 0.500 1779.400 1563.070 1779.688 ;
      RECT 0.500 1781.800 1563.070 1782.088 ;
      RECT 0.500 1784.200 1563.070 1784.488 ;
      RECT 0.500 1786.600 1563.070 1786.888 ;
      RECT 0.500 1789.000 1563.070 1789.288 ;
      RECT 0.500 1791.400 1563.070 1791.688 ;
      RECT 0.500 1793.800 1563.070 1794.088 ;
      RECT 0.500 1796.200 1563.070 1796.488 ;
      RECT 0.500 1798.600 1563.070 1798.888 ;
      RECT 0.500 1801.000 1563.070 1801.288 ;
      RECT 0.500 1803.400 1563.070 1803.688 ;
      RECT 0.500 1805.800 1563.070 1806.088 ;
      RECT 0.500 1808.200 1563.070 1808.488 ;
      RECT 0.500 1810.600 1563.070 1810.888 ;
      RECT 0.500 1813.000 1563.070 1813.288 ;
      RECT 0.500 1815.400 1563.070 1815.688 ;
      RECT 0.500 1817.800 1563.070 1818.088 ;
      RECT 0.500 1820.200 1563.070 1820.488 ;
      RECT 0.500 1822.600 1563.070 1822.888 ;
      RECT 0.500 1825.000 1563.070 1825.288 ;
      RECT 0.500 1827.400 1563.070 1827.688 ;
      RECT 0.500 1829.800 1563.070 1830.088 ;
      RECT 0.500 1832.200 1563.070 1832.488 ;
      RECT 0.500 1834.600 1563.070 1834.888 ;
      RECT 0.500 1837.000 1563.070 1837.288 ;
      RECT 0.500 1839.400 1563.070 1839.688 ;
      RECT 0.500 1841.800 1563.070 1842.088 ;
      RECT 0.500 1844.200 1563.070 1844.488 ;
      RECT 0.500 1846.600 1563.070 1846.888 ;
      RECT 0.500 1849.000 1563.070 1849.288 ;
      RECT 0.500 1851.400 1563.070 1851.688 ;
      RECT 0.500 1853.800 1563.070 1854.088 ;
      RECT 0.500 1856.200 1563.070 1856.488 ;
      RECT 0.500 1858.600 1563.070 1858.888 ;
      RECT 0.500 1861.000 1563.070 1861.288 ;
      RECT 0.500 1863.400 1563.070 1863.688 ;
      RECT 0.500 1865.800 1563.070 1866.088 ;
      RECT 0.500 1868.200 1563.070 1868.488 ;
      RECT 0.500 1870.600 1563.070 1870.888 ;
      RECT 0.500 1873.000 1563.070 1873.288 ;
      RECT 0.500 1875.400 1563.070 1875.688 ;
      RECT 0.500 1877.800 1563.070 1878.088 ;
      RECT 0.500 1880.200 1563.070 1880.488 ;
      RECT 0.500 1882.600 1563.070 1882.888 ;
      RECT 0.500 1885.000 1563.070 1885.288 ;
      RECT 0.500 1887.400 1563.070 1887.688 ;
      RECT 0.500 1889.800 1563.070 1890.088 ;
      RECT 0.500 1892.200 1563.070 1892.488 ;
      RECT 0.500 1894.600 1563.070 1894.888 ;
      RECT 0.500 1897.000 1563.070 1897.288 ;
      RECT 0.500 1899.400 1563.070 1899.688 ;
      RECT 0.500 1901.800 1563.070 1902.088 ;
      RECT 0.500 1904.200 1563.070 1904.488 ;
      RECT 0.500 1906.600 1563.070 1906.888 ;
      RECT 0.500 1909.000 1563.070 1909.288 ;
      RECT 0.500 1911.400 1563.070 1911.688 ;
      RECT 0.500 1913.800 1563.070 1914.088 ;
      RECT 0.500 1916.200 1563.070 1916.488 ;
      RECT 0.500 1918.600 1563.070 1918.888 ;
      RECT 0.500 1921.000 1563.070 1921.288 ;
      RECT 0.500 1923.400 1563.070 1923.688 ;
      RECT 0.500 1925.800 1563.070 1926.088 ;
      RECT 0.500 1928.200 1563.070 1928.488 ;
      RECT 0.500 1930.600 1563.070 1930.888 ;
      RECT 0.500 1933.000 1563.070 1933.288 ;
      RECT 0.500 1935.400 1563.070 1935.688 ;
      RECT 0.500 1937.800 1563.070 1938.088 ;
      RECT 0.500 1940.200 1563.070 1940.488 ;
      RECT 0.500 1942.600 1563.070 1942.888 ;
      RECT 0.500 1945.000 1563.070 1945.288 ;
      RECT 0.500 1947.400 1563.070 1947.688 ;
      RECT 0.500 1949.800 1563.070 1950.088 ;
      RECT 0.500 1952.200 1563.070 1952.488 ;
      RECT 0.500 1954.600 1563.070 1954.888 ;
      RECT 0.500 1957.000 1563.070 1957.288 ;
      RECT 0.500 1959.400 1563.070 1959.688 ;
      RECT 0.500 1961.800 1563.070 1962.088 ;
      RECT 0.500 1964.200 1563.070 1964.488 ;
      RECT 0.500 1966.600 1563.070 1966.888 ;
      RECT 0.500 1969.000 1563.070 1969.288 ;
      RECT 0.500 1971.400 1563.070 1971.688 ;
      RECT 0.500 1973.800 1563.070 1974.088 ;
      RECT 0.500 1976.200 1563.070 1976.488 ;
      RECT 0.500 1978.600 1563.070 1978.888 ;
      RECT 0.500 1981.000 1563.070 1981.288 ;
      RECT 0.500 1983.400 1563.070 1983.688 ;
      RECT 0.500 1985.800 1563.070 1986.088 ;
      RECT 0.500 1988.200 1563.070 1988.488 ;
      RECT 0.500 1990.600 1563.070 1990.888 ;
      RECT 0.500 1993.000 1563.070 1993.288 ;
      RECT 0.500 1995.400 1563.070 1995.688 ;
      RECT 0.500 1997.800 1563.070 1998.088 ;
      RECT 0.500 2000.200 1563.070 2000.488 ;
      RECT 0.500 2002.600 1563.070 2002.888 ;
      RECT 0.500 2005.000 1563.070 2005.288 ;
      RECT 0.500 2007.400 1563.070 2007.688 ;
      RECT 0.500 2009.800 1563.070 2010.088 ;
      RECT 0.500 2012.200 1563.070 2012.488 ;
      RECT 0.500 2014.600 1563.070 2014.888 ;
      RECT 0.500 2017.000 1563.070 2017.288 ;
      RECT 0.500 2019.400 1563.070 2019.688 ;
      RECT 0.500 2021.800 1563.070 2022.088 ;
      RECT 0.500 2024.200 1563.070 2024.488 ;
      RECT 0.500 2026.600 1563.070 2026.888 ;
      RECT 0.500 2029.000 1563.070 2029.288 ;
      RECT 0.500 2031.400 1563.070 2031.688 ;
      RECT 0.500 2033.800 1563.070 2034.088 ;
      RECT 0.500 2036.200 1563.070 2036.488 ;
      RECT 0.500 2038.600 1563.070 2038.888 ;
      RECT 0.500 2041.000 1563.070 2041.288 ;
      RECT 0.500 2043.400 1563.070 2043.688 ;
      RECT 0.500 2045.800 1563.070 2046.088 ;
      RECT 0.500 2048.200 1563.070 2048.488 ;
      RECT 0.500 2050.600 1563.070 2050.888 ;
      RECT 0.500 2053.000 1563.070 2053.288 ;
      RECT 0.500 2055.400 1563.070 2055.688 ;
      RECT 0.500 2057.800 1563.070 2058.088 ;
      RECT 0.500 2060.200 1563.070 2060.488 ;
      RECT 0.500 2062.600 1563.070 2062.888 ;
      RECT 0.500 2065.000 1563.070 2065.288 ;
      RECT 0.500 2067.400 1563.070 2067.688 ;
      RECT 0.500 2069.800 1563.070 2070.088 ;
      RECT 0.500 2072.200 1563.070 2072.488 ;
      RECT 0.500 2074.600 1563.070 2074.888 ;
      RECT 0.500 2077.000 1563.070 2077.288 ;
      RECT 0.500 2079.400 1563.070 2079.688 ;
      RECT 0.500 2081.800 1563.070 2082.088 ;
      RECT 0.500 2084.200 1563.070 2084.488 ;
      RECT 0.500 2086.600 1563.070 2086.888 ;
      RECT 0.500 2089.000 1563.070 2089.288 ;
      RECT 0.500 2091.400 1563.070 2091.688 ;
      RECT 0.500 2093.800 1563.070 2094.088 ;
      RECT 0.500 2096.200 1563.070 2096.488 ;
      RECT 0.500 2098.600 1563.070 2098.888 ;
      RECT 0.500 2101.000 1563.070 2101.288 ;
      RECT 0.500 2103.400 1563.070 2103.688 ;
      RECT 0.500 2105.800 1563.070 2106.088 ;
      RECT 0.500 2108.200 1563.070 2108.488 ;
      RECT 0.500 2110.600 1563.070 2110.888 ;
      RECT 0.500 2113.000 1563.070 2113.288 ;
      RECT 0.500 2115.400 1563.070 2115.688 ;
      RECT 0.500 2117.800 1563.070 2118.088 ;
      RECT 0.500 2120.200 1563.070 2120.488 ;
      RECT 0.500 2122.600 1563.070 2122.888 ;
      RECT 0.500 2125.000 1563.070 2125.288 ;
      RECT 0.500 2127.400 1563.070 2127.688 ;
      RECT 0.500 2129.800 1563.070 2130.088 ;
      RECT 0.500 2132.200 1563.070 2132.488 ;
      RECT 0.500 2134.600 1563.070 2134.888 ;
      RECT 0.500 2137.000 1563.070 2137.288 ;
      RECT 0.500 2139.400 1563.070 2139.688 ;
      RECT 0.500 2141.800 1563.070 2142.088 ;
      RECT 0.500 2144.200 1563.070 2144.488 ;
      RECT 0.500 2146.600 1563.070 2146.888 ;
      RECT 0.500 2149.000 1563.070 2149.288 ;
      RECT 0.500 2151.400 1563.070 2151.688 ;
      RECT 0.500 2153.800 1563.070 2154.088 ;
      RECT 0.500 2156.200 1563.070 2156.488 ;
      RECT 0.500 2158.600 1563.070 2158.888 ;
      RECT 0.500 2161.000 1563.070 2161.288 ;
      RECT 0.500 2163.400 1563.070 2163.688 ;
      RECT 0.500 2165.800 1563.070 2166.088 ;
      RECT 0.500 2168.200 1563.070 2168.488 ;
      RECT 0.500 2170.600 1563.070 2170.888 ;
      RECT 0.500 2173.000 1563.070 2173.288 ;
      RECT 0.500 2175.400 1563.070 2175.688 ;
      RECT 0.500 2177.800 1563.070 2178.088 ;
      RECT 0.500 2180.200 1563.070 2180.488 ;
      RECT 0.500 2182.600 1563.070 2182.888 ;
      RECT 0.500 2185.000 1563.070 2185.288 ;
      RECT 0.500 2187.400 1563.070 2187.688 ;
      RECT 0.500 2189.800 1563.070 2190.088 ;
      RECT 0.500 2192.200 1563.070 2192.488 ;
      RECT 0.500 2194.600 1563.070 2194.888 ;
      RECT 0.500 2197.000 1563.070 2197.288 ;
      RECT 0.500 2199.400 1563.070 2199.688 ;
      RECT 0.500 2201.800 1563.070 2202.088 ;
      RECT 0.500 2204.200 1563.070 2204.488 ;
      RECT 0.500 2206.600 1563.070 2206.888 ;
      RECT 0.500 2209.000 1563.070 2209.288 ;
      RECT 0.500 2211.400 1563.070 2211.688 ;
      RECT 0.500 2213.800 1563.070 2214.088 ;
      RECT 0.500 2216.200 1563.070 2216.488 ;
      RECT 0.500 2218.600 1563.070 2218.888 ;
      RECT 0.500 2221.000 1563.070 2221.288 ;
      RECT 0.500 2223.400 1563.070 2223.688 ;
      RECT 0.500 2225.800 1563.070 2226.088 ;
      RECT 0.500 2228.200 1563.070 2228.488 ;
      RECT 0.500 2230.600 1563.070 2230.888 ;
      RECT 0.500 2233.000 1563.070 2233.288 ;
      RECT 0.500 2235.400 1563.070 2235.688 ;
      RECT 0.500 2237.800 1563.070 2238.088 ;
      RECT 0.500 2240.200 1563.070 2240.488 ;
      RECT 0.500 2242.600 1563.070 2242.888 ;
      RECT 0.500 2245.000 1563.070 2245.288 ;
      RECT 0.500 2247.400 1563.070 2247.688 ;
      RECT 0.500 2249.800 1563.070 2250.088 ;
      RECT 0.500 2252.200 1563.070 2252.488 ;
      RECT 0.500 2254.600 1563.070 2254.888 ;
      RECT 0.500 2257.000 1563.070 2257.288 ;
      RECT 0.500 2259.400 1563.070 2259.688 ;
      RECT 0.500 2261.800 1563.070 2262.088 ;
      RECT 0.500 2264.200 1563.070 2264.488 ;
      RECT 0.500 2266.600 1563.070 2266.888 ;
      RECT 0.500 2269.000 1563.070 2269.288 ;
      RECT 0.500 2271.400 1563.070 2271.688 ;
      RECT 0.500 2273.800 1563.070 2274.088 ;
      RECT 0.500 2276.200 1563.070 2276.488 ;
      RECT 0.500 2278.600 1563.070 2278.888 ;
      RECT 0.500 2281.000 1563.070 2281.288 ;
      RECT 0.500 2283.400 1563.070 2283.688 ;
      RECT 0.500 2285.800 1563.070 2286.088 ;
      RECT 0.500 2288.200 1563.070 2288.488 ;
      RECT 0.500 2290.600 1563.070 2290.888 ;
      RECT 0.500 2293.000 1563.070 2293.288 ;
      RECT 0.500 2295.400 1563.070 2295.688 ;
      RECT 0.500 2297.800 1563.070 2298.088 ;
      RECT 0.500 2300.200 1563.070 2300.488 ;
      RECT 0.500 2302.600 1563.070 2302.888 ;
      RECT 0.500 2305.000 1563.070 2305.288 ;
      RECT 0.500 2307.400 1563.070 2307.688 ;
      RECT 0.500 2309.800 1563.070 2310.088 ;
      RECT 0.500 2312.200 1563.070 2312.488 ;
      RECT 0.500 2314.600 1563.070 2314.888 ;
      RECT 0.500 2317.000 1563.070 2317.288 ;
    END
  END VDD
  PIN VSS
    DIRECTION INOUT ;
    USE GROUND ;
    PORT
      LAYER M4 ;
      RECT 0.500 2.200 1563.070 2.488 ;
      RECT 0.500 4.600 1563.070 4.888 ;
      RECT 0.500 7.000 1563.070 7.288 ;
      RECT 0.500 9.400 1563.070 9.688 ;
      RECT 0.500 11.800 1563.070 12.088 ;
      RECT 0.500 14.200 1563.070 14.488 ;
      RECT 0.500 16.600 1563.070 16.888 ;
      RECT 0.500 19.000 1563.070 19.288 ;
      RECT 0.500 21.400 1563.070 21.688 ;
      RECT 0.500 23.800 1563.070 24.088 ;
      RECT 0.500 26.200 1563.070 26.488 ;
      RECT 0.500 28.600 1563.070 28.888 ;
      RECT 0.500 31.000 1563.070 31.288 ;
      RECT 0.500 33.400 1563.070 33.688 ;
      RECT 0.500 35.800 1563.070 36.088 ;
      RECT 0.500 38.200 1563.070 38.488 ;
      RECT 0.500 40.600 1563.070 40.888 ;
      RECT 0.500 43.000 1563.070 43.288 ;
      RECT 0.500 45.400 1563.070 45.688 ;
      RECT 0.500 47.800 1563.070 48.088 ;
      RECT 0.500 50.200 1563.070 50.488 ;
      RECT 0.500 52.600 1563.070 52.888 ;
      RECT 0.500 55.000 1563.070 55.288 ;
      RECT 0.500 57.400 1563.070 57.688 ;
      RECT 0.500 59.800 1563.070 60.088 ;
      RECT 0.500 62.200 1563.070 62.488 ;
      RECT 0.500 64.600 1563.070 64.888 ;
      RECT 0.500 67.000 1563.070 67.288 ;
      RECT 0.500 69.400 1563.070 69.688 ;
      RECT 0.500 71.800 1563.070 72.088 ;
      RECT 0.500 74.200 1563.070 74.488 ;
      RECT 0.500 76.600 1563.070 76.888 ;
      RECT 0.500 79.000 1563.070 79.288 ;
      RECT 0.500 81.400 1563.070 81.688 ;
      RECT 0.500 83.800 1563.070 84.088 ;
      RECT 0.500 86.200 1563.070 86.488 ;
      RECT 0.500 88.600 1563.070 88.888 ;
      RECT 0.500 91.000 1563.070 91.288 ;
      RECT 0.500 93.400 1563.070 93.688 ;
      RECT 0.500 95.800 1563.070 96.088 ;
      RECT 0.500 98.200 1563.070 98.488 ;
      RECT 0.500 100.600 1563.070 100.888 ;
      RECT 0.500 103.000 1563.070 103.288 ;
      RECT 0.500 105.400 1563.070 105.688 ;
      RECT 0.500 107.800 1563.070 108.088 ;
      RECT 0.500 110.200 1563.070 110.488 ;
      RECT 0.500 112.600 1563.070 112.888 ;
      RECT 0.500 115.000 1563.070 115.288 ;
      RECT 0.500 117.400 1563.070 117.688 ;
      RECT 0.500 119.800 1563.070 120.088 ;
      RECT 0.500 122.200 1563.070 122.488 ;
      RECT 0.500 124.600 1563.070 124.888 ;
      RECT 0.500 127.000 1563.070 127.288 ;
      RECT 0.500 129.400 1563.070 129.688 ;
      RECT 0.500 131.800 1563.070 132.088 ;
      RECT 0.500 134.200 1563.070 134.488 ;
      RECT 0.500 136.600 1563.070 136.888 ;
      RECT 0.500 139.000 1563.070 139.288 ;
      RECT 0.500 141.400 1563.070 141.688 ;
      RECT 0.500 143.800 1563.070 144.088 ;
      RECT 0.500 146.200 1563.070 146.488 ;
      RECT 0.500 148.600 1563.070 148.888 ;
      RECT 0.500 151.000 1563.070 151.288 ;
      RECT 0.500 153.400 1563.070 153.688 ;
      RECT 0.500 155.800 1563.070 156.088 ;
      RECT 0.500 158.200 1563.070 158.488 ;
      RECT 0.500 160.600 1563.070 160.888 ;
      RECT 0.500 163.000 1563.070 163.288 ;
      RECT 0.500 165.400 1563.070 165.688 ;
      RECT 0.500 167.800 1563.070 168.088 ;
      RECT 0.500 170.200 1563.070 170.488 ;
      RECT 0.500 172.600 1563.070 172.888 ;
      RECT 0.500 175.000 1563.070 175.288 ;
      RECT 0.500 177.400 1563.070 177.688 ;
      RECT 0.500 179.800 1563.070 180.088 ;
      RECT 0.500 182.200 1563.070 182.488 ;
      RECT 0.500 184.600 1563.070 184.888 ;
      RECT 0.500 187.000 1563.070 187.288 ;
      RECT 0.500 189.400 1563.070 189.688 ;
      RECT 0.500 191.800 1563.070 192.088 ;
      RECT 0.500 194.200 1563.070 194.488 ;
      RECT 0.500 196.600 1563.070 196.888 ;
      RECT 0.500 199.000 1563.070 199.288 ;
      RECT 0.500 201.400 1563.070 201.688 ;
      RECT 0.500 203.800 1563.070 204.088 ;
      RECT 0.500 206.200 1563.070 206.488 ;
      RECT 0.500 208.600 1563.070 208.888 ;
      RECT 0.500 211.000 1563.070 211.288 ;
      RECT 0.500 213.400 1563.070 213.688 ;
      RECT 0.500 215.800 1563.070 216.088 ;
      RECT 0.500 218.200 1563.070 218.488 ;
      RECT 0.500 220.600 1563.070 220.888 ;
      RECT 0.500 223.000 1563.070 223.288 ;
      RECT 0.500 225.400 1563.070 225.688 ;
      RECT 0.500 227.800 1563.070 228.088 ;
      RECT 0.500 230.200 1563.070 230.488 ;
      RECT 0.500 232.600 1563.070 232.888 ;
      RECT 0.500 235.000 1563.070 235.288 ;
      RECT 0.500 237.400 1563.070 237.688 ;
      RECT 0.500 239.800 1563.070 240.088 ;
      RECT 0.500 242.200 1563.070 242.488 ;
      RECT 0.500 244.600 1563.070 244.888 ;
      RECT 0.500 247.000 1563.070 247.288 ;
      RECT 0.500 249.400 1563.070 249.688 ;
      RECT 0.500 251.800 1563.070 252.088 ;
      RECT 0.500 254.200 1563.070 254.488 ;
      RECT 0.500 256.600 1563.070 256.888 ;
      RECT 0.500 259.000 1563.070 259.288 ;
      RECT 0.500 261.400 1563.070 261.688 ;
      RECT 0.500 263.800 1563.070 264.088 ;
      RECT 0.500 266.200 1563.070 266.488 ;
      RECT 0.500 268.600 1563.070 268.888 ;
      RECT 0.500 271.000 1563.070 271.288 ;
      RECT 0.500 273.400 1563.070 273.688 ;
      RECT 0.500 275.800 1563.070 276.088 ;
      RECT 0.500 278.200 1563.070 278.488 ;
      RECT 0.500 280.600 1563.070 280.888 ;
      RECT 0.500 283.000 1563.070 283.288 ;
      RECT 0.500 285.400 1563.070 285.688 ;
      RECT 0.500 287.800 1563.070 288.088 ;
      RECT 0.500 290.200 1563.070 290.488 ;
      RECT 0.500 292.600 1563.070 292.888 ;
      RECT 0.500 295.000 1563.070 295.288 ;
      RECT 0.500 297.400 1563.070 297.688 ;
      RECT 0.500 299.800 1563.070 300.088 ;
      RECT 0.500 302.200 1563.070 302.488 ;
      RECT 0.500 304.600 1563.070 304.888 ;
      RECT 0.500 307.000 1563.070 307.288 ;
      RECT 0.500 309.400 1563.070 309.688 ;
      RECT 0.500 311.800 1563.070 312.088 ;
      RECT 0.500 314.200 1563.070 314.488 ;
      RECT 0.500 316.600 1563.070 316.888 ;
      RECT 0.500 319.000 1563.070 319.288 ;
      RECT 0.500 321.400 1563.070 321.688 ;
      RECT 0.500 323.800 1563.070 324.088 ;
      RECT 0.500 326.200 1563.070 326.488 ;
      RECT 0.500 328.600 1563.070 328.888 ;
      RECT 0.500 331.000 1563.070 331.288 ;
      RECT 0.500 333.400 1563.070 333.688 ;
      RECT 0.500 335.800 1563.070 336.088 ;
      RECT 0.500 338.200 1563.070 338.488 ;
      RECT 0.500 340.600 1563.070 340.888 ;
      RECT 0.500 343.000 1563.070 343.288 ;
      RECT 0.500 345.400 1563.070 345.688 ;
      RECT 0.500 347.800 1563.070 348.088 ;
      RECT 0.500 350.200 1563.070 350.488 ;
      RECT 0.500 352.600 1563.070 352.888 ;
      RECT 0.500 355.000 1563.070 355.288 ;
      RECT 0.500 357.400 1563.070 357.688 ;
      RECT 0.500 359.800 1563.070 360.088 ;
      RECT 0.500 362.200 1563.070 362.488 ;
      RECT 0.500 364.600 1563.070 364.888 ;
      RECT 0.500 367.000 1563.070 367.288 ;
      RECT 0.500 369.400 1563.070 369.688 ;
      RECT 0.500 371.800 1563.070 372.088 ;
      RECT 0.500 374.200 1563.070 374.488 ;
      RECT 0.500 376.600 1563.070 376.888 ;
      RECT 0.500 379.000 1563.070 379.288 ;
      RECT 0.500 381.400 1563.070 381.688 ;
      RECT 0.500 383.800 1563.070 384.088 ;
      RECT 0.500 386.200 1563.070 386.488 ;
      RECT 0.500 388.600 1563.070 388.888 ;
      RECT 0.500 391.000 1563.070 391.288 ;
      RECT 0.500 393.400 1563.070 393.688 ;
      RECT 0.500 395.800 1563.070 396.088 ;
      RECT 0.500 398.200 1563.070 398.488 ;
      RECT 0.500 400.600 1563.070 400.888 ;
      RECT 0.500 403.000 1563.070 403.288 ;
      RECT 0.500 405.400 1563.070 405.688 ;
      RECT 0.500 407.800 1563.070 408.088 ;
      RECT 0.500 410.200 1563.070 410.488 ;
      RECT 0.500 412.600 1563.070 412.888 ;
      RECT 0.500 415.000 1563.070 415.288 ;
      RECT 0.500 417.400 1563.070 417.688 ;
      RECT 0.500 419.800 1563.070 420.088 ;
      RECT 0.500 422.200 1563.070 422.488 ;
      RECT 0.500 424.600 1563.070 424.888 ;
      RECT 0.500 427.000 1563.070 427.288 ;
      RECT 0.500 429.400 1563.070 429.688 ;
      RECT 0.500 431.800 1563.070 432.088 ;
      RECT 0.500 434.200 1563.070 434.488 ;
      RECT 0.500 436.600 1563.070 436.888 ;
      RECT 0.500 439.000 1563.070 439.288 ;
      RECT 0.500 441.400 1563.070 441.688 ;
      RECT 0.500 443.800 1563.070 444.088 ;
      RECT 0.500 446.200 1563.070 446.488 ;
      RECT 0.500 448.600 1563.070 448.888 ;
      RECT 0.500 451.000 1563.070 451.288 ;
      RECT 0.500 453.400 1563.070 453.688 ;
      RECT 0.500 455.800 1563.070 456.088 ;
      RECT 0.500 458.200 1563.070 458.488 ;
      RECT 0.500 460.600 1563.070 460.888 ;
      RECT 0.500 463.000 1563.070 463.288 ;
      RECT 0.500 465.400 1563.070 465.688 ;
      RECT 0.500 467.800 1563.070 468.088 ;
      RECT 0.500 470.200 1563.070 470.488 ;
      RECT 0.500 472.600 1563.070 472.888 ;
      RECT 0.500 475.000 1563.070 475.288 ;
      RECT 0.500 477.400 1563.070 477.688 ;
      RECT 0.500 479.800 1563.070 480.088 ;
      RECT 0.500 482.200 1563.070 482.488 ;
      RECT 0.500 484.600 1563.070 484.888 ;
      RECT 0.500 487.000 1563.070 487.288 ;
      RECT 0.500 489.400 1563.070 489.688 ;
      RECT 0.500 491.800 1563.070 492.088 ;
      RECT 0.500 494.200 1563.070 494.488 ;
      RECT 0.500 496.600 1563.070 496.888 ;
      RECT 0.500 499.000 1563.070 499.288 ;
      RECT 0.500 501.400 1563.070 501.688 ;
      RECT 0.500 503.800 1563.070 504.088 ;
      RECT 0.500 506.200 1563.070 506.488 ;
      RECT 0.500 508.600 1563.070 508.888 ;
      RECT 0.500 511.000 1563.070 511.288 ;
      RECT 0.500 513.400 1563.070 513.688 ;
      RECT 0.500 515.800 1563.070 516.088 ;
      RECT 0.500 518.200 1563.070 518.488 ;
      RECT 0.500 520.600 1563.070 520.888 ;
      RECT 0.500 523.000 1563.070 523.288 ;
      RECT 0.500 525.400 1563.070 525.688 ;
      RECT 0.500 527.800 1563.070 528.088 ;
      RECT 0.500 530.200 1563.070 530.488 ;
      RECT 0.500 532.600 1563.070 532.888 ;
      RECT 0.500 535.000 1563.070 535.288 ;
      RECT 0.500 537.400 1563.070 537.688 ;
      RECT 0.500 539.800 1563.070 540.088 ;
      RECT 0.500 542.200 1563.070 542.488 ;
      RECT 0.500 544.600 1563.070 544.888 ;
      RECT 0.500 547.000 1563.070 547.288 ;
      RECT 0.500 549.400 1563.070 549.688 ;
      RECT 0.500 551.800 1563.070 552.088 ;
      RECT 0.500 554.200 1563.070 554.488 ;
      RECT 0.500 556.600 1563.070 556.888 ;
      RECT 0.500 559.000 1563.070 559.288 ;
      RECT 0.500 561.400 1563.070 561.688 ;
      RECT 0.500 563.800 1563.070 564.088 ;
      RECT 0.500 566.200 1563.070 566.488 ;
      RECT 0.500 568.600 1563.070 568.888 ;
      RECT 0.500 571.000 1563.070 571.288 ;
      RECT 0.500 573.400 1563.070 573.688 ;
      RECT 0.500 575.800 1563.070 576.088 ;
      RECT 0.500 578.200 1563.070 578.488 ;
      RECT 0.500 580.600 1563.070 580.888 ;
      RECT 0.500 583.000 1563.070 583.288 ;
      RECT 0.500 585.400 1563.070 585.688 ;
      RECT 0.500 587.800 1563.070 588.088 ;
      RECT 0.500 590.200 1563.070 590.488 ;
      RECT 0.500 592.600 1563.070 592.888 ;
      RECT 0.500 595.000 1563.070 595.288 ;
      RECT 0.500 597.400 1563.070 597.688 ;
      RECT 0.500 599.800 1563.070 600.088 ;
      RECT 0.500 602.200 1563.070 602.488 ;
      RECT 0.500 604.600 1563.070 604.888 ;
      RECT 0.500 607.000 1563.070 607.288 ;
      RECT 0.500 609.400 1563.070 609.688 ;
      RECT 0.500 611.800 1563.070 612.088 ;
      RECT 0.500 614.200 1563.070 614.488 ;
      RECT 0.500 616.600 1563.070 616.888 ;
      RECT 0.500 619.000 1563.070 619.288 ;
      RECT 0.500 621.400 1563.070 621.688 ;
      RECT 0.500 623.800 1563.070 624.088 ;
      RECT 0.500 626.200 1563.070 626.488 ;
      RECT 0.500 628.600 1563.070 628.888 ;
      RECT 0.500 631.000 1563.070 631.288 ;
      RECT 0.500 633.400 1563.070 633.688 ;
      RECT 0.500 635.800 1563.070 636.088 ;
      RECT 0.500 638.200 1563.070 638.488 ;
      RECT 0.500 640.600 1563.070 640.888 ;
      RECT 0.500 643.000 1563.070 643.288 ;
      RECT 0.500 645.400 1563.070 645.688 ;
      RECT 0.500 647.800 1563.070 648.088 ;
      RECT 0.500 650.200 1563.070 650.488 ;
      RECT 0.500 652.600 1563.070 652.888 ;
      RECT 0.500 655.000 1563.070 655.288 ;
      RECT 0.500 657.400 1563.070 657.688 ;
      RECT 0.500 659.800 1563.070 660.088 ;
      RECT 0.500 662.200 1563.070 662.488 ;
      RECT 0.500 664.600 1563.070 664.888 ;
      RECT 0.500 667.000 1563.070 667.288 ;
      RECT 0.500 669.400 1563.070 669.688 ;
      RECT 0.500 671.800 1563.070 672.088 ;
      RECT 0.500 674.200 1563.070 674.488 ;
      RECT 0.500 676.600 1563.070 676.888 ;
      RECT 0.500 679.000 1563.070 679.288 ;
      RECT 0.500 681.400 1563.070 681.688 ;
      RECT 0.500 683.800 1563.070 684.088 ;
      RECT 0.500 686.200 1563.070 686.488 ;
      RECT 0.500 688.600 1563.070 688.888 ;
      RECT 0.500 691.000 1563.070 691.288 ;
      RECT 0.500 693.400 1563.070 693.688 ;
      RECT 0.500 695.800 1563.070 696.088 ;
      RECT 0.500 698.200 1563.070 698.488 ;
      RECT 0.500 700.600 1563.070 700.888 ;
      RECT 0.500 703.000 1563.070 703.288 ;
      RECT 0.500 705.400 1563.070 705.688 ;
      RECT 0.500 707.800 1563.070 708.088 ;
      RECT 0.500 710.200 1563.070 710.488 ;
      RECT 0.500 712.600 1563.070 712.888 ;
      RECT 0.500 715.000 1563.070 715.288 ;
      RECT 0.500 717.400 1563.070 717.688 ;
      RECT 0.500 719.800 1563.070 720.088 ;
      RECT 0.500 722.200 1563.070 722.488 ;
      RECT 0.500 724.600 1563.070 724.888 ;
      RECT 0.500 727.000 1563.070 727.288 ;
      RECT 0.500 729.400 1563.070 729.688 ;
      RECT 0.500 731.800 1563.070 732.088 ;
      RECT 0.500 734.200 1563.070 734.488 ;
      RECT 0.500 736.600 1563.070 736.888 ;
      RECT 0.500 739.000 1563.070 739.288 ;
      RECT 0.500 741.400 1563.070 741.688 ;
      RECT 0.500 743.800 1563.070 744.088 ;
      RECT 0.500 746.200 1563.070 746.488 ;
      RECT 0.500 748.600 1563.070 748.888 ;
      RECT 0.500 751.000 1563.070 751.288 ;
      RECT 0.500 753.400 1563.070 753.688 ;
      RECT 0.500 755.800 1563.070 756.088 ;
      RECT 0.500 758.200 1563.070 758.488 ;
      RECT 0.500 760.600 1563.070 760.888 ;
      RECT 0.500 763.000 1563.070 763.288 ;
      RECT 0.500 765.400 1563.070 765.688 ;
      RECT 0.500 767.800 1563.070 768.088 ;
      RECT 0.500 770.200 1563.070 770.488 ;
      RECT 0.500 772.600 1563.070 772.888 ;
      RECT 0.500 775.000 1563.070 775.288 ;
      RECT 0.500 777.400 1563.070 777.688 ;
      RECT 0.500 779.800 1563.070 780.088 ;
      RECT 0.500 782.200 1563.070 782.488 ;
      RECT 0.500 784.600 1563.070 784.888 ;
      RECT 0.500 787.000 1563.070 787.288 ;
      RECT 0.500 789.400 1563.070 789.688 ;
      RECT 0.500 791.800 1563.070 792.088 ;
      RECT 0.500 794.200 1563.070 794.488 ;
      RECT 0.500 796.600 1563.070 796.888 ;
      RECT 0.500 799.000 1563.070 799.288 ;
      RECT 0.500 801.400 1563.070 801.688 ;
      RECT 0.500 803.800 1563.070 804.088 ;
      RECT 0.500 806.200 1563.070 806.488 ;
      RECT 0.500 808.600 1563.070 808.888 ;
      RECT 0.500 811.000 1563.070 811.288 ;
      RECT 0.500 813.400 1563.070 813.688 ;
      RECT 0.500 815.800 1563.070 816.088 ;
      RECT 0.500 818.200 1563.070 818.488 ;
      RECT 0.500 820.600 1563.070 820.888 ;
      RECT 0.500 823.000 1563.070 823.288 ;
      RECT 0.500 825.400 1563.070 825.688 ;
      RECT 0.500 827.800 1563.070 828.088 ;
      RECT 0.500 830.200 1563.070 830.488 ;
      RECT 0.500 832.600 1563.070 832.888 ;
      RECT 0.500 835.000 1563.070 835.288 ;
      RECT 0.500 837.400 1563.070 837.688 ;
      RECT 0.500 839.800 1563.070 840.088 ;
      RECT 0.500 842.200 1563.070 842.488 ;
      RECT 0.500 844.600 1563.070 844.888 ;
      RECT 0.500 847.000 1563.070 847.288 ;
      RECT 0.500 849.400 1563.070 849.688 ;
      RECT 0.500 851.800 1563.070 852.088 ;
      RECT 0.500 854.200 1563.070 854.488 ;
      RECT 0.500 856.600 1563.070 856.888 ;
      RECT 0.500 859.000 1563.070 859.288 ;
      RECT 0.500 861.400 1563.070 861.688 ;
      RECT 0.500 863.800 1563.070 864.088 ;
      RECT 0.500 866.200 1563.070 866.488 ;
      RECT 0.500 868.600 1563.070 868.888 ;
      RECT 0.500 871.000 1563.070 871.288 ;
      RECT 0.500 873.400 1563.070 873.688 ;
      RECT 0.500 875.800 1563.070 876.088 ;
      RECT 0.500 878.200 1563.070 878.488 ;
      RECT 0.500 880.600 1563.070 880.888 ;
      RECT 0.500 883.000 1563.070 883.288 ;
      RECT 0.500 885.400 1563.070 885.688 ;
      RECT 0.500 887.800 1563.070 888.088 ;
      RECT 0.500 890.200 1563.070 890.488 ;
      RECT 0.500 892.600 1563.070 892.888 ;
      RECT 0.500 895.000 1563.070 895.288 ;
      RECT 0.500 897.400 1563.070 897.688 ;
      RECT 0.500 899.800 1563.070 900.088 ;
      RECT 0.500 902.200 1563.070 902.488 ;
      RECT 0.500 904.600 1563.070 904.888 ;
      RECT 0.500 907.000 1563.070 907.288 ;
      RECT 0.500 909.400 1563.070 909.688 ;
      RECT 0.500 911.800 1563.070 912.088 ;
      RECT 0.500 914.200 1563.070 914.488 ;
      RECT 0.500 916.600 1563.070 916.888 ;
      RECT 0.500 919.000 1563.070 919.288 ;
      RECT 0.500 921.400 1563.070 921.688 ;
      RECT 0.500 923.800 1563.070 924.088 ;
      RECT 0.500 926.200 1563.070 926.488 ;
      RECT 0.500 928.600 1563.070 928.888 ;
      RECT 0.500 931.000 1563.070 931.288 ;
      RECT 0.500 933.400 1563.070 933.688 ;
      RECT 0.500 935.800 1563.070 936.088 ;
      RECT 0.500 938.200 1563.070 938.488 ;
      RECT 0.500 940.600 1563.070 940.888 ;
      RECT 0.500 943.000 1563.070 943.288 ;
      RECT 0.500 945.400 1563.070 945.688 ;
      RECT 0.500 947.800 1563.070 948.088 ;
      RECT 0.500 950.200 1563.070 950.488 ;
      RECT 0.500 952.600 1563.070 952.888 ;
      RECT 0.500 955.000 1563.070 955.288 ;
      RECT 0.500 957.400 1563.070 957.688 ;
      RECT 0.500 959.800 1563.070 960.088 ;
      RECT 0.500 962.200 1563.070 962.488 ;
      RECT 0.500 964.600 1563.070 964.888 ;
      RECT 0.500 967.000 1563.070 967.288 ;
      RECT 0.500 969.400 1563.070 969.688 ;
      RECT 0.500 971.800 1563.070 972.088 ;
      RECT 0.500 974.200 1563.070 974.488 ;
      RECT 0.500 976.600 1563.070 976.888 ;
      RECT 0.500 979.000 1563.070 979.288 ;
      RECT 0.500 981.400 1563.070 981.688 ;
      RECT 0.500 983.800 1563.070 984.088 ;
      RECT 0.500 986.200 1563.070 986.488 ;
      RECT 0.500 988.600 1563.070 988.888 ;
      RECT 0.500 991.000 1563.070 991.288 ;
      RECT 0.500 993.400 1563.070 993.688 ;
      RECT 0.500 995.800 1563.070 996.088 ;
      RECT 0.500 998.200 1563.070 998.488 ;
      RECT 0.500 1000.600 1563.070 1000.888 ;
      RECT 0.500 1003.000 1563.070 1003.288 ;
      RECT 0.500 1005.400 1563.070 1005.688 ;
      RECT 0.500 1007.800 1563.070 1008.088 ;
      RECT 0.500 1010.200 1563.070 1010.488 ;
      RECT 0.500 1012.600 1563.070 1012.888 ;
      RECT 0.500 1015.000 1563.070 1015.288 ;
      RECT 0.500 1017.400 1563.070 1017.688 ;
      RECT 0.500 1019.800 1563.070 1020.088 ;
      RECT 0.500 1022.200 1563.070 1022.488 ;
      RECT 0.500 1024.600 1563.070 1024.888 ;
      RECT 0.500 1027.000 1563.070 1027.288 ;
      RECT 0.500 1029.400 1563.070 1029.688 ;
      RECT 0.500 1031.800 1563.070 1032.088 ;
      RECT 0.500 1034.200 1563.070 1034.488 ;
      RECT 0.500 1036.600 1563.070 1036.888 ;
      RECT 0.500 1039.000 1563.070 1039.288 ;
      RECT 0.500 1041.400 1563.070 1041.688 ;
      RECT 0.500 1043.800 1563.070 1044.088 ;
      RECT 0.500 1046.200 1563.070 1046.488 ;
      RECT 0.500 1048.600 1563.070 1048.888 ;
      RECT 0.500 1051.000 1563.070 1051.288 ;
      RECT 0.500 1053.400 1563.070 1053.688 ;
      RECT 0.500 1055.800 1563.070 1056.088 ;
      RECT 0.500 1058.200 1563.070 1058.488 ;
      RECT 0.500 1060.600 1563.070 1060.888 ;
      RECT 0.500 1063.000 1563.070 1063.288 ;
      RECT 0.500 1065.400 1563.070 1065.688 ;
      RECT 0.500 1067.800 1563.070 1068.088 ;
      RECT 0.500 1070.200 1563.070 1070.488 ;
      RECT 0.500 1072.600 1563.070 1072.888 ;
      RECT 0.500 1075.000 1563.070 1075.288 ;
      RECT 0.500 1077.400 1563.070 1077.688 ;
      RECT 0.500 1079.800 1563.070 1080.088 ;
      RECT 0.500 1082.200 1563.070 1082.488 ;
      RECT 0.500 1084.600 1563.070 1084.888 ;
      RECT 0.500 1087.000 1563.070 1087.288 ;
      RECT 0.500 1089.400 1563.070 1089.688 ;
      RECT 0.500 1091.800 1563.070 1092.088 ;
      RECT 0.500 1094.200 1563.070 1094.488 ;
      RECT 0.500 1096.600 1563.070 1096.888 ;
      RECT 0.500 1099.000 1563.070 1099.288 ;
      RECT 0.500 1101.400 1563.070 1101.688 ;
      RECT 0.500 1103.800 1563.070 1104.088 ;
      RECT 0.500 1106.200 1563.070 1106.488 ;
      RECT 0.500 1108.600 1563.070 1108.888 ;
      RECT 0.500 1111.000 1563.070 1111.288 ;
      RECT 0.500 1113.400 1563.070 1113.688 ;
      RECT 0.500 1115.800 1563.070 1116.088 ;
      RECT 0.500 1118.200 1563.070 1118.488 ;
      RECT 0.500 1120.600 1563.070 1120.888 ;
      RECT 0.500 1123.000 1563.070 1123.288 ;
      RECT 0.500 1125.400 1563.070 1125.688 ;
      RECT 0.500 1127.800 1563.070 1128.088 ;
      RECT 0.500 1130.200 1563.070 1130.488 ;
      RECT 0.500 1132.600 1563.070 1132.888 ;
      RECT 0.500 1135.000 1563.070 1135.288 ;
      RECT 0.500 1137.400 1563.070 1137.688 ;
      RECT 0.500 1139.800 1563.070 1140.088 ;
      RECT 0.500 1142.200 1563.070 1142.488 ;
      RECT 0.500 1144.600 1563.070 1144.888 ;
      RECT 0.500 1147.000 1563.070 1147.288 ;
      RECT 0.500 1149.400 1563.070 1149.688 ;
      RECT 0.500 1151.800 1563.070 1152.088 ;
      RECT 0.500 1154.200 1563.070 1154.488 ;
      RECT 0.500 1156.600 1563.070 1156.888 ;
      RECT 0.500 1159.000 1563.070 1159.288 ;
      RECT 0.500 1161.400 1563.070 1161.688 ;
      RECT 0.500 1163.800 1563.070 1164.088 ;
      RECT 0.500 1166.200 1563.070 1166.488 ;
      RECT 0.500 1168.600 1563.070 1168.888 ;
      RECT 0.500 1171.000 1563.070 1171.288 ;
      RECT 0.500 1173.400 1563.070 1173.688 ;
      RECT 0.500 1175.800 1563.070 1176.088 ;
      RECT 0.500 1178.200 1563.070 1178.488 ;
      RECT 0.500 1180.600 1563.070 1180.888 ;
      RECT 0.500 1183.000 1563.070 1183.288 ;
      RECT 0.500 1185.400 1563.070 1185.688 ;
      RECT 0.500 1187.800 1563.070 1188.088 ;
      RECT 0.500 1190.200 1563.070 1190.488 ;
      RECT 0.500 1192.600 1563.070 1192.888 ;
      RECT 0.500 1195.000 1563.070 1195.288 ;
      RECT 0.500 1197.400 1563.070 1197.688 ;
      RECT 0.500 1199.800 1563.070 1200.088 ;
      RECT 0.500 1202.200 1563.070 1202.488 ;
      RECT 0.500 1204.600 1563.070 1204.888 ;
      RECT 0.500 1207.000 1563.070 1207.288 ;
      RECT 0.500 1209.400 1563.070 1209.688 ;
      RECT 0.500 1211.800 1563.070 1212.088 ;
      RECT 0.500 1214.200 1563.070 1214.488 ;
      RECT 0.500 1216.600 1563.070 1216.888 ;
      RECT 0.500 1219.000 1563.070 1219.288 ;
      RECT 0.500 1221.400 1563.070 1221.688 ;
      RECT 0.500 1223.800 1563.070 1224.088 ;
      RECT 0.500 1226.200 1563.070 1226.488 ;
      RECT 0.500 1228.600 1563.070 1228.888 ;
      RECT 0.500 1231.000 1563.070 1231.288 ;
      RECT 0.500 1233.400 1563.070 1233.688 ;
      RECT 0.500 1235.800 1563.070 1236.088 ;
      RECT 0.500 1238.200 1563.070 1238.488 ;
      RECT 0.500 1240.600 1563.070 1240.888 ;
      RECT 0.500 1243.000 1563.070 1243.288 ;
      RECT 0.500 1245.400 1563.070 1245.688 ;
      RECT 0.500 1247.800 1563.070 1248.088 ;
      RECT 0.500 1250.200 1563.070 1250.488 ;
      RECT 0.500 1252.600 1563.070 1252.888 ;
      RECT 0.500 1255.000 1563.070 1255.288 ;
      RECT 0.500 1257.400 1563.070 1257.688 ;
      RECT 0.500 1259.800 1563.070 1260.088 ;
      RECT 0.500 1262.200 1563.070 1262.488 ;
      RECT 0.500 1264.600 1563.070 1264.888 ;
      RECT 0.500 1267.000 1563.070 1267.288 ;
      RECT 0.500 1269.400 1563.070 1269.688 ;
      RECT 0.500 1271.800 1563.070 1272.088 ;
      RECT 0.500 1274.200 1563.070 1274.488 ;
      RECT 0.500 1276.600 1563.070 1276.888 ;
      RECT 0.500 1279.000 1563.070 1279.288 ;
      RECT 0.500 1281.400 1563.070 1281.688 ;
      RECT 0.500 1283.800 1563.070 1284.088 ;
      RECT 0.500 1286.200 1563.070 1286.488 ;
      RECT 0.500 1288.600 1563.070 1288.888 ;
      RECT 0.500 1291.000 1563.070 1291.288 ;
      RECT 0.500 1293.400 1563.070 1293.688 ;
      RECT 0.500 1295.800 1563.070 1296.088 ;
      RECT 0.500 1298.200 1563.070 1298.488 ;
      RECT 0.500 1300.600 1563.070 1300.888 ;
      RECT 0.500 1303.000 1563.070 1303.288 ;
      RECT 0.500 1305.400 1563.070 1305.688 ;
      RECT 0.500 1307.800 1563.070 1308.088 ;
      RECT 0.500 1310.200 1563.070 1310.488 ;
      RECT 0.500 1312.600 1563.070 1312.888 ;
      RECT 0.500 1315.000 1563.070 1315.288 ;
      RECT 0.500 1317.400 1563.070 1317.688 ;
      RECT 0.500 1319.800 1563.070 1320.088 ;
      RECT 0.500 1322.200 1563.070 1322.488 ;
      RECT 0.500 1324.600 1563.070 1324.888 ;
      RECT 0.500 1327.000 1563.070 1327.288 ;
      RECT 0.500 1329.400 1563.070 1329.688 ;
      RECT 0.500 1331.800 1563.070 1332.088 ;
      RECT 0.500 1334.200 1563.070 1334.488 ;
      RECT 0.500 1336.600 1563.070 1336.888 ;
      RECT 0.500 1339.000 1563.070 1339.288 ;
      RECT 0.500 1341.400 1563.070 1341.688 ;
      RECT 0.500 1343.800 1563.070 1344.088 ;
      RECT 0.500 1346.200 1563.070 1346.488 ;
      RECT 0.500 1348.600 1563.070 1348.888 ;
      RECT 0.500 1351.000 1563.070 1351.288 ;
      RECT 0.500 1353.400 1563.070 1353.688 ;
      RECT 0.500 1355.800 1563.070 1356.088 ;
      RECT 0.500 1358.200 1563.070 1358.488 ;
      RECT 0.500 1360.600 1563.070 1360.888 ;
      RECT 0.500 1363.000 1563.070 1363.288 ;
      RECT 0.500 1365.400 1563.070 1365.688 ;
      RECT 0.500 1367.800 1563.070 1368.088 ;
      RECT 0.500 1370.200 1563.070 1370.488 ;
      RECT 0.500 1372.600 1563.070 1372.888 ;
      RECT 0.500 1375.000 1563.070 1375.288 ;
      RECT 0.500 1377.400 1563.070 1377.688 ;
      RECT 0.500 1379.800 1563.070 1380.088 ;
      RECT 0.500 1382.200 1563.070 1382.488 ;
      RECT 0.500 1384.600 1563.070 1384.888 ;
      RECT 0.500 1387.000 1563.070 1387.288 ;
      RECT 0.500 1389.400 1563.070 1389.688 ;
      RECT 0.500 1391.800 1563.070 1392.088 ;
      RECT 0.500 1394.200 1563.070 1394.488 ;
      RECT 0.500 1396.600 1563.070 1396.888 ;
      RECT 0.500 1399.000 1563.070 1399.288 ;
      RECT 0.500 1401.400 1563.070 1401.688 ;
      RECT 0.500 1403.800 1563.070 1404.088 ;
      RECT 0.500 1406.200 1563.070 1406.488 ;
      RECT 0.500 1408.600 1563.070 1408.888 ;
      RECT 0.500 1411.000 1563.070 1411.288 ;
      RECT 0.500 1413.400 1563.070 1413.688 ;
      RECT 0.500 1415.800 1563.070 1416.088 ;
      RECT 0.500 1418.200 1563.070 1418.488 ;
      RECT 0.500 1420.600 1563.070 1420.888 ;
      RECT 0.500 1423.000 1563.070 1423.288 ;
      RECT 0.500 1425.400 1563.070 1425.688 ;
      RECT 0.500 1427.800 1563.070 1428.088 ;
      RECT 0.500 1430.200 1563.070 1430.488 ;
      RECT 0.500 1432.600 1563.070 1432.888 ;
      RECT 0.500 1435.000 1563.070 1435.288 ;
      RECT 0.500 1437.400 1563.070 1437.688 ;
      RECT 0.500 1439.800 1563.070 1440.088 ;
      RECT 0.500 1442.200 1563.070 1442.488 ;
      RECT 0.500 1444.600 1563.070 1444.888 ;
      RECT 0.500 1447.000 1563.070 1447.288 ;
      RECT 0.500 1449.400 1563.070 1449.688 ;
      RECT 0.500 1451.800 1563.070 1452.088 ;
      RECT 0.500 1454.200 1563.070 1454.488 ;
      RECT 0.500 1456.600 1563.070 1456.888 ;
      RECT 0.500 1459.000 1563.070 1459.288 ;
      RECT 0.500 1461.400 1563.070 1461.688 ;
      RECT 0.500 1463.800 1563.070 1464.088 ;
      RECT 0.500 1466.200 1563.070 1466.488 ;
      RECT 0.500 1468.600 1563.070 1468.888 ;
      RECT 0.500 1471.000 1563.070 1471.288 ;
      RECT 0.500 1473.400 1563.070 1473.688 ;
      RECT 0.500 1475.800 1563.070 1476.088 ;
      RECT 0.500 1478.200 1563.070 1478.488 ;
      RECT 0.500 1480.600 1563.070 1480.888 ;
      RECT 0.500 1483.000 1563.070 1483.288 ;
      RECT 0.500 1485.400 1563.070 1485.688 ;
      RECT 0.500 1487.800 1563.070 1488.088 ;
      RECT 0.500 1490.200 1563.070 1490.488 ;
      RECT 0.500 1492.600 1563.070 1492.888 ;
      RECT 0.500 1495.000 1563.070 1495.288 ;
      RECT 0.500 1497.400 1563.070 1497.688 ;
      RECT 0.500 1499.800 1563.070 1500.088 ;
      RECT 0.500 1502.200 1563.070 1502.488 ;
      RECT 0.500 1504.600 1563.070 1504.888 ;
      RECT 0.500 1507.000 1563.070 1507.288 ;
      RECT 0.500 1509.400 1563.070 1509.688 ;
      RECT 0.500 1511.800 1563.070 1512.088 ;
      RECT 0.500 1514.200 1563.070 1514.488 ;
      RECT 0.500 1516.600 1563.070 1516.888 ;
      RECT 0.500 1519.000 1563.070 1519.288 ;
      RECT 0.500 1521.400 1563.070 1521.688 ;
      RECT 0.500 1523.800 1563.070 1524.088 ;
      RECT 0.500 1526.200 1563.070 1526.488 ;
      RECT 0.500 1528.600 1563.070 1528.888 ;
      RECT 0.500 1531.000 1563.070 1531.288 ;
      RECT 0.500 1533.400 1563.070 1533.688 ;
      RECT 0.500 1535.800 1563.070 1536.088 ;
      RECT 0.500 1538.200 1563.070 1538.488 ;
      RECT 0.500 1540.600 1563.070 1540.888 ;
      RECT 0.500 1543.000 1563.070 1543.288 ;
      RECT 0.500 1545.400 1563.070 1545.688 ;
      RECT 0.500 1547.800 1563.070 1548.088 ;
      RECT 0.500 1550.200 1563.070 1550.488 ;
      RECT 0.500 1552.600 1563.070 1552.888 ;
      RECT 0.500 1555.000 1563.070 1555.288 ;
      RECT 0.500 1557.400 1563.070 1557.688 ;
      RECT 0.500 1559.800 1563.070 1560.088 ;
      RECT 0.500 1562.200 1563.070 1562.488 ;
      RECT 0.500 1564.600 1563.070 1564.888 ;
      RECT 0.500 1567.000 1563.070 1567.288 ;
      RECT 0.500 1569.400 1563.070 1569.688 ;
      RECT 0.500 1571.800 1563.070 1572.088 ;
      RECT 0.500 1574.200 1563.070 1574.488 ;
      RECT 0.500 1576.600 1563.070 1576.888 ;
      RECT 0.500 1579.000 1563.070 1579.288 ;
      RECT 0.500 1581.400 1563.070 1581.688 ;
      RECT 0.500 1583.800 1563.070 1584.088 ;
      RECT 0.500 1586.200 1563.070 1586.488 ;
      RECT 0.500 1588.600 1563.070 1588.888 ;
      RECT 0.500 1591.000 1563.070 1591.288 ;
      RECT 0.500 1593.400 1563.070 1593.688 ;
      RECT 0.500 1595.800 1563.070 1596.088 ;
      RECT 0.500 1598.200 1563.070 1598.488 ;
      RECT 0.500 1600.600 1563.070 1600.888 ;
      RECT 0.500 1603.000 1563.070 1603.288 ;
      RECT 0.500 1605.400 1563.070 1605.688 ;
      RECT 0.500 1607.800 1563.070 1608.088 ;
      RECT 0.500 1610.200 1563.070 1610.488 ;
      RECT 0.500 1612.600 1563.070 1612.888 ;
      RECT 0.500 1615.000 1563.070 1615.288 ;
      RECT 0.500 1617.400 1563.070 1617.688 ;
      RECT 0.500 1619.800 1563.070 1620.088 ;
      RECT 0.500 1622.200 1563.070 1622.488 ;
      RECT 0.500 1624.600 1563.070 1624.888 ;
      RECT 0.500 1627.000 1563.070 1627.288 ;
      RECT 0.500 1629.400 1563.070 1629.688 ;
      RECT 0.500 1631.800 1563.070 1632.088 ;
      RECT 0.500 1634.200 1563.070 1634.488 ;
      RECT 0.500 1636.600 1563.070 1636.888 ;
      RECT 0.500 1639.000 1563.070 1639.288 ;
      RECT 0.500 1641.400 1563.070 1641.688 ;
      RECT 0.500 1643.800 1563.070 1644.088 ;
      RECT 0.500 1646.200 1563.070 1646.488 ;
      RECT 0.500 1648.600 1563.070 1648.888 ;
      RECT 0.500 1651.000 1563.070 1651.288 ;
      RECT 0.500 1653.400 1563.070 1653.688 ;
      RECT 0.500 1655.800 1563.070 1656.088 ;
      RECT 0.500 1658.200 1563.070 1658.488 ;
      RECT 0.500 1660.600 1563.070 1660.888 ;
      RECT 0.500 1663.000 1563.070 1663.288 ;
      RECT 0.500 1665.400 1563.070 1665.688 ;
      RECT 0.500 1667.800 1563.070 1668.088 ;
      RECT 0.500 1670.200 1563.070 1670.488 ;
      RECT 0.500 1672.600 1563.070 1672.888 ;
      RECT 0.500 1675.000 1563.070 1675.288 ;
      RECT 0.500 1677.400 1563.070 1677.688 ;
      RECT 0.500 1679.800 1563.070 1680.088 ;
      RECT 0.500 1682.200 1563.070 1682.488 ;
      RECT 0.500 1684.600 1563.070 1684.888 ;
      RECT 0.500 1687.000 1563.070 1687.288 ;
      RECT 0.500 1689.400 1563.070 1689.688 ;
      RECT 0.500 1691.800 1563.070 1692.088 ;
      RECT 0.500 1694.200 1563.070 1694.488 ;
      RECT 0.500 1696.600 1563.070 1696.888 ;
      RECT 0.500 1699.000 1563.070 1699.288 ;
      RECT 0.500 1701.400 1563.070 1701.688 ;
      RECT 0.500 1703.800 1563.070 1704.088 ;
      RECT 0.500 1706.200 1563.070 1706.488 ;
      RECT 0.500 1708.600 1563.070 1708.888 ;
      RECT 0.500 1711.000 1563.070 1711.288 ;
      RECT 0.500 1713.400 1563.070 1713.688 ;
      RECT 0.500 1715.800 1563.070 1716.088 ;
      RECT 0.500 1718.200 1563.070 1718.488 ;
      RECT 0.500 1720.600 1563.070 1720.888 ;
      RECT 0.500 1723.000 1563.070 1723.288 ;
      RECT 0.500 1725.400 1563.070 1725.688 ;
      RECT 0.500 1727.800 1563.070 1728.088 ;
      RECT 0.500 1730.200 1563.070 1730.488 ;
      RECT 0.500 1732.600 1563.070 1732.888 ;
      RECT 0.500 1735.000 1563.070 1735.288 ;
      RECT 0.500 1737.400 1563.070 1737.688 ;
      RECT 0.500 1739.800 1563.070 1740.088 ;
      RECT 0.500 1742.200 1563.070 1742.488 ;
      RECT 0.500 1744.600 1563.070 1744.888 ;
      RECT 0.500 1747.000 1563.070 1747.288 ;
      RECT 0.500 1749.400 1563.070 1749.688 ;
      RECT 0.500 1751.800 1563.070 1752.088 ;
      RECT 0.500 1754.200 1563.070 1754.488 ;
      RECT 0.500 1756.600 1563.070 1756.888 ;
      RECT 0.500 1759.000 1563.070 1759.288 ;
      RECT 0.500 1761.400 1563.070 1761.688 ;
      RECT 0.500 1763.800 1563.070 1764.088 ;
      RECT 0.500 1766.200 1563.070 1766.488 ;
      RECT 0.500 1768.600 1563.070 1768.888 ;
      RECT 0.500 1771.000 1563.070 1771.288 ;
      RECT 0.500 1773.400 1563.070 1773.688 ;
      RECT 0.500 1775.800 1563.070 1776.088 ;
      RECT 0.500 1778.200 1563.070 1778.488 ;
      RECT 0.500 1780.600 1563.070 1780.888 ;
      RECT 0.500 1783.000 1563.070 1783.288 ;
      RECT 0.500 1785.400 1563.070 1785.688 ;
      RECT 0.500 1787.800 1563.070 1788.088 ;
      RECT 0.500 1790.200 1563.070 1790.488 ;
      RECT 0.500 1792.600 1563.070 1792.888 ;
      RECT 0.500 1795.000 1563.070 1795.288 ;
      RECT 0.500 1797.400 1563.070 1797.688 ;
      RECT 0.500 1799.800 1563.070 1800.088 ;
      RECT 0.500 1802.200 1563.070 1802.488 ;
      RECT 0.500 1804.600 1563.070 1804.888 ;
      RECT 0.500 1807.000 1563.070 1807.288 ;
      RECT 0.500 1809.400 1563.070 1809.688 ;
      RECT 0.500 1811.800 1563.070 1812.088 ;
      RECT 0.500 1814.200 1563.070 1814.488 ;
      RECT 0.500 1816.600 1563.070 1816.888 ;
      RECT 0.500 1819.000 1563.070 1819.288 ;
      RECT 0.500 1821.400 1563.070 1821.688 ;
      RECT 0.500 1823.800 1563.070 1824.088 ;
      RECT 0.500 1826.200 1563.070 1826.488 ;
      RECT 0.500 1828.600 1563.070 1828.888 ;
      RECT 0.500 1831.000 1563.070 1831.288 ;
      RECT 0.500 1833.400 1563.070 1833.688 ;
      RECT 0.500 1835.800 1563.070 1836.088 ;
      RECT 0.500 1838.200 1563.070 1838.488 ;
      RECT 0.500 1840.600 1563.070 1840.888 ;
      RECT 0.500 1843.000 1563.070 1843.288 ;
      RECT 0.500 1845.400 1563.070 1845.688 ;
      RECT 0.500 1847.800 1563.070 1848.088 ;
      RECT 0.500 1850.200 1563.070 1850.488 ;
      RECT 0.500 1852.600 1563.070 1852.888 ;
      RECT 0.500 1855.000 1563.070 1855.288 ;
      RECT 0.500 1857.400 1563.070 1857.688 ;
      RECT 0.500 1859.800 1563.070 1860.088 ;
      RECT 0.500 1862.200 1563.070 1862.488 ;
      RECT 0.500 1864.600 1563.070 1864.888 ;
      RECT 0.500 1867.000 1563.070 1867.288 ;
      RECT 0.500 1869.400 1563.070 1869.688 ;
      RECT 0.500 1871.800 1563.070 1872.088 ;
      RECT 0.500 1874.200 1563.070 1874.488 ;
      RECT 0.500 1876.600 1563.070 1876.888 ;
      RECT 0.500 1879.000 1563.070 1879.288 ;
      RECT 0.500 1881.400 1563.070 1881.688 ;
      RECT 0.500 1883.800 1563.070 1884.088 ;
      RECT 0.500 1886.200 1563.070 1886.488 ;
      RECT 0.500 1888.600 1563.070 1888.888 ;
      RECT 0.500 1891.000 1563.070 1891.288 ;
      RECT 0.500 1893.400 1563.070 1893.688 ;
      RECT 0.500 1895.800 1563.070 1896.088 ;
      RECT 0.500 1898.200 1563.070 1898.488 ;
      RECT 0.500 1900.600 1563.070 1900.888 ;
      RECT 0.500 1903.000 1563.070 1903.288 ;
      RECT 0.500 1905.400 1563.070 1905.688 ;
      RECT 0.500 1907.800 1563.070 1908.088 ;
      RECT 0.500 1910.200 1563.070 1910.488 ;
      RECT 0.500 1912.600 1563.070 1912.888 ;
      RECT 0.500 1915.000 1563.070 1915.288 ;
      RECT 0.500 1917.400 1563.070 1917.688 ;
      RECT 0.500 1919.800 1563.070 1920.088 ;
      RECT 0.500 1922.200 1563.070 1922.488 ;
      RECT 0.500 1924.600 1563.070 1924.888 ;
      RECT 0.500 1927.000 1563.070 1927.288 ;
      RECT 0.500 1929.400 1563.070 1929.688 ;
      RECT 0.500 1931.800 1563.070 1932.088 ;
      RECT 0.500 1934.200 1563.070 1934.488 ;
      RECT 0.500 1936.600 1563.070 1936.888 ;
      RECT 0.500 1939.000 1563.070 1939.288 ;
      RECT 0.500 1941.400 1563.070 1941.688 ;
      RECT 0.500 1943.800 1563.070 1944.088 ;
      RECT 0.500 1946.200 1563.070 1946.488 ;
      RECT 0.500 1948.600 1563.070 1948.888 ;
      RECT 0.500 1951.000 1563.070 1951.288 ;
      RECT 0.500 1953.400 1563.070 1953.688 ;
      RECT 0.500 1955.800 1563.070 1956.088 ;
      RECT 0.500 1958.200 1563.070 1958.488 ;
      RECT 0.500 1960.600 1563.070 1960.888 ;
      RECT 0.500 1963.000 1563.070 1963.288 ;
      RECT 0.500 1965.400 1563.070 1965.688 ;
      RECT 0.500 1967.800 1563.070 1968.088 ;
      RECT 0.500 1970.200 1563.070 1970.488 ;
      RECT 0.500 1972.600 1563.070 1972.888 ;
      RECT 0.500 1975.000 1563.070 1975.288 ;
      RECT 0.500 1977.400 1563.070 1977.688 ;
      RECT 0.500 1979.800 1563.070 1980.088 ;
      RECT 0.500 1982.200 1563.070 1982.488 ;
      RECT 0.500 1984.600 1563.070 1984.888 ;
      RECT 0.500 1987.000 1563.070 1987.288 ;
      RECT 0.500 1989.400 1563.070 1989.688 ;
      RECT 0.500 1991.800 1563.070 1992.088 ;
      RECT 0.500 1994.200 1563.070 1994.488 ;
      RECT 0.500 1996.600 1563.070 1996.888 ;
      RECT 0.500 1999.000 1563.070 1999.288 ;
      RECT 0.500 2001.400 1563.070 2001.688 ;
      RECT 0.500 2003.800 1563.070 2004.088 ;
      RECT 0.500 2006.200 1563.070 2006.488 ;
      RECT 0.500 2008.600 1563.070 2008.888 ;
      RECT 0.500 2011.000 1563.070 2011.288 ;
      RECT 0.500 2013.400 1563.070 2013.688 ;
      RECT 0.500 2015.800 1563.070 2016.088 ;
      RECT 0.500 2018.200 1563.070 2018.488 ;
      RECT 0.500 2020.600 1563.070 2020.888 ;
      RECT 0.500 2023.000 1563.070 2023.288 ;
      RECT 0.500 2025.400 1563.070 2025.688 ;
      RECT 0.500 2027.800 1563.070 2028.088 ;
      RECT 0.500 2030.200 1563.070 2030.488 ;
      RECT 0.500 2032.600 1563.070 2032.888 ;
      RECT 0.500 2035.000 1563.070 2035.288 ;
      RECT 0.500 2037.400 1563.070 2037.688 ;
      RECT 0.500 2039.800 1563.070 2040.088 ;
      RECT 0.500 2042.200 1563.070 2042.488 ;
      RECT 0.500 2044.600 1563.070 2044.888 ;
      RECT 0.500 2047.000 1563.070 2047.288 ;
      RECT 0.500 2049.400 1563.070 2049.688 ;
      RECT 0.500 2051.800 1563.070 2052.088 ;
      RECT 0.500 2054.200 1563.070 2054.488 ;
      RECT 0.500 2056.600 1563.070 2056.888 ;
      RECT 0.500 2059.000 1563.070 2059.288 ;
      RECT 0.500 2061.400 1563.070 2061.688 ;
      RECT 0.500 2063.800 1563.070 2064.088 ;
      RECT 0.500 2066.200 1563.070 2066.488 ;
      RECT 0.500 2068.600 1563.070 2068.888 ;
      RECT 0.500 2071.000 1563.070 2071.288 ;
      RECT 0.500 2073.400 1563.070 2073.688 ;
      RECT 0.500 2075.800 1563.070 2076.088 ;
      RECT 0.500 2078.200 1563.070 2078.488 ;
      RECT 0.500 2080.600 1563.070 2080.888 ;
      RECT 0.500 2083.000 1563.070 2083.288 ;
      RECT 0.500 2085.400 1563.070 2085.688 ;
      RECT 0.500 2087.800 1563.070 2088.088 ;
      RECT 0.500 2090.200 1563.070 2090.488 ;
      RECT 0.500 2092.600 1563.070 2092.888 ;
      RECT 0.500 2095.000 1563.070 2095.288 ;
      RECT 0.500 2097.400 1563.070 2097.688 ;
      RECT 0.500 2099.800 1563.070 2100.088 ;
      RECT 0.500 2102.200 1563.070 2102.488 ;
      RECT 0.500 2104.600 1563.070 2104.888 ;
      RECT 0.500 2107.000 1563.070 2107.288 ;
      RECT 0.500 2109.400 1563.070 2109.688 ;
      RECT 0.500 2111.800 1563.070 2112.088 ;
      RECT 0.500 2114.200 1563.070 2114.488 ;
      RECT 0.500 2116.600 1563.070 2116.888 ;
      RECT 0.500 2119.000 1563.070 2119.288 ;
      RECT 0.500 2121.400 1563.070 2121.688 ;
      RECT 0.500 2123.800 1563.070 2124.088 ;
      RECT 0.500 2126.200 1563.070 2126.488 ;
      RECT 0.500 2128.600 1563.070 2128.888 ;
      RECT 0.500 2131.000 1563.070 2131.288 ;
      RECT 0.500 2133.400 1563.070 2133.688 ;
      RECT 0.500 2135.800 1563.070 2136.088 ;
      RECT 0.500 2138.200 1563.070 2138.488 ;
      RECT 0.500 2140.600 1563.070 2140.888 ;
      RECT 0.500 2143.000 1563.070 2143.288 ;
      RECT 0.500 2145.400 1563.070 2145.688 ;
      RECT 0.500 2147.800 1563.070 2148.088 ;
      RECT 0.500 2150.200 1563.070 2150.488 ;
      RECT 0.500 2152.600 1563.070 2152.888 ;
      RECT 0.500 2155.000 1563.070 2155.288 ;
      RECT 0.500 2157.400 1563.070 2157.688 ;
      RECT 0.500 2159.800 1563.070 2160.088 ;
      RECT 0.500 2162.200 1563.070 2162.488 ;
      RECT 0.500 2164.600 1563.070 2164.888 ;
      RECT 0.500 2167.000 1563.070 2167.288 ;
      RECT 0.500 2169.400 1563.070 2169.688 ;
      RECT 0.500 2171.800 1563.070 2172.088 ;
      RECT 0.500 2174.200 1563.070 2174.488 ;
      RECT 0.500 2176.600 1563.070 2176.888 ;
      RECT 0.500 2179.000 1563.070 2179.288 ;
      RECT 0.500 2181.400 1563.070 2181.688 ;
      RECT 0.500 2183.800 1563.070 2184.088 ;
      RECT 0.500 2186.200 1563.070 2186.488 ;
      RECT 0.500 2188.600 1563.070 2188.888 ;
      RECT 0.500 2191.000 1563.070 2191.288 ;
      RECT 0.500 2193.400 1563.070 2193.688 ;
      RECT 0.500 2195.800 1563.070 2196.088 ;
      RECT 0.500 2198.200 1563.070 2198.488 ;
      RECT 0.500 2200.600 1563.070 2200.888 ;
      RECT 0.500 2203.000 1563.070 2203.288 ;
      RECT 0.500 2205.400 1563.070 2205.688 ;
      RECT 0.500 2207.800 1563.070 2208.088 ;
      RECT 0.500 2210.200 1563.070 2210.488 ;
      RECT 0.500 2212.600 1563.070 2212.888 ;
      RECT 0.500 2215.000 1563.070 2215.288 ;
      RECT 0.500 2217.400 1563.070 2217.688 ;
      RECT 0.500 2219.800 1563.070 2220.088 ;
      RECT 0.500 2222.200 1563.070 2222.488 ;
      RECT 0.500 2224.600 1563.070 2224.888 ;
      RECT 0.500 2227.000 1563.070 2227.288 ;
      RECT 0.500 2229.400 1563.070 2229.688 ;
      RECT 0.500 2231.800 1563.070 2232.088 ;
      RECT 0.500 2234.200 1563.070 2234.488 ;
      RECT 0.500 2236.600 1563.070 2236.888 ;
      RECT 0.500 2239.000 1563.070 2239.288 ;
      RECT 0.500 2241.400 1563.070 2241.688 ;
      RECT 0.500 2243.800 1563.070 2244.088 ;
      RECT 0.500 2246.200 1563.070 2246.488 ;
      RECT 0.500 2248.600 1563.070 2248.888 ;
      RECT 0.500 2251.000 1563.070 2251.288 ;
      RECT 0.500 2253.400 1563.070 2253.688 ;
      RECT 0.500 2255.800 1563.070 2256.088 ;
      RECT 0.500 2258.200 1563.070 2258.488 ;
      RECT 0.500 2260.600 1563.070 2260.888 ;
      RECT 0.500 2263.000 1563.070 2263.288 ;
      RECT 0.500 2265.400 1563.070 2265.688 ;
      RECT 0.500 2267.800 1563.070 2268.088 ;
      RECT 0.500 2270.200 1563.070 2270.488 ;
      RECT 0.500 2272.600 1563.070 2272.888 ;
      RECT 0.500 2275.000 1563.070 2275.288 ;
      RECT 0.500 2277.400 1563.070 2277.688 ;
      RECT 0.500 2279.800 1563.070 2280.088 ;
      RECT 0.500 2282.200 1563.070 2282.488 ;
      RECT 0.500 2284.600 1563.070 2284.888 ;
      RECT 0.500 2287.000 1563.070 2287.288 ;
      RECT 0.500 2289.400 1563.070 2289.688 ;
      RECT 0.500 2291.800 1563.070 2292.088 ;
      RECT 0.500 2294.200 1563.070 2294.488 ;
      RECT 0.500 2296.600 1563.070 2296.888 ;
      RECT 0.500 2299.000 1563.070 2299.288 ;
      RECT 0.500 2301.400 1563.070 2301.688 ;
      RECT 0.500 2303.800 1563.070 2304.088 ;
      RECT 0.500 2306.200 1563.070 2306.488 ;
      RECT 0.500 2308.600 1563.070 2308.888 ;
      RECT 0.500 2311.000 1563.070 2311.288 ;
      RECT 0.500 2313.400 1563.070 2313.688 ;
      RECT 0.500 2315.800 1563.070 2316.088 ;
      RECT 0.500 2318.200 1563.070 2318.488 ;
    END
  END VSS
  OBS
    LAYER M1 ;
    RECT 0 0 1563.570 2320.056 ;
    LAYER M2 ;
    RECT 0 0 1563.570 2320.056 ;
    LAYER M3 ;
    RECT 0 0 1563.570 2320.056 ;
    LAYER M4 ;
    RECT 0 0 1563.570 2320.056 ;
    LAYER M5 ;
    RECT 0 0 1563.570 2319.656 ;
  END
END ot_qfd_serdes_112g_x12_phy_s597

END LIBRARY
